VERSION 5.8 ;
BUSBITCHARS "[]" ;
DIVIDERCHAR "/" ;
UNITS
    DATABASE MICRONS 1000 ;
END UNITS

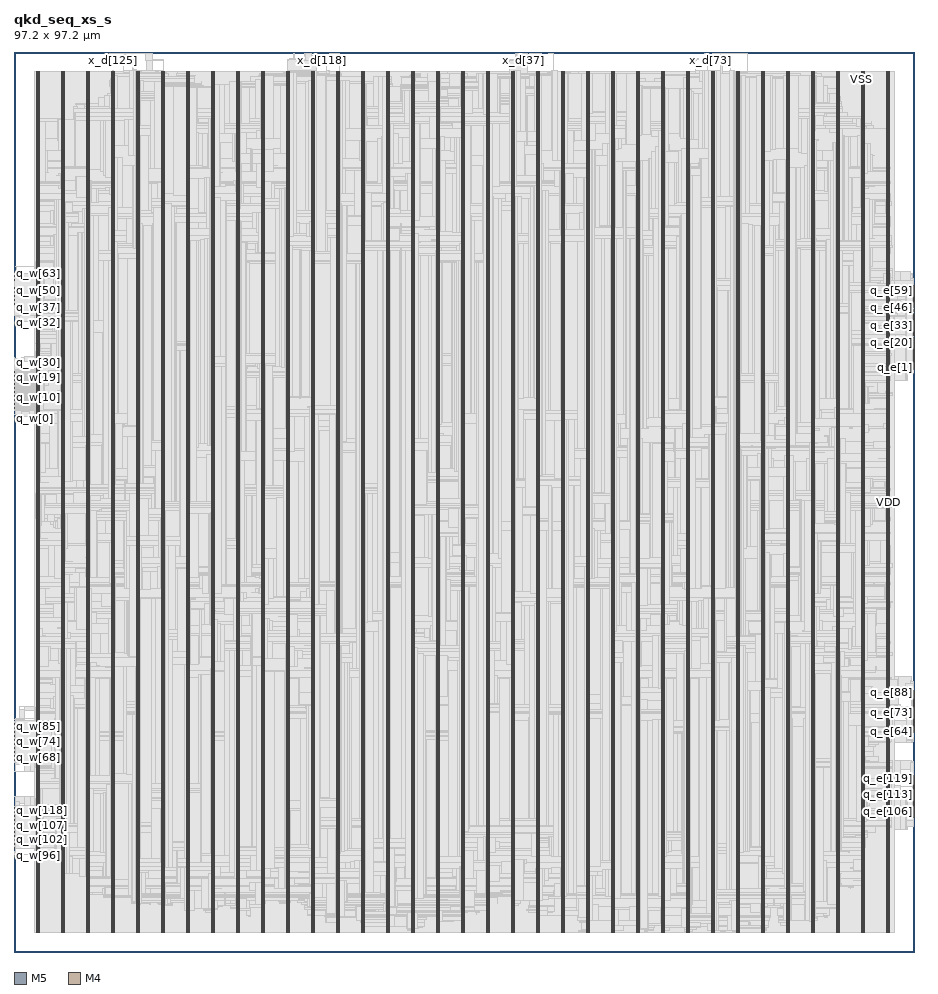
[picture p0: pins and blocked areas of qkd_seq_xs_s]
MACRO qkd_seq_xs_s
  FOREIGN qkd_seq_xs_s 0 0 ;
  CLASS BLOCK ;
  SIZE 97.2 BY 97.2 ;
  PIN ck
    DIRECTION INPUT ;
    USE SIGNAL ;
    PORT
      LAYER M5 ;
        RECT  11.232 97.116 11.256 97.2 ;
    END
  END ck
  PIN q_e[0]
    DIRECTION OUTPUT ;
    USE SIGNAL ;
    PORT
      LAYER M4 ;
        RECT  97.116 62.928 97.2 62.952 ;
    END
  END q_e[0]
  PIN q_e[100]
    DIRECTION OUTPUT ;
    USE SIGNAL ;
    PORT
      LAYER M4 ;
        RECT  97.116 15.12 97.2 15.144 ;
    END
  END q_e[100]
  PIN q_e[101]
    DIRECTION OUTPUT ;
    USE SIGNAL ;
    PORT
      LAYER M4 ;
        RECT  97.116 15.264 97.2 15.288 ;
    END
  END q_e[101]
  PIN q_e[102]
    DIRECTION OUTPUT ;
    USE SIGNAL ;
    PORT
      LAYER M4 ;
        RECT  97.116 15.408 97.2 15.432 ;
    END
  END q_e[102]
  PIN q_e[103]
    DIRECTION OUTPUT ;
    USE SIGNAL ;
    PORT
      LAYER M4 ;
        RECT  97.116 15.552 97.2 15.576 ;
    END
  END q_e[103]
  PIN q_e[104]
    DIRECTION OUTPUT ;
    USE SIGNAL ;
    PORT
      LAYER M4 ;
        RECT  97.116 15.696 97.2 15.72 ;
    END
  END q_e[104]
  PIN q_e[105]
    DIRECTION OUTPUT ;
    USE SIGNAL ;
    PORT
      LAYER M4 ;
        RECT  97.116 15.84 97.2 15.864 ;
    END
  END q_e[105]
  PIN q_e[106]
    DIRECTION OUTPUT ;
    USE SIGNAL ;
    PORT
      LAYER M4 ;
        RECT  97.116 15.984 97.2 16.008 ;
    END
  END q_e[106]
  PIN q_e[107]
    DIRECTION OUTPUT ;
    USE SIGNAL ;
    PORT
      LAYER M4 ;
        RECT  97.116 16.128 97.2 16.152 ;
    END
  END q_e[107]
  PIN q_e[108]
    DIRECTION OUTPUT ;
    USE SIGNAL ;
    PORT
      LAYER M4 ;
        RECT  97.116 16.272 97.2 16.296 ;
    END
  END q_e[108]
  PIN q_e[109]
    DIRECTION OUTPUT ;
    USE SIGNAL ;
    PORT
      LAYER M4 ;
        RECT  97.116 16.416 97.2 16.44 ;
    END
  END q_e[109]
  PIN q_e[10]
    DIRECTION OUTPUT ;
    USE SIGNAL ;
    PORT
      LAYER M4 ;
        RECT  97.116 64.368 97.2 64.392 ;
    END
  END q_e[10]
  PIN q_e[110]
    DIRECTION OUTPUT ;
    USE SIGNAL ;
    PORT
      LAYER M4 ;
        RECT  97.116 16.56 97.2 16.584 ;
    END
  END q_e[110]
  PIN q_e[111]
    DIRECTION OUTPUT ;
    USE SIGNAL ;
    PORT
      LAYER M4 ;
        RECT  97.116 16.704 97.2 16.728 ;
    END
  END q_e[111]
  PIN q_e[112]
    DIRECTION OUTPUT ;
    USE SIGNAL ;
    PORT
      LAYER M4 ;
        RECT  97.116 16.848 97.2 16.872 ;
    END
  END q_e[112]
  PIN q_e[113]
    DIRECTION OUTPUT ;
    USE SIGNAL ;
    PORT
      LAYER M4 ;
        RECT  97.116 16.992 97.2 17.016 ;
    END
  END q_e[113]
  PIN q_e[114]
    DIRECTION OUTPUT ;
    USE SIGNAL ;
    PORT
      LAYER M4 ;
        RECT  97.116 17.136 97.2 17.16 ;
    END
  END q_e[114]
  PIN q_e[115]
    DIRECTION OUTPUT ;
    USE SIGNAL ;
    PORT
      LAYER M4 ;
        RECT  97.116 17.28 97.2 17.304 ;
    END
  END q_e[115]
  PIN q_e[116]
    DIRECTION OUTPUT ;
    USE SIGNAL ;
    PORT
      LAYER M4 ;
        RECT  97.116 17.424 97.2 17.448 ;
    END
  END q_e[116]
  PIN q_e[117]
    DIRECTION OUTPUT ;
    USE SIGNAL ;
    PORT
      LAYER M4 ;
        RECT  97.116 17.568 97.2 17.592 ;
    END
  END q_e[117]
  PIN q_e[118]
    DIRECTION OUTPUT ;
    USE SIGNAL ;
    PORT
      LAYER M4 ;
        RECT  97.116 17.712 97.2 17.736 ;
    END
  END q_e[118]
  PIN q_e[119]
    DIRECTION OUTPUT ;
    USE SIGNAL ;
    PORT
      LAYER M4 ;
        RECT  97.116 17.856 97.2 17.88 ;
    END
  END q_e[119]
  PIN q_e[11]
    DIRECTION OUTPUT ;
    USE SIGNAL ;
    PORT
      LAYER M4 ;
        RECT  97.116 64.512 97.2 64.536 ;
    END
  END q_e[11]
  PIN q_e[120]
    DIRECTION OUTPUT ;
    USE SIGNAL ;
    PORT
      LAYER M4 ;
        RECT  97.116 18 97.2 18.024 ;
    END
  END q_e[120]
  PIN q_e[121]
    DIRECTION OUTPUT ;
    USE SIGNAL ;
    PORT
      LAYER M4 ;
        RECT  97.116 18.144 97.2 18.168 ;
    END
  END q_e[121]
  PIN q_e[122]
    DIRECTION OUTPUT ;
    USE SIGNAL ;
    PORT
      LAYER M4 ;
        RECT  97.116 18.288 97.2 18.312 ;
    END
  END q_e[122]
  PIN q_e[123]
    DIRECTION OUTPUT ;
    USE SIGNAL ;
    PORT
      LAYER M4 ;
        RECT  97.116 18.432 97.2 18.456 ;
    END
  END q_e[123]
  PIN q_e[124]
    DIRECTION OUTPUT ;
    USE SIGNAL ;
    PORT
      LAYER M4 ;
        RECT  97.116 18.576 97.2 18.6 ;
    END
  END q_e[124]
  PIN q_e[125]
    DIRECTION OUTPUT ;
    USE SIGNAL ;
    PORT
      LAYER M4 ;
        RECT  97.116 18.72 97.2 18.744 ;
    END
  END q_e[125]
  PIN q_e[126]
    DIRECTION OUTPUT ;
    USE SIGNAL ;
    PORT
      LAYER M4 ;
        RECT  97.116 18.864 97.2 18.888 ;
    END
  END q_e[126]
  PIN q_e[127]
    DIRECTION OUTPUT ;
    USE SIGNAL ;
    PORT
      LAYER M4 ;
        RECT  97.116 19.008 97.2 19.032 ;
    END
  END q_e[127]
  PIN q_e[12]
    DIRECTION OUTPUT ;
    USE SIGNAL ;
    PORT
      LAYER M4 ;
        RECT  97.116 64.656 97.2 64.68 ;
    END
  END q_e[12]
  PIN q_e[13]
    DIRECTION OUTPUT ;
    USE SIGNAL ;
    PORT
      LAYER M4 ;
        RECT  97.116 64.8 97.2 64.824 ;
    END
  END q_e[13]
  PIN q_e[14]
    DIRECTION OUTPUT ;
    USE SIGNAL ;
    PORT
      LAYER M4 ;
        RECT  97.116 64.944 97.2 64.968 ;
    END
  END q_e[14]
  PIN q_e[15]
    DIRECTION OUTPUT ;
    USE SIGNAL ;
    PORT
      LAYER M4 ;
        RECT  97.116 65.088 97.2 65.112 ;
    END
  END q_e[15]
  PIN q_e[16]
    DIRECTION OUTPUT ;
    USE SIGNAL ;
    PORT
      LAYER M4 ;
        RECT  97.116 65.232 97.2 65.256 ;
    END
  END q_e[16]
  PIN q_e[17]
    DIRECTION OUTPUT ;
    USE SIGNAL ;
    PORT
      LAYER M4 ;
        RECT  97.116 65.376 97.2 65.4 ;
    END
  END q_e[17]
  PIN q_e[18]
    DIRECTION OUTPUT ;
    USE SIGNAL ;
    PORT
      LAYER M4 ;
        RECT  97.116 65.52 97.2 65.544 ;
    END
  END q_e[18]
  PIN q_e[19]
    DIRECTION OUTPUT ;
    USE SIGNAL ;
    PORT
      LAYER M4 ;
        RECT  97.116 65.664 97.2 65.688 ;
    END
  END q_e[19]
  PIN q_e[1]
    DIRECTION OUTPUT ;
    USE SIGNAL ;
    PORT
      LAYER M4 ;
        RECT  97.116 63.072 97.2 63.096 ;
    END
  END q_e[1]
  PIN q_e[20]
    DIRECTION OUTPUT ;
    USE SIGNAL ;
    PORT
      LAYER M4 ;
        RECT  97.116 65.808 97.2 65.832 ;
    END
  END q_e[20]
  PIN q_e[21]
    DIRECTION OUTPUT ;
    USE SIGNAL ;
    PORT
      LAYER M4 ;
        RECT  97.116 65.952 97.2 65.976 ;
    END
  END q_e[21]
  PIN q_e[22]
    DIRECTION OUTPUT ;
    USE SIGNAL ;
    PORT
      LAYER M4 ;
        RECT  97.116 66.096 97.2 66.12 ;
    END
  END q_e[22]
  PIN q_e[23]
    DIRECTION OUTPUT ;
    USE SIGNAL ;
    PORT
      LAYER M4 ;
        RECT  97.116 66.24 97.2 66.264 ;
    END
  END q_e[23]
  PIN q_e[24]
    DIRECTION OUTPUT ;
    USE SIGNAL ;
    PORT
      LAYER M4 ;
        RECT  97.116 66.384 97.2 66.408 ;
    END
  END q_e[24]
  PIN q_e[25]
    DIRECTION OUTPUT ;
    USE SIGNAL ;
    PORT
      LAYER M4 ;
        RECT  97.116 66.528 97.2 66.552 ;
    END
  END q_e[25]
  PIN q_e[26]
    DIRECTION OUTPUT ;
    USE SIGNAL ;
    PORT
      LAYER M4 ;
        RECT  97.116 66.672 97.2 66.696 ;
    END
  END q_e[26]
  PIN q_e[27]
    DIRECTION OUTPUT ;
    USE SIGNAL ;
    PORT
      LAYER M4 ;
        RECT  97.116 66.816 97.2 66.84 ;
    END
  END q_e[27]
  PIN q_e[28]
    DIRECTION OUTPUT ;
    USE SIGNAL ;
    PORT
      LAYER M4 ;
        RECT  97.116 66.96 97.2 66.984 ;
    END
  END q_e[28]
  PIN q_e[29]
    DIRECTION OUTPUT ;
    USE SIGNAL ;
    PORT
      LAYER M4 ;
        RECT  97.116 67.104 97.2 67.128 ;
    END
  END q_e[29]
  PIN q_e[2]
    DIRECTION OUTPUT ;
    USE SIGNAL ;
    PORT
      LAYER M4 ;
        RECT  97.116 63.216 97.2 63.24 ;
    END
  END q_e[2]
  PIN q_e[30]
    DIRECTION OUTPUT ;
    USE SIGNAL ;
    PORT
      LAYER M4 ;
        RECT  97.116 67.248 97.2 67.272 ;
    END
  END q_e[30]
  PIN q_e[31]
    DIRECTION OUTPUT ;
    USE SIGNAL ;
    PORT
      LAYER M4 ;
        RECT  97.116 67.392 97.2 67.416 ;
    END
  END q_e[31]
  PIN q_e[32]
    DIRECTION OUTPUT ;
    USE SIGNAL ;
    PORT
      LAYER M4 ;
        RECT  97.116 67.536 97.2 67.56 ;
    END
  END q_e[32]
  PIN q_e[33]
    DIRECTION OUTPUT ;
    USE SIGNAL ;
    PORT
      LAYER M4 ;
        RECT  97.116 67.68 97.2 67.704 ;
    END
  END q_e[33]
  PIN q_e[34]
    DIRECTION OUTPUT ;
    USE SIGNAL ;
    PORT
      LAYER M4 ;
        RECT  97.116 67.824 97.2 67.848 ;
    END
  END q_e[34]
  PIN q_e[35]
    DIRECTION OUTPUT ;
    USE SIGNAL ;
    PORT
      LAYER M4 ;
        RECT  97.116 67.968 97.2 67.992 ;
    END
  END q_e[35]
  PIN q_e[36]
    DIRECTION OUTPUT ;
    USE SIGNAL ;
    PORT
      LAYER M4 ;
        RECT  97.116 68.112 97.2 68.136 ;
    END
  END q_e[36]
  PIN q_e[37]
    DIRECTION OUTPUT ;
    USE SIGNAL ;
    PORT
      LAYER M4 ;
        RECT  97.116 68.256 97.2 68.28 ;
    END
  END q_e[37]
  PIN q_e[38]
    DIRECTION OUTPUT ;
    USE SIGNAL ;
    PORT
      LAYER M4 ;
        RECT  97.116 68.4 97.2 68.424 ;
    END
  END q_e[38]
  PIN q_e[39]
    DIRECTION OUTPUT ;
    USE SIGNAL ;
    PORT
      LAYER M4 ;
        RECT  97.116 68.544 97.2 68.568 ;
    END
  END q_e[39]
  PIN q_e[3]
    DIRECTION OUTPUT ;
    USE SIGNAL ;
    PORT
      LAYER M4 ;
        RECT  97.116 63.36 97.2 63.384 ;
    END
  END q_e[3]
  PIN q_e[40]
    DIRECTION OUTPUT ;
    USE SIGNAL ;
    PORT
      LAYER M4 ;
        RECT  97.116 68.688 97.2 68.712 ;
    END
  END q_e[40]
  PIN q_e[41]
    DIRECTION OUTPUT ;
    USE SIGNAL ;
    PORT
      LAYER M4 ;
        RECT  97.116 68.832 97.2 68.856 ;
    END
  END q_e[41]
  PIN q_e[42]
    DIRECTION OUTPUT ;
    USE SIGNAL ;
    PORT
      LAYER M4 ;
        RECT  97.116 68.976 97.2 69 ;
    END
  END q_e[42]
  PIN q_e[43]
    DIRECTION OUTPUT ;
    USE SIGNAL ;
    PORT
      LAYER M4 ;
        RECT  97.116 69.12 97.2 69.144 ;
    END
  END q_e[43]
  PIN q_e[44]
    DIRECTION OUTPUT ;
    USE SIGNAL ;
    PORT
      LAYER M4 ;
        RECT  97.116 69.264 97.2 69.288 ;
    END
  END q_e[44]
  PIN q_e[45]
    DIRECTION OUTPUT ;
    USE SIGNAL ;
    PORT
      LAYER M4 ;
        RECT  97.116 69.408 97.2 69.432 ;
    END
  END q_e[45]
  PIN q_e[46]
    DIRECTION OUTPUT ;
    USE SIGNAL ;
    PORT
      LAYER M4 ;
        RECT  97.116 69.552 97.2 69.576 ;
    END
  END q_e[46]
  PIN q_e[47]
    DIRECTION OUTPUT ;
    USE SIGNAL ;
    PORT
      LAYER M4 ;
        RECT  97.116 69.696 97.2 69.72 ;
    END
  END q_e[47]
  PIN q_e[48]
    DIRECTION OUTPUT ;
    USE SIGNAL ;
    PORT
      LAYER M4 ;
        RECT  97.116 69.84 97.2 69.864 ;
    END
  END q_e[48]
  PIN q_e[49]
    DIRECTION OUTPUT ;
    USE SIGNAL ;
    PORT
      LAYER M4 ;
        RECT  97.116 69.984 97.2 70.008 ;
    END
  END q_e[49]
  PIN q_e[4]
    DIRECTION OUTPUT ;
    USE SIGNAL ;
    PORT
      LAYER M4 ;
        RECT  97.116 63.504 97.2 63.528 ;
    END
  END q_e[4]
  PIN q_e[50]
    DIRECTION OUTPUT ;
    USE SIGNAL ;
    PORT
      LAYER M4 ;
        RECT  97.116 70.128 97.2 70.152 ;
    END
  END q_e[50]
  PIN q_e[51]
    DIRECTION OUTPUT ;
    USE SIGNAL ;
    PORT
      LAYER M4 ;
        RECT  97.116 70.272 97.2 70.296 ;
    END
  END q_e[51]
  PIN q_e[52]
    DIRECTION OUTPUT ;
    USE SIGNAL ;
    PORT
      LAYER M4 ;
        RECT  97.116 70.416 97.2 70.44 ;
    END
  END q_e[52]
  PIN q_e[53]
    DIRECTION OUTPUT ;
    USE SIGNAL ;
    PORT
      LAYER M4 ;
        RECT  97.116 70.56 97.2 70.584 ;
    END
  END q_e[53]
  PIN q_e[54]
    DIRECTION OUTPUT ;
    USE SIGNAL ;
    PORT
      LAYER M4 ;
        RECT  97.116 70.704 97.2 70.728 ;
    END
  END q_e[54]
  PIN q_e[55]
    DIRECTION OUTPUT ;
    USE SIGNAL ;
    PORT
      LAYER M4 ;
        RECT  97.116 70.848 97.2 70.872 ;
    END
  END q_e[55]
  PIN q_e[56]
    DIRECTION OUTPUT ;
    USE SIGNAL ;
    PORT
      LAYER M4 ;
        RECT  97.116 70.992 97.2 71.016 ;
    END
  END q_e[56]
  PIN q_e[57]
    DIRECTION OUTPUT ;
    USE SIGNAL ;
    PORT
      LAYER M4 ;
        RECT  97.116 71.136 97.2 71.16 ;
    END
  END q_e[57]
  PIN q_e[58]
    DIRECTION OUTPUT ;
    USE SIGNAL ;
    PORT
      LAYER M4 ;
        RECT  97.116 71.28 97.2 71.304 ;
    END
  END q_e[58]
  PIN q_e[59]
    DIRECTION OUTPUT ;
    USE SIGNAL ;
    PORT
      LAYER M4 ;
        RECT  97.116 71.424 97.2 71.448 ;
    END
  END q_e[59]
  PIN q_e[5]
    DIRECTION OUTPUT ;
    USE SIGNAL ;
    PORT
      LAYER M4 ;
        RECT  97.116 63.648 97.2 63.672 ;
    END
  END q_e[5]
  PIN q_e[60]
    DIRECTION OUTPUT ;
    USE SIGNAL ;
    PORT
      LAYER M4 ;
        RECT  97.116 71.568 97.2 71.592 ;
    END
  END q_e[60]
  PIN q_e[61]
    DIRECTION OUTPUT ;
    USE SIGNAL ;
    PORT
      LAYER M4 ;
        RECT  97.116 71.712 97.2 71.736 ;
    END
  END q_e[61]
  PIN q_e[62]
    DIRECTION OUTPUT ;
    USE SIGNAL ;
    PORT
      LAYER M4 ;
        RECT  97.116 71.856 97.2 71.88 ;
    END
  END q_e[62]
  PIN q_e[63]
    DIRECTION OUTPUT ;
    USE SIGNAL ;
    PORT
      LAYER M4 ;
        RECT  97.116 72 97.2 72.024 ;
    END
  END q_e[63]
  PIN q_e[64]
    DIRECTION OUTPUT ;
    USE SIGNAL ;
    PORT
      LAYER M4 ;
        RECT  97.116 23.76 97.2 23.784 ;
    END
  END q_e[64]
  PIN q_e[65]
    DIRECTION OUTPUT ;
    USE SIGNAL ;
    PORT
      LAYER M4 ;
        RECT  97.116 23.904 97.2 23.928 ;
    END
  END q_e[65]
  PIN q_e[66]
    DIRECTION OUTPUT ;
    USE SIGNAL ;
    PORT
      LAYER M4 ;
        RECT  97.116 24.048 97.2 24.072 ;
    END
  END q_e[66]
  PIN q_e[67]
    DIRECTION OUTPUT ;
    USE SIGNAL ;
    PORT
      LAYER M4 ;
        RECT  97.116 24.192 97.2 24.216 ;
    END
  END q_e[67]
  PIN q_e[68]
    DIRECTION OUTPUT ;
    USE SIGNAL ;
    PORT
      LAYER M4 ;
        RECT  97.116 24.336 97.2 24.36 ;
    END
  END q_e[68]
  PIN q_e[69]
    DIRECTION OUTPUT ;
    USE SIGNAL ;
    PORT
      LAYER M4 ;
        RECT  97.116 24.48 97.2 24.504 ;
    END
  END q_e[69]
  PIN q_e[6]
    DIRECTION OUTPUT ;
    USE SIGNAL ;
    PORT
      LAYER M4 ;
        RECT  97.116 63.792 97.2 63.816 ;
    END
  END q_e[6]
  PIN q_e[70]
    DIRECTION OUTPUT ;
    USE SIGNAL ;
    PORT
      LAYER M4 ;
        RECT  97.116 24.624 97.2 24.648 ;
    END
  END q_e[70]
  PIN q_e[71]
    DIRECTION OUTPUT ;
    USE SIGNAL ;
    PORT
      LAYER M4 ;
        RECT  97.116 24.768 97.2 24.792 ;
    END
  END q_e[71]
  PIN q_e[72]
    DIRECTION OUTPUT ;
    USE SIGNAL ;
    PORT
      LAYER M4 ;
        RECT  97.116 24.912 97.2 24.936 ;
    END
  END q_e[72]
  PIN q_e[73]
    DIRECTION OUTPUT ;
    USE SIGNAL ;
    PORT
      LAYER M4 ;
        RECT  97.116 25.056 97.2 25.08 ;
    END
  END q_e[73]
  PIN q_e[74]
    DIRECTION OUTPUT ;
    USE SIGNAL ;
    PORT
      LAYER M4 ;
        RECT  97.116 25.2 97.2 25.224 ;
    END
  END q_e[74]
  PIN q_e[75]
    DIRECTION OUTPUT ;
    USE SIGNAL ;
    PORT
      LAYER M4 ;
        RECT  97.116 25.344 97.2 25.368 ;
    END
  END q_e[75]
  PIN q_e[76]
    DIRECTION OUTPUT ;
    USE SIGNAL ;
    PORT
      LAYER M4 ;
        RECT  97.116 25.488 97.2 25.512 ;
    END
  END q_e[76]
  PIN q_e[77]
    DIRECTION OUTPUT ;
    USE SIGNAL ;
    PORT
      LAYER M4 ;
        RECT  97.116 25.632 97.2 25.656 ;
    END
  END q_e[77]
  PIN q_e[78]
    DIRECTION OUTPUT ;
    USE SIGNAL ;
    PORT
      LAYER M4 ;
        RECT  97.116 25.776 97.2 25.8 ;
    END
  END q_e[78]
  PIN q_e[79]
    DIRECTION OUTPUT ;
    USE SIGNAL ;
    PORT
      LAYER M4 ;
        RECT  97.116 25.92 97.2 25.944 ;
    END
  END q_e[79]
  PIN q_e[7]
    DIRECTION OUTPUT ;
    USE SIGNAL ;
    PORT
      LAYER M4 ;
        RECT  97.116 63.936 97.2 63.96 ;
    END
  END q_e[7]
  PIN q_e[80]
    DIRECTION OUTPUT ;
    USE SIGNAL ;
    PORT
      LAYER M4 ;
        RECT  97.116 26.064 97.2 26.088 ;
    END
  END q_e[80]
  PIN q_e[81]
    DIRECTION OUTPUT ;
    USE SIGNAL ;
    PORT
      LAYER M4 ;
        RECT  97.116 26.208 97.2 26.232 ;
    END
  END q_e[81]
  PIN q_e[82]
    DIRECTION OUTPUT ;
    USE SIGNAL ;
    PORT
      LAYER M4 ;
        RECT  97.116 26.352 97.2 26.376 ;
    END
  END q_e[82]
  PIN q_e[83]
    DIRECTION OUTPUT ;
    USE SIGNAL ;
    PORT
      LAYER M4 ;
        RECT  97.116 26.496 97.2 26.52 ;
    END
  END q_e[83]
  PIN q_e[84]
    DIRECTION OUTPUT ;
    USE SIGNAL ;
    PORT
      LAYER M4 ;
        RECT  97.116 26.64 97.2 26.664 ;
    END
  END q_e[84]
  PIN q_e[85]
    DIRECTION OUTPUT ;
    USE SIGNAL ;
    PORT
      LAYER M4 ;
        RECT  97.116 26.784 97.2 26.808 ;
    END
  END q_e[85]
  PIN q_e[86]
    DIRECTION OUTPUT ;
    USE SIGNAL ;
    PORT
      LAYER M4 ;
        RECT  97.116 26.928 97.2 26.952 ;
    END
  END q_e[86]
  PIN q_e[87]
    DIRECTION OUTPUT ;
    USE SIGNAL ;
    PORT
      LAYER M4 ;
        RECT  97.116 27.072 97.2 27.096 ;
    END
  END q_e[87]
  PIN q_e[88]
    DIRECTION OUTPUT ;
    USE SIGNAL ;
    PORT
      LAYER M4 ;
        RECT  97.116 27.216 97.2 27.24 ;
    END
  END q_e[88]
  PIN q_e[89]
    DIRECTION OUTPUT ;
    USE SIGNAL ;
    PORT
      LAYER M4 ;
        RECT  97.116 27.36 97.2 27.384 ;
    END
  END q_e[89]
  PIN q_e[8]
    DIRECTION OUTPUT ;
    USE SIGNAL ;
    PORT
      LAYER M4 ;
        RECT  97.116 64.08 97.2 64.104 ;
    END
  END q_e[8]
  PIN q_e[90]
    DIRECTION OUTPUT ;
    USE SIGNAL ;
    PORT
      LAYER M4 ;
        RECT  97.116 27.504 97.2 27.528 ;
    END
  END q_e[90]
  PIN q_e[91]
    DIRECTION OUTPUT ;
    USE SIGNAL ;
    PORT
      LAYER M4 ;
        RECT  97.116 27.648 97.2 27.672 ;
    END
  END q_e[91]
  PIN q_e[92]
    DIRECTION OUTPUT ;
    USE SIGNAL ;
    PORT
      LAYER M4 ;
        RECT  97.116 27.792 97.2 27.816 ;
    END
  END q_e[92]
  PIN q_e[93]
    DIRECTION OUTPUT ;
    USE SIGNAL ;
    PORT
      LAYER M4 ;
        RECT  97.116 27.936 97.2 27.96 ;
    END
  END q_e[93]
  PIN q_e[94]
    DIRECTION OUTPUT ;
    USE SIGNAL ;
    PORT
      LAYER M4 ;
        RECT  97.116 28.08 97.2 28.104 ;
    END
  END q_e[94]
  PIN q_e[95]
    DIRECTION OUTPUT ;
    USE SIGNAL ;
    PORT
      LAYER M4 ;
        RECT  97.116 28.224 97.2 28.248 ;
    END
  END q_e[95]
  PIN q_e[96]
    DIRECTION OUTPUT ;
    USE SIGNAL ;
    PORT
      LAYER M4 ;
        RECT  97.116 14.544 97.2 14.568 ;
    END
  END q_e[96]
  PIN q_e[97]
    DIRECTION OUTPUT ;
    USE SIGNAL ;
    PORT
      LAYER M4 ;
        RECT  97.116 14.688 97.2 14.712 ;
    END
  END q_e[97]
  PIN q_e[98]
    DIRECTION OUTPUT ;
    USE SIGNAL ;
    PORT
      LAYER M4 ;
        RECT  97.116 14.832 97.2 14.856 ;
    END
  END q_e[98]
  PIN q_e[99]
    DIRECTION OUTPUT ;
    USE SIGNAL ;
    PORT
      LAYER M4 ;
        RECT  97.116 14.976 97.2 15 ;
    END
  END q_e[99]
  PIN q_e[9]
    DIRECTION OUTPUT ;
    USE SIGNAL ;
    PORT
      LAYER M4 ;
        RECT  97.116 64.224 97.2 64.248 ;
    END
  END q_e[9]
  PIN q_w[0]
    DIRECTION OUTPUT ;
    USE SIGNAL ;
    PORT
      LAYER M4 ;
        RECT  0 58.464 0.084 58.488 ;
    END
  END q_w[0]
  PIN q_w[100]
    DIRECTION OUTPUT ;
    USE SIGNAL ;
    PORT
      LAYER M4 ;
        RECT  0 11.808 0.084 11.832 ;
    END
  END q_w[100]
  PIN q_w[101]
    DIRECTION OUTPUT ;
    USE SIGNAL ;
    PORT
      LAYER M4 ;
        RECT  0 11.952 0.084 11.976 ;
    END
  END q_w[101]
  PIN q_w[102]
    DIRECTION OUTPUT ;
    USE SIGNAL ;
    PORT
      LAYER M4 ;
        RECT  0 12.096 0.084 12.12 ;
    END
  END q_w[102]
  PIN q_w[103]
    DIRECTION OUTPUT ;
    USE SIGNAL ;
    PORT
      LAYER M4 ;
        RECT  0 12.24 0.084 12.264 ;
    END
  END q_w[103]
  PIN q_w[104]
    DIRECTION OUTPUT ;
    USE SIGNAL ;
    PORT
      LAYER M4 ;
        RECT  0 12.384 0.084 12.408 ;
    END
  END q_w[104]
  PIN q_w[105]
    DIRECTION OUTPUT ;
    USE SIGNAL ;
    PORT
      LAYER M4 ;
        RECT  0 12.528 0.084 12.552 ;
    END
  END q_w[105]
  PIN q_w[106]
    DIRECTION OUTPUT ;
    USE SIGNAL ;
    PORT
      LAYER M4 ;
        RECT  0 12.672 0.084 12.696 ;
    END
  END q_w[106]
  PIN q_w[107]
    DIRECTION OUTPUT ;
    USE SIGNAL ;
    PORT
      LAYER M4 ;
        RECT  0 12.816 0.084 12.84 ;
    END
  END q_w[107]
  PIN q_w[108]
    DIRECTION OUTPUT ;
    USE SIGNAL ;
    PORT
      LAYER M4 ;
        RECT  0 12.96 0.084 12.984 ;
    END
  END q_w[108]
  PIN q_w[109]
    DIRECTION OUTPUT ;
    USE SIGNAL ;
    PORT
      LAYER M4 ;
        RECT  0 13.104 0.084 13.128 ;
    END
  END q_w[109]
  PIN q_w[10]
    DIRECTION OUTPUT ;
    USE SIGNAL ;
    PORT
      LAYER M4 ;
        RECT  0 59.904 0.084 59.928 ;
    END
  END q_w[10]
  PIN q_w[110]
    DIRECTION OUTPUT ;
    USE SIGNAL ;
    PORT
      LAYER M4 ;
        RECT  0 13.248 0.084 13.272 ;
    END
  END q_w[110]
  PIN q_w[111]
    DIRECTION OUTPUT ;
    USE SIGNAL ;
    PORT
      LAYER M4 ;
        RECT  0 13.392 0.084 13.416 ;
    END
  END q_w[111]
  PIN q_w[112]
    DIRECTION OUTPUT ;
    USE SIGNAL ;
    PORT
      LAYER M4 ;
        RECT  0 13.536 0.084 13.56 ;
    END
  END q_w[112]
  PIN q_w[113]
    DIRECTION OUTPUT ;
    USE SIGNAL ;
    PORT
      LAYER M4 ;
        RECT  0 13.68 0.084 13.704 ;
    END
  END q_w[113]
  PIN q_w[114]
    DIRECTION OUTPUT ;
    USE SIGNAL ;
    PORT
      LAYER M4 ;
        RECT  0 13.824 0.084 13.848 ;
    END
  END q_w[114]
  PIN q_w[115]
    DIRECTION OUTPUT ;
    USE SIGNAL ;
    PORT
      LAYER M4 ;
        RECT  0 13.968 0.084 13.992 ;
    END
  END q_w[115]
  PIN q_w[116]
    DIRECTION OUTPUT ;
    USE SIGNAL ;
    PORT
      LAYER M4 ;
        RECT  0 14.112 0.084 14.136 ;
    END
  END q_w[116]
  PIN q_w[117]
    DIRECTION OUTPUT ;
    USE SIGNAL ;
    PORT
      LAYER M4 ;
        RECT  0 14.256 0.084 14.28 ;
    END
  END q_w[117]
  PIN q_w[118]
    DIRECTION OUTPUT ;
    USE SIGNAL ;
    PORT
      LAYER M4 ;
        RECT  0 14.4 0.084 14.424 ;
    END
  END q_w[118]
  PIN q_w[119]
    DIRECTION OUTPUT ;
    USE SIGNAL ;
    PORT
      LAYER M4 ;
        RECT  0 14.544 0.084 14.568 ;
    END
  END q_w[119]
  PIN q_w[11]
    DIRECTION OUTPUT ;
    USE SIGNAL ;
    PORT
      LAYER M4 ;
        RECT  0 60.048 0.084 60.072 ;
    END
  END q_w[11]
  PIN q_w[120]
    DIRECTION OUTPUT ;
    USE SIGNAL ;
    PORT
      LAYER M4 ;
        RECT  0 14.688 0.084 14.712 ;
    END
  END q_w[120]
  PIN q_w[121]
    DIRECTION OUTPUT ;
    USE SIGNAL ;
    PORT
      LAYER M4 ;
        RECT  0 14.832 0.084 14.856 ;
    END
  END q_w[121]
  PIN q_w[122]
    DIRECTION OUTPUT ;
    USE SIGNAL ;
    PORT
      LAYER M4 ;
        RECT  0 14.976 0.084 15 ;
    END
  END q_w[122]
  PIN q_w[123]
    DIRECTION OUTPUT ;
    USE SIGNAL ;
    PORT
      LAYER M4 ;
        RECT  0 15.12 0.084 15.144 ;
    END
  END q_w[123]
  PIN q_w[124]
    DIRECTION OUTPUT ;
    USE SIGNAL ;
    PORT
      LAYER M4 ;
        RECT  0 15.264 0.084 15.288 ;
    END
  END q_w[124]
  PIN q_w[125]
    DIRECTION OUTPUT ;
    USE SIGNAL ;
    PORT
      LAYER M4 ;
        RECT  0 15.408 0.084 15.432 ;
    END
  END q_w[125]
  PIN q_w[126]
    DIRECTION OUTPUT ;
    USE SIGNAL ;
    PORT
      LAYER M4 ;
        RECT  0 15.552 0.084 15.576 ;
    END
  END q_w[126]
  PIN q_w[127]
    DIRECTION OUTPUT ;
    USE SIGNAL ;
    PORT
      LAYER M4 ;
        RECT  0 15.696 0.084 15.72 ;
    END
  END q_w[127]
  PIN q_w[12]
    DIRECTION OUTPUT ;
    USE SIGNAL ;
    PORT
      LAYER M4 ;
        RECT  0 60.192 0.084 60.216 ;
    END
  END q_w[12]
  PIN q_w[13]
    DIRECTION OUTPUT ;
    USE SIGNAL ;
    PORT
      LAYER M4 ;
        RECT  0 60.336 0.084 60.36 ;
    END
  END q_w[13]
  PIN q_w[14]
    DIRECTION OUTPUT ;
    USE SIGNAL ;
    PORT
      LAYER M4 ;
        RECT  0 60.48 0.084 60.504 ;
    END
  END q_w[14]
  PIN q_w[15]
    DIRECTION OUTPUT ;
    USE SIGNAL ;
    PORT
      LAYER M4 ;
        RECT  0 60.624 0.084 60.648 ;
    END
  END q_w[15]
  PIN q_w[16]
    DIRECTION OUTPUT ;
    USE SIGNAL ;
    PORT
      LAYER M4 ;
        RECT  0 60.768 0.084 60.792 ;
    END
  END q_w[16]
  PIN q_w[17]
    DIRECTION OUTPUT ;
    USE SIGNAL ;
    PORT
      LAYER M4 ;
        RECT  0 60.912 0.084 60.936 ;
    END
  END q_w[17]
  PIN q_w[18]
    DIRECTION OUTPUT ;
    USE SIGNAL ;
    PORT
      LAYER M4 ;
        RECT  0 61.056 0.084 61.08 ;
    END
  END q_w[18]
  PIN q_w[19]
    DIRECTION OUTPUT ;
    USE SIGNAL ;
    PORT
      LAYER M4 ;
        RECT  0 61.2 0.084 61.224 ;
    END
  END q_w[19]
  PIN q_w[1]
    DIRECTION OUTPUT ;
    USE SIGNAL ;
    PORT
      LAYER M4 ;
        RECT  0 58.608 0.084 58.632 ;
    END
  END q_w[1]
  PIN q_w[20]
    DIRECTION OUTPUT ;
    USE SIGNAL ;
    PORT
      LAYER M4 ;
        RECT  0 61.344 0.084 61.368 ;
    END
  END q_w[20]
  PIN q_w[21]
    DIRECTION OUTPUT ;
    USE SIGNAL ;
    PORT
      LAYER M4 ;
        RECT  0 61.488 0.084 61.512 ;
    END
  END q_w[21]
  PIN q_w[22]
    DIRECTION OUTPUT ;
    USE SIGNAL ;
    PORT
      LAYER M4 ;
        RECT  0 61.632 0.084 61.656 ;
    END
  END q_w[22]
  PIN q_w[23]
    DIRECTION OUTPUT ;
    USE SIGNAL ;
    PORT
      LAYER M4 ;
        RECT  0 61.776 0.084 61.8 ;
    END
  END q_w[23]
  PIN q_w[24]
    DIRECTION OUTPUT ;
    USE SIGNAL ;
    PORT
      LAYER M4 ;
        RECT  0 61.92 0.084 61.944 ;
    END
  END q_w[24]
  PIN q_w[25]
    DIRECTION OUTPUT ;
    USE SIGNAL ;
    PORT
      LAYER M4 ;
        RECT  0 62.064 0.084 62.088 ;
    END
  END q_w[25]
  PIN q_w[26]
    DIRECTION OUTPUT ;
    USE SIGNAL ;
    PORT
      LAYER M4 ;
        RECT  0 62.208 0.084 62.232 ;
    END
  END q_w[26]
  PIN q_w[27]
    DIRECTION OUTPUT ;
    USE SIGNAL ;
    PORT
      LAYER M4 ;
        RECT  0 62.352 0.084 62.376 ;
    END
  END q_w[27]
  PIN q_w[28]
    DIRECTION OUTPUT ;
    USE SIGNAL ;
    PORT
      LAYER M4 ;
        RECT  0 62.496 0.084 62.52 ;
    END
  END q_w[28]
  PIN q_w[29]
    DIRECTION OUTPUT ;
    USE SIGNAL ;
    PORT
      LAYER M4 ;
        RECT  0 62.64 0.084 62.664 ;
    END
  END q_w[29]
  PIN q_w[2]
    DIRECTION OUTPUT ;
    USE SIGNAL ;
    PORT
      LAYER M4 ;
        RECT  0 58.752 0.084 58.776 ;
    END
  END q_w[2]
  PIN q_w[30]
    DIRECTION OUTPUT ;
    USE SIGNAL ;
    PORT
      LAYER M4 ;
        RECT  0 62.784 0.084 62.808 ;
    END
  END q_w[30]
  PIN q_w[31]
    DIRECTION OUTPUT ;
    USE SIGNAL ;
    PORT
      LAYER M4 ;
        RECT  0 62.928 0.084 62.952 ;
    END
  END q_w[31]
  PIN q_w[32]
    DIRECTION OUTPUT ;
    USE SIGNAL ;
    PORT
      LAYER M4 ;
        RECT  0 68.832 0.084 68.856 ;
    END
  END q_w[32]
  PIN q_w[33]
    DIRECTION OUTPUT ;
    USE SIGNAL ;
    PORT
      LAYER M4 ;
        RECT  0 68.976 0.084 69 ;
    END
  END q_w[33]
  PIN q_w[34]
    DIRECTION OUTPUT ;
    USE SIGNAL ;
    PORT
      LAYER M4 ;
        RECT  0 69.12 0.084 69.144 ;
    END
  END q_w[34]
  PIN q_w[35]
    DIRECTION OUTPUT ;
    USE SIGNAL ;
    PORT
      LAYER M4 ;
        RECT  0 69.264 0.084 69.288 ;
    END
  END q_w[35]
  PIN q_w[36]
    DIRECTION OUTPUT ;
    USE SIGNAL ;
    PORT
      LAYER M4 ;
        RECT  0 69.408 0.084 69.432 ;
    END
  END q_w[36]
  PIN q_w[37]
    DIRECTION OUTPUT ;
    USE SIGNAL ;
    PORT
      LAYER M4 ;
        RECT  0 69.552 0.084 69.576 ;
    END
  END q_w[37]
  PIN q_w[38]
    DIRECTION OUTPUT ;
    USE SIGNAL ;
    PORT
      LAYER M4 ;
        RECT  0 69.696 0.084 69.72 ;
    END
  END q_w[38]
  PIN q_w[39]
    DIRECTION OUTPUT ;
    USE SIGNAL ;
    PORT
      LAYER M4 ;
        RECT  0 69.84 0.084 69.864 ;
    END
  END q_w[39]
  PIN q_w[3]
    DIRECTION OUTPUT ;
    USE SIGNAL ;
    PORT
      LAYER M4 ;
        RECT  0 58.896 0.084 58.92 ;
    END
  END q_w[3]
  PIN q_w[40]
    DIRECTION OUTPUT ;
    USE SIGNAL ;
    PORT
      LAYER M4 ;
        RECT  0 69.984 0.084 70.008 ;
    END
  END q_w[40]
  PIN q_w[41]
    DIRECTION OUTPUT ;
    USE SIGNAL ;
    PORT
      LAYER M4 ;
        RECT  0 70.128 0.084 70.152 ;
    END
  END q_w[41]
  PIN q_w[42]
    DIRECTION OUTPUT ;
    USE SIGNAL ;
    PORT
      LAYER M4 ;
        RECT  0 70.272 0.084 70.296 ;
    END
  END q_w[42]
  PIN q_w[43]
    DIRECTION OUTPUT ;
    USE SIGNAL ;
    PORT
      LAYER M4 ;
        RECT  0 70.416 0.084 70.44 ;
    END
  END q_w[43]
  PIN q_w[44]
    DIRECTION OUTPUT ;
    USE SIGNAL ;
    PORT
      LAYER M4 ;
        RECT  0 70.56 0.084 70.584 ;
    END
  END q_w[44]
  PIN q_w[45]
    DIRECTION OUTPUT ;
    USE SIGNAL ;
    PORT
      LAYER M4 ;
        RECT  0 70.704 0.084 70.728 ;
    END
  END q_w[45]
  PIN q_w[46]
    DIRECTION OUTPUT ;
    USE SIGNAL ;
    PORT
      LAYER M4 ;
        RECT  0 70.848 0.084 70.872 ;
    END
  END q_w[46]
  PIN q_w[47]
    DIRECTION OUTPUT ;
    USE SIGNAL ;
    PORT
      LAYER M4 ;
        RECT  0 70.992 0.084 71.016 ;
    END
  END q_w[47]
  PIN q_w[48]
    DIRECTION OUTPUT ;
    USE SIGNAL ;
    PORT
      LAYER M4 ;
        RECT  0 71.136 0.084 71.16 ;
    END
  END q_w[48]
  PIN q_w[49]
    DIRECTION OUTPUT ;
    USE SIGNAL ;
    PORT
      LAYER M4 ;
        RECT  0 71.28 0.084 71.304 ;
    END
  END q_w[49]
  PIN q_w[4]
    DIRECTION OUTPUT ;
    USE SIGNAL ;
    PORT
      LAYER M4 ;
        RECT  0 59.04 0.084 59.064 ;
    END
  END q_w[4]
  PIN q_w[50]
    DIRECTION OUTPUT ;
    USE SIGNAL ;
    PORT
      LAYER M4 ;
        RECT  0 71.424 0.084 71.448 ;
    END
  END q_w[50]
  PIN q_w[51]
    DIRECTION OUTPUT ;
    USE SIGNAL ;
    PORT
      LAYER M4 ;
        RECT  0 71.568 0.084 71.592 ;
    END
  END q_w[51]
  PIN q_w[52]
    DIRECTION OUTPUT ;
    USE SIGNAL ;
    PORT
      LAYER M4 ;
        RECT  0 71.712 0.084 71.736 ;
    END
  END q_w[52]
  PIN q_w[53]
    DIRECTION OUTPUT ;
    USE SIGNAL ;
    PORT
      LAYER M4 ;
        RECT  0 71.856 0.084 71.88 ;
    END
  END q_w[53]
  PIN q_w[54]
    DIRECTION OUTPUT ;
    USE SIGNAL ;
    PORT
      LAYER M4 ;
        RECT  0 72 0.084 72.024 ;
    END
  END q_w[54]
  PIN q_w[55]
    DIRECTION OUTPUT ;
    USE SIGNAL ;
    PORT
      LAYER M4 ;
        RECT  0 72.144 0.084 72.168 ;
    END
  END q_w[55]
  PIN q_w[56]
    DIRECTION OUTPUT ;
    USE SIGNAL ;
    PORT
      LAYER M4 ;
        RECT  0 72.288 0.084 72.312 ;
    END
  END q_w[56]
  PIN q_w[57]
    DIRECTION OUTPUT ;
    USE SIGNAL ;
    PORT
      LAYER M4 ;
        RECT  0 72.432 0.084 72.456 ;
    END
  END q_w[57]
  PIN q_w[58]
    DIRECTION OUTPUT ;
    USE SIGNAL ;
    PORT
      LAYER M4 ;
        RECT  0 72.576 0.084 72.6 ;
    END
  END q_w[58]
  PIN q_w[59]
    DIRECTION OUTPUT ;
    USE SIGNAL ;
    PORT
      LAYER M4 ;
        RECT  0 72.72 0.084 72.744 ;
    END
  END q_w[59]
  PIN q_w[5]
    DIRECTION OUTPUT ;
    USE SIGNAL ;
    PORT
      LAYER M4 ;
        RECT  0 59.184 0.084 59.208 ;
    END
  END q_w[5]
  PIN q_w[60]
    DIRECTION OUTPUT ;
    USE SIGNAL ;
    PORT
      LAYER M4 ;
        RECT  0 72.864 0.084 72.888 ;
    END
  END q_w[60]
  PIN q_w[61]
    DIRECTION OUTPUT ;
    USE SIGNAL ;
    PORT
      LAYER M4 ;
        RECT  0 73.008 0.084 73.032 ;
    END
  END q_w[61]
  PIN q_w[62]
    DIRECTION OUTPUT ;
    USE SIGNAL ;
    PORT
      LAYER M4 ;
        RECT  0 73.152 0.084 73.176 ;
    END
  END q_w[62]
  PIN q_w[63]
    DIRECTION OUTPUT ;
    USE SIGNAL ;
    PORT
      LAYER M4 ;
        RECT  0 73.296 0.084 73.32 ;
    END
  END q_w[63]
  PIN q_w[64]
    DIRECTION OUTPUT ;
    USE SIGNAL ;
    PORT
      LAYER M4 ;
        RECT  0 20.448 0.084 20.472 ;
    END
  END q_w[64]
  PIN q_w[65]
    DIRECTION OUTPUT ;
    USE SIGNAL ;
    PORT
      LAYER M4 ;
        RECT  0 20.592 0.084 20.616 ;
    END
  END q_w[65]
  PIN q_w[66]
    DIRECTION OUTPUT ;
    USE SIGNAL ;
    PORT
      LAYER M4 ;
        RECT  0 20.736 0.084 20.76 ;
    END
  END q_w[66]
  PIN q_w[67]
    DIRECTION OUTPUT ;
    USE SIGNAL ;
    PORT
      LAYER M4 ;
        RECT  0 20.88 0.084 20.904 ;
    END
  END q_w[67]
  PIN q_w[68]
    DIRECTION OUTPUT ;
    USE SIGNAL ;
    PORT
      LAYER M4 ;
        RECT  0 21.024 0.084 21.048 ;
    END
  END q_w[68]
  PIN q_w[69]
    DIRECTION OUTPUT ;
    USE SIGNAL ;
    PORT
      LAYER M4 ;
        RECT  0 21.168 0.084 21.192 ;
    END
  END q_w[69]
  PIN q_w[6]
    DIRECTION OUTPUT ;
    USE SIGNAL ;
    PORT
      LAYER M4 ;
        RECT  0 59.328 0.084 59.352 ;
    END
  END q_w[6]
  PIN q_w[70]
    DIRECTION OUTPUT ;
    USE SIGNAL ;
    PORT
      LAYER M4 ;
        RECT  0 21.312 0.084 21.336 ;
    END
  END q_w[70]
  PIN q_w[71]
    DIRECTION OUTPUT ;
    USE SIGNAL ;
    PORT
      LAYER M4 ;
        RECT  0 21.456 0.084 21.48 ;
    END
  END q_w[71]
  PIN q_w[72]
    DIRECTION OUTPUT ;
    USE SIGNAL ;
    PORT
      LAYER M4 ;
        RECT  0 21.6 0.084 21.624 ;
    END
  END q_w[72]
  PIN q_w[73]
    DIRECTION OUTPUT ;
    USE SIGNAL ;
    PORT
      LAYER M4 ;
        RECT  0 21.744 0.084 21.768 ;
    END
  END q_w[73]
  PIN q_w[74]
    DIRECTION OUTPUT ;
    USE SIGNAL ;
    PORT
      LAYER M4 ;
        RECT  0 21.888 0.084 21.912 ;
    END
  END q_w[74]
  PIN q_w[75]
    DIRECTION OUTPUT ;
    USE SIGNAL ;
    PORT
      LAYER M4 ;
        RECT  0 22.032 0.084 22.056 ;
    END
  END q_w[75]
  PIN q_w[76]
    DIRECTION OUTPUT ;
    USE SIGNAL ;
    PORT
      LAYER M4 ;
        RECT  0 22.176 0.084 22.2 ;
    END
  END q_w[76]
  PIN q_w[77]
    DIRECTION OUTPUT ;
    USE SIGNAL ;
    PORT
      LAYER M4 ;
        RECT  0 22.32 0.084 22.344 ;
    END
  END q_w[77]
  PIN q_w[78]
    DIRECTION OUTPUT ;
    USE SIGNAL ;
    PORT
      LAYER M4 ;
        RECT  0 22.464 0.084 22.488 ;
    END
  END q_w[78]
  PIN q_w[79]
    DIRECTION OUTPUT ;
    USE SIGNAL ;
    PORT
      LAYER M4 ;
        RECT  0 22.608 0.084 22.632 ;
    END
  END q_w[79]
  PIN q_w[7]
    DIRECTION OUTPUT ;
    USE SIGNAL ;
    PORT
      LAYER M4 ;
        RECT  0 59.472 0.084 59.496 ;
    END
  END q_w[7]
  PIN q_w[80]
    DIRECTION OUTPUT ;
    USE SIGNAL ;
    PORT
      LAYER M4 ;
        RECT  0 22.752 0.084 22.776 ;
    END
  END q_w[80]
  PIN q_w[81]
    DIRECTION OUTPUT ;
    USE SIGNAL ;
    PORT
      LAYER M4 ;
        RECT  0 22.896 0.084 22.92 ;
    END
  END q_w[81]
  PIN q_w[82]
    DIRECTION OUTPUT ;
    USE SIGNAL ;
    PORT
      LAYER M4 ;
        RECT  0 23.04 0.084 23.064 ;
    END
  END q_w[82]
  PIN q_w[83]
    DIRECTION OUTPUT ;
    USE SIGNAL ;
    PORT
      LAYER M4 ;
        RECT  0 23.184 0.084 23.208 ;
    END
  END q_w[83]
  PIN q_w[84]
    DIRECTION OUTPUT ;
    USE SIGNAL ;
    PORT
      LAYER M4 ;
        RECT  0 23.328 0.084 23.352 ;
    END
  END q_w[84]
  PIN q_w[85]
    DIRECTION OUTPUT ;
    USE SIGNAL ;
    PORT
      LAYER M4 ;
        RECT  0 23.472 0.084 23.496 ;
    END
  END q_w[85]
  PIN q_w[86]
    DIRECTION OUTPUT ;
    USE SIGNAL ;
    PORT
      LAYER M4 ;
        RECT  0 23.616 0.084 23.64 ;
    END
  END q_w[86]
  PIN q_w[87]
    DIRECTION OUTPUT ;
    USE SIGNAL ;
    PORT
      LAYER M4 ;
        RECT  0 23.76 0.084 23.784 ;
    END
  END q_w[87]
  PIN q_w[88]
    DIRECTION OUTPUT ;
    USE SIGNAL ;
    PORT
      LAYER M4 ;
        RECT  0 23.904 0.084 23.928 ;
    END
  END q_w[88]
  PIN q_w[89]
    DIRECTION OUTPUT ;
    USE SIGNAL ;
    PORT
      LAYER M4 ;
        RECT  0 24.048 0.084 24.072 ;
    END
  END q_w[89]
  PIN q_w[8]
    DIRECTION OUTPUT ;
    USE SIGNAL ;
    PORT
      LAYER M4 ;
        RECT  0 59.616 0.084 59.64 ;
    END
  END q_w[8]
  PIN q_w[90]
    DIRECTION OUTPUT ;
    USE SIGNAL ;
    PORT
      LAYER M4 ;
        RECT  0 24.192 0.084 24.216 ;
    END
  END q_w[90]
  PIN q_w[91]
    DIRECTION OUTPUT ;
    USE SIGNAL ;
    PORT
      LAYER M4 ;
        RECT  0 24.336 0.084 24.36 ;
    END
  END q_w[91]
  PIN q_w[92]
    DIRECTION OUTPUT ;
    USE SIGNAL ;
    PORT
      LAYER M4 ;
        RECT  0 24.48 0.084 24.504 ;
    END
  END q_w[92]
  PIN q_w[93]
    DIRECTION OUTPUT ;
    USE SIGNAL ;
    PORT
      LAYER M4 ;
        RECT  0 24.624 0.084 24.648 ;
    END
  END q_w[93]
  PIN q_w[94]
    DIRECTION OUTPUT ;
    USE SIGNAL ;
    PORT
      LAYER M4 ;
        RECT  0 24.768 0.084 24.792 ;
    END
  END q_w[94]
  PIN q_w[95]
    DIRECTION OUTPUT ;
    USE SIGNAL ;
    PORT
      LAYER M4 ;
        RECT  0 24.912 0.084 24.936 ;
    END
  END q_w[95]
  PIN q_w[96]
    DIRECTION OUTPUT ;
    USE SIGNAL ;
    PORT
      LAYER M4 ;
        RECT  0 11.232 0.084 11.256 ;
    END
  END q_w[96]
  PIN q_w[97]
    DIRECTION OUTPUT ;
    USE SIGNAL ;
    PORT
      LAYER M4 ;
        RECT  0 11.376 0.084 11.4 ;
    END
  END q_w[97]
  PIN q_w[98]
    DIRECTION OUTPUT ;
    USE SIGNAL ;
    PORT
      LAYER M4 ;
        RECT  0 11.52 0.084 11.544 ;
    END
  END q_w[98]
  PIN q_w[99]
    DIRECTION OUTPUT ;
    USE SIGNAL ;
    PORT
      LAYER M4 ;
        RECT  0 11.664 0.084 11.688 ;
    END
  END q_w[99]
  PIN q_w[9]
    DIRECTION OUTPUT ;
    USE SIGNAL ;
    PORT
      LAYER M4 ;
        RECT  0 59.76 0.084 59.784 ;
    END
  END q_w[9]
  PIN qpop
    DIRECTION INPUT ;
    USE SIGNAL ;
    PORT
      LAYER M5 ;
        RECT  11.376 97.116 11.4 97.2 ;
    END
  END qpop
  PIN rst_n
    DIRECTION INPUT ;
    USE SIGNAL ;
    PORT
      LAYER M5 ;
        RECT  11.52 97.116 11.544 97.2 ;
    END
  END rst_n
  PIN x_d[0]
    DIRECTION INPUT ;
    USE SIGNAL ;
    PORT
      LAYER M5 ;
        RECT  11.664 97.116 11.688 97.2 ;
    END
  END x_d[0]
  PIN x_d[100]
    DIRECTION INPUT ;
    USE SIGNAL ;
    PORT
      LAYER M5 ;
        RECT  30.672 97.116 30.696 97.2 ;
    END
  END x_d[100]
  PIN x_d[101]
    DIRECTION INPUT ;
    USE SIGNAL ;
    PORT
      LAYER M5 ;
        RECT  30.816 97.116 30.84 97.2 ;
    END
  END x_d[101]
  PIN x_d[102]
    DIRECTION INPUT ;
    USE SIGNAL ;
    PORT
      LAYER M5 ;
        RECT  30.96 97.116 30.984 97.2 ;
    END
  END x_d[102]
  PIN x_d[103]
    DIRECTION INPUT ;
    USE SIGNAL ;
    PORT
      LAYER M5 ;
        RECT  31.104 97.116 31.128 97.2 ;
    END
  END x_d[103]
  PIN x_d[104]
    DIRECTION INPUT ;
    USE SIGNAL ;
    PORT
      LAYER M5 ;
        RECT  31.248 97.116 31.272 97.2 ;
    END
  END x_d[104]
  PIN x_d[105]
    DIRECTION INPUT ;
    USE SIGNAL ;
    PORT
      LAYER M5 ;
        RECT  31.392 97.116 31.416 97.2 ;
    END
  END x_d[105]
  PIN x_d[106]
    DIRECTION INPUT ;
    USE SIGNAL ;
    PORT
      LAYER M5 ;
        RECT  31.536 97.116 31.56 97.2 ;
    END
  END x_d[106]
  PIN x_d[107]
    DIRECTION INPUT ;
    USE SIGNAL ;
    PORT
      LAYER M5 ;
        RECT  31.68 97.116 31.704 97.2 ;
    END
  END x_d[107]
  PIN x_d[108]
    DIRECTION INPUT ;
    USE SIGNAL ;
    PORT
      LAYER M5 ;
        RECT  31.824 97.116 31.848 97.2 ;
    END
  END x_d[108]
  PIN x_d[109]
    DIRECTION INPUT ;
    USE SIGNAL ;
    PORT
      LAYER M5 ;
        RECT  31.968 97.116 31.992 97.2 ;
    END
  END x_d[109]
  PIN x_d[10]
    DIRECTION INPUT ;
    USE SIGNAL ;
    PORT
      LAYER M5 ;
        RECT  13.104 97.116 13.128 97.2 ;
    END
  END x_d[10]
  PIN x_d[110]
    DIRECTION INPUT ;
    USE SIGNAL ;
    PORT
      LAYER M5 ;
        RECT  32.112 97.116 32.136 97.2 ;
    END
  END x_d[110]
  PIN x_d[111]
    DIRECTION INPUT ;
    USE SIGNAL ;
    PORT
      LAYER M5 ;
        RECT  32.256 97.116 32.28 97.2 ;
    END
  END x_d[111]
  PIN x_d[112]
    DIRECTION INPUT ;
    USE SIGNAL ;
    PORT
      LAYER M5 ;
        RECT  32.4 97.116 32.424 97.2 ;
    END
  END x_d[112]
  PIN x_d[113]
    DIRECTION INPUT ;
    USE SIGNAL ;
    PORT
      LAYER M5 ;
        RECT  32.544 97.116 32.568 97.2 ;
    END
  END x_d[113]
  PIN x_d[114]
    DIRECTION INPUT ;
    USE SIGNAL ;
    PORT
      LAYER M5 ;
        RECT  32.688 97.116 32.712 97.2 ;
    END
  END x_d[114]
  PIN x_d[115]
    DIRECTION INPUT ;
    USE SIGNAL ;
    PORT
      LAYER M5 ;
        RECT  32.832 97.116 32.856 97.2 ;
    END
  END x_d[115]
  PIN x_d[116]
    DIRECTION INPUT ;
    USE SIGNAL ;
    PORT
      LAYER M5 ;
        RECT  32.976 97.116 33 97.2 ;
    END
  END x_d[116]
  PIN x_d[117]
    DIRECTION INPUT ;
    USE SIGNAL ;
    PORT
      LAYER M5 ;
        RECT  33.12 97.116 33.144 97.2 ;
    END
  END x_d[117]
  PIN x_d[118]
    DIRECTION INPUT ;
    USE SIGNAL ;
    PORT
      LAYER M5 ;
        RECT  33.264 97.116 33.288 97.2 ;
    END
  END x_d[118]
  PIN x_d[119]
    DIRECTION INPUT ;
    USE SIGNAL ;
    PORT
      LAYER M5 ;
        RECT  33.408 97.116 33.432 97.2 ;
    END
  END x_d[119]
  PIN x_d[11]
    DIRECTION INPUT ;
    USE SIGNAL ;
    PORT
      LAYER M5 ;
        RECT  13.248 97.116 13.272 97.2 ;
    END
  END x_d[11]
  PIN x_d[120]
    DIRECTION INPUT ;
    USE SIGNAL ;
    PORT
      LAYER M5 ;
        RECT  33.552 97.116 33.576 97.2 ;
    END
  END x_d[120]
  PIN x_d[121]
    DIRECTION INPUT ;
    USE SIGNAL ;
    PORT
      LAYER M5 ;
        RECT  33.696 97.116 33.72 97.2 ;
    END
  END x_d[121]
  PIN x_d[122]
    DIRECTION INPUT ;
    USE SIGNAL ;
    PORT
      LAYER M5 ;
        RECT  33.84 97.116 33.864 97.2 ;
    END
  END x_d[122]
  PIN x_d[123]
    DIRECTION INPUT ;
    USE SIGNAL ;
    PORT
      LAYER M5 ;
        RECT  33.984 97.116 34.008 97.2 ;
    END
  END x_d[123]
  PIN x_d[124]
    DIRECTION INPUT ;
    USE SIGNAL ;
    PORT
      LAYER M5 ;
        RECT  34.128 97.116 34.152 97.2 ;
    END
  END x_d[124]
  PIN x_d[125]
    DIRECTION INPUT ;
    USE SIGNAL ;
    PORT
      LAYER M5 ;
        RECT  10.656 97.116 10.68 97.2 ;
    END
  END x_d[125]
  PIN x_d[126]
    DIRECTION INPUT ;
    USE SIGNAL ;
    PORT
      LAYER M5 ;
        RECT  10.8 97.116 10.824 97.2 ;
    END
  END x_d[126]
  PIN x_d[127]
    DIRECTION INPUT ;
    USE SIGNAL ;
    PORT
      LAYER M5 ;
        RECT  10.944 97.116 10.968 97.2 ;
    END
  END x_d[127]
  PIN x_d[12]
    DIRECTION INPUT ;
    USE SIGNAL ;
    PORT
      LAYER M5 ;
        RECT  13.392 97.116 13.416 97.2 ;
    END
  END x_d[12]
  PIN x_d[13]
    DIRECTION INPUT ;
    USE SIGNAL ;
    PORT
      LAYER M5 ;
        RECT  13.536 97.116 13.56 97.2 ;
    END
  END x_d[13]
  PIN x_d[14]
    DIRECTION INPUT ;
    USE SIGNAL ;
    PORT
      LAYER M5 ;
        RECT  13.68 97.116 13.704 97.2 ;
    END
  END x_d[14]
  PIN x_d[15]
    DIRECTION INPUT ;
    USE SIGNAL ;
    PORT
      LAYER M5 ;
        RECT  13.824 97.116 13.848 97.2 ;
    END
  END x_d[15]
  PIN x_d[16]
    DIRECTION INPUT ;
    USE SIGNAL ;
    PORT
      LAYER M5 ;
        RECT  13.968 97.116 13.992 97.2 ;
    END
  END x_d[16]
  PIN x_d[17]
    DIRECTION INPUT ;
    USE SIGNAL ;
    PORT
      LAYER M5 ;
        RECT  14.112 97.116 14.136 97.2 ;
    END
  END x_d[17]
  PIN x_d[18]
    DIRECTION INPUT ;
    USE SIGNAL ;
    PORT
      LAYER M5 ;
        RECT  14.256 97.116 14.28 97.2 ;
    END
  END x_d[18]
  PIN x_d[19]
    DIRECTION INPUT ;
    USE SIGNAL ;
    PORT
      LAYER M5 ;
        RECT  14.4 97.116 14.424 97.2 ;
    END
  END x_d[19]
  PIN x_d[1]
    DIRECTION INPUT ;
    USE SIGNAL ;
    PORT
      LAYER M5 ;
        RECT  11.808 97.116 11.832 97.2 ;
    END
  END x_d[1]
  PIN x_d[20]
    DIRECTION INPUT ;
    USE SIGNAL ;
    PORT
      LAYER M5 ;
        RECT  14.544 97.116 14.568 97.2 ;
    END
  END x_d[20]
  PIN x_d[21]
    DIRECTION INPUT ;
    USE SIGNAL ;
    PORT
      LAYER M5 ;
        RECT  14.688 97.116 14.712 97.2 ;
    END
  END x_d[21]
  PIN x_d[22]
    DIRECTION INPUT ;
    USE SIGNAL ;
    PORT
      LAYER M5 ;
        RECT  14.832 97.116 14.856 97.2 ;
    END
  END x_d[22]
  PIN x_d[23]
    DIRECTION INPUT ;
    USE SIGNAL ;
    PORT
      LAYER M5 ;
        RECT  14.976 97.116 15 97.2 ;
    END
  END x_d[23]
  PIN x_d[24]
    DIRECTION INPUT ;
    USE SIGNAL ;
    PORT
      LAYER M5 ;
        RECT  15.12 97.116 15.144 97.2 ;
    END
  END x_d[24]
  PIN x_d[25]
    DIRECTION INPUT ;
    USE SIGNAL ;
    PORT
      LAYER M5 ;
        RECT  15.264 97.116 15.288 97.2 ;
    END
  END x_d[25]
  PIN x_d[26]
    DIRECTION INPUT ;
    USE SIGNAL ;
    PORT
      LAYER M5 ;
        RECT  15.408 97.116 15.432 97.2 ;
    END
  END x_d[26]
  PIN x_d[27]
    DIRECTION INPUT ;
    USE SIGNAL ;
    PORT
      LAYER M5 ;
        RECT  15.552 97.116 15.576 97.2 ;
    END
  END x_d[27]
  PIN x_d[28]
    DIRECTION INPUT ;
    USE SIGNAL ;
    PORT
      LAYER M5 ;
        RECT  15.696 97.116 15.72 97.2 ;
    END
  END x_d[28]
  PIN x_d[29]
    DIRECTION INPUT ;
    USE SIGNAL ;
    PORT
      LAYER M5 ;
        RECT  53.856 97.116 53.88 97.2 ;
    END
  END x_d[29]
  PIN x_d[2]
    DIRECTION INPUT ;
    USE SIGNAL ;
    PORT
      LAYER M5 ;
        RECT  11.952 97.116 11.976 97.2 ;
    END
  END x_d[2]
  PIN x_d[30]
    DIRECTION INPUT ;
    USE SIGNAL ;
    PORT
      LAYER M5 ;
        RECT  54 97.116 54.024 97.2 ;
    END
  END x_d[30]
  PIN x_d[31]
    DIRECTION INPUT ;
    USE SIGNAL ;
    PORT
      LAYER M5 ;
        RECT  54.144 97.116 54.168 97.2 ;
    END
  END x_d[31]
  PIN x_d[32]
    DIRECTION INPUT ;
    USE SIGNAL ;
    PORT
      LAYER M5 ;
        RECT  54.288 97.116 54.312 97.2 ;
    END
  END x_d[32]
  PIN x_d[33]
    DIRECTION INPUT ;
    USE SIGNAL ;
    PORT
      LAYER M5 ;
        RECT  54.432 97.116 54.456 97.2 ;
    END
  END x_d[33]
  PIN x_d[34]
    DIRECTION INPUT ;
    USE SIGNAL ;
    PORT
      LAYER M5 ;
        RECT  54.576 97.116 54.6 97.2 ;
    END
  END x_d[34]
  PIN x_d[35]
    DIRECTION INPUT ;
    USE SIGNAL ;
    PORT
      LAYER M5 ;
        RECT  54.72 97.116 54.744 97.2 ;
    END
  END x_d[35]
  PIN x_d[36]
    DIRECTION INPUT ;
    USE SIGNAL ;
    PORT
      LAYER M5 ;
        RECT  54.864 97.116 54.888 97.2 ;
    END
  END x_d[36]
  PIN x_d[37]
    DIRECTION INPUT ;
    USE SIGNAL ;
    PORT
      LAYER M5 ;
        RECT  55.008 97.116 55.032 97.2 ;
    END
  END x_d[37]
  PIN x_d[38]
    DIRECTION INPUT ;
    USE SIGNAL ;
    PORT
      LAYER M5 ;
        RECT  55.152 97.116 55.176 97.2 ;
    END
  END x_d[38]
  PIN x_d[39]
    DIRECTION INPUT ;
    USE SIGNAL ;
    PORT
      LAYER M5 ;
        RECT  55.296 97.116 55.32 97.2 ;
    END
  END x_d[39]
  PIN x_d[3]
    DIRECTION INPUT ;
    USE SIGNAL ;
    PORT
      LAYER M5 ;
        RECT  12.096 97.116 12.12 97.2 ;
    END
  END x_d[3]
  PIN x_d[40]
    DIRECTION INPUT ;
    USE SIGNAL ;
    PORT
      LAYER M5 ;
        RECT  55.44 97.116 55.464 97.2 ;
    END
  END x_d[40]
  PIN x_d[41]
    DIRECTION INPUT ;
    USE SIGNAL ;
    PORT
      LAYER M5 ;
        RECT  55.584 97.116 55.608 97.2 ;
    END
  END x_d[41]
  PIN x_d[42]
    DIRECTION INPUT ;
    USE SIGNAL ;
    PORT
      LAYER M5 ;
        RECT  55.728 97.116 55.752 97.2 ;
    END
  END x_d[42]
  PIN x_d[43]
    DIRECTION INPUT ;
    USE SIGNAL ;
    PORT
      LAYER M5 ;
        RECT  55.872 97.116 55.896 97.2 ;
    END
  END x_d[43]
  PIN x_d[44]
    DIRECTION INPUT ;
    USE SIGNAL ;
    PORT
      LAYER M5 ;
        RECT  56.016 97.116 56.04 97.2 ;
    END
  END x_d[44]
  PIN x_d[45]
    DIRECTION INPUT ;
    USE SIGNAL ;
    PORT
      LAYER M5 ;
        RECT  56.16 97.116 56.184 97.2 ;
    END
  END x_d[45]
  PIN x_d[46]
    DIRECTION INPUT ;
    USE SIGNAL ;
    PORT
      LAYER M5 ;
        RECT  56.304 97.116 56.328 97.2 ;
    END
  END x_d[46]
  PIN x_d[47]
    DIRECTION INPUT ;
    USE SIGNAL ;
    PORT
      LAYER M5 ;
        RECT  56.448 97.116 56.472 97.2 ;
    END
  END x_d[47]
  PIN x_d[48]
    DIRECTION INPUT ;
    USE SIGNAL ;
    PORT
      LAYER M5 ;
        RECT  56.592 97.116 56.616 97.2 ;
    END
  END x_d[48]
  PIN x_d[49]
    DIRECTION INPUT ;
    USE SIGNAL ;
    PORT
      LAYER M5 ;
        RECT  56.736 97.116 56.76 97.2 ;
    END
  END x_d[49]
  PIN x_d[4]
    DIRECTION INPUT ;
    USE SIGNAL ;
    PORT
      LAYER M5 ;
        RECT  12.24 97.116 12.264 97.2 ;
    END
  END x_d[4]
  PIN x_d[50]
    DIRECTION INPUT ;
    USE SIGNAL ;
    PORT
      LAYER M5 ;
        RECT  56.88 97.116 56.904 97.2 ;
    END
  END x_d[50]
  PIN x_d[51]
    DIRECTION INPUT ;
    USE SIGNAL ;
    PORT
      LAYER M5 ;
        RECT  57.024 97.116 57.048 97.2 ;
    END
  END x_d[51]
  PIN x_d[52]
    DIRECTION INPUT ;
    USE SIGNAL ;
    PORT
      LAYER M5 ;
        RECT  57.168 97.116 57.192 97.2 ;
    END
  END x_d[52]
  PIN x_d[53]
    DIRECTION INPUT ;
    USE SIGNAL ;
    PORT
      LAYER M5 ;
        RECT  57.312 97.116 57.336 97.2 ;
    END
  END x_d[53]
  PIN x_d[54]
    DIRECTION INPUT ;
    USE SIGNAL ;
    PORT
      LAYER M5 ;
        RECT  57.456 97.116 57.48 97.2 ;
    END
  END x_d[54]
  PIN x_d[55]
    DIRECTION INPUT ;
    USE SIGNAL ;
    PORT
      LAYER M5 ;
        RECT  57.6 97.116 57.624 97.2 ;
    END
  END x_d[55]
  PIN x_d[56]
    DIRECTION INPUT ;
    USE SIGNAL ;
    PORT
      LAYER M5 ;
        RECT  57.744 97.116 57.768 97.2 ;
    END
  END x_d[56]
  PIN x_d[57]
    DIRECTION INPUT ;
    USE SIGNAL ;
    PORT
      LAYER M5 ;
        RECT  57.888 97.116 57.912 97.2 ;
    END
  END x_d[57]
  PIN x_d[58]
    DIRECTION INPUT ;
    USE SIGNAL ;
    PORT
      LAYER M5 ;
        RECT  58.032 97.116 58.056 97.2 ;
    END
  END x_d[58]
  PIN x_d[59]
    DIRECTION INPUT ;
    USE SIGNAL ;
    PORT
      LAYER M5 ;
        RECT  58.176 97.116 58.2 97.2 ;
    END
  END x_d[59]
  PIN x_d[5]
    DIRECTION INPUT ;
    USE SIGNAL ;
    PORT
      LAYER M5 ;
        RECT  12.384 97.116 12.408 97.2 ;
    END
  END x_d[5]
  PIN x_d[60]
    DIRECTION INPUT ;
    USE SIGNAL ;
    PORT
      LAYER M5 ;
        RECT  58.32 97.116 58.344 97.2 ;
    END
  END x_d[60]
  PIN x_d[61]
    DIRECTION INPUT ;
    USE SIGNAL ;
    PORT
      LAYER M5 ;
        RECT  73.44 97.116 73.464 97.2 ;
    END
  END x_d[61]
  PIN x_d[62]
    DIRECTION INPUT ;
    USE SIGNAL ;
    PORT
      LAYER M5 ;
        RECT  73.584 97.116 73.608 97.2 ;
    END
  END x_d[62]
  PIN x_d[63]
    DIRECTION INPUT ;
    USE SIGNAL ;
    PORT
      LAYER M5 ;
        RECT  73.728 97.116 73.752 97.2 ;
    END
  END x_d[63]
  PIN x_d[64]
    DIRECTION INPUT ;
    USE SIGNAL ;
    PORT
      LAYER M5 ;
        RECT  73.872 97.116 73.896 97.2 ;
    END
  END x_d[64]
  PIN x_d[65]
    DIRECTION INPUT ;
    USE SIGNAL ;
    PORT
      LAYER M5 ;
        RECT  74.016 97.116 74.04 97.2 ;
    END
  END x_d[65]
  PIN x_d[66]
    DIRECTION INPUT ;
    USE SIGNAL ;
    PORT
      LAYER M5 ;
        RECT  74.16 97.116 74.184 97.2 ;
    END
  END x_d[66]
  PIN x_d[67]
    DIRECTION INPUT ;
    USE SIGNAL ;
    PORT
      LAYER M5 ;
        RECT  74.304 97.116 74.328 97.2 ;
    END
  END x_d[67]
  PIN x_d[68]
    DIRECTION INPUT ;
    USE SIGNAL ;
    PORT
      LAYER M5 ;
        RECT  74.448 97.116 74.472 97.2 ;
    END
  END x_d[68]
  PIN x_d[69]
    DIRECTION INPUT ;
    USE SIGNAL ;
    PORT
      LAYER M5 ;
        RECT  74.592 97.116 74.616 97.2 ;
    END
  END x_d[69]
  PIN x_d[6]
    DIRECTION INPUT ;
    USE SIGNAL ;
    PORT
      LAYER M5 ;
        RECT  12.528 97.116 12.552 97.2 ;
    END
  END x_d[6]
  PIN x_d[70]
    DIRECTION INPUT ;
    USE SIGNAL ;
    PORT
      LAYER M5 ;
        RECT  74.736 97.116 74.76 97.2 ;
    END
  END x_d[70]
  PIN x_d[71]
    DIRECTION INPUT ;
    USE SIGNAL ;
    PORT
      LAYER M5 ;
        RECT  74.88 97.116 74.904 97.2 ;
    END
  END x_d[71]
  PIN x_d[72]
    DIRECTION INPUT ;
    USE SIGNAL ;
    PORT
      LAYER M5 ;
        RECT  75.024 97.116 75.048 97.2 ;
    END
  END x_d[72]
  PIN x_d[73]
    DIRECTION INPUT ;
    USE SIGNAL ;
    PORT
      LAYER M5 ;
        RECT  75.168 97.116 75.192 97.2 ;
    END
  END x_d[73]
  PIN x_d[74]
    DIRECTION INPUT ;
    USE SIGNAL ;
    PORT
      LAYER M5 ;
        RECT  75.312 97.116 75.336 97.2 ;
    END
  END x_d[74]
  PIN x_d[75]
    DIRECTION INPUT ;
    USE SIGNAL ;
    PORT
      LAYER M5 ;
        RECT  75.456 97.116 75.48 97.2 ;
    END
  END x_d[75]
  PIN x_d[76]
    DIRECTION INPUT ;
    USE SIGNAL ;
    PORT
      LAYER M5 ;
        RECT  75.6 97.116 75.624 97.2 ;
    END
  END x_d[76]
  PIN x_d[77]
    DIRECTION INPUT ;
    USE SIGNAL ;
    PORT
      LAYER M5 ;
        RECT  75.744 97.116 75.768 97.2 ;
    END
  END x_d[77]
  PIN x_d[78]
    DIRECTION INPUT ;
    USE SIGNAL ;
    PORT
      LAYER M5 ;
        RECT  75.888 97.116 75.912 97.2 ;
    END
  END x_d[78]
  PIN x_d[79]
    DIRECTION INPUT ;
    USE SIGNAL ;
    PORT
      LAYER M5 ;
        RECT  76.032 97.116 76.056 97.2 ;
    END
  END x_d[79]
  PIN x_d[7]
    DIRECTION INPUT ;
    USE SIGNAL ;
    PORT
      LAYER M5 ;
        RECT  12.672 97.116 12.696 97.2 ;
    END
  END x_d[7]
  PIN x_d[80]
    DIRECTION INPUT ;
    USE SIGNAL ;
    PORT
      LAYER M5 ;
        RECT  76.176 97.116 76.2 97.2 ;
    END
  END x_d[80]
  PIN x_d[81]
    DIRECTION INPUT ;
    USE SIGNAL ;
    PORT
      LAYER M5 ;
        RECT  76.32 97.116 76.344 97.2 ;
    END
  END x_d[81]
  PIN x_d[82]
    DIRECTION INPUT ;
    USE SIGNAL ;
    PORT
      LAYER M5 ;
        RECT  76.464 97.116 76.488 97.2 ;
    END
  END x_d[82]
  PIN x_d[83]
    DIRECTION INPUT ;
    USE SIGNAL ;
    PORT
      LAYER M5 ;
        RECT  76.608 97.116 76.632 97.2 ;
    END
  END x_d[83]
  PIN x_d[84]
    DIRECTION INPUT ;
    USE SIGNAL ;
    PORT
      LAYER M5 ;
        RECT  76.752 97.116 76.776 97.2 ;
    END
  END x_d[84]
  PIN x_d[85]
    DIRECTION INPUT ;
    USE SIGNAL ;
    PORT
      LAYER M5 ;
        RECT  76.896 97.116 76.92 97.2 ;
    END
  END x_d[85]
  PIN x_d[86]
    DIRECTION INPUT ;
    USE SIGNAL ;
    PORT
      LAYER M5 ;
        RECT  77.04 97.116 77.064 97.2 ;
    END
  END x_d[86]
  PIN x_d[87]
    DIRECTION INPUT ;
    USE SIGNAL ;
    PORT
      LAYER M5 ;
        RECT  77.184 97.116 77.208 97.2 ;
    END
  END x_d[87]
  PIN x_d[88]
    DIRECTION INPUT ;
    USE SIGNAL ;
    PORT
      LAYER M5 ;
        RECT  77.328 97.116 77.352 97.2 ;
    END
  END x_d[88]
  PIN x_d[89]
    DIRECTION INPUT ;
    USE SIGNAL ;
    PORT
      LAYER M5 ;
        RECT  77.472 97.116 77.496 97.2 ;
    END
  END x_d[89]
  PIN x_d[8]
    DIRECTION INPUT ;
    USE SIGNAL ;
    PORT
      LAYER M5 ;
        RECT  12.816 97.116 12.84 97.2 ;
    END
  END x_d[8]
  PIN x_d[90]
    DIRECTION INPUT ;
    USE SIGNAL ;
    PORT
      LAYER M5 ;
        RECT  77.616 97.116 77.64 97.2 ;
    END
  END x_d[90]
  PIN x_d[91]
    DIRECTION INPUT ;
    USE SIGNAL ;
    PORT
      LAYER M5 ;
        RECT  77.76 97.116 77.784 97.2 ;
    END
  END x_d[91]
  PIN x_d[92]
    DIRECTION INPUT ;
    USE SIGNAL ;
    PORT
      LAYER M5 ;
        RECT  77.904 97.116 77.928 97.2 ;
    END
  END x_d[92]
  PIN x_d[93]
    DIRECTION INPUT ;
    USE SIGNAL ;
    PORT
      LAYER M5 ;
        RECT  29.664 97.116 29.688 97.2 ;
    END
  END x_d[93]
  PIN x_d[94]
    DIRECTION INPUT ;
    USE SIGNAL ;
    PORT
      LAYER M5 ;
        RECT  29.808 97.116 29.832 97.2 ;
    END
  END x_d[94]
  PIN x_d[95]
    DIRECTION INPUT ;
    USE SIGNAL ;
    PORT
      LAYER M5 ;
        RECT  29.952 97.116 29.976 97.2 ;
    END
  END x_d[95]
  PIN x_d[96]
    DIRECTION INPUT ;
    USE SIGNAL ;
    PORT
      LAYER M5 ;
        RECT  30.096 97.116 30.12 97.2 ;
    END
  END x_d[96]
  PIN x_d[97]
    DIRECTION INPUT ;
    USE SIGNAL ;
    PORT
      LAYER M5 ;
        RECT  30.24 97.116 30.264 97.2 ;
    END
  END x_d[97]
  PIN x_d[98]
    DIRECTION INPUT ;
    USE SIGNAL ;
    PORT
      LAYER M5 ;
        RECT  30.384 97.116 30.408 97.2 ;
    END
  END x_d[98]
  PIN x_d[99]
    DIRECTION INPUT ;
    USE SIGNAL ;
    PORT
      LAYER M5 ;
        RECT  30.528 97.116 30.552 97.2 ;
    END
  END x_d[99]
  PIN x_d[9]
    DIRECTION INPUT ;
    USE SIGNAL ;
    PORT
      LAYER M5 ;
        RECT  12.96 97.116 12.984 97.2 ;
    END
  END x_d[9]
  PIN x_v
    DIRECTION INPUT ;
    USE SIGNAL ;
    PORT
      LAYER M5 ;
        RECT  11.088 97.116 11.112 97.2 ;
    END
  END x_v
  PIN VDD
    DIRECTION INOUT ;
    USE POWER ;
    PORT
      LAYER M5 ;
        RECT  94.392 2.151 94.512 95.049 ;
        RECT  91.692 2.151 91.812 95.049 ;
        RECT  88.992 2.151 89.112 95.049 ;
        RECT  86.292 2.151 86.412 95.049 ;
        RECT  83.592 2.151 83.712 95.049 ;
        RECT  80.892 2.151 81.012 95.049 ;
        RECT  78.192 2.151 78.312 95.049 ;
        RECT  75.492 2.151 75.612 95.049 ;
        RECT  72.792 2.151 72.912 95.049 ;
        RECT  70.092 2.151 70.212 95.049 ;
        RECT  67.392 2.151 67.512 95.049 ;
        RECT  64.692 2.151 64.812 95.049 ;
        RECT  61.992 2.151 62.112 95.049 ;
        RECT  59.292 2.151 59.412 95.049 ;
        RECT  56.592 2.151 56.712 95.049 ;
        RECT  53.892 2.151 54.012 95.049 ;
        RECT  51.192 2.151 51.312 95.049 ;
        RECT  48.492 2.151 48.612 95.049 ;
        RECT  45.792 2.151 45.912 95.049 ;
        RECT  43.092 2.151 43.212 95.049 ;
        RECT  40.392 2.151 40.512 95.049 ;
        RECT  37.692 2.151 37.812 95.049 ;
        RECT  34.992 2.151 35.112 95.049 ;
        RECT  32.292 2.151 32.412 95.049 ;
        RECT  29.592 2.151 29.712 95.049 ;
        RECT  26.892 2.151 27.012 95.049 ;
        RECT  24.192 2.151 24.312 95.049 ;
        RECT  21.492 2.151 21.612 95.049 ;
        RECT  18.792 2.151 18.912 95.049 ;
        RECT  16.092 2.151 16.212 95.049 ;
        RECT  13.392 2.151 13.512 95.049 ;
        RECT  10.692 2.151 10.812 95.049 ;
        RECT  7.992 2.151 8.112 95.049 ;
        RECT  5.292 2.151 5.412 95.049 ;
        RECT  2.592 2.151 2.712 95.049 ;
    END
  END VDD
  PIN VSS
    DIRECTION INOUT ;
    USE GROUND ;
    PORT
      LAYER M5 ;
        RECT  94.2 2.137 94.32 95.063 ;
        RECT  91.5 2.137 91.62 95.063 ;
        RECT  88.8 2.137 88.92 95.063 ;
        RECT  86.1 2.137 86.22 95.063 ;
        RECT  83.4 2.137 83.52 95.063 ;
        RECT  80.7 2.137 80.82 95.063 ;
        RECT  78 2.137 78.12 95.063 ;
        RECT  75.3 2.137 75.42 95.063 ;
        RECT  72.6 2.137 72.72 95.063 ;
        RECT  69.9 2.137 70.02 95.063 ;
        RECT  67.2 2.137 67.32 95.063 ;
        RECT  64.5 2.137 64.62 95.063 ;
        RECT  61.8 2.137 61.92 95.063 ;
        RECT  59.1 2.137 59.22 95.063 ;
        RECT  56.4 2.137 56.52 95.063 ;
        RECT  53.7 2.137 53.82 95.063 ;
        RECT  51 2.137 51.12 95.063 ;
        RECT  48.3 2.137 48.42 95.063 ;
        RECT  45.6 2.137 45.72 95.063 ;
        RECT  42.9 2.137 43.02 95.063 ;
        RECT  40.2 2.137 40.32 95.063 ;
        RECT  37.5 2.137 37.62 95.063 ;
        RECT  34.8 2.137 34.92 95.063 ;
        RECT  32.1 2.137 32.22 95.063 ;
        RECT  29.4 2.137 29.52 95.063 ;
        RECT  26.7 2.137 26.82 95.063 ;
        RECT  24 2.137 24.12 95.063 ;
        RECT  21.3 2.137 21.42 95.063 ;
        RECT  18.6 2.137 18.72 95.063 ;
        RECT  15.9 2.137 16.02 95.063 ;
        RECT  13.2 2.137 13.32 95.063 ;
        RECT  10.5 2.137 10.62 95.063 ;
        RECT  7.8 2.137 7.92 95.063 ;
        RECT  5.1 2.137 5.22 95.063 ;
        RECT  2.4 2.137 2.52 95.063 ;
    END
  END VSS
  # OT_OBS_CLOSED layer=M5 d_um=1.536 added=1233
  OBS
    LAYER RVTN ;
     RECT  2.16 2.16 95.04 2.295 ;
     RECT  2.16 2.565 95.04 2.835 ;
     RECT  2.16 3.105 95.04 3.375 ;
     RECT  2.16 3.645 95.04 3.915 ;
     RECT  2.16 4.185 95.04 4.455 ;
     RECT  2.16 4.725 95.04 4.995 ;
     RECT  2.16 5.265 95.04 5.535 ;
     RECT  2.16 5.805 95.04 6.075 ;
     RECT  2.16 6.345 95.04 6.615 ;
     RECT  2.16 6.885 95.04 7.155 ;
     RECT  2.16 7.425 95.04 7.695 ;
     RECT  2.16 7.965 95.04 8.235 ;
     RECT  2.16 8.505 95.04 8.775 ;
     RECT  2.16 9.045 95.04 9.315 ;
     RECT  2.16 9.585 95.04 9.855 ;
     RECT  2.16 10.125 95.04 10.395 ;
     RECT  2.16 10.665 95.04 10.935 ;
     RECT  2.16 11.205 95.04 11.475 ;
     RECT  2.16 11.745 95.04 12.015 ;
     RECT  2.16 12.285 95.04 12.555 ;
     RECT  2.16 12.825 95.04 13.095 ;
     RECT  2.16 13.365 95.04 13.635 ;
     RECT  2.16 13.905 95.04 14.175 ;
     RECT  2.16 14.445 95.04 14.715 ;
     RECT  2.16 14.985 95.04 15.255 ;
     RECT  2.16 15.525 95.04 15.795 ;
     RECT  2.16 16.065 95.04 16.335 ;
     RECT  2.16 16.605 95.04 16.875 ;
     RECT  2.16 17.145 95.04 17.415 ;
     RECT  2.16 17.685 95.04 17.955 ;
     RECT  2.16 18.225 95.04 18.495 ;
     RECT  2.16 18.765 95.04 19.035 ;
     RECT  2.16 19.305 95.04 19.575 ;
     RECT  2.16 19.845 95.04 20.115 ;
     RECT  2.16 20.385 95.04 20.655 ;
     RECT  2.16 20.925 95.04 21.195 ;
     RECT  2.16 21.465 95.04 21.735 ;
     RECT  2.16 22.005 95.04 22.275 ;
     RECT  2.16 22.545 95.04 22.815 ;
     RECT  2.16 23.085 95.04 23.355 ;
     RECT  2.16 23.625 95.04 23.895 ;
     RECT  2.16 24.165 95.04 24.435 ;
     RECT  2.16 24.705 95.04 24.975 ;
     RECT  2.16 25.245 95.04 25.515 ;
     RECT  2.16 25.785 95.04 26.055 ;
     RECT  2.16 26.325 95.04 26.595 ;
     RECT  2.16 26.865 95.04 27.135 ;
     RECT  2.16 27.405 95.04 27.675 ;
     RECT  2.16 27.945 95.04 28.215 ;
     RECT  2.16 28.485 95.04 28.755 ;
     RECT  2.16 29.025 95.04 29.295 ;
     RECT  2.16 29.565 95.04 29.835 ;
     RECT  2.16 30.105 95.04 30.375 ;
     RECT  2.16 30.645 95.04 30.915 ;
     RECT  2.16 31.185 95.04 31.455 ;
     RECT  2.16 31.725 95.04 31.995 ;
     RECT  2.16 32.265 95.04 32.535 ;
     RECT  2.16 32.805 95.04 33.075 ;
     RECT  2.16 33.345 95.04 33.615 ;
     RECT  2.16 33.885 95.04 34.155 ;
     RECT  2.16 34.425 95.04 34.695 ;
     RECT  2.16 34.965 95.04 35.235 ;
     RECT  2.16 35.505 95.04 35.775 ;
     RECT  2.16 36.045 95.04 36.315 ;
     RECT  2.16 36.585 95.04 36.855 ;
     RECT  2.16 37.125 95.04 37.395 ;
     RECT  2.16 37.665 95.04 37.935 ;
     RECT  2.16 38.205 95.04 38.475 ;
     RECT  2.16 38.745 95.04 39.015 ;
     RECT  2.16 39.285 95.04 39.555 ;
     RECT  2.16 39.825 95.04 40.095 ;
     RECT  2.16 40.365 95.04 40.635 ;
     RECT  2.16 40.905 95.04 41.175 ;
     RECT  2.16 41.445 95.04 41.715 ;
     RECT  2.16 41.985 95.04 42.255 ;
     RECT  2.16 42.525 95.04 42.795 ;
     RECT  2.16 43.065 95.04 43.335 ;
     RECT  2.16 43.605 95.04 43.875 ;
     RECT  2.16 44.145 95.04 44.415 ;
     RECT  2.16 44.685 95.04 44.955 ;
     RECT  2.16 45.225 95.04 45.495 ;
     RECT  2.16 45.765 95.04 46.035 ;
     RECT  2.16 46.305 95.04 46.575 ;
     RECT  2.16 46.845 95.04 47.115 ;
     RECT  2.16 47.385 95.04 47.655 ;
     RECT  2.16 47.925 95.04 48.195 ;
     RECT  2.16 48.465 95.04 48.735 ;
     RECT  2.16 49.005 95.04 49.275 ;
     RECT  2.16 49.545 95.04 49.815 ;
     RECT  2.16 50.085 95.04 50.355 ;
     RECT  2.16 50.625 95.04 50.895 ;
     RECT  2.16 51.165 95.04 51.435 ;
     RECT  2.16 51.705 95.04 51.975 ;
     RECT  2.16 52.245 95.04 52.515 ;
     RECT  2.16 52.785 95.04 53.055 ;
     RECT  2.16 53.325 95.04 53.595 ;
     RECT  2.16 53.865 95.04 54.135 ;
     RECT  2.16 54.405 95.04 54.675 ;
     RECT  2.16 54.945 95.04 55.215 ;
     RECT  2.16 55.485 95.04 55.755 ;
     RECT  2.16 56.025 95.04 56.295 ;
     RECT  2.16 56.565 95.04 56.835 ;
     RECT  2.16 57.105 95.04 57.375 ;
     RECT  2.16 57.645 95.04 57.915 ;
     RECT  2.16 58.185 95.04 58.455 ;
     RECT  2.16 58.725 95.04 58.995 ;
     RECT  2.16 59.265 95.04 59.535 ;
     RECT  2.16 59.805 95.04 60.075 ;
     RECT  2.16 60.345 95.04 60.615 ;
     RECT  2.16 60.885 95.04 61.155 ;
     RECT  2.16 61.425 95.04 61.695 ;
     RECT  2.16 61.965 95.04 62.235 ;
     RECT  2.16 62.505 95.04 62.775 ;
     RECT  2.16 63.045 95.04 63.315 ;
     RECT  2.16 63.585 95.04 63.855 ;
     RECT  2.16 64.125 95.04 64.395 ;
     RECT  2.16 64.665 95.04 64.935 ;
     RECT  2.16 65.205 95.04 65.475 ;
     RECT  2.16 65.745 95.04 66.015 ;
     RECT  2.16 66.285 95.04 66.555 ;
     RECT  2.16 66.825 95.04 67.095 ;
     RECT  2.16 67.365 95.04 67.635 ;
     RECT  2.16 67.905 95.04 68.175 ;
     RECT  2.16 68.445 95.04 68.715 ;
     RECT  2.16 68.985 95.04 69.255 ;
     RECT  2.16 69.525 95.04 69.795 ;
     RECT  2.16 70.065 95.04 70.335 ;
     RECT  2.16 70.605 95.04 70.875 ;
     RECT  2.16 71.145 95.04 71.415 ;
     RECT  2.16 71.685 95.04 71.955 ;
     RECT  2.16 72.225 95.04 72.495 ;
     RECT  2.16 72.765 95.04 73.035 ;
     RECT  2.16 73.305 95.04 73.575 ;
     RECT  2.16 73.845 95.04 74.115 ;
     RECT  2.16 74.385 95.04 74.655 ;
     RECT  2.16 74.925 95.04 75.195 ;
     RECT  2.16 75.465 95.04 75.735 ;
     RECT  2.16 76.005 95.04 76.275 ;
     RECT  2.16 76.545 95.04 76.815 ;
     RECT  2.16 77.085 95.04 77.355 ;
     RECT  2.16 77.625 95.04 77.895 ;
     RECT  2.16 78.165 95.04 78.435 ;
     RECT  2.16 78.705 95.04 78.975 ;
     RECT  2.16 79.245 95.04 79.515 ;
     RECT  2.16 79.785 95.04 80.055 ;
     RECT  2.16 80.325 95.04 80.595 ;
     RECT  2.16 80.865 95.04 81.135 ;
     RECT  2.16 81.405 95.04 81.675 ;
     RECT  2.16 81.945 95.04 82.215 ;
     RECT  2.16 82.485 95.04 82.755 ;
     RECT  2.16 83.025 95.04 83.295 ;
     RECT  2.16 83.565 95.04 83.835 ;
     RECT  2.16 84.105 95.04 84.375 ;
     RECT  2.16 84.645 95.04 84.915 ;
     RECT  2.16 85.185 95.04 85.455 ;
     RECT  2.16 85.725 95.04 85.995 ;
     RECT  2.16 86.265 95.04 86.535 ;
     RECT  2.16 86.805 95.04 87.075 ;
     RECT  2.16 87.345 95.04 87.615 ;
     RECT  2.16 87.885 95.04 88.155 ;
     RECT  2.16 88.425 95.04 88.695 ;
     RECT  2.16 88.965 95.04 89.235 ;
     RECT  2.16 89.505 95.04 89.775 ;
     RECT  2.16 90.045 95.04 90.315 ;
     RECT  2.16 90.585 95.04 90.855 ;
     RECT  2.16 91.125 95.04 91.395 ;
     RECT  2.16 91.665 95.04 91.935 ;
     RECT  2.16 92.205 95.04 92.475 ;
     RECT  2.16 92.745 95.04 93.015 ;
     RECT  2.16 93.285 95.04 93.555 ;
     RECT  2.16 93.825 95.04 94.095 ;
     RECT  2.16 94.365 95.04 94.635 ;
     RECT  2.16 94.905 95.04 95.04 ;
    LAYER RVTP ;
     RECT  2.16 2.295 95.04 2.565 ;
     RECT  2.16 2.835 95.04 3.105 ;
     RECT  2.16 3.375 95.04 3.645 ;
     RECT  2.16 3.915 95.04 4.185 ;
     RECT  2.16 4.455 95.04 4.725 ;
     RECT  2.16 4.995 95.04 5.265 ;
     RECT  2.16 5.535 95.04 5.805 ;
     RECT  2.16 6.075 95.04 6.345 ;
     RECT  2.16 6.615 95.04 6.885 ;
     RECT  2.16 7.155 95.04 7.425 ;
     RECT  2.16 7.695 95.04 7.965 ;
     RECT  2.16 8.235 95.04 8.505 ;
     RECT  2.16 8.775 95.04 9.045 ;
     RECT  2.16 9.315 95.04 9.585 ;
     RECT  2.16 9.855 95.04 10.125 ;
     RECT  2.16 10.395 95.04 10.665 ;
     RECT  2.16 10.935 95.04 11.205 ;
     RECT  2.16 11.475 95.04 11.745 ;
     RECT  2.16 12.015 95.04 12.285 ;
     RECT  2.16 12.555 95.04 12.825 ;
     RECT  2.16 13.095 95.04 13.365 ;
     RECT  2.16 13.635 95.04 13.905 ;
     RECT  2.16 14.175 95.04 14.445 ;
     RECT  2.16 14.715 95.04 14.985 ;
     RECT  2.16 15.255 95.04 15.525 ;
     RECT  2.16 15.795 95.04 16.065 ;
     RECT  2.16 16.335 95.04 16.605 ;
     RECT  2.16 16.875 95.04 17.145 ;
     RECT  2.16 17.415 95.04 17.685 ;
     RECT  2.16 17.955 95.04 18.225 ;
     RECT  2.16 18.495 95.04 18.765 ;
     RECT  2.16 19.035 95.04 19.305 ;
     RECT  2.16 19.575 95.04 19.845 ;
     RECT  2.16 20.115 95.04 20.385 ;
     RECT  2.16 20.655 95.04 20.925 ;
     RECT  2.16 21.195 95.04 21.465 ;
     RECT  2.16 21.735 95.04 22.005 ;
     RECT  2.16 22.275 95.04 22.545 ;
     RECT  2.16 22.815 95.04 23.085 ;
     RECT  2.16 23.355 95.04 23.625 ;
     RECT  2.16 23.895 95.04 24.165 ;
     RECT  2.16 24.435 95.04 24.705 ;
     RECT  2.16 24.975 95.04 25.245 ;
     RECT  2.16 25.515 95.04 25.785 ;
     RECT  2.16 26.055 95.04 26.325 ;
     RECT  2.16 26.595 95.04 26.865 ;
     RECT  2.16 27.135 95.04 27.405 ;
     RECT  2.16 27.675 95.04 27.945 ;
     RECT  2.16 28.215 95.04 28.485 ;
     RECT  2.16 28.755 95.04 29.025 ;
     RECT  2.16 29.295 95.04 29.565 ;
     RECT  2.16 29.835 95.04 30.105 ;
     RECT  2.16 30.375 95.04 30.645 ;
     RECT  2.16 30.915 95.04 31.185 ;
     RECT  2.16 31.455 95.04 31.725 ;
     RECT  2.16 31.995 95.04 32.265 ;
     RECT  2.16 32.535 95.04 32.805 ;
     RECT  2.16 33.075 95.04 33.345 ;
     RECT  2.16 33.615 95.04 33.885 ;
     RECT  2.16 34.155 95.04 34.425 ;
     RECT  2.16 34.695 95.04 34.965 ;
     RECT  2.16 35.235 95.04 35.505 ;
     RECT  2.16 35.775 95.04 36.045 ;
     RECT  2.16 36.315 95.04 36.585 ;
     RECT  2.16 36.855 95.04 37.125 ;
     RECT  2.16 37.395 95.04 37.665 ;
     RECT  2.16 37.935 95.04 38.205 ;
     RECT  2.16 38.475 95.04 38.745 ;
     RECT  2.16 39.015 95.04 39.285 ;
     RECT  2.16 39.555 95.04 39.825 ;
     RECT  2.16 40.095 95.04 40.365 ;
     RECT  2.16 40.635 95.04 40.905 ;
     RECT  2.16 41.175 95.04 41.445 ;
     RECT  2.16 41.715 95.04 41.985 ;
     RECT  2.16 42.255 95.04 42.525 ;
     RECT  2.16 42.795 95.04 43.065 ;
     RECT  2.16 43.335 95.04 43.605 ;
     RECT  2.16 43.875 95.04 44.145 ;
     RECT  2.16 44.415 95.04 44.685 ;
     RECT  2.16 44.955 95.04 45.225 ;
     RECT  2.16 45.495 95.04 45.765 ;
     RECT  2.16 46.035 95.04 46.305 ;
     RECT  2.16 46.575 95.04 46.845 ;
     RECT  2.16 47.115 95.04 47.385 ;
     RECT  2.16 47.655 95.04 47.925 ;
     RECT  2.16 48.195 95.04 48.465 ;
     RECT  2.16 48.735 95.04 49.005 ;
     RECT  2.16 49.275 95.04 49.545 ;
     RECT  2.16 49.815 95.04 50.085 ;
     RECT  2.16 50.355 95.04 50.625 ;
     RECT  2.16 50.895 95.04 51.165 ;
     RECT  2.16 51.435 95.04 51.705 ;
     RECT  2.16 51.975 95.04 52.245 ;
     RECT  2.16 52.515 95.04 52.785 ;
     RECT  2.16 53.055 95.04 53.325 ;
     RECT  2.16 53.595 95.04 53.865 ;
     RECT  2.16 54.135 95.04 54.405 ;
     RECT  2.16 54.675 95.04 54.945 ;
     RECT  2.16 55.215 95.04 55.485 ;
     RECT  2.16 55.755 95.04 56.025 ;
     RECT  2.16 56.295 95.04 56.565 ;
     RECT  2.16 56.835 95.04 57.105 ;
     RECT  2.16 57.375 95.04 57.645 ;
     RECT  2.16 57.915 95.04 58.185 ;
     RECT  2.16 58.455 95.04 58.725 ;
     RECT  2.16 58.995 95.04 59.265 ;
     RECT  2.16 59.535 95.04 59.805 ;
     RECT  2.16 60.075 95.04 60.345 ;
     RECT  2.16 60.615 95.04 60.885 ;
     RECT  2.16 61.155 95.04 61.425 ;
     RECT  2.16 61.695 95.04 61.965 ;
     RECT  2.16 62.235 95.04 62.505 ;
     RECT  2.16 62.775 95.04 63.045 ;
     RECT  2.16 63.315 95.04 63.585 ;
     RECT  2.16 63.855 95.04 64.125 ;
     RECT  2.16 64.395 95.04 64.665 ;
     RECT  2.16 64.935 95.04 65.205 ;
     RECT  2.16 65.475 95.04 65.745 ;
     RECT  2.16 66.015 95.04 66.285 ;
     RECT  2.16 66.555 95.04 66.825 ;
     RECT  2.16 67.095 95.04 67.365 ;
     RECT  2.16 67.635 95.04 67.905 ;
     RECT  2.16 68.175 95.04 68.445 ;
     RECT  2.16 68.715 95.04 68.985 ;
     RECT  2.16 69.255 95.04 69.525 ;
     RECT  2.16 69.795 95.04 70.065 ;
     RECT  2.16 70.335 95.04 70.605 ;
     RECT  2.16 70.875 95.04 71.145 ;
     RECT  2.16 71.415 95.04 71.685 ;
     RECT  2.16 71.955 95.04 72.225 ;
     RECT  2.16 72.495 95.04 72.765 ;
     RECT  2.16 73.035 95.04 73.305 ;
     RECT  2.16 73.575 95.04 73.845 ;
     RECT  2.16 74.115 95.04 74.385 ;
     RECT  2.16 74.655 95.04 74.925 ;
     RECT  2.16 75.195 95.04 75.465 ;
     RECT  2.16 75.735 95.04 76.005 ;
     RECT  2.16 76.275 95.04 76.545 ;
     RECT  2.16 76.815 95.04 77.085 ;
     RECT  2.16 77.355 95.04 77.625 ;
     RECT  2.16 77.895 95.04 78.165 ;
     RECT  2.16 78.435 95.04 78.705 ;
     RECT  2.16 78.975 95.04 79.245 ;
     RECT  2.16 79.515 95.04 79.785 ;
     RECT  2.16 80.055 95.04 80.325 ;
     RECT  2.16 80.595 95.04 80.865 ;
     RECT  2.16 81.135 95.04 81.405 ;
     RECT  2.16 81.675 95.04 81.945 ;
     RECT  2.16 82.215 95.04 82.485 ;
     RECT  2.16 82.755 95.04 83.025 ;
     RECT  2.16 83.295 95.04 83.565 ;
     RECT  2.16 83.835 95.04 84.105 ;
     RECT  2.16 84.375 95.04 84.645 ;
     RECT  2.16 84.915 95.04 85.185 ;
     RECT  2.16 85.455 95.04 85.725 ;
     RECT  2.16 85.995 95.04 86.265 ;
     RECT  2.16 86.535 95.04 86.805 ;
     RECT  2.16 87.075 95.04 87.345 ;
     RECT  2.16 87.615 95.04 87.885 ;
     RECT  2.16 88.155 95.04 88.425 ;
     RECT  2.16 88.695 95.04 88.965 ;
     RECT  2.16 89.235 95.04 89.505 ;
     RECT  2.16 89.775 95.04 90.045 ;
     RECT  2.16 90.315 95.04 90.585 ;
     RECT  2.16 90.855 95.04 91.125 ;
     RECT  2.16 91.395 95.04 91.665 ;
     RECT  2.16 91.935 95.04 92.205 ;
     RECT  2.16 92.475 95.04 92.745 ;
     RECT  2.16 93.015 95.04 93.285 ;
     RECT  2.16 93.555 95.04 93.825 ;
     RECT  2.16 94.095 95.04 94.365 ;
     RECT  2.16 94.635 95.04 94.905 ;
    LAYER M1 ;
     RECT  2.16 2.151 95.04 95.049 ;
    LAYER M2 ;
     RECT  0.067 64.134 0.103 64.152 ;
     RECT  0.031 10.566 0.131 10.854 ;
     RECT  0.103 25.146 0.139 25.164 ;
     RECT  0.103 58.086 0.175 58.104 ;
     RECT  0.103 59.04 0.175 59.058 ;
     RECT  0.139 68.076 0.175 68.094 ;
     RECT  0.067 61.938 0.203 61.956 ;
     RECT  0.103 16.776 0.211 16.794 ;
     RECT  0.175 58.086 0.239 59.058 ;
     RECT  0.139 20.511 0.571 20.529 ;
     RECT  0.175 68.076 0.571 68.634 ;
     RECT  0.139 25.101 0.599 25.164 ;
     RECT  0.239 58.086 0.823 58.374 ;
     RECT  0.103 63.756 0.823 64.152 ;
     RECT  0.211 16.038 1.111 16.794 ;
     RECT  0.571 26.496 1.111 26.514 ;
     RECT  0.103 19.476 1.147 19.494 ;
     RECT  0.571 20.286 1.147 20.529 ;
     RECT  0.599 25.146 1.147 25.164 ;
     RECT  0.823 63.756 1.147 64.224 ;
     RECT  1.147 25.146 1.175 25.236 ;
     RECT  0.823 57.888 1.687 58.374 ;
     RECT  0.571 11.376 1.723 11.394 ;
     RECT  1.687 57.888 1.723 58.644 ;
     RECT  1.111 15.606 1.759 16.794 ;
     RECT  1.147 19.476 1.759 20.529 ;
     RECT  0.131 10.566 2.16 10.584 ;
     RECT  1.723 11.376 2.16 11.844 ;
     RECT  1.723 14.616 2.16 14.634 ;
     RECT  1.759 15.426 2.16 16.794 ;
     RECT  1.759 19.476 2.16 20.574 ;
     RECT  0.103 21.636 2.16 21.654 ;
     RECT  1.175 25.218 2.16 25.236 ;
     RECT  1.111 26.136 2.16 26.514 ;
     RECT  1.723 57.888 2.16 58.914 ;
     RECT  1.147 63.756 2.16 64.314 ;
     RECT  0.571 68.076 2.16 68.706 ;
     RECT  0.571 69.768 2.16 69.786 ;
     RECT  0.211 74.016 2.16 74.034 ;
     RECT  2.16 2.151 95.04 95.049 ;
     RECT  95.04 25.758 95.207 25.884 ;
     RECT  95.04 27.954 95.531 29.754 ;
     RECT  95.04 13.266 95.747 17.946 ;
     RECT  95.04 18.846 95.747 20.718 ;
     RECT  95.04 26.676 95.747 26.694 ;
     RECT  95.207 25.866 95.783 25.884 ;
     RECT  95.04 61.776 96.287 70.794 ;
     RECT  95.747 13.266 96.323 17.604 ;
     RECT  96.287 61.776 96.323 69.984 ;
     RECT  96.323 13.266 96.359 16.326 ;
     RECT  96.323 61.776 96.359 69.786 ;
     RECT  96.359 65.448 96.395 67.896 ;
     RECT  95.04 22.626 96.431 25.002 ;
     RECT  96.395 65.448 96.431 67.392 ;
     RECT  96.359 61.776 96.467 64.314 ;
     RECT  96.467 61.776 96.503 63.27 ;
     RECT  96.467 64.134 96.503 64.314 ;
     RECT  96.359 13.266 96.539 15.174 ;
     RECT  96.503 62.478 96.611 63.27 ;
     RECT  96.539 13.536 96.647 15.084 ;
     RECT  95.04 71.586 96.863 73.494 ;
     RECT  95.531 28.188 96.899 29.754 ;
     RECT  95.747 19.746 96.935 20.718 ;
     RECT  96.431 22.626 96.971 24.498 ;
     RECT  96.899 28.188 96.971 29.484 ;
     RECT  95.747 18.846 97.007 18.864 ;
     RECT  96.971 28.188 97.007 29.214 ;
     RECT  96.323 17.154 97.043 17.604 ;
     RECT  96.431 65.448 97.043 67.284 ;
     RECT  96.359 68.994 97.043 69.786 ;
     RECT  96.863 71.586 97.043 73.224 ;
     RECT  96.935 19.746 97.079 20.574 ;
     RECT  96.971 22.626 97.079 22.806 ;
     RECT  96.971 23.634 97.079 24.498 ;
     RECT  97.007 28.386 97.079 29.214 ;
     RECT  97.043 65.646 97.079 67.284 ;
     RECT  97.043 71.586 97.079 73.134 ;
     RECT  96.647 13.536 97.115 13.554 ;
     RECT  96.647 14.616 97.115 15.084 ;
     RECT  97.043 17.154 97.115 17.514 ;
     RECT  97.079 20.016 97.115 20.574 ;
     RECT  97.079 23.634 97.115 24.156 ;
     RECT  97.079 28.386 97.115 28.404 ;
     RECT  96.611 62.586 97.115 63.27 ;
     RECT  97.079 65.718 97.115 67.122 ;
     RECT  97.043 68.994 97.115 69.444 ;
     RECT  96.287 70.776 97.115 70.794 ;
     RECT  97.079 71.928 97.115 72.684 ;
     RECT  97.115 14.616 97.151 14.859 ;
     RECT  97.079 22.788 97.151 22.806 ;
     RECT  97.115 24.138 97.151 24.156 ;
     RECT  97.115 17.154 97.187 17.172 ;
     RECT  97.115 20.556 97.187 20.574 ;
     RECT  97.087 26.676 97.187 26.694 ;
     RECT  97.079 29.196 97.187 29.214 ;
     RECT  97.115 62.586 97.187 62.604 ;
     RECT  97.087 64.791 97.187 64.809 ;
     RECT  97.115 69.426 97.187 69.444 ;
     RECT  97.115 71.928 97.187 71.946 ;
    LAYER M3 ;
     RECT  78.015 2.143 78.105 2.227 ;
     RECT  64.515 2.143 64.605 2.263 ;
     RECT  68.112 2.227 68.13 2.263 ;
     RECT  72.615 2.143 72.705 2.263 ;
     RECT  60.984 2.251 61.002 2.291 ;
     RECT  75.315 2.143 75.405 2.299 ;
     RECT  42.915 2.143 43.005 2.335 ;
     RECT  69.915 2.143 70.005 2.335 ;
     RECT  80.715 2.143 80.805 2.335 ;
     RECT  61.815 2.143 61.905 2.371 ;
     RECT  64.515 2.263 64.854 2.371 ;
     RECT  68.112 2.263 68.454 2.371 ;
     RECT  76.32 2.263 76.806 2.371 ;
     RECT  2.415 2.143 2.505 2.413 ;
     RECT  5.115 2.143 5.205 2.413 ;
     RECT  7.815 2.143 7.905 2.413 ;
     RECT  10.515 2.143 10.605 2.413 ;
     RECT  13.215 2.143 13.305 2.413 ;
     RECT  15.915 2.143 16.005 2.413 ;
     RECT  18.615 2.143 18.705 2.413 ;
     RECT  21.315 2.143 21.405 2.413 ;
     RECT  24.015 2.143 24.105 2.413 ;
     RECT  26.715 2.143 26.805 2.413 ;
     RECT  29.415 2.143 29.505 2.413 ;
     RECT  32.115 2.143 32.205 2.413 ;
     RECT  34.815 2.143 34.905 2.413 ;
     RECT  37.515 2.143 37.605 2.413 ;
     RECT  40.215 2.143 40.305 2.413 ;
     RECT  42.516 2.335 43.005 2.413 ;
     RECT  45.615 2.143 45.705 2.413 ;
     RECT  48.315 2.143 48.405 2.413 ;
     RECT  51.015 2.143 51.105 2.413 ;
     RECT  53.715 2.143 53.805 2.413 ;
     RECT  56.415 2.143 56.505 2.413 ;
     RECT  59.115 2.143 59.205 2.413 ;
     RECT  61.272 2.371 61.905 2.413 ;
     RECT  67.215 2.143 67.305 2.413 ;
     RECT  68.112 2.371 69.03 2.413 ;
     RECT  74.952 2.299 75.405 2.413 ;
     RECT  76.284 2.371 76.806 2.413 ;
     RECT  77.544 2.227 78.105 2.413 ;
     RECT  83.415 2.143 83.505 2.413 ;
     RECT  86.115 2.143 86.205 2.413 ;
     RECT  88.815 2.143 88.905 2.413 ;
     RECT  91.515 2.143 91.605 2.413 ;
     RECT  94.215 2.143 94.305 2.413 ;
     RECT  72.396 2.263 73.242 2.461 ;
     RECT  80.715 2.335 81.306 2.461 ;
     RECT  77.544 2.413 78.297 2.497 ;
     RECT  77.544 2.497 78.678 2.533 ;
     RECT  77.544 2.533 79.938 2.569 ;
     RECT  80.712 2.461 81.306 2.569 ;
     RECT  42.516 2.413 43.197 2.582 ;
     RECT  42.408 2.582 43.197 2.587 ;
     RECT  67.215 2.413 69.03 2.605 ;
     RECT  72.396 2.461 73.71 2.605 ;
     RECT  83.415 2.413 83.697 2.605 ;
     RECT  42.408 2.587 43.686 2.641 ;
     RECT  67.215 2.605 69.102 2.641 ;
     RECT  69.915 2.335 70.758 2.641 ;
     RECT  71.82 2.605 73.71 2.641 ;
     RECT  74.952 2.413 76.806 2.641 ;
     RECT  77.544 2.569 81.306 2.641 ;
     RECT  37.515 2.413 37.797 2.731 ;
     RECT  40.215 2.413 40.497 2.731 ;
     RECT  37.515 2.731 38.394 2.767 ;
     RECT  39.744 2.731 40.497 2.767 ;
     RECT  41.508 2.731 41.526 2.767 ;
     RECT  42.408 2.641 44.118 2.767 ;
     RECT  37.515 2.767 40.497 2.779 ;
     RECT  41.328 2.767 44.298 2.779 ;
     RECT  67.215 2.641 69.174 2.839 ;
     RECT  69.915 2.641 74.178 2.839 ;
     RECT  83.415 2.605 83.79 2.875 ;
     RECT  64.515 2.371 65.862 2.911 ;
     RECT  66.6 2.839 74.178 2.911 ;
     RECT  74.952 2.641 81.486 2.911 ;
     RECT  37.515 2.779 44.298 3.145 ;
     RECT  61.272 2.413 62.097 3.145 ;
     RECT  82.8 2.875 83.79 3.145 ;
     RECT  33.624 3.145 33.642 3.181 ;
     RECT  34.815 2.413 35.097 3.181 ;
     RECT  61.092 3.145 62.097 3.271 ;
     RECT  86.115 2.413 86.397 3.301 ;
     RECT  46.908 3.307 46.926 3.343 ;
     RECT  85.896 3.301 86.397 3.343 ;
     RECT  45.615 2.413 45.897 3.379 ;
     RECT  46.908 3.343 47.43 3.379 ;
     RECT  64.515 2.911 81.486 3.379 ;
     RECT  61.092 3.271 62.19 3.403 ;
     RECT  64.515 3.379 81.522 3.403 ;
     RECT  61.092 3.403 62.91 3.415 ;
     RECT  45.615 3.379 47.43 3.451 ;
     RECT  48.315 2.413 48.597 3.451 ;
     RECT  64.26 3.403 81.522 3.451 ;
     RECT  85.896 3.343 86.454 3.451 ;
     RECT  37.44 3.145 44.298 3.541 ;
     RECT  82.548 3.145 83.79 3.541 ;
     RECT  85.896 3.451 86.814 3.649 ;
     RECT  33.624 3.181 35.097 3.685 ;
     RECT  64.26 3.451 81.558 3.685 ;
     RECT  33.624 3.685 35.73 3.721 ;
     RECT  36.648 3.685 36.666 3.721 ;
     RECT  37.44 3.541 44.514 3.721 ;
     RECT  60.804 3.415 62.91 3.721 ;
     RECT  64.26 3.685 81.594 3.721 ;
     RECT  82.548 3.541 84.258 3.721 ;
     RECT  85.248 3.649 86.814 3.721 ;
     RECT  87.552 3.685 87.57 3.721 ;
     RECT  33.624 3.721 44.514 3.811 ;
     RECT  82.548 3.721 86.814 3.835 ;
     RECT  87.552 3.721 87.822 3.835 ;
     RECT  45.615 3.451 48.597 3.847 ;
     RECT  63.828 3.721 81.738 3.877 ;
     RECT  33.48 3.811 44.514 3.88 ;
     RECT  45.288 3.847 48.597 3.88 ;
     RECT  60.804 3.721 63.054 3.919 ;
     RECT  63.792 3.877 81.738 3.919 ;
     RECT  32.115 2.413 32.397 3.931 ;
     RECT  33.48 3.88 48.597 3.931 ;
     RECT  25.272 3.883 25.506 3.955 ;
     RECT  31.716 3.931 32.397 3.955 ;
     RECT  33.12 3.931 48.597 3.955 ;
     RECT  60.804 3.919 81.738 3.955 ;
     RECT  59.115 2.413 59.397 3.991 ;
     RECT  60.66 3.955 81.738 3.991 ;
     RECT  82.548 3.835 87.822 3.991 ;
     RECT  31.716 3.955 48.597 4.019 ;
     RECT  57.492 3.931 57.51 4.145 ;
     RECT  21.315 2.413 21.597 4.225 ;
     RECT  24.015 2.413 24.297 4.225 ;
     RECT  49.932 4.081 49.95 4.225 ;
     RECT  41.328 4.019 48.597 4.261 ;
     RECT  49.86 4.225 49.95 4.261 ;
     RECT  55.548 4.225 55.566 4.261 ;
     RECT  56.415 2.413 56.697 4.261 ;
     RECT  41.328 4.261 48.942 4.423 ;
     RECT  49.86 4.261 50.274 4.423 ;
     RECT  57.564 4.261 58.194 4.423 ;
     RECT  18.615 2.413 18.897 4.495 ;
     RECT  20.664 4.225 21.597 4.495 ;
     RECT  55.548 4.261 56.697 4.495 ;
     RECT  18.396 4.495 18.897 4.507 ;
     RECT  23.976 4.225 24.297 4.531 ;
     RECT  25.128 3.955 25.506 4.531 ;
     RECT  41.328 4.423 50.274 4.531 ;
     RECT  51.015 2.413 51.297 4.531 ;
     RECT  18.396 4.507 19.458 4.541 ;
     RECT  55.332 4.495 56.697 4.541 ;
     RECT  20.448 4.495 21.597 4.621 ;
     RECT  31.716 4.019 40.497 4.621 ;
     RECT  20.448 4.621 21.942 4.657 ;
     RECT  23.976 4.531 25.506 4.693 ;
     RECT  82.476 3.991 88.074 4.729 ;
     RECT  88.815 2.413 89.097 4.729 ;
     RECT  31.356 4.621 40.497 4.765 ;
     RECT  41.328 4.531 51.297 4.765 ;
     RECT  18.468 4.541 19.458 4.801 ;
     RECT  20.448 4.657 21.978 4.801 ;
     RECT  23.4 4.693 25.506 4.801 ;
     RECT  26.715 2.413 26.997 4.801 ;
     RECT  59.115 3.991 81.738 4.801 ;
     RECT  82.476 4.729 89.097 4.801 ;
     RECT  55.548 4.541 56.697 4.829 ;
     RECT  18.468 4.801 22.122 4.891 ;
     RECT  55.584 4.829 56.697 4.891 ;
     RECT  57.564 4.423 58.374 4.891 ;
     RECT  18.468 4.891 22.41 4.927 ;
     RECT  18.468 4.927 22.518 4.987 ;
     RECT  53.715 2.413 53.997 4.999 ;
     RECT  15.915 2.413 16.197 5.035 ;
     RECT  53.715 4.999 54.126 5.035 ;
     RECT  55.584 4.891 58.374 5.063 ;
     RECT  15.915 5.035 16.614 5.071 ;
     RECT  31.356 4.765 51.297 5.071 ;
     RECT  53.715 5.035 54.306 5.071 ;
     RECT  13.215 2.413 13.497 5.161 ;
     RECT  15.915 5.071 17.154 5.161 ;
     RECT  31.356 5.071 51.354 5.161 ;
     RECT  13.215 5.161 13.698 5.197 ;
     RECT  14.616 5.161 14.742 5.197 ;
     RECT  15.552 5.161 17.154 5.197 ;
     RECT  23.4 4.801 26.997 5.197 ;
     RECT  29.415 2.413 29.697 5.197 ;
     RECT  53.715 5.071 54.486 5.233 ;
     RECT  13.068 5.197 14.742 5.269 ;
     RECT  23.4 5.197 27.162 5.269 ;
     RECT  12.636 5.269 14.742 5.305 ;
     RECT  15.48 5.197 17.154 5.305 ;
     RECT  18.468 4.987 22.662 5.305 ;
     RECT  28.656 5.197 29.697 5.341 ;
     RECT  31.068 5.161 51.354 5.341 ;
     RECT  28.656 5.341 29.898 5.461 ;
     RECT  12.636 5.305 22.662 5.515 ;
     RECT  23.4 5.269 27.198 5.515 ;
     RECT  12.636 5.515 27.198 5.539 ;
     RECT  28.548 5.461 29.898 5.539 ;
     RECT  30.636 5.341 51.354 5.539 ;
     RECT  12.636 5.539 27.774 5.575 ;
     RECT  28.548 5.539 51.354 5.575 ;
     RECT  53.715 5.233 54.702 5.611 ;
     RECT  53.715 5.611 54.738 5.773 ;
     RECT  52.164 5.233 52.182 5.809 ;
     RECT  55.62 5.063 58.374 5.809 ;
     RECT  59.115 4.801 89.097 5.809 ;
     RECT  10.515 2.413 10.797 5.845 ;
     RECT  10.515 5.845 11.25 5.881 ;
     RECT  12.636 5.575 51.354 5.881 ;
     RECT  52.164 5.809 52.254 5.881 ;
     RECT  9.684 5.881 52.254 6.007 ;
     RECT  53.715 5.773 54.846 6.007 ;
     RECT  9.684 6.007 54.846 6.151 ;
     RECT  55.62 5.809 89.097 6.151 ;
     RECT  7.815 2.413 8.097 6.235 ;
     RECT  9.684 6.151 89.097 6.235 ;
     RECT  7.815 6.235 8.442 6.421 ;
     RECT  9.54 6.235 89.097 6.421 ;
     RECT  90.288 6.889 90.306 6.925 ;
     RECT  90.144 6.925 90.306 6.961 ;
     RECT  7.815 6.421 89.097 7.051 ;
     RECT  90.144 6.961 90.63 7.051 ;
     RECT  7.815 7.051 90.63 7.187 ;
     RECT  7.815 7.187 68.778 7.223 ;
     RECT  69.588 7.187 90.63 7.231 ;
     RECT  91.515 2.413 91.797 7.231 ;
     RECT  7.815 7.223 68.706 7.925 ;
     RECT  63.864 7.925 68.706 7.969 ;
     RECT  69.588 7.231 91.797 7.969 ;
     RECT  7.815 7.925 63.054 7.997 ;
     RECT  7.815 7.997 26.997 8.155 ;
     RECT  27.72 7.997 63.054 8.707 ;
     RECT  63.864 7.969 91.797 8.707 ;
     RECT  6.192 8.443 6.21 8.851 ;
     RECT  7.128 8.155 26.997 8.851 ;
     RECT  5.115 2.413 5.397 9.283 ;
     RECT  6.192 8.851 26.997 9.283 ;
     RECT  5.115 9.283 26.997 9.625 ;
     RECT  27.72 8.707 91.797 9.625 ;
     RECT  2.415 2.413 2.697 10.201 ;
     RECT  5.115 9.625 91.797 10.399 ;
     RECT  2.415 10.201 3.438 10.435 ;
     RECT  2.415 10.435 3.474 10.471 ;
     RECT  2.415 10.471 4.014 10.705 ;
     RECT  0.036 10.561 0.054 10.831 ;
     RECT  0.036 10.831 0.126 10.859 ;
     RECT  2.376 10.705 4.014 10.939 ;
     RECT  5.076 10.399 91.797 10.939 ;
     RECT  2.34 10.939 4.014 10.975 ;
     RECT  2.304 10.975 4.014 10.987 ;
     RECT  4.86 10.939 91.797 10.987 ;
     RECT  0.108 10.859 0.126 11.179 ;
     RECT  2.304 10.987 91.797 11.245 ;
     RECT  0.108 11.179 0.162 11.371 ;
     RECT  2.304 11.245 91.998 11.821 ;
     RECT  0.108 11.371 0.594 12.125 ;
     RECT  1.728 11.821 91.998 12.361 ;
     RECT  0.144 12.125 0.594 12.413 ;
     RECT  0.576 12.413 0.594 12.557 ;
     RECT  1.728 12.361 92.214 12.701 ;
     RECT  2.304 12.701 92.214 12.901 ;
     RECT  0.144 13.147 0.162 13.277 ;
     RECT  94.215 2.413 94.497 13.405 ;
     RECT  96.516 13.261 96.534 13.441 ;
     RECT  2.304 12.901 93.006 13.531 ;
     RECT  94.215 13.405 94.77 13.531 ;
     RECT  96.444 13.441 96.534 13.531 ;
     RECT  96.444 13.531 97.11 13.603 ;
     RECT  1.728 13.531 94.806 13.631 ;
     RECT  96.372 13.603 97.11 14.215 ;
     RECT  1.728 13.631 94.77 14.251 ;
     RECT  0.108 13.819 0.126 14.395 ;
     RECT  0.108 14.395 0.162 14.539 ;
     RECT  96.336 14.215 97.11 14.611 ;
     RECT  1.152 14.251 94.77 14.683 ;
     RECT  96.336 14.611 97.146 14.864 ;
     RECT  0.108 14.539 0.234 14.971 ;
     RECT  1.116 14.683 94.77 14.971 ;
     RECT  96.336 14.864 97.11 15.149 ;
     RECT  0.108 14.971 94.77 15.295 ;
     RECT  0.108 15.295 94.806 15.449 ;
     RECT  0.108 15.449 1.134 15.629 ;
     RECT  96.372 15.149 97.11 15.869 ;
     RECT  96.372 15.869 97.074 15.871 ;
     RECT  0.108 15.629 0.594 16.259 ;
     RECT  96.336 15.871 97.074 16.267 ;
     RECT  2.304 15.449 94.806 16.367 ;
     RECT  2.304 16.367 94.698 16.529 ;
     RECT  2.304 16.529 94.59 16.601 ;
     RECT  96.3 16.267 97.074 16.699 ;
     RECT  0.108 16.259 0.126 16.799 ;
     RECT  2.376 16.601 94.59 16.943 ;
     RECT  96.3 16.699 97.11 17.069 ;
     RECT  97.02 17.069 97.11 17.149 ;
     RECT  2.415 16.943 94.59 17.455 ;
     RECT  2.415 17.455 94.698 17.653 ;
     RECT  95.724 17.851 95.742 17.951 ;
     RECT  97.02 17.149 97.182 17.995 ;
     RECT  2.415 17.653 94.806 18.149 ;
     RECT  96.948 17.995 97.182 18.283 ;
     RECT  96.876 18.283 97.182 18.427 ;
     RECT  2.415 18.149 54.738 18.461 ;
     RECT  55.476 18.149 94.806 18.769 ;
     RECT  95.724 18.859 95.742 19.031 ;
     RECT  2.415 18.461 54.702 19.243 ;
     RECT  2.415 19.243 54.738 19.615 ;
     RECT  2.376 19.615 54.738 19.849 ;
     RECT  55.476 18.769 94.878 19.849 ;
     RECT  2.376 19.849 94.878 19.885 ;
     RECT  2.34 19.885 94.878 20.011 ;
     RECT  0.108 19.471 0.126 20.281 ;
     RECT  1.152 19.741 1.17 20.281 ;
     RECT  2.268 20.011 94.878 20.417 ;
     RECT  96.804 18.427 97.182 20.417 ;
     RECT  0.108 20.281 1.17 20.461 ;
     RECT  2.268 20.417 93.402 20.461 ;
     RECT  0.108 20.461 93.402 20.534 ;
     RECT  96.912 20.417 97.182 20.579 ;
     RECT  94.215 20.417 94.878 20.651 ;
     RECT  94.215 20.651 94.734 20.723 ;
     RECT  96.912 20.579 96.93 20.723 ;
     RECT  0.108 20.534 0.594 20.765 ;
     RECT  1.728 20.534 93.402 21.119 ;
     RECT  0.144 20.765 0.594 21.341 ;
     RECT  1.728 21.119 92.79 21.629 ;
     RECT  0.144 21.341 0.198 21.631 ;
     RECT  1.764 21.629 92.79 21.659 ;
     RECT  0.108 21.631 0.198 21.773 ;
     RECT  2.304 21.659 92.79 22.219 ;
     RECT  2.304 22.219 93.078 22.441 ;
     RECT  0.144 21.773 0.198 22.603 ;
     RECT  2.304 22.441 93.366 22.621 ;
     RECT  94.215 20.723 94.497 22.621 ;
     RECT  0.144 22.603 0.342 22.781 ;
     RECT  2.304 22.621 94.662 22.783 ;
     RECT  97.056 22.621 97.074 22.783 ;
     RECT  97.056 22.783 97.146 22.891 ;
     RECT  96.372 22.891 97.146 22.981 ;
     RECT  2.304 22.783 94.806 23.279 ;
     RECT  2.34 23.279 94.806 23.387 ;
     RECT  0.144 22.781 0.162 23.611 ;
     RECT  2.376 23.387 94.806 23.701 ;
     RECT  2.376 23.701 95.202 23.789 ;
     RECT  96.336 22.981 97.146 24.161 ;
     RECT  2.376 23.789 94.842 24.241 ;
     RECT  2.304 24.241 94.842 24.331 ;
     RECT  2.268 24.331 94.842 24.368 ;
     RECT  96.336 24.161 97.11 24.509 ;
     RECT  0.108 23.611 0.162 24.763 ;
     RECT  0.108 24.763 0.342 25.096 ;
     RECT  1.116 24.187 1.134 25.096 ;
     RECT  0.108 25.096 1.134 25.141 ;
     RECT  0.108 25.141 1.17 25.169 ;
     RECT  0.576 25.169 1.17 25.241 ;
     RECT  96.336 24.509 97.074 25.517 ;
     RECT  2.304 24.368 94.842 25.753 ;
     RECT  2.304 25.753 95.202 25.861 ;
     RECT  96.336 25.517 96.426 25.861 ;
     RECT  2.304 25.861 96.426 25.979 ;
     RECT  95.436 25.979 96.426 26.093 ;
     RECT  0.576 25.241 1.134 26.159 ;
     RECT  2.304 25.979 94.662 26.393 ;
     RECT  0.576 26.159 0.594 26.519 ;
     RECT  97.092 26.635 97.11 26.671 ;
     RECT  95.436 26.093 95.742 26.699 ;
     RECT  2.415 26.393 94.662 26.761 ;
     RECT  95.436 26.699 95.526 26.761 ;
     RECT  97.092 26.671 97.182 26.923 ;
     RECT  97.056 26.923 97.182 27.067 ;
     RECT  97.02 27.067 97.182 27.211 ;
     RECT  96.984 27.211 97.182 27.355 ;
     RECT  96.948 27.355 97.182 27.499 ;
     RECT  96.912 27.499 97.182 27.643 ;
     RECT  96.876 27.643 97.182 27.787 ;
     RECT  96.84 27.787 97.182 27.931 ;
     RECT  2.415 26.761 95.526 27.977 ;
     RECT  96.804 27.931 97.182 28.075 ;
     RECT  96.768 28.075 97.182 28.219 ;
     RECT  96.3 28.219 97.182 28.949 ;
     RECT  96.804 28.949 97.182 29.219 ;
     RECT  96.804 29.219 96.966 29.327 ;
     RECT  2.415 27.977 95.454 29.399 ;
     RECT  96.876 29.327 96.966 29.489 ;
     RECT  2.415 29.399 94.806 29.525 ;
     RECT  2.415 29.525 94.734 29.633 ;
     RECT  96.876 29.489 96.894 29.759 ;
     RECT  2.415 29.633 94.497 30.415 ;
     RECT  2.376 30.415 94.497 31.805 ;
     RECT  74.088 31.805 94.497 32.071 ;
     RECT  74.088 32.071 94.914 32.333 ;
     RECT  2.376 31.805 73.314 32.459 ;
     RECT  2.415 32.459 73.314 32.773 ;
     RECT  74.088 32.333 94.59 32.773 ;
     RECT  2.415 32.773 94.59 33.349 ;
     RECT  2.415 33.349 94.662 33.539 ;
     RECT  2.415 33.539 94.59 34.087 ;
     RECT  2.376 34.087 94.59 34.115 ;
     RECT  2.376 34.115 94.554 34.349 ;
     RECT  2.415 34.349 94.554 35.735 ;
     RECT  2.415 35.735 94.497 36.553 ;
     RECT  2.376 36.553 94.497 36.815 ;
     RECT  2.415 36.815 94.497 37.049 ;
     RECT  86.076 37.049 94.497 37.165 ;
     RECT  86.076 37.165 94.662 37.705 ;
     RECT  86.076 37.705 94.914 37.859 ;
     RECT  2.415 37.049 85.266 37.861 ;
     RECT  86.076 37.859 94.497 37.861 ;
     RECT  2.415 37.861 94.497 38.281 ;
     RECT  2.376 38.281 94.497 39.515 ;
     RECT  7.815 39.515 94.497 39.631 ;
     RECT  7.815 39.631 94.554 39.721 ;
     RECT  2.376 39.515 7.074 39.857 ;
     RECT  7.815 39.721 94.662 39.857 ;
     RECT  7.815 39.857 94.554 40.531 ;
     RECT  7.776 40.531 94.554 40.801 ;
     RECT  7.776 40.801 94.626 40.873 ;
     RECT  2.376 39.857 7.038 41.035 ;
     RECT  7.776 40.873 94.662 41.035 ;
     RECT  2.376 41.035 94.662 41.485 ;
     RECT  2.376 41.485 94.914 41.513 ;
     RECT  2.415 41.513 94.914 41.909 ;
     RECT  2.415 41.909 94.626 43.871 ;
     RECT  2.415 43.871 94.554 44.447 ;
     RECT  38.52 44.447 94.554 45.229 ;
     RECT  2.415 44.447 37.797 45.265 ;
     RECT  38.52 45.229 94.626 45.265 ;
     RECT  2.415 45.265 94.626 45.329 ;
     RECT  2.415 45.329 94.497 46.541 ;
     RECT  4.392 46.541 94.497 46.651 ;
     RECT  2.415 46.541 3.618 46.813 ;
     RECT  4.392 46.651 94.626 46.877 ;
     RECT  2.34 46.813 3.618 47.281 ;
     RECT  4.392 46.877 94.497 47.281 ;
     RECT  2.34 47.281 94.497 48.001 ;
     RECT  2.34 48.001 94.914 48.227 ;
     RECT  2.34 48.227 94.662 48.461 ;
     RECT  2.34 48.461 94.497 49.351 ;
     RECT  2.34 49.351 94.554 49.541 ;
     RECT  2.415 49.541 94.554 49.819 ;
     RECT  2.415 49.819 94.662 50.009 ;
     RECT  2.415 50.009 94.554 50.117 ;
     RECT  7.488 50.117 94.554 50.153 ;
     RECT  7.524 50.153 94.554 50.189 ;
     RECT  66.312 50.189 94.554 50.819 ;
     RECT  7.524 50.189 65.574 50.971 ;
     RECT  7.488 50.971 65.574 51.061 ;
     RECT  66.312 50.819 94.497 51.061 ;
     RECT  2.415 50.117 6.75 51.355 ;
     RECT  7.488 51.061 94.497 51.355 ;
     RECT  2.415 51.355 94.497 52.301 ;
     RECT  2.415 52.301 57.798 53.023 ;
     RECT  58.536 52.301 94.497 53.023 ;
     RECT  2.415 53.023 94.497 54.125 ;
     RECT  58.5 54.125 94.497 54.445 ;
     RECT  58.5 54.445 94.626 54.599 ;
     RECT  2.415 54.125 57.726 54.985 ;
     RECT  58.5 54.599 94.497 54.985 ;
     RECT  2.415 54.985 94.497 56.767 ;
     RECT  0.828 57.883 0.846 58.081 ;
     RECT  2.376 56.767 94.497 58.117 ;
     RECT  2.304 58.117 94.497 58.621 ;
     RECT  0.108 58.081 0.846 59.063 ;
     RECT  0.144 59.063 0.846 59.645 ;
     RECT  1.692 58.621 94.497 59.933 ;
     RECT  0.828 59.645 0.846 60.077 ;
     RECT  1.728 59.933 94.497 60.151 ;
     RECT  1.728 60.151 94.914 60.341 ;
     RECT  1.728 60.341 93.402 60.365 ;
     RECT  2.304 60.365 93.402 60.413 ;
     RECT  94.14 60.341 94.914 60.413 ;
     RECT  94.14 60.413 94.497 60.575 ;
     RECT  1.152 60.763 1.17 60.893 ;
     RECT  2.304 60.413 93.258 61.465 ;
     RECT  0.108 61.051 0.126 61.483 ;
     RECT  2.304 61.465 93.366 61.501 ;
     RECT  94.176 60.575 94.497 61.501 ;
     RECT  2.304 61.501 94.497 61.699 ;
     RECT  96.48 61.771 96.498 61.861 ;
     RECT  0.108 61.483 0.846 61.933 ;
     RECT  2.304 61.699 94.626 62.275 ;
     RECT  96.372 61.861 96.498 62.473 ;
     RECT  0.072 61.933 0.846 62.491 ;
     RECT  2.304 62.275 94.734 62.545 ;
     RECT  96.372 62.473 96.606 62.581 ;
     RECT  96.372 62.581 97.182 62.671 ;
     RECT  2.304 62.545 94.806 62.699 ;
     RECT  2.304 62.699 94.734 63.239 ;
     RECT  2.34 63.239 94.734 63.509 ;
     RECT  0.072 62.491 0.918 63.779 ;
     RECT  0.828 63.779 0.918 63.931 ;
     RECT  0.072 63.779 0.09 64.157 ;
     RECT  0.828 63.931 1.17 64.229 ;
     RECT  1.152 64.229 1.17 64.319 ;
     RECT  2.34 63.509 94.698 64.435 ;
     RECT  2.34 64.435 94.734 64.471 ;
     RECT  2.304 64.471 94.734 64.589 ;
     RECT  96.336 62.671 97.182 64.814 ;
     RECT  2.304 64.589 94.698 64.895 ;
     RECT  96.336 64.814 97.11 64.939 ;
     RECT  2.415 64.895 94.698 65.515 ;
     RECT  2.415 65.515 94.734 65.641 ;
     RECT  2.376 65.641 94.734 65.741 ;
     RECT  2.415 65.741 94.734 66.289 ;
     RECT  2.415 66.289 95.202 66.701 ;
     RECT  96.3 64.939 97.11 67.127 ;
     RECT  96.3 67.127 97.074 67.289 ;
     RECT  2.415 66.701 94.95 68.215 ;
     RECT  96.3 67.289 96.426 68.285 ;
     RECT  0.144 68.071 0.162 68.611 ;
     RECT  0.144 68.611 0.198 68.683 ;
     RECT  2.376 68.215 94.95 68.683 ;
     RECT  0.144 68.683 0.594 68.731 ;
     RECT  0.108 68.731 0.594 68.861 ;
     RECT  2.376 68.683 95.454 68.917 ;
     RECT  2.34 68.917 95.454 69.061 ;
     RECT  96.3 68.285 96.354 69.148 ;
     RECT  97.092 68.827 97.11 69.148 ;
     RECT  96.3 69.148 97.11 69.421 ;
     RECT  0.144 68.861 0.594 69.437 ;
     RECT  2.268 69.061 95.454 69.725 ;
     RECT  96.3 69.421 97.182 69.979 ;
     RECT  0.18 69.437 0.594 70.157 ;
     RECT  2.304 69.725 95.454 70.411 ;
     RECT  96.264 69.979 97.182 70.411 ;
     RECT  2.304 70.411 97.182 70.448 ;
     RECT  96.264 70.448 97.182 70.529 ;
     RECT  0.576 70.157 0.594 70.733 ;
     RECT  2.304 70.448 95.454 71.419 ;
     RECT  96.336 70.529 97.182 71.419 ;
     RECT  2.304 71.419 97.182 71.951 ;
     RECT  0.144 70.891 0.162 71.995 ;
     RECT  2.304 71.951 97.11 72.509 ;
     RECT  95.724 72.509 97.11 72.563 ;
     RECT  96.84 72.563 97.11 72.689 ;
     RECT  0.144 71.995 0.234 72.797 ;
     RECT  2.304 72.509 94.914 72.859 ;
     RECT  96.84 72.689 97.074 73.139 ;
     RECT  96.84 73.139 97.038 73.229 ;
     RECT  95.724 72.563 95.742 73.337 ;
     RECT  96.84 73.229 96.858 73.499 ;
     RECT  2.268 72.859 94.914 73.607 ;
     RECT  2.304 73.607 94.914 73.769 ;
     RECT  2.304 73.769 94.59 73.805 ;
     RECT  0.216 72.797 0.234 74.039 ;
     RECT  2.304 73.805 94.497 74.579 ;
     RECT  2.415 74.579 94.497 74.659 ;
     RECT  2.415 74.659 94.59 75.469 ;
     RECT  2.415 75.469 94.626 76.081 ;
     RECT  2.415 76.081 94.914 76.343 ;
     RECT  2.415 76.343 94.734 76.747 ;
     RECT  2.376 76.747 94.734 77.351 ;
     RECT  2.376 77.351 94.59 78.269 ;
     RECT  2.415 78.269 94.59 78.367 ;
     RECT  2.415 78.367 94.662 79.439 ;
     RECT  2.415 79.439 94.554 79.709 ;
     RECT  2.415 79.709 94.497 80.671 ;
     RECT  2.415 80.671 94.734 81.059 ;
     RECT  2.415 81.059 94.626 81.869 ;
     RECT  2.415 81.869 94.497 82.831 ;
     RECT  2.376 82.831 94.497 82.993 ;
     RECT  2.376 82.993 94.662 83.093 ;
     RECT  2.415 83.093 94.662 83.219 ;
     RECT  2.415 83.219 94.554 84.649 ;
     RECT  2.415 84.649 94.662 84.749 ;
     RECT  2.415 84.749 94.497 88.889 ;
     RECT  2.415 88.889 93.186 88.931 ;
     RECT  2.415 88.931 92.826 89.231 ;
     RECT  2.415 89.231 92.574 89.501 ;
     RECT  92.556 89.501 92.574 89.699 ;
     RECT  2.415 89.501 91.797 89.735 ;
     RECT  2.415 89.735 5.397 89.969 ;
     RECT  2.415 89.969 3.078 90.005 ;
     RECT  6.372 89.735 91.797 90.239 ;
     RECT  6.372 90.239 90.45 90.275 ;
     RECT  6.372 90.275 89.982 90.617 ;
     RECT  6.372 90.617 89.442 91.085 ;
     RECT  6.372 91.085 6.858 91.319 ;
     RECT  7.596 91.085 89.442 91.319 ;
     RECT  7.596 91.319 89.37 91.589 ;
     RECT  6.696 91.319 6.714 91.613 ;
     RECT  7.596 91.589 8.19 91.625 ;
     RECT  7.815 91.625 8.19 91.697 ;
     RECT  9.108 91.589 89.37 91.859 ;
     RECT  71.028 91.859 89.262 91.895 ;
     RECT  9.108 91.859 70.29 91.931 ;
     RECT  9.108 91.931 70.254 92.129 ;
     RECT  71.028 91.895 89.226 92.165 ;
     RECT  9.108 92.129 70.197 92.333 ;
     RECT  71.028 92.165 71.37 92.399 ;
     RECT  72.144 92.165 89.226 92.399 ;
     RECT  9.756 92.333 70.197 92.543 ;
     RECT  72.144 92.399 89.154 92.579 ;
     RECT  10.044 92.543 70.197 92.669 ;
     RECT  71.028 92.399 71.298 92.669 ;
     RECT  72.144 92.579 89.097 93.209 ;
     RECT  10.368 92.669 70.197 93.289 ;
     RECT  10.368 93.289 70.362 93.353 ;
     RECT  45.615 93.353 70.362 93.389 ;
     RECT  10.368 93.353 44.838 93.479 ;
     RECT  45.615 93.389 70.197 93.479 ;
     RECT  10.368 93.479 20.466 93.623 ;
     RECT  41.724 93.479 44.838 93.623 ;
     RECT  22.68 93.479 40.878 93.659 ;
     RECT  41.724 93.623 44.694 93.659 ;
     RECT  10.368 93.623 20.214 93.725 ;
     RECT  10.404 93.725 20.214 93.749 ;
     RECT  23.328 93.659 40.878 93.749 ;
     RECT  10.404 93.749 19.458 93.857 ;
     RECT  45.615 93.479 65.538 93.893 ;
     RECT  20.196 93.749 20.214 94.019 ;
     RECT  23.328 93.749 40.77 94.019 ;
     RECT  66.42 93.479 70.197 94.019 ;
     RECT  23.328 94.019 24.534 94.061 ;
     RECT  38.772 94.019 40.77 94.199 ;
     RECT  66.42 94.019 68.238 94.289 ;
     RECT  69.156 94.019 70.197 94.289 ;
     RECT  10.476 93.857 19.458 94.349 ;
     RECT  45.615 93.893 65.286 94.361 ;
     RECT  41.796 93.659 44.694 94.397 ;
     RECT  46.656 94.361 65.286 94.397 ;
     RECT  69.768 94.289 70.197 94.433 ;
     RECT  72.252 93.209 89.097 94.469 ;
     RECT  41.796 94.397 43.902 94.541 ;
     RECT  10.512 94.349 19.458 94.559 ;
     RECT  25.524 94.019 37.797 94.559 ;
     RECT  38.808 94.199 40.77 94.559 ;
     RECT  41.94 94.541 43.902 94.559 ;
     RECT  52.236 94.397 65.286 94.559 ;
     RECT  67.14 94.289 67.554 94.559 ;
     RECT  72.615 94.469 89.097 94.559 ;
     RECT  52.236 94.559 62.586 94.589 ;
     RECT  10.512 94.559 18.99 94.595 ;
     RECT  25.524 94.559 25.542 94.595 ;
     RECT  36.216 94.559 36.234 94.595 ;
     RECT  38.808 94.559 38.826 94.595 ;
     RECT  40.032 94.559 40.497 94.595 ;
     RECT  41.94 94.559 41.958 94.595 ;
     RECT  46.656 94.397 51.39 94.595 ;
     RECT  63.648 94.559 63.666 94.595 ;
     RECT  72.615 94.559 87.462 94.595 ;
     RECT  26.388 94.559 35.334 94.631 ;
     RECT  50.004 94.595 51.39 94.631 ;
     RECT  67.215 94.559 67.554 94.631 ;
     RECT  42.732 94.559 43.902 94.637 ;
     RECT  69.915 94.433 70.197 94.699 ;
     RECT  17.568 94.595 18.99 94.703 ;
     RECT  26.496 94.631 35.334 94.739 ;
     RECT  42.84 94.637 43.902 94.739 ;
     RECT  2.415 90.005 2.697 94.787 ;
     RECT  5.115 89.969 5.397 94.787 ;
     RECT  7.815 91.697 8.097 94.787 ;
     RECT  21.315 93.479 21.597 94.787 ;
     RECT  24.015 94.061 24.297 94.787 ;
     RECT  37.515 94.559 37.797 94.787 ;
     RECT  40.215 94.595 40.497 94.787 ;
     RECT  45.615 94.361 45.897 94.787 ;
     RECT  50.004 94.631 51.297 94.787 ;
     RECT  52.236 94.589 62.097 94.787 ;
     RECT  67.215 94.631 67.497 94.787 ;
     RECT  88.815 94.559 89.097 94.787 ;
     RECT  91.515 90.239 91.797 94.787 ;
     RECT  94.215 88.889 94.497 94.787 ;
     RECT  10.512 94.595 16.65 94.829 ;
     RECT  17.568 94.703 18.954 94.829 ;
     RECT  26.496 94.739 34.038 94.829 ;
     RECT  34.776 94.739 35.334 94.829 ;
     RECT  42.915 94.739 43.902 94.829 ;
     RECT  44.676 94.397 44.694 94.829 ;
     RECT  46.656 94.595 48.942 94.829 ;
     RECT  50.004 94.787 51.105 94.829 ;
     RECT  52.236 94.787 61.905 94.829 ;
     RECT  64.476 94.559 65.178 94.829 ;
     RECT  72.615 94.595 84.978 94.829 ;
     RECT  86.115 94.595 87.174 94.829 ;
     RECT  17.676 94.829 18.774 94.865 ;
     RECT  26.496 94.829 26.874 94.865 ;
     RECT  28.44 94.829 32.922 94.865 ;
     RECT  52.236 94.829 52.29 94.865 ;
     RECT  72.615 94.829 79.902 94.865 ;
     RECT  81.792 94.829 81.81 94.865 ;
     RECT  83.088 94.829 83.505 94.865 ;
     RECT  84.384 94.829 84.402 94.865 ;
     RECT  46.656 94.829 46.782 94.877 ;
     RECT  47.988 94.829 48.405 94.877 ;
     RECT  50.004 94.829 50.022 94.877 ;
     RECT  52.236 94.865 52.254 94.877 ;
     RECT  69.915 94.699 70.29 94.877 ;
     RECT  53.532 94.829 56.754 94.901 ;
     RECT  77.364 94.865 79.902 94.901 ;
     RECT  11.844 94.829 16.506 94.937 ;
     RECT  34.815 94.829 35.298 94.937 ;
     RECT  86.115 94.829 86.67 94.937 ;
     RECT  29.088 94.865 32.922 94.973 ;
     RECT  46.764 94.877 46.782 94.973 ;
     RECT  57.636 94.829 60.102 94.973 ;
     RECT  60.948 94.829 60.966 94.973 ;
     RECT  17.676 94.865 17.694 95.009 ;
     RECT  56.34 94.901 56.505 95.009 ;
     RECT  57.636 94.973 59.205 95.009 ;
     RECT  60.084 94.973 60.102 95.009 ;
     RECT  77.364 94.901 79.218 95.009 ;
     RECT  72.615 94.865 75.405 95.021 ;
     RECT  2.415 94.787 2.505 95.057 ;
     RECT  5.115 94.787 5.205 95.057 ;
     RECT  7.815 94.787 7.905 95.057 ;
     RECT  10.515 94.829 10.71 95.057 ;
     RECT  18.615 94.865 18.705 95.057 ;
     RECT  21.315 94.787 21.405 95.057 ;
     RECT  24.015 94.787 24.105 95.057 ;
     RECT  26.715 94.865 26.805 95.057 ;
     RECT  29.415 94.973 32.706 95.057 ;
     RECT  34.815 94.937 35.154 95.057 ;
     RECT  37.515 94.787 37.605 95.057 ;
     RECT  40.215 94.787 40.305 95.057 ;
     RECT  42.915 94.829 43.005 95.057 ;
     RECT  45.615 94.787 45.705 95.057 ;
     RECT  48.315 94.877 48.405 95.057 ;
     RECT  51.015 94.829 51.105 95.057 ;
     RECT  56.415 95.009 56.505 95.057 ;
     RECT  58.068 95.009 59.205 95.057 ;
     RECT  61.815 94.829 61.905 95.057 ;
     RECT  64.515 94.829 64.605 95.057 ;
     RECT  67.215 94.787 67.305 95.057 ;
     RECT  69.915 94.877 70.005 95.057 ;
     RECT  72.615 95.021 72.705 95.057 ;
     RECT  73.548 95.021 75.405 95.057 ;
     RECT  77.364 95.009 78.105 95.057 ;
     RECT  80.715 94.829 80.805 95.057 ;
     RECT  83.415 94.865 83.505 95.057 ;
     RECT  86.115 94.937 86.205 95.057 ;
     RECT  88.815 94.787 88.905 95.057 ;
     RECT  91.515 94.787 91.605 95.057 ;
     RECT  94.215 94.787 94.305 95.057 ;
     RECT  11.844 94.937 16.11 95.165 ;
     RECT  33.768 94.829 34.038 95.165 ;
     RECT  58.068 95.057 58.698 95.165 ;
     RECT  73.548 95.057 74.862 95.165 ;
     RECT  77.364 95.057 77.706 95.165 ;
     RECT  10.692 95.057 10.71 95.213 ;
     RECT  11.844 95.165 13.194 95.213 ;
     RECT  29.556 95.057 32.706 95.213 ;
     RECT  74.592 95.165 74.862 95.213 ;
     RECT  12.78 95.213 13.194 95.261 ;
     RECT  16.092 95.165 16.11 96.365 ;
     RECT  29.556 95.213 32.634 96.365 ;
     RECT  53.532 94.901 55.458 96.365 ;
     RECT  73.548 95.165 73.602 96.365 ;
     RECT  29.736 96.365 32.094 96.413 ;
     RECT  29.772 96.413 32.094 96.461 ;
     RECT  73.584 96.365 73.602 96.461 ;
     RECT  29.772 96.461 30.186 96.509 ;
     RECT  31.428 96.461 32.094 96.845 ;
     RECT  33.768 95.165 33.786 96.845 ;
     RECT  76.248 94.865 76.518 96.845 ;
     RECT  12.78 95.261 12.942 97.037 ;
     RECT  14.256 95.165 14.958 97.037 ;
     RECT  11.844 95.213 11.862 97.085 ;
     RECT  12.924 97.037 12.942 97.085 ;
     RECT  14.328 97.037 14.958 97.085 ;
     RECT  30.168 96.509 30.186 97.085 ;
     RECT  31.428 96.845 31.446 97.085 ;
     RECT  35.136 95.057 35.154 97.085 ;
     RECT  54.144 96.365 55.458 97.085 ;
     RECT  58.248 95.165 58.266 97.085 ;
     RECT  74.844 95.213 74.862 97.085 ;
     RECT  76.5 96.845 76.518 97.085 ;
     RECT  77.364 95.165 77.382 97.085 ;
     RECT  79.2 95.009 79.218 97.085 ;
    LAYER M4 ;
     RECT  0.084 68.832 0.097 68.856 ;
     RECT  0.06 68.856 0.097 68.976 ;
     RECT  0.084 68.976 0.097 69 ;
     RECT  0.06 69 0.097 69.12 ;
     RECT  0.084 69.12 0.097 69.144 ;
     RECT  0.06 69.144 0.097 69.264 ;
     RECT  0.084 69.264 0.097 69.288 ;
     RECT  0.06 69.288 0.097 69.408 ;
     RECT  0.084 69.408 0.097 69.432 ;
     RECT  0.06 69.432 0.097 69.552 ;
     RECT  0.084 69.552 0.097 69.576 ;
     RECT  0.06 69.576 0.097 69.696 ;
     RECT  0.084 69.696 0.097 69.72 ;
     RECT  0.06 69.72 0.097 69.84 ;
     RECT  0.084 69.84 0.097 69.864 ;
     RECT  0.06 69.864 0.097 69.984 ;
     RECT  0.084 69.984 0.097 70.008 ;
     RECT  0.06 70.008 0.097 70.128 ;
     RECT  0.084 70.128 0.097 70.152 ;
     RECT  0.06 70.152 0.097 70.272 ;
     RECT  0.084 70.272 0.097 70.296 ;
     RECT  0.06 70.296 0.097 70.416 ;
     RECT  0.084 70.416 0.097 70.44 ;
     RECT  0.06 70.44 0.097 70.56 ;
     RECT  0.084 70.56 0.097 70.584 ;
     RECT  0.06 70.584 0.097 70.704 ;
     RECT  0.084 70.704 0.097 70.728 ;
     RECT  0.06 70.728 0.097 70.848 ;
     RECT  0.084 70.848 0.097 70.872 ;
     RECT  0.06 70.872 0.097 70.992 ;
     RECT  0.084 70.992 0.097 71.016 ;
     RECT  0.06 71.016 0.097 71.136 ;
     RECT  0.084 71.136 0.097 71.16 ;
     RECT  0.06 71.16 0.097 71.28 ;
     RECT  0.084 71.28 0.097 71.304 ;
     RECT  0.06 71.304 0.097 71.424 ;
     RECT  0.084 71.424 0.097 71.448 ;
     RECT  0.06 71.448 0.097 71.568 ;
     RECT  0.084 71.568 0.097 71.592 ;
     RECT  0.06 71.592 0.097 71.712 ;
     RECT  0.084 71.712 0.097 71.736 ;
     RECT  0.06 71.736 0.097 71.856 ;
     RECT  0.084 71.856 0.097 71.88 ;
     RECT  0.06 71.88 0.097 72 ;
     RECT  0.084 72 0.097 72.024 ;
     RECT  0.06 72.024 0.097 72.144 ;
     RECT  0.084 72.144 0.097 72.168 ;
     RECT  0.06 72.168 0.097 72.288 ;
     RECT  0.084 72.288 0.097 72.312 ;
     RECT  0.06 72.312 0.097 72.432 ;
     RECT  0.084 72.432 0.097 72.456 ;
     RECT  0.06 72.456 0.097 72.576 ;
     RECT  0.084 72.576 0.097 72.6 ;
     RECT  0.06 72.6 0.097 72.72 ;
     RECT  0.084 72.72 0.097 72.744 ;
     RECT  0.06 72.744 0.097 72.864 ;
     RECT  0.084 72.864 0.097 72.888 ;
     RECT  0.06 72.888 0.097 73.008 ;
     RECT  0.084 73.008 0.097 73.032 ;
     RECT  0.06 73.032 0.097 73.152 ;
     RECT  0.084 73.152 0.097 73.176 ;
     RECT  0.06 73.176 0.097 73.296 ;
     RECT  0.084 73.296 0.097 73.32 ;
     RECT  0.084 11.232 0.133 11.256 ;
     RECT  0.06 11.256 0.133 11.376 ;
     RECT  0.084 11.376 0.133 11.4 ;
     RECT  0.06 11.4 0.133 11.52 ;
     RECT  0.084 11.52 0.133 11.544 ;
     RECT  0.06 11.544 0.133 11.664 ;
     RECT  0.084 11.664 0.133 11.688 ;
     RECT  0.06 11.688 0.133 11.808 ;
     RECT  0.084 11.808 0.133 11.832 ;
     RECT  0.06 11.832 0.133 11.952 ;
     RECT  0.084 11.952 0.133 11.976 ;
     RECT  0.06 11.976 0.133 12.096 ;
     RECT  0.084 12.096 0.133 12.12 ;
     RECT  0.06 12.12 0.133 12.24 ;
     RECT  0.084 12.24 0.133 12.264 ;
     RECT  0.06 12.264 0.133 12.384 ;
     RECT  0.084 12.384 0.133 12.408 ;
     RECT  0.06 12.408 0.133 12.528 ;
     RECT  0.084 12.528 0.133 12.552 ;
     RECT  0.06 12.552 0.133 12.672 ;
     RECT  0.084 12.672 0.133 12.696 ;
     RECT  0.06 12.696 0.133 12.816 ;
     RECT  0.084 12.816 0.133 12.84 ;
     RECT  0.06 12.84 0.133 12.96 ;
     RECT  0.084 12.96 0.133 12.984 ;
     RECT  0.06 12.984 0.133 13.104 ;
     RECT  0.084 13.104 0.133 13.128 ;
     RECT  0.06 13.128 0.133 13.248 ;
     RECT  0.084 13.248 0.133 13.272 ;
     RECT  0.06 13.272 0.133 13.392 ;
     RECT  0.084 13.392 0.133 13.416 ;
     RECT  0.06 13.416 0.133 13.536 ;
     RECT  0.084 13.536 0.133 13.56 ;
     RECT  0.06 13.56 0.133 13.68 ;
     RECT  0.084 13.68 0.133 13.704 ;
     RECT  0.06 13.704 0.133 13.824 ;
     RECT  0.084 13.824 0.133 13.848 ;
     RECT  0.06 13.848 0.133 13.968 ;
     RECT  0.084 13.968 0.133 13.992 ;
     RECT  0.06 13.992 0.133 14.112 ;
     RECT  0.084 14.112 0.133 14.136 ;
     RECT  0.06 14.136 0.133 14.256 ;
     RECT  0.084 14.256 0.133 14.28 ;
     RECT  0.06 14.28 0.133 14.4 ;
     RECT  0.084 14.4 0.133 14.424 ;
     RECT  0.06 14.424 0.133 14.544 ;
     RECT  0.084 14.544 0.133 14.568 ;
     RECT  0.06 14.568 0.133 14.688 ;
     RECT  0.084 14.688 0.133 14.712 ;
     RECT  0.06 14.712 0.133 14.832 ;
     RECT  0.084 14.832 0.133 14.856 ;
     RECT  0.06 14.856 0.133 14.976 ;
     RECT  0.084 14.976 0.133 15 ;
     RECT  0.06 15 0.133 15.12 ;
     RECT  0.084 15.12 0.133 15.144 ;
     RECT  0.06 15.144 0.133 15.264 ;
     RECT  0.084 15.264 0.133 15.288 ;
     RECT  0.06 15.288 0.133 15.408 ;
     RECT  0.084 15.408 0.133 15.432 ;
     RECT  0.06 15.432 0.133 15.552 ;
     RECT  0.084 15.552 0.133 15.576 ;
     RECT  0.06 15.576 0.133 15.696 ;
     RECT  0.084 15.696 0.133 15.72 ;
     RECT  0.084 20.448 0.133 20.472 ;
     RECT  0.06 20.472 0.133 20.592 ;
     RECT  0.084 20.592 0.133 20.616 ;
     RECT  0.06 20.616 0.133 20.736 ;
     RECT  0.084 20.736 0.133 20.76 ;
     RECT  0.06 20.76 0.133 20.88 ;
     RECT  0.084 20.88 0.133 20.904 ;
     RECT  0.06 20.904 0.133 21.024 ;
     RECT  0.084 21.024 0.133 21.048 ;
     RECT  0.06 21.048 0.133 21.168 ;
     RECT  0.084 21.168 0.133 21.192 ;
     RECT  0.06 21.192 0.133 21.312 ;
     RECT  0.084 21.312 0.133 21.336 ;
     RECT  0.06 21.336 0.133 21.456 ;
     RECT  0.084 21.456 0.133 21.48 ;
     RECT  0.06 21.48 0.133 21.6 ;
     RECT  0.084 21.6 0.133 21.624 ;
     RECT  0.06 21.624 0.133 21.744 ;
     RECT  0.084 21.744 0.133 21.768 ;
     RECT  0.06 21.768 0.133 21.888 ;
     RECT  0.084 21.888 0.133 21.912 ;
     RECT  0.06 21.912 0.133 22.032 ;
     RECT  0.084 22.032 0.133 22.056 ;
     RECT  0.06 22.056 0.133 22.176 ;
     RECT  0.084 22.176 0.133 22.2 ;
     RECT  0.06 22.2 0.133 22.32 ;
     RECT  0.084 22.32 0.133 22.344 ;
     RECT  0.06 22.344 0.133 22.464 ;
     RECT  0.084 22.464 0.133 22.488 ;
     RECT  0.06 22.488 0.133 22.608 ;
     RECT  0.084 22.608 0.133 22.632 ;
     RECT  0.06 22.632 0.133 22.752 ;
     RECT  0.084 22.752 0.133 22.776 ;
     RECT  0.06 22.776 0.133 22.896 ;
     RECT  0.084 22.896 0.133 22.92 ;
     RECT  0.06 22.92 0.133 23.04 ;
     RECT  0.084 23.04 0.133 23.064 ;
     RECT  0.06 23.064 0.133 23.184 ;
     RECT  0.084 23.184 0.133 23.208 ;
     RECT  0.06 23.208 0.133 23.328 ;
     RECT  0.084 23.328 0.133 23.352 ;
     RECT  0.06 23.352 0.133 23.472 ;
     RECT  0.084 23.472 0.133 23.496 ;
     RECT  0.06 23.496 0.133 23.616 ;
     RECT  0.084 23.616 0.133 23.64 ;
     RECT  0.06 23.64 0.133 23.76 ;
     RECT  0.084 23.76 0.133 23.784 ;
     RECT  0.06 23.784 0.133 23.904 ;
     RECT  0.084 23.904 0.133 23.928 ;
     RECT  0.06 23.928 0.133 24.048 ;
     RECT  0.084 24.048 0.133 24.072 ;
     RECT  0.06 24.072 0.133 24.192 ;
     RECT  0.084 24.192 0.133 24.216 ;
     RECT  0.06 24.216 0.133 24.336 ;
     RECT  0.084 24.336 0.133 24.36 ;
     RECT  0.06 24.36 0.133 24.48 ;
     RECT  0.084 24.48 0.133 24.504 ;
     RECT  0.06 24.504 0.133 24.624 ;
     RECT  0.084 24.624 0.133 24.648 ;
     RECT  0.06 24.648 0.133 24.768 ;
     RECT  0.084 24.768 0.133 24.792 ;
     RECT  0.06 24.792 0.133 24.912 ;
     RECT  0.084 24.912 0.133 24.936 ;
     RECT  0.133 11.184 2.329 15.816 ;
     RECT  0.084 58.464 2.329 58.488 ;
     RECT  0.06 58.488 2.329 58.608 ;
     RECT  0.084 58.608 2.329 58.632 ;
     RECT  0.06 58.632 2.329 58.752 ;
     RECT  0.084 58.752 2.329 58.776 ;
     RECT  0.06 58.776 2.329 58.896 ;
     RECT  0.084 58.896 2.329 58.92 ;
     RECT  0.06 58.92 2.329 59.04 ;
     RECT  0.084 59.04 2.329 59.064 ;
     RECT  0.06 59.064 2.329 59.184 ;
     RECT  0.084 59.184 2.329 59.208 ;
     RECT  0.06 59.208 2.329 59.328 ;
     RECT  0.084 59.328 2.329 59.352 ;
     RECT  0.06 59.352 2.329 59.472 ;
     RECT  0.084 59.472 2.329 59.496 ;
     RECT  0.06 59.496 2.329 59.616 ;
     RECT  0.084 59.616 2.329 59.64 ;
     RECT  0.06 59.64 2.329 59.76 ;
     RECT  0.084 59.76 2.329 59.784 ;
     RECT  0.06 59.784 2.329 59.904 ;
     RECT  0.084 59.904 2.329 59.928 ;
     RECT  0.06 59.928 2.329 60.048 ;
     RECT  0.084 60.048 2.329 60.072 ;
     RECT  0.06 60.072 2.329 60.192 ;
     RECT  0.084 60.192 2.329 60.216 ;
     RECT  0.06 60.216 2.329 60.336 ;
     RECT  0.084 60.336 2.329 60.36 ;
     RECT  0.06 60.36 2.329 60.48 ;
     RECT  0.084 60.48 2.329 60.504 ;
     RECT  0.06 60.504 2.329 60.624 ;
     RECT  0.084 60.624 2.329 60.648 ;
     RECT  0.06 60.648 2.329 60.768 ;
     RECT  0.084 60.768 2.329 60.792 ;
     RECT  0.06 60.792 2.329 60.912 ;
     RECT  0.084 60.912 2.329 60.936 ;
     RECT  0.06 60.936 2.329 61.056 ;
     RECT  0.084 61.056 2.329 61.08 ;
     RECT  0.06 61.08 2.329 61.2 ;
     RECT  0.084 61.2 2.329 61.224 ;
     RECT  0.06 61.224 2.329 61.344 ;
     RECT  0.084 61.344 2.329 61.368 ;
     RECT  0.06 61.368 2.329 61.488 ;
     RECT  0.084 61.488 2.329 61.512 ;
     RECT  0.06 61.512 2.329 61.632 ;
     RECT  0.084 61.632 2.329 61.656 ;
     RECT  0.06 61.656 2.329 61.776 ;
     RECT  0.084 61.776 2.329 61.8 ;
     RECT  0.06 61.8 2.329 61.92 ;
     RECT  0.084 61.92 2.329 61.944 ;
     RECT  0.06 61.944 2.329 62.064 ;
     RECT  0.084 62.064 2.329 62.088 ;
     RECT  0.06 62.088 2.329 62.208 ;
     RECT  0.084 62.208 2.329 62.232 ;
     RECT  0.06 62.232 2.329 62.352 ;
     RECT  0.084 62.352 2.329 62.376 ;
     RECT  0.06 62.376 2.329 62.496 ;
     RECT  0.084 62.496 2.329 62.52 ;
     RECT  0.06 62.52 2.329 62.64 ;
     RECT  0.084 62.64 2.329 62.664 ;
     RECT  0.06 62.664 2.329 62.784 ;
     RECT  0.084 62.784 2.329 62.808 ;
     RECT  0.06 62.808 2.329 62.928 ;
     RECT  0.084 62.928 2.329 62.952 ;
     RECT  2.329 10.944 2.408 15.816 ;
     RECT  0.133 20.448 2.408 25.032 ;
     RECT  2.401 56.784 2.408 56.808 ;
     RECT  2.329 58.464 2.408 63.048 ;
     RECT  2.365 65.712 2.408 65.736 ;
     RECT  0.097 68.736 2.408 73.32 ;
     RECT  2.408 2.148 2.512 95.052 ;
     RECT  2.512 2.418 2.704 94.782 ;
     RECT  2.704 58.464 2.765 63.096 ;
     RECT  2.704 68.736 2.801 74.424 ;
     RECT  2.704 50.688 2.819 57.048 ;
     RECT  2.704 64.944 2.819 65.736 ;
     RECT  2.704 44.688 2.873 49.368 ;
     RECT  2.704 11.184 2.909 17.64 ;
     RECT  2.801 68.736 2.909 72.744 ;
     RECT  2.873 46.08 2.917 49.368 ;
     RECT  2.704 75.456 3.017 75.48 ;
     RECT  2.909 11.664 3.125 17.64 ;
     RECT  2.704 34.08 3.125 34.968 ;
     RECT  3.125 11.712 3.161 14.664 ;
     RECT  2.765 58.464 3.161 62.568 ;
     RECT  3.161 13.392 3.197 14.424 ;
     RECT  3.161 58.464 3.197 58.728 ;
     RECT  2.909 69.264 3.233 72.744 ;
     RECT  3.233 69.264 3.269 72.696 ;
     RECT  2.917 46.512 3.299 49.368 ;
     RECT  3.161 59.76 3.305 62.568 ;
     RECT  3.299 48.288 3.377 49.368 ;
     RECT  2.704 83.184 3.388 89.736 ;
     RECT  2.819 51.792 3.413 54.936 ;
     RECT  3.305 59.76 3.413 59.784 ;
     RECT  3.125 34.08 3.443 34.2 ;
     RECT  2.704 37.584 3.443 39.24 ;
     RECT  3.269 69.264 3.449 69.528 ;
     RECT  3.388 83.184 3.449 86.616 ;
     RECT  2.873 44.688 3.629 44.712 ;
     RECT  3.449 84.144 3.635 86.616 ;
     RECT  3.635 85.392 3.665 86.616 ;
     RECT  3.305 61.2 3.701 62.568 ;
     RECT  2.704 40.56 3.733 43.56 ;
     RECT  2.704 30.864 3.737 33.048 ;
     RECT  2.819 50.688 3.745 50.712 ;
     RECT  3.701 61.632 3.769 62.568 ;
     RECT  3.635 84.144 3.773 84.168 ;
     RECT  3.413 52.224 3.841 54.936 ;
     RECT  2.819 55.968 3.841 57.048 ;
     RECT  3.443 34.08 3.845 34.104 ;
     RECT  3.443 39.216 3.845 39.24 ;
     RECT  3.299 46.512 3.913 46.536 ;
     RECT  2.704 78.72 3.949 79.992 ;
     RECT  2.704 26.64 3.985 27.432 ;
     RECT  2.704 29.04 3.985 29.112 ;
     RECT  2.819 65.184 3.985 65.736 ;
     RECT  2.704 77.28 3.985 77.304 ;
     RECT  3.737 31.488 3.989 33.048 ;
     RECT  2.704 20.16 4.057 25.032 ;
     RECT  3.985 64.464 4.057 65.736 ;
     RECT  3.985 28.944 4.129 29.112 ;
     RECT  2.704 67.008 4.129 67.272 ;
     RECT  3.985 26.304 4.237 27.432 ;
     RECT  2.704 36.096 4.237 36.12 ;
     RECT  3.443 37.584 4.237 37.608 ;
     RECT  3.913 46.128 4.237 46.536 ;
     RECT  3.949 78.72 4.268 80.088 ;
     RECT  3.269 71.376 4.273 72.696 ;
     RECT  3.985 76.32 4.273 77.304 ;
     RECT  2.801 73.776 4.309 74.424 ;
     RECT  2.704 81.216 4.309 81.24 ;
     RECT  3.161 11.712 4.345 12.36 ;
     RECT  4.057 19.776 4.345 25.032 ;
     RECT  4.129 67.008 4.345 67.704 ;
     RECT  4.057 18.72 4.381 18.744 ;
     RECT  4.345 19.776 4.381 25.224 ;
     RECT  4.268 78.528 4.381 80.088 ;
     RECT  4.309 81.072 4.381 81.24 ;
     RECT  3.733 40.56 4.412 43.944 ;
     RECT  4.309 73.776 4.417 74.664 ;
     RECT  4.273 76.32 4.417 77.544 ;
     RECT  4.381 18.72 4.453 25.224 ;
     RECT  4.237 26.304 4.453 27.624 ;
     RECT  4.345 10.992 4.501 12.36 ;
     RECT  3.197 13.392 4.501 14.184 ;
     RECT  4.237 45.888 4.501 46.536 ;
     RECT  4.453 18.72 4.525 27.624 ;
     RECT  4.129 28.944 4.525 29.688 ;
     RECT  3.449 69.456 4.525 69.528 ;
     RECT  4.273 71.088 4.525 72.696 ;
     RECT  4.417 73.776 4.549 77.544 ;
     RECT  4.381 78.528 4.549 81.24 ;
     RECT  3.377 48.432 4.561 49.368 ;
     RECT  4.057 63.888 4.597 65.736 ;
     RECT  4.501 10.992 4.633 14.184 ;
     RECT  4.597 63.888 4.633 65.976 ;
     RECT  4.345 67.008 4.633 68.424 ;
     RECT  3.388 87.84 4.645 89.736 ;
     RECT  3.841 52.224 4.669 57.048 ;
     RECT  3.197 58.464 4.669 58.536 ;
     RECT  4.645 87.84 4.7 89.88 ;
     RECT  4.501 45.792 4.741 46.536 ;
     RECT  3.989 31.488 4.777 32.76 ;
     RECT  3.665 86.592 4.777 86.616 ;
     RECT  4.7 87.6 4.777 89.88 ;
     RECT  4.525 69.456 4.789 72.696 ;
     RECT  4.549 73.776 4.789 81.24 ;
     RECT  3.985 82.8 4.796 82.824 ;
     RECT  4.633 63.888 4.813 68.424 ;
     RECT  4.669 52.224 4.837 58.536 ;
     RECT  4.604 83.808 4.837 83.832 ;
     RECT  4.837 51.552 4.849 58.536 ;
     RECT  3.769 61.632 4.849 62.76 ;
     RECT  4.813 63.84 4.849 68.424 ;
     RECT  3.125 15.984 4.957 17.64 ;
     RECT  4.525 18.72 4.957 29.688 ;
     RECT  4.957 15.984 4.981 29.688 ;
     RECT  4.777 31.152 4.981 32.76 ;
     RECT  4.705 60.576 4.981 60.6 ;
     RECT  4.849 61.632 4.981 68.424 ;
     RECT  4.741 45.792 5.029 46.776 ;
     RECT  4.796 82.416 5.065 82.824 ;
     RECT  4.837 83.808 5.065 84.12 ;
     RECT  3.665 85.392 5.101 85.512 ;
     RECT  4.777 86.592 5.101 89.88 ;
     RECT  4.633 10.992 5.108 14.424 ;
     RECT  4.981 15.984 5.108 32.76 ;
     RECT  4.741 34.992 5.108 35.016 ;
     RECT  4.237 36.096 5.108 37.608 ;
     RECT  4.412 40.32 5.108 43.944 ;
     RECT  5.029 45.792 5.108 47.112 ;
     RECT  4.561 48.432 5.108 49.512 ;
     RECT  4.849 51.36 5.108 58.536 ;
     RECT  4.993 59.568 5.108 59.592 ;
     RECT  4.981 60.576 5.108 68.424 ;
     RECT  4.789 69.456 5.108 81.24 ;
     RECT  5.065 82.416 5.108 84.12 ;
     RECT  5.101 85.392 5.108 89.88 ;
     RECT  5.108 2.148 5.212 95.052 ;
     RECT  5.212 2.418 5.404 94.782 ;
     RECT  5.404 42.144 5.555 47.352 ;
     RECT  5.404 69.312 5.565 81 ;
     RECT  5.404 8.448 5.645 32.808 ;
     RECT  5.645 8.448 5.717 32.76 ;
     RECT  5.555 43.536 5.747 47.352 ;
     RECT  5.404 33.84 5.789 37.752 ;
     RECT  5.565 69.312 5.843 78.744 ;
     RECT  5.717 8.448 6.005 12.888 ;
     RECT  5.404 38.736 6.041 40.824 ;
     RECT  5.717 13.872 6.083 32.76 ;
     RECT  5.789 33.84 6.124 34.488 ;
     RECT  5.404 50.784 6.149 68.04 ;
     RECT  5.843 78.336 6.221 78.744 ;
     RECT  6.005 8.448 6.275 10.296 ;
     RECT  5.555 42.144 6.293 42.168 ;
     RECT  5.565 79.824 6.293 81 ;
     RECT  6.149 50.784 6.323 57.336 ;
     RECT  6.041 40.8 6.329 40.824 ;
     RECT  6.323 50.928 6.329 57.336 ;
     RECT  6.149 58.56 6.329 68.04 ;
     RECT  6.293 80.976 6.329 81 ;
     RECT  5.404 48.432 6.469 49.464 ;
     RECT  6.083 13.872 6.473 27.672 ;
     RECT  6.473 13.872 6.509 27.432 ;
     RECT  5.789 35.76 6.541 37.752 ;
     RECT  6.041 38.736 6.541 39.336 ;
     RECT  5.404 84.816 6.572 89.928 ;
     RECT  6.083 28.8 6.617 32.76 ;
     RECT  6.572 84.816 6.659 90.552 ;
     RECT  6.617 30.864 6.685 32.76 ;
     RECT  5.404 82.224 6.685 83.304 ;
     RECT  6.685 30.864 6.761 33.576 ;
     RECT  6.541 35.76 6.793 39.336 ;
     RECT  6.685 82.224 6.793 83.784 ;
     RECT  6.761 30.864 6.797 31.224 ;
     RECT  6.005 11.28 6.865 12.888 ;
     RECT  6.509 13.872 6.865 26.328 ;
     RECT  5.843 69.312 6.901 77.352 ;
     RECT  6.329 62.496 6.937 68.04 ;
     RECT  6.901 69.312 6.937 77.688 ;
     RECT  6.221 78.72 7.009 78.744 ;
     RECT  6.293 79.824 7.009 79.992 ;
     RECT  6.275 8.448 7.117 10.056 ;
     RECT  6.329 58.56 7.297 61.512 ;
     RECT  6.937 62.496 7.297 77.688 ;
     RECT  6.329 55.68 7.369 57.336 ;
     RECT  7.297 58.56 7.369 77.688 ;
     RECT  7.009 78.72 7.429 79.992 ;
     RECT  7.369 55.68 7.628 77.688 ;
     RECT  7.429 78.72 7.628 80.328 ;
     RECT  6.509 27.408 7.657 27.432 ;
     RECT  6.617 28.8 7.657 29.544 ;
     RECT  7.117 8.16 7.669 10.056 ;
     RECT  6.865 11.28 7.669 26.328 ;
     RECT  7.669 8.16 7.693 26.328 ;
     RECT  7.657 27.408 7.693 29.544 ;
     RECT  5.747 44.16 7.693 47.352 ;
     RECT  6.329 50.928 7.729 54.456 ;
     RECT  6.685 41.04 7.765 41.4 ;
     RECT  7.693 8.16 7.808 29.544 ;
     RECT  6.797 31.104 7.808 31.224 ;
     RECT  6.761 32.736 7.808 33.576 ;
     RECT  6.793 34.8 7.808 39.336 ;
     RECT  7.765 40.56 7.808 41.4 ;
     RECT  7.765 42.576 7.808 42.6 ;
     RECT  7.693 44.064 7.808 47.352 ;
     RECT  6.469 48.432 7.808 49.608 ;
     RECT  7.729 50.928 7.808 54.696 ;
     RECT  7.628 55.68 7.808 80.328 ;
     RECT  6.793 81.456 7.808 83.784 ;
     RECT  6.659 84.816 7.808 89.784 ;
     RECT  6.685 91.584 7.808 91.608 ;
     RECT  7.808 2.148 7.912 95.052 ;
     RECT  7.912 2.418 8.104 94.782 ;
     RECT  8.104 9.6 8.165 9.624 ;
     RECT  8.104 19.056 8.243 31.224 ;
     RECT  8.104 40.416 8.243 49.272 ;
     RECT  8.104 50.544 8.243 83.304 ;
     RECT  8.243 50.544 8.291 79.56 ;
     RECT  8.104 32.208 8.381 39.24 ;
     RECT  8.243 80.928 8.381 83.304 ;
     RECT  8.381 32.208 8.417 36.696 ;
     RECT  8.381 37.824 8.417 39.24 ;
     RECT  8.291 55.872 8.62 79.56 ;
     RECT  8.104 10.848 8.633 17.64 ;
     RECT  8.243 19.056 8.777 29.688 ;
     RECT  8.243 30.864 8.885 31.224 ;
     RECT  8.417 35.472 8.915 36.696 ;
     RECT  8.243 40.416 8.921 47.64 ;
     RECT  8.381 80.928 8.921 82.488 ;
     RECT  8.921 40.416 9.065 46.584 ;
     RECT  8.104 91.344 9.097 91.368 ;
     RECT  8.62 68.208 9.137 79.56 ;
     RECT  8.921 80.976 9.137 82.488 ;
     RECT  8.885 30.864 9.209 30.936 ;
     RECT  8.921 47.616 9.277 47.64 ;
     RECT  8.777 19.056 9.281 29.544 ;
     RECT  9.137 81.072 9.281 81.096 ;
     RECT  8.104 84.528 9.308 89.784 ;
     RECT  8.633 10.848 9.313 17.112 ;
     RECT  8.417 32.208 9.353 34.392 ;
     RECT  8.243 48.768 9.389 49.272 ;
     RECT  8.417 37.824 9.421 38.712 ;
     RECT  8.291 50.544 9.421 54.744 ;
     RECT  9.277 47.616 9.457 47.784 ;
     RECT  8.104 6.24 9.529 6.264 ;
     RECT  9.421 50.544 9.529 54.792 ;
     RECT  8.62 55.872 9.529 66.888 ;
     RECT  8.104 8.16 9.601 8.184 ;
     RECT  9.601 8.16 9.637 9.096 ;
     RECT  9.137 68.208 9.637 74.664 ;
     RECT  9.313 10.8 9.673 17.112 ;
     RECT  9.529 50.544 9.685 66.888 ;
     RECT  9.637 68.064 9.685 74.664 ;
     RECT  9.389 48.96 9.709 49.272 ;
     RECT  9.308 84.336 9.709 89.784 ;
     RECT  9.097 91.344 9.745 92.328 ;
     RECT  9.529 6.24 9.817 6.84 ;
     RECT  9.209 30.864 9.853 30.888 ;
     RECT  9.817 6.24 9.889 6.936 ;
     RECT  9.137 82.224 9.889 82.488 ;
     RECT  9.637 8.16 9.925 9.624 ;
     RECT  9.673 10.8 9.925 17.208 ;
     RECT  9.065 45.168 9.925 46.584 ;
     RECT  9.709 83.856 9.925 89.784 ;
     RECT  9.925 8.16 9.997 17.208 ;
     RECT  9.353 32.256 10.213 34.392 ;
     RECT  8.915 35.472 10.213 36.072 ;
     RECT  9.709 48.96 10.213 49.56 ;
     RECT  9.685 50.544 10.213 74.664 ;
     RECT  9.137 75.744 10.249 79.56 ;
     RECT  9.065 40.416 10.285 44.184 ;
     RECT  9.889 82.224 10.309 82.536 ;
     RECT  10.261 94.128 10.309 94.152 ;
     RECT  9.281 19.056 10.321 22.872 ;
     RECT  9.281 23.856 10.321 29.544 ;
     RECT  9.745 91.344 10.357 92.52 ;
     RECT  10.309 93.6 10.357 94.152 ;
     RECT  9.997 8.16 10.393 18.072 ;
     RECT  10.321 19.056 10.393 29.544 ;
     RECT  10.357 93.504 10.465 94.152 ;
     RECT  9.925 45.168 10.501 46.632 ;
     RECT  9.457 47.616 10.501 47.88 ;
     RECT  10.357 91.152 10.501 92.52 ;
     RECT  10.465 93.504 10.501 94.344 ;
     RECT  9.889 6.24 10.508 6.984 ;
     RECT  10.393 8.16 10.508 29.544 ;
     RECT  9.853 30.768 10.508 30.888 ;
     RECT  10.213 32.256 10.508 36.072 ;
     RECT  9.421 37.296 10.508 38.712 ;
     RECT  10.285 39.84 10.508 44.184 ;
     RECT  10.501 45.168 10.508 47.88 ;
     RECT  10.213 48.96 10.508 74.664 ;
     RECT  10.249 75.744 10.508 80.376 ;
     RECT  10.309 81.84 10.508 82.536 ;
     RECT  9.925 83.664 10.508 89.784 ;
     RECT  10.501 91.152 10.508 94.344 ;
     RECT  10.508 2.148 10.612 95.052 ;
     RECT  10.612 2.418 10.645 95.052 ;
     RECT  10.645 2.418 10.732 95.208 ;
     RECT  10.732 2.418 10.804 94.782 ;
     RECT  10.804 48.768 10.829 57.096 ;
     RECT  10.804 42.288 10.865 47.64 ;
     RECT  10.804 86.784 10.865 89.784 ;
     RECT  10.829 50.544 10.937 57.096 ;
     RECT  10.804 32.304 10.973 40.44 ;
     RECT  10.973 32.304 10.979 38.424 ;
     RECT  10.804 91.056 11.15 94.68 ;
     RECT  10.804 58.128 11.189 76.68 ;
     RECT  10.804 77.952 11.189 85.8 ;
     RECT  11.189 58.128 11.297 75.432 ;
     RECT  11.189 80.352 11.747 85.8 ;
     RECT  10.937 52.176 11.765 57.096 ;
     RECT  10.804 19.248 11.797 22.872 ;
     RECT  10.804 23.856 11.797 30.888 ;
     RECT  10.865 42.288 11.797 46.632 ;
     RECT  10.357 97.056 11.845 97.08 ;
     RECT  11.765 56.688 11.873 57.096 ;
     RECT  10.829 48.768 11.905 49.56 ;
     RECT  10.937 50.544 11.905 50.952 ;
     RECT  10.979 32.304 11.941 37.992 ;
     RECT  10.973 39.84 11.941 40.44 ;
     RECT  11.797 41.424 11.941 46.632 ;
     RECT  10.865 87.072 11.941 89.784 ;
     RECT  11.873 56.736 11.945 57.096 ;
     RECT  11.905 48.768 12.089 50.952 ;
     RECT  11.797 19.248 12.157 30.888 ;
     RECT  11.941 39.216 12.157 46.632 ;
     RECT  10.865 47.616 12.157 47.64 ;
     RECT  12.157 19.2 12.161 30.888 ;
     RECT  12.089 50.592 12.161 50.952 ;
     RECT  12.157 39.216 12.179 47.64 ;
     RECT  11.941 32.256 12.193 37.992 ;
     RECT  11.189 76.56 12.193 76.68 ;
     RECT  11.189 77.952 12.193 79.224 ;
     RECT  11.945 56.832 12.229 57.096 ;
     RECT  11.297 58.128 12.229 74.856 ;
     RECT  12.193 32.208 12.265 37.992 ;
     RECT  12.161 50.64 12.265 50.952 ;
     RECT  11.765 52.176 12.265 55.704 ;
     RECT  10.804 6.144 12.325 6.84 ;
     RECT  10.804 7.824 12.325 18.216 ;
     RECT  11.941 87.072 12.337 89.88 ;
     RECT  12.265 32.016 12.409 37.992 ;
     RECT  12.179 44.928 12.445 47.64 ;
     RECT  12.089 48.768 12.445 49.56 ;
     RECT  12.409 31.92 12.517 37.992 ;
     RECT  12.179 39.216 12.517 43.896 ;
     RECT  11.15 91.056 12.517 94.584 ;
     RECT  12.325 6.144 12.661 18.216 ;
     RECT  12.193 76.56 12.757 79.224 ;
     RECT  12.757 76.08 12.805 79.224 ;
     RECT  11.747 80.352 12.805 84.936 ;
     RECT  11.845 96.96 12.805 97.08 ;
     RECT  12.661 5.472 12.841 18.216 ;
     RECT  12.161 19.2 12.841 25.608 ;
     RECT  12.805 76.08 12.877 84.936 ;
     RECT  12.337 86.064 12.949 89.88 ;
     RECT  12.517 91.056 12.949 95.208 ;
     RECT  12.805 96.768 12.995 97.08 ;
     RECT  12.995 96.864 13.043 97.08 ;
     RECT  12.949 86.064 13.093 95.208 ;
     RECT  12.841 5.472 13.129 25.608 ;
     RECT  12.161 27.072 13.129 30.888 ;
     RECT  12.877 75.984 13.165 84.936 ;
     RECT  13.093 86.016 13.165 95.208 ;
     RECT  13.129 5.472 13.208 30.888 ;
     RECT  12.517 31.92 13.208 43.896 ;
     RECT  12.445 44.928 13.208 49.56 ;
     RECT  12.265 50.64 13.208 55.704 ;
     RECT  12.229 56.832 13.208 74.856 ;
     RECT  13.165 75.984 13.208 95.256 ;
     RECT  13.208 2.148 13.312 95.256 ;
     RECT  13.312 2.418 13.504 95.256 ;
     RECT  13.504 50.64 13.565 94.104 ;
     RECT  13.504 95.136 13.571 95.256 ;
     RECT  13.565 89.232 13.619 94.104 ;
     RECT  13.565 50.64 13.673 88.152 ;
     RECT  13.504 10.128 13.708 38.184 ;
     RECT  13.504 39.168 13.781 43.896 ;
     RECT  13.504 5.232 13.817 8.568 ;
     RECT  13.571 95.136 13.817 95.16 ;
     RECT  13.781 39.168 13.853 41.4 ;
     RECT  13.673 50.64 13.859 78.696 ;
     RECT  13.859 50.64 13.997 78.456 ;
     RECT  13.619 92.928 14.033 94.104 ;
     RECT  13.043 97.056 14.101 97.08 ;
     RECT  13.817 6.288 14.243 8.568 ;
     RECT  14.101 97.008 14.245 97.08 ;
     RECT  13.673 80.064 14.501 88.152 ;
     RECT  14.243 7.92 14.533 8.568 ;
     RECT  13.504 44.976 14.537 48.984 ;
     RECT  13.817 5.232 14.717 5.256 ;
     RECT  14.243 6.288 14.717 6.888 ;
     RECT  14.501 84.672 14.749 88.152 ;
     RECT  13.619 89.232 14.749 91.944 ;
     RECT  13.853 39.168 14.753 41.064 ;
     RECT  13.708 13.968 14.819 38.184 ;
     RECT  13.997 52.56 14.819 78.456 ;
     RECT  13.708 10.128 14.821 12.888 ;
     RECT  14.819 13.968 14.821 15.528 ;
     RECT  14.501 80.064 14.821 82.968 ;
     RECT  14.537 47.904 14.857 48.984 ;
     RECT  14.821 79.92 14.867 82.968 ;
     RECT  14.819 55.2 14.937 78.456 ;
     RECT  14.245 96.336 14.969 97.08 ;
     RECT  13.781 42.624 15.037 43.656 ;
     RECT  13.997 50.64 15.037 51.24 ;
     RECT  14.937 55.2 15.116 78.648 ;
     RECT  14.867 79.92 15.116 80.376 ;
     RECT  14.749 84.672 15.145 91.944 ;
     RECT  14.033 92.928 15.145 94.056 ;
     RECT  14.857 47.904 15.205 49.56 ;
     RECT  15.037 50.64 15.205 51.384 ;
     RECT  14.819 18.192 15.253 38.184 ;
     RECT  15.205 47.904 15.325 51.384 ;
     RECT  14.819 52.56 15.325 54.216 ;
     RECT  14.753 39.216 15.461 41.064 ;
     RECT  14.867 81.408 15.541 82.968 ;
     RECT  15.037 42.624 15.613 43.896 ;
     RECT  14.537 44.976 15.613 46.632 ;
     RECT  15.245 95.136 15.617 95.16 ;
     RECT  15.613 42.624 15.793 46.632 ;
     RECT  14.821 10.128 15.829 15.528 ;
     RECT  15.461 39.216 15.832 41.64 ;
     RECT  15.793 42.624 15.832 46.872 ;
     RECT  14.717 6.288 15.908 6.84 ;
     RECT  14.533 7.92 15.908 8.76 ;
     RECT  15.829 9.792 15.908 15.528 ;
     RECT  14.819 16.656 15.908 17.208 ;
     RECT  15.253 18.192 15.908 38.232 ;
     RECT  15.832 39.216 15.908 46.872 ;
     RECT  15.325 47.904 15.908 54.216 ;
     RECT  15.116 55.2 15.908 80.376 ;
     RECT  15.541 81.408 15.908 83.064 ;
     RECT  15.145 84.672 15.908 94.056 ;
     RECT  15.908 2.148 16.012 95.052 ;
     RECT  14.969 96.336 16.121 96.36 ;
     RECT  16.012 2.418 16.204 94.782 ;
     RECT  16.204 9.12 16.301 80.856 ;
     RECT  16.204 5.088 16.355 7.464 ;
     RECT  16.301 9.12 16.409 47.688 ;
     RECT  16.355 5.088 16.625 5.784 ;
     RECT  16.409 9.12 16.661 43.896 ;
     RECT  16.625 5.232 16.913 5.784 ;
     RECT  16.301 48.672 17.057 80.856 ;
     RECT  16.661 9.12 17.129 33.72 ;
     RECT  17.129 11.952 17.171 33.72 ;
     RECT  16.204 81.936 17.197 93.48 ;
     RECT  17.057 48.672 17.363 80.52 ;
     RECT  16.661 34.8 17.417 43.896 ;
     RECT  17.363 48.672 17.453 78.792 ;
     RECT  17.417 34.8 17.489 41.688 ;
     RECT  17.453 48.672 17.5 78.744 ;
     RECT  17.363 79.776 17.507 80.52 ;
     RECT  16.355 7.44 17.593 7.464 ;
     RECT  17.129 9.12 17.593 10.968 ;
     RECT  17.593 7.44 17.633 10.968 ;
     RECT  17.171 32.448 17.665 33.72 ;
     RECT  17.489 34.8 17.665 41.448 ;
     RECT  16.409 44.928 17.845 47.688 ;
     RECT  17.5 48.672 17.845 64.968 ;
     RECT  17.417 42.672 17.917 43.896 ;
     RECT  16.913 5.76 17.989 5.784 ;
     RECT  17.633 7.44 17.989 9.144 ;
     RECT  17.917 42.672 18.025 43.944 ;
     RECT  17.845 44.928 18.025 64.968 ;
     RECT  18.385 4.512 18.457 4.536 ;
     RECT  17.989 5.76 18.457 9.144 ;
     RECT  17.633 10.128 18.457 10.968 ;
     RECT  17.171 11.952 18.457 31.032 ;
     RECT  18.457 4.512 18.608 9.144 ;
     RECT  18.457 10.128 18.608 31.032 ;
     RECT  17.665 32.448 18.608 41.448 ;
     RECT  18.025 42.672 18.608 64.968 ;
     RECT  17.5 65.952 18.608 78.744 ;
     RECT  17.507 80.256 18.608 80.52 ;
     RECT  17.197 81.744 18.608 93.48 ;
     RECT  17.557 94.608 18.608 94.632 ;
     RECT  18.608 2.148 18.712 95.052 ;
     RECT  18.712 2.418 18.904 94.782 ;
     RECT  18.904 31.056 18.965 39.288 ;
     RECT  18.904 80.256 18.965 93.384 ;
     RECT  18.965 31.056 19.001 38.232 ;
     RECT  19.001 31.056 19.037 38.136 ;
     RECT  19.037 31.056 19.073 36.984 ;
     RECT  18.904 48.432 19.109 76.872 ;
     RECT  18.904 4.512 19.469 6.6 ;
     RECT  18.904 94.608 19.619 94.632 ;
     RECT  19.037 38.112 19.641 38.136 ;
     RECT  19.109 48.672 19.685 76.872 ;
     RECT  18.965 84.912 19.756 93.384 ;
     RECT  19.756 89.568 19.829 93.384 ;
     RECT  18.965 80.256 19.897 83.592 ;
     RECT  19.685 54.48 19.907 76.872 ;
     RECT  19.756 84.912 19.907 88.536 ;
     RECT  19.829 89.568 19.907 90.072 ;
     RECT  18.904 18.192 19.909 29.64 ;
     RECT  18.904 78.144 19.909 78.744 ;
     RECT  19.073 31.056 19.955 34.2 ;
     RECT  18.904 40.416 19.973 47.352 ;
     RECT  19.955 31.2 20.041 34.2 ;
     RECT  19.073 35.232 20.041 36.984 ;
     RECT  18.965 39.216 20.041 39.288 ;
     RECT  19.973 40.416 20.041 40.68 ;
     RECT  20.041 31.2 20.081 36.984 ;
     RECT  18.904 9.648 20.185 17.208 ;
     RECT  19.909 18.192 20.185 30.024 ;
     RECT  19.907 54.912 20.185 76.872 ;
     RECT  19.469 4.656 20.197 6.6 ;
     RECT  18.904 7.968 20.197 7.992 ;
     RECT  20.185 9.648 20.225 30.024 ;
     RECT  20.081 31.92 20.225 36.984 ;
     RECT  20.041 39.216 20.329 40.68 ;
     RECT  19.907 84.912 20.365 88.44 ;
     RECT  20.225 35.424 20.533 36.984 ;
     RECT  19.897 79.824 20.54 83.592 ;
     RECT  20.185 54.912 20.581 76.968 ;
     RECT  19.909 78.144 20.821 78.792 ;
     RECT  20.54 79.824 20.821 83.64 ;
     RECT  19.685 48.672 20.833 53.4 ;
     RECT  20.581 54.912 20.869 77.112 ;
     RECT  20.365 84.816 20.869 88.44 ;
     RECT  20.197 4.656 21.013 7.992 ;
     RECT  20.329 38.736 21.049 40.68 ;
     RECT  19.973 41.664 21.049 47.352 ;
     RECT  20.869 84.624 21.049 88.44 ;
     RECT  19.907 89.568 21.049 90.024 ;
     RECT  20.869 54.72 21.061 77.112 ;
     RECT  20.821 78.144 21.061 83.64 ;
     RECT  20.533 35.424 21.085 37.656 ;
     RECT  21.049 38.736 21.085 47.352 ;
     RECT  21.085 35.424 21.193 47.352 ;
     RECT  20.225 10.608 21.229 30.024 ;
     RECT  21.193 35.424 21.229 47.448 ;
     RECT  21.061 54.72 21.265 83.64 ;
     RECT  21.049 84.624 21.265 90.024 ;
     RECT  21.013 4.656 21.308 8.472 ;
     RECT  21.229 10.608 21.308 30.6 ;
     RECT  20.225 31.92 21.308 34.2 ;
     RECT  21.229 35.28 21.308 47.448 ;
     RECT  20.833 48.672 21.308 53.688 ;
     RECT  21.265 54.72 21.308 90.024 ;
     RECT  19.829 91.056 21.308 93.384 ;
     RECT  21.308 2.148 21.412 95.052 ;
     RECT  21.412 2.418 21.604 94.782 ;
     RECT  21.604 36.912 21.629 37.704 ;
     RECT  21.629 36.912 21.773 36.936 ;
     RECT  21.604 4.704 21.953 5.544 ;
     RECT  21.604 31.392 21.961 35.928 ;
     RECT  21.604 82.656 22.241 93.72 ;
     RECT  21.604 64.32 22.249 81.528 ;
     RECT  22.241 82.656 22.277 87.384 ;
     RECT  22.277 84 22.307 87.384 ;
     RECT  21.961 31.392 22.313 35.448 ;
     RECT  22.277 82.656 22.313 83.016 ;
     RECT  22.307 84 22.313 84.6 ;
     RECT  22.313 84.144 22.348 84.6 ;
     RECT  21.604 8.16 22.355 9.288 ;
     RECT  21.604 38.736 22.421 63.288 ;
     RECT  21.604 6.816 22.457 6.84 ;
     RECT  22.421 39.216 22.457 63.288 ;
     RECT  22.348 84.144 22.529 84.168 ;
     RECT  22.597 38.112 22.633 38.232 ;
     RECT  21.604 10.464 22.705 22.872 ;
     RECT  21.604 23.856 22.705 30.264 ;
     RECT  22.705 10.464 22.741 30.264 ;
     RECT  22.313 31.392 22.741 35.4 ;
     RECT  22.741 10.464 22.745 35.4 ;
     RECT  21.953 4.992 22.777 5.544 ;
     RECT  22.633 37.92 22.777 38.232 ;
     RECT  22.241 88.368 22.78 93.72 ;
     RECT  22.457 39.696 22.789 63.288 ;
     RECT  22.249 64.32 22.789 81.144 ;
     RECT  22.777 4.992 22.861 6.312 ;
     RECT  22.861 4.992 22.876 6.216 ;
     RECT  22.313 82.656 22.889 82.968 ;
     RECT  22.789 39.696 22.925 81.144 ;
     RECT  22.925 39.744 22.931 81.144 ;
     RECT  22.931 39.744 22.961 78.984 ;
     RECT  22.961 39.744 22.997 57.72 ;
     RECT  22.355 8.544 23.245 9.288 ;
     RECT  22.745 10.464 23.245 32.616 ;
     RECT  22.78 89.52 23.317 93.72 ;
     RECT  22.307 85.728 23.577 87.384 ;
     RECT  22.78 88.368 23.577 88.392 ;
     RECT  23.577 85.728 23.605 88.392 ;
     RECT  22.745 33.696 23.713 35.4 ;
     RECT  22.777 36.432 23.713 38.232 ;
     RECT  22.889 82.944 23.713 82.968 ;
     RECT  23.245 8.544 23.857 32.616 ;
     RECT  23.605 85.392 23.857 88.392 ;
     RECT  23.713 82.944 23.893 83.352 ;
     RECT  23.857 85.392 23.893 88.44 ;
     RECT  22.876 4.992 23.929 5.208 ;
     RECT  22.876 6.192 23.929 6.216 ;
     RECT  22.997 44.688 23.929 57.72 ;
     RECT  22.961 58.944 23.929 78.984 ;
     RECT  23.893 84.96 23.929 88.44 ;
     RECT  23.929 4.992 24.008 6.216 ;
     RECT  23.857 7.92 24.008 32.616 ;
     RECT  23.713 33.696 24.008 38.232 ;
     RECT  22.997 39.744 24.008 43.608 ;
     RECT  23.929 44.688 24.008 78.984 ;
     RECT  22.931 80.88 24.008 81.144 ;
     RECT  23.893 82.176 24.008 83.352 ;
     RECT  23.929 84.336 24.008 88.44 ;
     RECT  23.317 89.52 24.008 94.056 ;
     RECT  24.008 2.148 24.112 95.052 ;
     RECT  24.112 2.418 24.304 94.782 ;
     RECT  24.304 37.872 24.419 79.032 ;
     RECT  24.304 80.304 24.419 94.056 ;
     RECT  24.419 39.888 24.467 79.032 ;
     RECT  24.467 39.888 24.473 78.936 ;
     RECT  24.419 80.304 24.509 88.488 ;
     RECT  24.304 34.128 24.545 36.36 ;
     RECT  24.473 54.096 24.545 78.936 ;
     RECT  24.419 89.472 24.545 94.056 ;
     RECT  24.509 80.784 24.617 85.176 ;
     RECT  24.304 30.912 24.653 32.616 ;
     RECT  24.617 80.784 24.797 83.016 ;
     RECT  24.419 37.872 24.833 38.808 ;
     RECT  24.473 39.888 24.947 53.064 ;
     RECT  24.545 54.096 25.013 76.584 ;
     RECT  25.013 54.096 25.085 63.384 ;
     RECT  24.304 4.704 25.091 5.736 ;
     RECT  24.833 38.16 25.121 38.808 ;
     RECT  24.947 39.888 25.121 49.272 ;
     RECT  25.013 64.608 25.121 76.584 ;
     RECT  24.509 86.208 25.121 88.488 ;
     RECT  25.085 54.096 25.139 62.04 ;
     RECT  24.304 7.92 25.157 8.808 ;
     RECT  25.121 38.784 25.157 38.808 ;
     RECT  25.121 64.608 25.157 74.76 ;
     RECT  25.121 75.84 25.165 76.584 ;
     RECT  25.085 63.024 25.229 63.384 ;
     RECT  24.545 35.28 25.405 36.36 ;
     RECT  25.091 4.704 25.409 5.592 ;
     RECT  25.157 64.608 25.409 74.472 ;
     RECT  24.545 89.472 25.445 93.384 ;
     RECT  25.405 6.672 25.477 6.696 ;
     RECT  25.157 8.784 25.513 8.808 ;
     RECT  24.304 10.08 25.513 10.392 ;
     RECT  24.797 80.784 25.523 81.624 ;
     RECT  24.653 30.96 25.585 32.616 ;
     RECT  24.545 34.128 25.585 34.2 ;
     RECT  24.617 84.288 25.585 85.176 ;
     RECT  25.121 86.208 25.585 86.808 ;
     RECT  25.585 84.288 25.667 86.808 ;
     RECT  24.304 11.376 25.669 29.784 ;
     RECT  25.585 30.96 25.669 34.2 ;
     RECT  25.405 35.28 25.669 36.552 ;
     RECT  25.121 40.608 25.697 49.272 ;
     RECT  25.667 84.288 25.715 86.664 ;
     RECT  25.669 11.376 25.733 36.552 ;
     RECT  25.697 41.664 25.733 49.272 ;
     RECT  24.545 78.144 25.765 78.936 ;
     RECT  25.445 90.048 26.101 93.384 ;
     RECT  25.409 5.184 26.125 5.592 ;
     RECT  25.477 6.672 26.125 7.464 ;
     RECT  25.657 38.832 26.125 38.856 ;
     RECT  25.697 40.608 26.125 40.68 ;
     RECT  24.947 50.544 26.125 53.064 ;
     RECT  25.139 54.096 26.125 57.432 ;
     RECT  25.229 63.264 26.125 63.384 ;
     RECT  25.165 75.84 26.125 76.536 ;
     RECT  24.797 82.992 26.125 83.016 ;
     RECT  25.733 41.904 26.161 49.272 ;
     RECT  26.125 50.544 26.161 57.432 ;
     RECT  25.139 58.992 26.161 62.04 ;
     RECT  25.121 87.888 26.161 88.488 ;
     RECT  25.513 8.784 26.197 10.392 ;
     RECT  25.733 11.376 26.197 30.936 ;
     RECT  26.125 82.992 26.197 83.256 ;
     RECT  25.715 84.288 26.197 85.176 ;
     RECT  25.765 78.144 26.233 79.848 ;
     RECT  26.125 75.6 26.245 76.536 ;
     RECT  26.125 63.264 26.269 63.576 ;
     RECT  26.245 75.504 26.341 76.536 ;
     RECT  26.125 38.832 26.377 39.24 ;
     RECT  26.341 75.504 26.413 76.584 ;
     RECT  26.233 77.664 26.413 79.848 ;
     RECT  26.377 38.832 26.449 39.288 ;
     RECT  26.449 38.736 26.485 39.288 ;
     RECT  26.125 40.416 26.521 40.68 ;
     RECT  26.161 58.656 26.557 62.04 ;
     RECT  26.269 63.072 26.557 63.576 ;
     RECT  26.161 87.888 26.593 88.776 ;
     RECT  26.101 90.048 26.593 94.248 ;
     RECT  26.125 5.184 26.708 7.464 ;
     RECT  26.197 8.784 26.708 30.936 ;
     RECT  25.733 31.92 26.708 36.552 ;
     RECT  26.485 38.736 26.708 39.336 ;
     RECT  26.521 40.32 26.708 40.68 ;
     RECT  26.161 41.904 26.708 57.432 ;
     RECT  26.557 58.656 26.708 63.576 ;
     RECT  25.409 64.608 26.708 74.376 ;
     RECT  26.413 75.504 26.708 79.848 ;
     RECT  25.523 80.832 26.708 81.624 ;
     RECT  26.197 82.608 26.708 85.176 ;
     RECT  25.715 86.208 26.708 86.664 ;
     RECT  26.593 87.888 26.708 94.248 ;
     RECT  26.708 2.148 26.812 95.052 ;
     RECT  26.812 2.418 27.004 94.782 ;
     RECT  27.004 37.584 27.065 48.984 ;
     RECT  27.004 50.4 27.203 63.576 ;
     RECT  27.004 31.728 27.389 36.024 ;
     RECT  27.065 37.584 27.533 42.504 ;
     RECT  27.389 34.704 27.605 36.024 ;
     RECT  27.004 81.36 27.821 83.256 ;
     RECT  27.004 6.096 27.857 6.12 ;
     RECT  27.389 31.728 27.964 33.576 ;
     RECT  27.605 34.704 27.965 35.784 ;
     RECT  27.203 50.4 27.965 63.384 ;
     RECT  27.004 84.336 27.973 86.664 ;
     RECT  27.533 38.208 28.001 42.504 ;
     RECT  27.965 50.4 28.012 62.04 ;
     RECT  27.973 84.336 28.037 86.808 ;
     RECT  27.004 87.888 28.037 94.68 ;
     RECT  28.037 84.912 28.067 86.808 ;
     RECT  28.012 50.4 28.073 55.512 ;
     RECT  27.004 9.072 28.115 30.312 ;
     RECT  28.115 10.08 28.156 30.312 ;
     RECT  27.004 7.344 28.177 7.896 ;
     RECT  27.821 81.36 28.181 82.968 ;
     RECT  27.965 63.216 28.249 63.384 ;
     RECT  27.004 64.608 28.249 74.376 ;
     RECT  28.249 63.216 28.285 74.376 ;
     RECT  27.004 75.504 28.285 80.28 ;
     RECT  27.065 43.632 28.321 48.984 ;
     RECT  28.001 38.4 28.357 42.504 ;
     RECT  28.321 43.632 28.357 49.08 ;
     RECT  28.067 84.912 28.433 84.936 ;
     RECT  28.177 6.912 28.537 7.896 ;
     RECT  28.115 9.072 28.537 9.096 ;
     RECT  28.285 63.216 28.645 80.28 ;
     RECT  28.181 81.36 28.645 82.488 ;
     RECT  28.067 86.208 28.789 86.808 ;
     RECT  28.037 87.888 28.789 93.576 ;
     RECT  28.645 63.216 28.933 82.488 ;
     RECT  28.357 38.4 29.077 49.08 ;
     RECT  28.073 50.4 29.077 53.064 ;
     RECT  28.156 10.08 29.185 10.2 ;
     RECT  28.156 11.28 29.185 30.312 ;
     RECT  28.537 6.912 29.257 9.096 ;
     RECT  29.185 10.08 29.257 30.312 ;
     RECT  28.933 63.12 29.257 82.488 ;
     RECT  28.012 56.496 29.269 62.04 ;
     RECT  29.257 63.12 29.269 82.536 ;
     RECT  29.257 6.912 29.293 30.312 ;
     RECT  27.964 31.728 29.293 33.336 ;
     RECT  28.537 5.472 29.408 5.496 ;
     RECT  29.293 6.912 29.408 33.336 ;
     RECT  27.965 34.704 29.408 35.112 ;
     RECT  28.609 36.24 29.408 36.264 ;
     RECT  29.077 38.4 29.408 53.064 ;
     RECT  28.073 54.336 29.408 55.512 ;
     RECT  29.269 56.496 29.408 82.536 ;
     RECT  28.789 86.208 29.408 93.576 ;
     RECT  28.037 94.656 29.408 94.68 ;
     RECT  29.408 2.148 29.512 95.052 ;
     RECT  29.545 96.336 29.698 96.36 ;
     RECT  29.698 96.336 29.699 96.408 ;
     RECT  29.512 2.418 29.704 95.016 ;
     RECT  29.704 5.472 29.729 5.496 ;
     RECT  29.699 96.384 29.761 96.408 ;
     RECT  29.704 11.232 29.909 15.24 ;
     RECT  29.704 60.048 30.125 76.248 ;
     RECT  29.761 96.384 30.157 96.504 ;
     RECT  29.704 77.28 30.233 95.016 ;
     RECT  30.157 96.384 30.275 97.08 ;
     RECT  29.704 30.816 30.305 33.048 ;
     RECT  29.704 54.096 30.305 57.864 ;
     RECT  29.704 7.2 30.341 7.992 ;
     RECT  30.233 77.568 30.457 95.016 ;
     RECT  30.457 77.568 30.485 94.008 ;
     RECT  30.485 80.064 30.563 94.008 ;
     RECT  29.704 34.08 30.611 36.408 ;
     RECT  30.305 30.816 30.665 32.568 ;
     RECT  29.704 39.936 30.707 53.016 ;
     RECT  30.457 94.992 30.707 95.016 ;
     RECT  29.704 26.64 30.733 29.544 ;
     RECT  30.275 96.384 30.764 96.456 ;
     RECT  30.341 7.2 30.773 7.368 ;
     RECT  30.733 26.64 30.803 29.64 ;
     RECT  30.611 34.08 30.809 34.872 ;
     RECT  30.485 77.568 30.851 78.744 ;
     RECT  30.125 60.048 30.86 75.864 ;
     RECT  29.704 38.016 30.901 38.04 ;
     RECT  30.901 38.016 30.947 38.952 ;
     RECT  30.86 59.76 30.947 75.864 ;
     RECT  29.909 11.664 30.985 15.24 ;
     RECT  29.704 16.32 30.985 25.272 ;
     RECT  30.947 60 31.069 75.864 ;
     RECT  30.665 31.728 31.133 32.568 ;
     RECT  31.093 95.136 31.241 95.16 ;
     RECT  30.707 40.368 31.345 53.016 ;
     RECT  30.764 96.336 31.373 96.456 ;
     RECT  30.697 5.712 31.417 5.736 ;
     RECT  31.345 40.368 31.417 53.16 ;
     RECT  30.305 54.336 31.417 57.864 ;
     RECT  31.373 96.336 31.457 97.08 ;
     RECT  30.803 26.64 31.525 26.664 ;
     RECT  30.563 80.064 31.525 93.768 ;
     RECT  30.947 38.256 31.561 38.952 ;
     RECT  30.985 11.664 31.597 25.272 ;
     RECT  31.525 26.256 31.597 26.664 ;
     RECT  30.851 77.568 31.621 78.696 ;
     RECT  31.417 5.424 31.705 5.736 ;
     RECT  31.597 11.664 31.777 26.664 ;
     RECT  31.525 80.064 31.813 94.056 ;
     RECT  31.705 4.944 31.861 5.736 ;
     RECT  31.381 30.672 31.885 30.696 ;
     RECT  31.417 40.368 31.909 57.864 ;
     RECT  31.669 58.848 31.909 58.872 ;
     RECT  31.561 38.256 31.921 39.24 ;
     RECT  31.909 40.368 31.921 58.872 ;
     RECT  31.069 60 31.921 75.768 ;
     RECT  30.773 7.344 31.957 7.368 ;
     RECT  30.733 8.544 31.957 8.568 ;
     RECT  29.704 9.648 31.957 10.2 ;
     RECT  31.621 77.328 31.957 78.696 ;
     RECT  31.705 3.936 32.108 3.96 ;
     RECT  31.861 4.944 32.108 6.312 ;
     RECT  31.957 7.344 32.108 10.2 ;
     RECT  31.777 11.232 32.108 26.664 ;
     RECT  30.803 27.984 32.108 29.64 ;
     RECT  31.885 30.624 32.108 30.696 ;
     RECT  31.133 31.728 32.108 32.088 ;
     RECT  31.381 33.072 32.108 33.096 ;
     RECT  30.809 34.08 32.108 34.104 ;
     RECT  30.611 36.048 32.108 36.312 ;
     RECT  31.921 38.256 32.108 58.872 ;
     RECT  31.921 59.856 32.108 75.768 ;
     RECT  31.957 77.328 32.108 78.936 ;
     RECT  31.813 80.064 32.108 94.104 ;
     RECT  31.457 96.336 32.147 97.032 ;
     RECT  32.108 2.148 32.212 95.052 ;
     RECT  32.212 2.418 32.245 95.052 ;
     RECT  32.245 2.418 32.404 95.208 ;
     RECT  32.404 37.584 32.501 74.376 ;
     RECT  32.147 96.336 32.579 96.84 ;
     RECT  32.579 96.336 32.645 96.36 ;
     RECT  32.404 75.696 32.717 95.208 ;
     RECT  32.501 37.584 32.933 58.008 ;
     RECT  32.404 10.176 33.005 36.312 ;
     RECT  32.933 37.584 33.005 56.376 ;
     RECT  33.005 16.656 33.077 36.312 ;
     RECT  33.005 10.176 33.107 15.576 ;
     RECT  32.404 5.856 33.329 7.416 ;
     RECT  32.404 3.936 33.613 4.44 ;
     RECT  32.717 75.696 33.635 94.68 ;
     RECT  33.077 34.416 33.721 36.312 ;
     RECT  33.005 37.584 33.721 39 ;
     RECT  33.613 3.168 33.733 4.44 ;
     RECT  33.329 5.856 33.733 7.368 ;
     RECT  33.635 80.064 33.761 94.68 ;
     RECT  33.733 3.168 33.779 7.368 ;
     RECT  33.541 96.816 33.797 96.84 ;
     RECT  33.635 75.696 33.833 78.696 ;
     RECT  32.404 8.496 33.877 9.144 ;
     RECT  33.107 10.176 33.877 13.368 ;
     RECT  33.965 95.136 34.049 95.16 ;
     RECT  33.077 16.656 34.081 33.288 ;
     RECT  33.005 40.032 34.081 56.376 ;
     RECT  32.933 57.408 34.081 58.008 ;
     RECT  32.501 59.04 34.153 74.376 ;
     RECT  33.833 75.696 34.153 77.16 ;
     RECT  33.721 34.416 34.597 39 ;
     RECT  34.597 34.416 34.693 39.048 ;
     RECT  34.081 40.032 34.693 58.008 ;
     RECT  33.779 4.176 34.729 7.368 ;
     RECT  33.877 8.496 34.729 13.368 ;
     RECT  33.107 14.496 34.801 15.576 ;
     RECT  34.081 16.56 34.801 33.288 ;
     RECT  34.729 4.176 34.808 13.368 ;
     RECT  34.801 14.496 34.808 33.288 ;
     RECT  34.693 34.416 34.808 58.008 ;
     RECT  34.153 59.04 34.808 77.16 ;
     RECT  33.833 78.144 34.808 78.696 ;
     RECT  33.761 80.064 34.808 94.104 ;
     RECT  34.808 2.148 34.912 95.052 ;
     RECT  34.912 2.418 35.104 94.782 ;
     RECT  34.117 97.056 35.165 97.08 ;
     RECT  35.104 10.656 35.273 33.096 ;
     RECT  35.104 34.464 35.273 94.104 ;
     RECT  35.273 34.464 35.315 80.904 ;
     RECT  35.273 10.848 35.381 33.096 ;
     RECT  35.315 34.464 35.381 80.808 ;
     RECT  35.381 34.464 35.453 80.664 ;
     RECT  35.273 81.936 35.459 94.104 ;
     RECT  35.453 34.464 35.525 53.928 ;
     RECT  35.104 3.792 35.699 7.752 ;
     RECT  35.381 10.848 35.741 31.224 ;
     RECT  35.104 8.976 35.813 9.672 ;
     RECT  35.459 81.936 35.813 84.6 ;
     RECT  35.459 85.68 35.849 94.104 ;
     RECT  35.453 55.152 35.921 80.664 ;
     RECT  35.699 5.472 35.957 7.752 ;
     RECT  35.921 55.488 35.957 80.664 ;
     RECT  35.957 75.456 35.987 80.664 ;
     RECT  35.741 10.944 36.029 31.224 ;
     RECT  35.957 5.472 36.065 7.416 ;
     RECT  35.381 32.208 36.241 33.096 ;
     RECT  36.029 11.136 36.245 31.224 ;
     RECT  35.849 88.944 36.245 94.104 ;
     RECT  35.813 9.072 36.385 9.672 ;
     RECT  36.245 11.136 36.425 29.64 ;
     RECT  36.245 30.672 36.517 31.224 ;
     RECT  36.241 32.208 36.517 33.384 ;
     RECT  36.385 9.072 36.745 9.768 ;
     RECT  35.987 79.584 36.805 80.664 ;
     RECT  35.813 81.936 36.805 84.36 ;
     RECT  35.525 34.896 36.889 53.928 ;
     RECT  35.957 55.488 36.889 74.376 ;
     RECT  35.699 3.792 36.908 4.488 ;
     RECT  36.908 3.792 36.949 4.92 ;
     RECT  36.517 30.672 36.997 33.384 ;
     RECT  36.889 34.896 36.997 74.376 ;
     RECT  36.425 14.448 37.285 29.64 ;
     RECT  36.997 30.672 37.285 74.376 ;
     RECT  35.849 85.68 37.321 87.672 ;
     RECT  36.065 6.336 37.357 7.416 ;
     RECT  36.745 9.072 37.357 9.912 ;
     RECT  36.949 3.408 37.508 4.92 ;
     RECT  37.357 6.336 37.508 9.912 ;
     RECT  36.425 11.136 37.508 13.416 ;
     RECT  37.285 14.448 37.508 74.376 ;
     RECT  35.987 75.456 37.508 78.504 ;
     RECT  36.805 79.584 37.508 84.36 ;
     RECT  37.321 85.488 37.508 87.672 ;
     RECT  36.245 88.944 37.508 93.768 ;
     RECT  37.508 2.148 37.612 95.052 ;
     RECT  37.612 2.418 37.804 94.782 ;
     RECT  37.804 76.896 37.955 93.768 ;
     RECT  37.804 4.416 37.973 4.488 ;
     RECT  37.955 83.04 37.981 93.768 ;
     RECT  37.804 6.384 38.003 49.56 ;
     RECT  37.981 83.04 38.081 87.576 ;
     RECT  37.981 89.28 38.117 93.768 ;
     RECT  38.117 89.28 38.189 90.264 ;
     RECT  38.003 35.616 38.195 49.56 ;
     RECT  37.955 76.896 38.621 82.008 ;
     RECT  38.195 35.712 38.729 49.56 ;
     RECT  38.117 91.344 38.797 93.768 ;
     RECT  38.003 6.384 38.819 34.632 ;
     RECT  38.819 6.384 38.873 11.16 ;
     RECT  37.973 4.416 39.013 4.44 ;
     RECT  38.081 83.232 39.229 87.576 ;
     RECT  38.729 36.816 39.265 49.56 ;
     RECT  37.804 50.64 39.265 75.72 ;
     RECT  39.229 82.992 39.301 87.576 ;
     RECT  38.819 12.288 39.337 34.632 ;
     RECT  38.729 35.712 39.337 35.832 ;
     RECT  38.189 89.28 39.373 90.072 ;
     RECT  38.797 91.344 39.373 94.584 ;
     RECT  39.013 4.416 39.409 4.632 ;
     RECT  38.873 6.384 39.625 8.28 ;
     RECT  38.621 76.896 39.661 80.568 ;
     RECT  39.301 82.992 39.685 87.864 ;
     RECT  39.337 12.288 39.769 35.832 ;
     RECT  39.265 36.816 39.769 75.72 ;
     RECT  38.621 81.936 39.769 82.008 ;
     RECT  39.685 82.992 39.769 88.104 ;
     RECT  39.373 89.28 39.769 94.584 ;
     RECT  39.409 4.368 39.877 4.632 ;
     RECT  38.873 9.792 39.877 11.16 ;
     RECT  39.769 12.288 39.877 75.72 ;
     RECT  39.661 76.896 39.877 80.808 ;
     RECT  39.877 4.368 40.165 5.256 ;
     RECT  39.625 6.336 40.165 8.28 ;
     RECT  37.804 2.784 40.208 2.808 ;
     RECT  40.165 4.368 40.208 8.28 ;
     RECT  39.877 9.792 40.208 75.72 ;
     RECT  39.877 76.896 40.208 80.904 ;
     RECT  39.769 81.936 40.208 94.584 ;
     RECT  40.208 2.148 40.312 95.052 ;
     RECT  40.312 2.418 40.504 94.782 ;
     RECT  40.504 12.24 40.637 39.528 ;
     RECT  40.504 40.608 40.637 75.768 ;
     RECT  40.504 80.256 40.709 89.496 ;
     RECT  40.709 80.256 40.997 83.784 ;
     RECT  40.709 84.768 41.033 89.496 ;
     RECT  40.504 4.944 41.069 11.16 ;
     RECT  40.997 80.256 41.069 82.296 ;
     RECT  40.504 2.784 41.075 3.96 ;
     RECT  41.069 10.272 41.105 11.16 ;
     RECT  41.069 4.944 41.249 9.144 ;
     RECT  41.249 7.632 41.315 9.144 ;
     RECT  41.249 4.944 41.465 6.648 ;
     RECT  41.033 85.152 41.537 88.392 ;
     RECT  41.069 80.256 41.605 82.248 ;
     RECT  40.504 76.848 41.645 78.168 ;
     RECT  40.637 40.608 41.677 42.072 ;
     RECT  40.637 43.104 41.677 75.768 ;
     RECT  41.605 80.208 41.708 82.248 ;
     RECT  41.677 40.608 41.713 75.768 ;
     RECT  41.645 77.616 41.713 78.168 ;
     RECT  40.504 91.872 41.785 93.48 ;
     RECT  41.708 79.92 41.795 82.248 ;
     RECT  41.713 77.616 41.797 78.648 ;
     RECT  40.637 12.24 41.821 39.336 ;
     RECT  41.713 40.608 41.821 76.056 ;
     RECT  41.821 12.24 41.825 76.056 ;
     RECT  41.785 91.824 41.825 93.48 ;
     RECT  41.537 85.152 41.939 88.008 ;
     RECT  40.504 90.576 42.001 90.6 ;
     RECT  41.825 91.824 42.001 93.048 ;
     RECT  41.315 7.92 42.145 9.144 ;
     RECT  41.033 89.472 42.181 89.496 ;
     RECT  42.001 90.576 42.181 93.048 ;
     RECT  42.145 7.92 42.229 9.288 ;
     RECT  41.105 10.512 42.229 11.16 ;
     RECT  41.825 12.24 42.229 75.768 ;
     RECT  40.997 83.28 42.236 83.784 ;
     RECT  41.075 2.784 42.397 3.864 ;
     RECT  42.397 2.592 42.541 3.864 ;
     RECT  41.795 80.064 42.541 82.248 ;
     RECT  42.236 83.28 42.541 84.072 ;
     RECT  41.785 94.512 42.721 94.536 ;
     RECT  41.939 85.392 42.757 88.008 ;
     RECT  42.181 89.472 42.757 93.048 ;
     RECT  42.541 2.592 42.908 4.248 ;
     RECT  41.465 5.232 42.908 6.648 ;
     RECT  42.229 7.92 42.908 75.768 ;
     RECT  41.797 77.616 42.908 77.88 ;
     RECT  42.541 80.064 42.908 84.072 ;
     RECT  42.757 85.392 42.908 93.048 ;
     RECT  42.721 94.512 42.908 94.632 ;
     RECT  42.908 2.148 43.012 95.052 ;
     RECT  43.012 2.418 43.204 94.782 ;
     RECT  43.204 5.808 43.265 33.096 ;
     RECT  43.204 94.032 43.373 94.632 ;
     RECT  43.204 34.464 43.517 34.968 ;
     RECT  43.265 5.808 43.589 32.856 ;
     RECT  43.204 2.592 43.625 4.248 ;
     RECT  43.204 55.44 43.667 77.592 ;
     RECT  43.625 2.592 43.697 2.616 ;
     RECT  43.204 90.528 43.697 90.6 ;
     RECT  43.204 79.056 43.811 89.496 ;
     RECT  43.697 90.528 43.841 90.552 ;
     RECT  43.625 4.224 43.877 4.248 ;
     RECT  43.667 76.608 43.877 76.632 ;
     RECT  43.667 55.44 43.913 75.24 ;
     RECT  43.811 79.44 43.913 89.496 ;
     RECT  43.913 79.44 43.955 86.808 ;
     RECT  43.589 5.808 44.201 32.232 ;
     RECT  44.201 6.24 44.237 32.232 ;
     RECT  43.204 42.576 44.293 47.112 ;
     RECT  43.517 34.464 44.305 34.92 ;
     RECT  44.237 6.24 44.489 32.04 ;
     RECT  44.489 6.24 44.525 22.92 ;
     RECT  43.204 48.288 44.561 54.168 ;
     RECT  44.561 48.672 44.633 54.168 ;
     RECT  44.293 42.576 44.737 47.304 ;
     RECT  44.633 51.792 44.737 54.168 ;
     RECT  43.913 55.44 44.737 75.192 ;
     RECT  43.204 36.336 44.809 41.496 ;
     RECT  43.204 91.872 44.809 93.048 ;
     RECT  43.373 94.032 44.809 94.056 ;
     RECT  43.913 87.888 44.831 89.496 ;
     RECT  44.377 78.048 44.869 78.072 ;
     RECT  44.305 33.936 44.917 34.92 ;
     RECT  44.917 33.696 45.025 34.92 ;
     RECT  44.737 51.792 45.061 75.192 ;
     RECT  44.809 36.24 45.097 41.496 ;
     RECT  44.737 42.528 45.097 47.304 ;
     RECT  45.025 33.696 45.169 35.256 ;
     RECT  45.097 36.24 45.169 47.304 ;
     RECT  43.955 79.44 45.169 81.96 ;
     RECT  43.955 83.184 45.169 86.808 ;
     RECT  44.525 8.016 45.493 22.92 ;
     RECT  44.489 23.904 45.493 32.04 ;
     RECT  45.061 51.792 45.565 75.24 ;
     RECT  44.869 78.048 45.565 78.408 ;
     RECT  45.169 79.44 45.565 86.808 ;
     RECT  45.025 3.888 45.608 3.912 ;
     RECT  45.025 5.088 45.608 5.112 ;
     RECT  44.525 6.24 45.608 6.648 ;
     RECT  45.493 8.016 45.608 32.04 ;
     RECT  45.169 33.696 45.608 47.304 ;
     RECT  44.633 48.672 45.608 50.664 ;
     RECT  45.565 51.792 45.608 75.768 ;
     RECT  45.097 76.896 45.608 76.92 ;
     RECT  45.565 78.048 45.608 86.808 ;
     RECT  44.831 87.888 45.608 90.264 ;
     RECT  44.809 91.872 45.608 94.056 ;
     RECT  45.608 2.148 45.712 95.052 ;
     RECT  45.712 2.418 45.904 94.872 ;
     RECT  45.904 8.496 45.965 9.048 ;
     RECT  45.904 77.856 46.019 88.104 ;
     RECT  45.904 92.4 46.019 94.872 ;
     RECT  46.019 86.496 46.037 88.104 ;
     RECT  45.904 89.472 46.06 91.368 ;
     RECT  46.06 89.472 46.067 90.072 ;
     RECT  45.904 33.072 46.109 44.904 ;
     RECT  45.904 57.024 46.145 74.424 ;
     RECT  45.904 75.744 46.145 76.056 ;
     RECT  46.145 75.744 46.181 75.96 ;
     RECT  45.904 3.312 46.253 4.536 ;
     RECT  46.145 57.168 46.289 74.424 ;
     RECT  45.904 55.776 46.397 55.992 ;
     RECT  46.037 86.592 46.499 88.104 ;
     RECT  46.019 77.856 46.595 85.512 ;
     RECT  46.109 33.12 46.613 44.904 ;
     RECT  46.613 35.76 46.721 44.904 ;
     RECT  45.904 27.648 46.793 32.04 ;
     RECT  46.019 92.4 46.793 93.096 ;
     RECT  45.904 5.616 46.865 5.64 ;
     RECT  46.793 27.648 46.865 31.896 ;
     RECT  46.865 31.488 46.901 31.896 ;
     RECT  45.904 23.904 46.933 26.664 ;
     RECT  46.865 27.648 46.933 30.456 ;
     RECT  46.253 3.312 46.937 3.336 ;
     RECT  45.904 10.32 46.969 22.872 ;
     RECT  46.933 23.904 46.969 30.456 ;
     RECT  45.904 46.56 46.969 47.784 ;
     RECT  46.06 91.344 46.969 91.368 ;
     RECT  46.721 41.328 47.027 44.904 ;
     RECT  47.027 41.424 47.045 44.904 ;
     RECT  46.019 94.32 47.077 94.872 ;
     RECT  46.253 4.512 47.149 4.536 ;
     RECT  46.499 86.592 47.149 87.912 ;
     RECT  46.721 35.76 47.171 40.2 ;
     RECT  45.904 52.224 47.185 54.648 ;
     RECT  47.185 52.224 47.257 54.744 ;
     RECT  46.397 55.776 47.257 55.8 ;
     RECT  46.067 89.52 47.257 89.544 ;
     RECT  46.289 57.168 47.285 63.384 ;
     RECT  46.289 64.608 47.285 74.424 ;
     RECT  47.257 89.328 47.317 89.544 ;
     RECT  47.317 89.136 47.329 89.544 ;
     RECT  47.045 42.768 47.333 44.904 ;
     RECT  46.181 75.744 47.333 75.816 ;
     RECT  45.965 8.544 47.365 9.048 ;
     RECT  47.257 52.224 47.365 55.8 ;
     RECT  47.285 57.168 47.365 74.424 ;
     RECT  46.595 77.856 47.365 84.072 ;
     RECT  46.595 85.152 47.557 85.512 ;
     RECT  47.149 86.496 47.557 87.912 ;
     RECT  47.365 52.224 47.581 74.424 ;
     RECT  45.904 6.624 47.708 6.744 ;
     RECT  47.708 6.624 47.749 7.176 ;
     RECT  47.365 8.208 47.749 9.048 ;
     RECT  47.333 75.792 47.761 75.816 ;
     RECT  47.581 51.888 47.797 74.424 ;
     RECT  46.613 33.12 47.833 34.68 ;
     RECT  47.365 77.712 47.833 84.072 ;
     RECT  47.557 85.152 47.833 87.912 ;
     RECT  47.833 33.12 47.869 34.776 ;
     RECT  47.171 35.76 47.869 39.096 ;
     RECT  46.969 10.32 47.941 30.456 ;
     RECT  46.901 31.488 47.941 31.512 ;
     RECT  47.333 44.064 47.977 44.904 ;
     RECT  46.969 45.888 47.977 47.88 ;
     RECT  45.904 48.96 47.977 50.856 ;
     RECT  47.797 51.888 47.977 74.664 ;
     RECT  46.969 91.344 47.977 92.232 ;
     RECT  47.941 10.32 48.077 31.512 ;
     RECT  47.869 33.12 48.077 39.096 ;
     RECT  47.749 6.624 48.085 9.048 ;
     RECT  47.045 41.424 48.085 41.688 ;
     RECT  47.761 75.792 48.157 76.296 ;
     RECT  47.833 77.712 48.157 87.912 ;
     RECT  47.977 91.344 48.181 92.28 ;
     RECT  47.077 93.504 48.181 94.872 ;
     RECT  47.149 4.512 48.265 4.968 ;
     RECT  48.085 6.048 48.265 9.192 ;
     RECT  47.977 44.064 48.265 47.88 ;
     RECT  47.977 48.96 48.265 74.664 ;
     RECT  48.265 4.512 48.308 9.192 ;
     RECT  48.077 10.32 48.308 39.096 ;
     RECT  47.171 40.128 48.308 40.152 ;
     RECT  48.085 41.232 48.308 41.688 ;
     RECT  47.333 42.768 48.308 42.792 ;
     RECT  48.265 44.064 48.308 74.664 ;
     RECT  48.157 75.792 48.308 76.488 ;
     RECT  48.157 77.664 48.308 87.912 ;
     RECT  47.329 88.896 48.308 89.544 ;
     RECT  48.181 91.344 48.308 94.872 ;
     RECT  48.308 2.148 48.412 95.052 ;
     RECT  48.412 2.418 48.604 94.782 ;
     RECT  48.604 58.128 48.701 93 ;
     RECT  48.604 44.112 48.809 46.824 ;
     RECT  48.604 41.184 48.881 42.792 ;
     RECT  48.604 13.056 49.061 39.432 ;
     RECT  49.061 13.344 49.241 39.432 ;
     RECT  48.701 58.128 49.349 89.304 ;
     RECT  49.349 58.128 49.379 79.512 ;
     RECT  49.349 80.784 49.421 89.304 ;
     RECT  48.701 90.576 49.493 93 ;
     RECT  48.604 7.968 49.612 10.968 ;
     RECT  48.881 41.184 49.705 42.648 ;
     RECT  49.379 58.128 49.709 79.032 ;
     RECT  48.604 4.944 49.717 6.648 ;
     RECT  49.717 4.512 49.763 6.648 ;
     RECT  49.763 6.288 49.921 6.648 ;
     RECT  49.612 7.968 49.921 8.76 ;
     RECT  49.241 13.632 49.957 39.432 ;
     RECT  49.705 40.512 49.957 42.648 ;
     RECT  48.604 48.384 49.957 57.048 ;
     RECT  49.709 58.128 49.957 74.424 ;
     RECT  49.957 13.632 49.993 42.744 ;
     RECT  48.809 44.16 49.993 46.824 ;
     RECT  48.604 94.032 49.993 94.392 ;
     RECT  49.612 9.936 50.029 10.968 ;
     RECT  49.813 12.336 50.029 12.36 ;
     RECT  49.493 91.152 50.137 93 ;
     RECT  49.993 94.032 50.137 94.872 ;
     RECT  49.993 13.632 50.149 46.824 ;
     RECT  50.149 13.632 50.204 47.064 ;
     RECT  49.957 48.384 50.204 74.424 ;
     RECT  49.709 75.456 50.569 79.032 ;
     RECT  49.421 80.784 50.569 84.984 ;
     RECT  50.137 91.152 50.605 94.872 ;
     RECT  50.029 9.936 50.713 12.36 ;
     RECT  50.204 13.632 50.713 74.424 ;
     RECT  50.569 75.456 50.713 84.984 ;
     RECT  49.421 86.016 50.713 89.304 ;
     RECT  50.605 91.056 50.732 94.872 ;
     RECT  49.921 6.288 50.869 8.76 ;
     RECT  50.713 9.936 50.869 12.504 ;
     RECT  49.763 4.512 51.008 5.064 ;
     RECT  50.869 6.288 51.008 12.504 ;
     RECT  50.713 13.632 51.008 89.304 ;
     RECT  50.732 90.48 51.008 94.872 ;
     RECT  51.008 2.148 51.112 95.052 ;
     RECT  51.112 2.418 51.304 94.872 ;
     RECT  51.304 33.552 51.653 41.736 ;
     RECT  51.304 43.056 51.689 89.448 ;
     RECT  51.689 43.056 51.761 81.624 ;
     RECT  51.304 26.832 51.941 32.568 ;
     RECT  51.653 33.552 51.977 41.496 ;
     RECT  51.304 10.704 52.013 12.36 ;
     RECT  52.013 11.136 52.049 12.36 ;
     RECT  51.941 26.832 52.193 29.88 ;
     RECT  51.304 90.624 52.265 94.872 ;
     RECT  51.761 43.056 52.297 81.432 ;
     RECT  52.049 11.136 52.409 11.976 ;
     RECT  51.304 13.632 52.409 25.848 ;
     RECT  52.409 14.448 52.441 25.848 ;
     RECT  52.193 26.832 52.441 29.592 ;
     RECT  51.689 82.656 52.445 89.448 ;
     RECT  52.265 90.624 52.453 94.392 ;
     RECT  51.304 7.632 52.481 9.384 ;
     RECT  51.941 31.44 52.508 32.568 ;
     RECT  51.977 33.552 52.508 35.736 ;
     RECT  52.453 90.576 52.525 94.392 ;
     RECT  51.304 6.288 52.585 6.408 ;
     RECT  52.585 6.288 52.621 6.6 ;
     RECT  52.481 8.496 52.693 9.384 ;
     RECT  51.977 36.72 52.693 41.496 ;
     RECT  52.297 42.528 52.693 81.432 ;
     RECT  52.693 36.72 52.697 81.432 ;
     RECT  52.621 6.096 52.739 6.6 ;
     RECT  52.697 81.072 53.084 81.432 ;
     RECT  52.508 31.44 53.173 35.736 ;
     RECT  52.441 14.448 53.485 29.592 ;
     RECT  53.485 14.448 53.557 29.64 ;
     RECT  52.445 83.232 53.557 89.448 ;
     RECT  52.525 90.576 53.557 91.512 ;
     RECT  52.525 92.736 53.557 94.392 ;
     RECT  52.739 6.576 53.708 6.6 ;
     RECT  52.693 8.496 53.708 9.816 ;
     RECT  52.409 11.136 53.708 11.448 ;
     RECT  53.557 14.208 53.708 29.64 ;
     RECT  53.173 31.008 53.708 35.736 ;
     RECT  52.697 36.72 53.708 45.48 ;
     RECT  52.697 46.464 53.708 80.088 ;
     RECT  53.084 81.072 53.708 81.912 ;
     RECT  53.557 83.232 53.708 94.392 ;
     RECT  53.708 2.148 53.812 95.052 ;
     RECT  53.812 2.418 53.917 95.052 ;
     RECT  53.917 2.418 54.004 95.16 ;
     RECT  54.004 26.784 54.065 37.704 ;
     RECT  54.004 5.52 54.101 12.792 ;
     RECT  53.521 96.336 54.133 96.36 ;
     RECT  54.004 38.976 54.209 81.624 ;
     RECT  54.004 82.656 54.245 95.16 ;
     RECT  54.245 82.656 54.281 87.576 ;
     RECT  54.133 96.336 54.323 97.08 ;
     RECT  54.209 51.12 54.389 81.624 ;
     RECT  54.389 51.12 54.533 76.536 ;
     RECT  54.245 88.656 54.649 95.16 ;
     RECT  54.065 33.792 54.803 37.704 ;
     RECT  54.389 77.568 54.821 81.624 ;
     RECT  54.209 38.976 54.929 50.136 ;
     RECT  54.101 5.52 55.001 10.008 ;
     RECT  54.533 59.76 55.001 76.536 ;
     RECT  54.533 51.12 55.037 58.584 ;
     RECT  54.065 26.784 55.105 32.52 ;
     RECT  54.803 33.792 55.105 37.464 ;
     RECT  55.001 8.448 55.187 10.008 ;
     RECT  54.281 83.856 55.187 87.576 ;
     RECT  54.929 48.144 55.213 50.136 ;
     RECT  55.037 51.12 55.213 57.48 ;
     RECT  54.649 88.656 55.235 94.392 ;
     RECT  55.187 83.856 55.285 86.088 ;
     RECT  55.187 9.552 55.325 10.008 ;
     RECT  55.187 87.072 55.333 87.576 ;
     RECT  55.235 88.656 55.333 92.472 ;
     RECT  55.037 58.464 55.42 58.584 ;
     RECT  55.333 87.072 55.42 92.472 ;
     RECT  54.323 97.056 55.469 97.08 ;
     RECT  55.001 59.856 55.525 76.536 ;
     RECT  54.821 77.568 55.525 81.432 ;
     RECT  54.004 14.448 55.609 25.032 ;
     RECT  55.609 14.448 55.681 25.32 ;
     RECT  55.105 26.784 55.681 37.464 ;
     RECT  55.235 93.456 55.717 94.392 ;
     RECT  54.929 38.976 55.789 47.16 ;
     RECT  55.525 59.856 55.789 81.432 ;
     RECT  54.281 82.656 55.789 82.68 ;
     RECT  54.101 11.136 55.861 12.792 ;
     RECT  55.789 59.856 56.077 82.68 ;
     RECT  55.681 14.448 56.185 37.464 ;
     RECT  56.077 59.856 56.185 82.776 ;
     RECT  55.42 88.656 56.245 92.472 ;
     RECT  55.717 93.456 56.245 94.632 ;
     RECT  56.185 14.4 56.257 37.464 ;
     RECT  55.187 8.448 56.293 8.52 ;
     RECT  55.321 4.512 56.408 4.536 ;
     RECT  55.001 5.52 56.408 7.464 ;
     RECT  56.293 8.448 56.408 9 ;
     RECT  55.861 10.272 56.408 12.792 ;
     RECT  56.257 14.4 56.408 37.656 ;
     RECT  55.789 38.736 56.408 47.16 ;
     RECT  55.213 48.144 56.408 57.48 ;
     RECT  55.42 58.464 56.408 58.536 ;
     RECT  56.185 59.808 56.408 82.776 ;
     RECT  55.285 83.808 56.408 86.088 ;
     RECT  55.42 87.072 56.408 87.576 ;
     RECT  56.245 88.656 56.408 94.632 ;
     RECT  56.408 2.148 56.512 95.052 ;
     RECT  55.717 97.008 56.581 97.032 ;
     RECT  56.512 2.418 56.704 94.782 ;
     RECT  56.581 96.912 56.725 97.032 ;
     RECT  56.725 96.816 56.915 97.032 ;
     RECT  56.704 51.456 56.945 94.632 ;
     RECT  56.945 83.28 57.011 94.632 ;
     RECT  56.915 97.008 57.011 97.032 ;
     RECT  56.704 5.52 57.053 9 ;
     RECT  56.945 51.456 57.053 82.248 ;
     RECT  57.053 5.52 57.089 6.12 ;
     RECT  57.011 83.28 57.161 85.128 ;
     RECT  57.053 7.2 57.269 9 ;
     RECT  57.053 51.6 57.413 82.248 ;
     RECT  56.704 13.632 57.521 45.576 ;
     RECT  56.704 3.936 57.587 4.536 ;
     RECT  56.704 12.096 57.697 12.312 ;
     RECT  57.269 7.68 57.701 9 ;
     RECT  57.521 39.264 57.733 45.576 ;
     RECT  56.704 46.8 57.733 50.328 ;
     RECT  57.521 13.632 57.737 37.896 ;
     RECT  57.413 58.512 57.737 82.248 ;
     RECT  57.089 5.712 57.773 6.12 ;
     RECT  57.737 78 57.773 82.248 ;
     RECT  57.697 11.424 57.805 12.504 ;
     RECT  57.737 26.784 57.953 37.896 ;
     RECT  57.737 58.512 57.989 76.584 ;
     RECT  57.011 86.544 58.013 94.632 ;
     RECT  57.701 8.448 58.021 9 ;
     RECT  57.733 39.264 58.061 50.376 ;
     RECT  57.805 10.464 58.093 12.504 ;
     RECT  58.013 86.544 58.124 95.16 ;
     RECT  58.061 39.312 58.133 50.136 ;
     RECT  58.124 86.16 58.165 95.16 ;
     RECT  58.093 10.368 58.237 12.504 ;
     RECT  57.737 13.632 58.237 25.608 ;
     RECT  57.733 97.056 58.277 97.08 ;
     RECT  57.773 6 58.309 6.12 ;
     RECT  57.413 51.6 58.345 57.432 ;
     RECT  57.161 83.28 58.357 84.408 ;
     RECT  58.309 6 58.381 6.696 ;
     RECT  58.165 85.44 58.709 95.16 ;
     RECT  58.237 10.368 58.789 25.608 ;
     RECT  57.773 78 58.885 81.72 ;
     RECT  58.357 82.704 58.885 84.408 ;
     RECT  58.381 6 58.981 7.416 ;
     RECT  58.021 8.448 58.981 9.144 ;
     RECT  57.989 58.512 58.981 76.488 ;
     RECT  58.885 78 58.981 84.408 ;
     RECT  57.587 3.936 59.108 3.96 ;
     RECT  58.981 6 59.108 9.144 ;
     RECT  58.789 10.368 59.108 25.704 ;
     RECT  57.953 26.784 59.108 37.656 ;
     RECT  58.133 39.312 59.108 45.48 ;
     RECT  58.133 46.464 59.108 50.136 ;
     RECT  58.345 51.12 59.108 57.432 ;
     RECT  58.981 58.512 59.108 76.536 ;
     RECT  58.981 77.52 59.108 84.408 ;
     RECT  58.709 85.44 59.108 95.052 ;
     RECT  59.108 2.148 59.212 95.052 ;
     RECT  59.212 2.418 59.404 94.872 ;
     RECT  59.404 80.832 59.609 84.12 ;
     RECT  59.404 6.048 59.681 57.48 ;
     RECT  59.404 78.048 59.717 79.8 ;
     RECT  59.404 85.2 59.753 94.872 ;
     RECT  59.753 89.76 59.897 94.872 ;
     RECT  59.681 6.288 59.939 57.48 ;
     RECT  59.939 6.288 60.437 50.376 ;
     RECT  59.609 80.88 60.437 84.12 ;
     RECT  59.753 85.2 60.473 88.728 ;
     RECT  59.939 51.36 60.545 57.48 ;
     RECT  60.437 40.368 60.581 50.376 ;
     RECT  60.473 87.552 60.581 88.728 ;
     RECT  59.404 4.512 60.709 4.776 ;
     RECT  60.437 6.288 60.709 39.336 ;
     RECT  60.437 80.88 60.709 83.688 ;
     RECT  60.709 4.512 60.755 39.336 ;
     RECT  60.545 54.336 60.908 57.48 ;
     RECT  59.404 58.464 60.908 76.776 ;
     RECT  60.755 4.512 60.997 5.832 ;
     RECT  59.717 78.048 61.093 79.752 ;
     RECT  60.581 42.768 61.225 50.376 ;
     RECT  60.545 51.36 61.225 53.352 ;
     RECT  60.581 87.648 61.333 88.728 ;
     RECT  59.897 90 61.333 94.872 ;
     RECT  61.093 78 61.477 79.848 ;
     RECT  60.709 80.832 61.477 83.688 ;
     RECT  60.755 7.152 61.621 39.336 ;
     RECT  60.581 40.368 61.621 41.592 ;
     RECT  60.908 54.336 61.621 76.776 ;
     RECT  61.477 78 61.621 83.688 ;
     RECT  60.973 2.256 61.808 2.28 ;
     RECT  60.997 3.696 61.808 5.832 ;
     RECT  61.621 7.152 61.808 41.592 ;
     RECT  61.225 42.768 61.808 53.352 ;
     RECT  61.621 54.336 61.808 83.688 ;
     RECT  60.473 85.2 61.808 86.568 ;
     RECT  61.333 87.648 61.808 94.872 ;
     RECT  61.808 2.148 61.912 95.052 ;
     RECT  61.912 2.418 62.104 94.872 ;
     RECT  62.104 3.408 62.129 26.856 ;
     RECT  62.129 3.408 62.201 25.224 ;
     RECT  62.104 27.84 62.201 86.664 ;
     RECT  62.201 40.32 62.417 86.664 ;
     RECT  62.201 3.408 62.525 8.28 ;
     RECT  62.417 40.368 62.525 86.664 ;
     RECT  62.104 90.528 62.525 94.872 ;
     RECT  62.525 46.8 62.705 48.456 ;
     RECT  62.525 49.584 62.713 86.664 ;
     RECT  62.525 40.368 62.741 45.72 ;
     RECT  62.713 78.24 62.771 86.664 ;
     RECT  62.525 6.096 62.819 8.28 ;
     RECT  62.104 87.648 62.849 89.496 ;
     RECT  62.741 40.416 63.011 45.576 ;
     RECT  62.525 3.408 63.101 5.112 ;
     RECT  62.771 78.24 63.209 84.984 ;
     RECT  62.201 9.264 63.317 25.224 ;
     RECT  62.129 26.208 63.349 26.856 ;
     RECT  62.201 27.84 63.349 39.288 ;
     RECT  63.011 42.48 63.353 45.576 ;
     RECT  62.713 49.584 63.461 77.112 ;
     RECT  62.819 6.912 63.529 8.28 ;
     RECT  63.317 9.888 63.601 25.224 ;
     RECT  63.349 26.208 63.601 39.288 ;
     RECT  62.771 86.016 63.601 86.664 ;
     RECT  63.461 49.584 63.733 77.064 ;
     RECT  62.705 46.848 63.781 48.456 ;
     RECT  62.849 88.368 63.829 89.496 ;
     RECT  62.525 90.816 63.829 94.872 ;
     RECT  63.353 45.168 63.889 45.576 ;
     RECT  63.781 46.656 63.889 48.456 ;
     RECT  63.529 6.912 63.925 8.904 ;
     RECT  63.209 78.48 64.069 84.984 ;
     RECT  63.601 86.016 64.069 87.288 ;
     RECT  63.925 6.048 64.249 8.904 ;
     RECT  64.069 78.48 64.316 87.288 ;
     RECT  63.829 88.368 64.316 94.872 ;
     RECT  63.601 9.888 64.321 39.288 ;
     RECT  63.011 40.416 64.321 41.496 ;
     RECT  63.889 45.168 64.393 48.456 ;
     RECT  63.733 49.536 64.393 77.064 ;
     RECT  63.101 3.408 64.508 4.872 ;
     RECT  64.249 6 64.508 8.904 ;
     RECT  64.321 9.888 64.508 41.496 ;
     RECT  63.353 42.48 64.508 44.184 ;
     RECT  64.393 45.168 64.508 77.064 ;
     RECT  64.316 78.48 64.508 94.872 ;
     RECT  64.508 2.148 64.612 95.052 ;
     RECT  64.612 2.418 64.804 94.872 ;
     RECT  64.804 78.24 65.009 87.816 ;
     RECT  64.804 89.232 65.045 94.872 ;
     RECT  64.804 34.656 65.075 77.016 ;
     RECT  65.075 35.232 65.081 77.016 ;
     RECT  65.081 54.432 65.117 77.016 ;
     RECT  65.117 54.432 65.297 57.096 ;
     RECT  64.804 2.832 65.305 4.632 ;
     RECT  65.009 86.64 65.305 87.816 ;
     RECT  65.081 35.232 65.411 53.4 ;
     RECT  65.411 40.848 65.441 45.624 ;
     RECT  65.297 54.672 65.477 57.096 ;
     RECT  64.804 5.76 65.507 31.224 ;
     RECT  65.507 6.288 65.585 31.224 ;
     RECT  65.305 86.736 65.621 87.816 ;
     RECT  65.411 35.232 65.629 39.864 ;
     RECT  64.804 32.304 65.729 33.624 ;
     RECT  65.009 78.24 65.729 85.416 ;
     RECT  65.585 27.648 65.869 31.224 ;
     RECT  65.729 32.304 65.869 33.576 ;
     RECT  65.117 58.08 65.869 77.016 ;
     RECT  65.729 78.24 65.869 84.36 ;
     RECT  65.621 87.264 66.013 87.816 ;
     RECT  65.045 89.232 66.013 89.784 ;
     RECT  65.477 56.496 66.085 57.096 ;
     RECT  65.869 58.08 66.085 84.36 ;
     RECT  65.629 35.232 66.121 38.856 ;
     RECT  66.085 56.496 66.125 84.36 ;
     RECT  66.013 87.264 66.193 89.784 ;
     RECT  65.045 90.816 66.193 94.872 ;
     RECT  65.411 46.656 66.301 53.4 ;
     RECT  65.477 54.672 66.301 55.512 ;
     RECT  65.305 3.408 66.445 4.632 ;
     RECT  65.441 40.848 66.517 41.496 ;
     RECT  65.441 42.576 66.517 45.624 ;
     RECT  66.301 46.656 66.517 55.512 ;
     RECT  66.125 56.496 66.517 77.112 ;
     RECT  66.517 40.848 66.589 45.624 ;
     RECT  66.517 46.656 66.589 77.112 ;
     RECT  65.585 6.288 66.661 26.664 ;
     RECT  65.869 27.648 66.661 33.576 ;
     RECT  66.121 34.752 66.661 38.856 ;
     RECT  65.629 39.84 66.661 39.864 ;
     RECT  66.661 6.288 67.093 33.576 ;
     RECT  66.661 34.752 67.093 39.864 ;
     RECT  66.589 40.848 67.093 77.112 ;
     RECT  66.125 78.24 67.093 81.672 ;
     RECT  66.125 82.752 67.093 84.36 ;
     RECT  65.729 85.392 67.093 85.416 ;
     RECT  66.445 3.408 67.208 4.968 ;
     RECT  67.093 6.288 67.208 39.864 ;
     RECT  67.093 40.848 67.208 81.672 ;
     RECT  67.093 82.752 67.208 85.416 ;
     RECT  66.193 87.264 67.208 94.872 ;
     RECT  67.208 2.148 67.312 95.052 ;
     RECT  67.312 2.418 67.504 94.872 ;
     RECT  67.504 2.592 67.619 29.544 ;
     RECT  67.504 47.328 67.619 85.512 ;
     RECT  67.619 47.328 67.637 55.512 ;
     RECT  67.619 2.592 67.667 25.032 ;
     RECT  67.504 30.864 67.673 36.024 ;
     RECT  67.504 88.176 67.745 93.528 ;
     RECT  67.673 30.864 67.817 33.576 ;
     RECT  67.637 47.376 67.853 55.512 ;
     RECT  67.745 88.32 67.853 93.528 ;
     RECT  67.619 56.496 67.889 85.512 ;
     RECT  67.889 56.496 67.961 76.92 ;
     RECT  67.673 34.752 68.321 36.024 ;
     RECT  67.961 56.496 68.357 75.192 ;
     RECT  67.504 37.392 68.387 41.448 ;
     RECT  67.619 26.208 68.428 27.288 ;
     RECT  67.667 2.592 68.429 24.984 ;
     RECT  67.889 77.952 68.492 85.512 ;
     RECT  67.619 28.56 68.497 29.544 ;
     RECT  68.357 56.592 68.501 56.616 ;
     RECT  68.357 57.6 68.501 75.192 ;
     RECT  68.429 2.592 68.524 4.44 ;
     RECT  67.853 47.376 68.641 54.984 ;
     RECT  68.492 77.952 68.645 85.656 ;
     RECT  67.504 42.528 68.681 46.248 ;
     RECT  68.681 42.576 68.749 46.248 ;
     RECT  68.641 47.328 68.749 54.984 ;
     RECT  68.387 37.584 68.753 41.448 ;
     RECT  68.321 35.28 68.785 36.024 ;
     RECT  67.853 88.32 68.789 93.288 ;
     RECT  68.789 88.32 68.821 88.728 ;
     RECT  68.645 80.256 68.876 85.656 ;
     RECT  68.749 42.576 68.933 54.984 ;
     RECT  68.429 6.288 68.965 24.984 ;
     RECT  68.497 28.56 69.001 29.64 ;
     RECT  67.817 30.96 69.001 33.576 ;
     RECT  67.961 76.32 69.001 76.92 ;
     RECT  68.645 77.952 69.001 79.224 ;
     RECT  68.501 57.696 69.068 75.192 ;
     RECT  69.001 76.32 69.068 79.224 ;
     RECT  68.876 80.256 69.253 86.472 ;
     RECT  68.965 6.288 69.613 25.08 ;
     RECT  69.253 80.256 69.613 87 ;
     RECT  68.821 88.08 69.613 88.728 ;
     RECT  69.068 57.696 69.637 79.224 ;
     RECT  69.613 80.256 69.637 88.728 ;
     RECT  69.001 28.56 69.649 34.2 ;
     RECT  68.524 3.12 69.781 4.44 ;
     RECT  69.649 28.512 69.781 34.2 ;
     RECT  68.785 35.28 69.781 36.504 ;
     RECT  69.781 28.512 69.829 36.504 ;
     RECT  68.753 37.584 69.829 39.768 ;
     RECT  68.753 40.8 69.829 41.448 ;
     RECT  69.781 3.12 69.908 4.776 ;
     RECT  69.613 6.048 69.908 25.08 ;
     RECT  68.428 26.208 69.908 27.192 ;
     RECT  69.829 28.512 69.908 36.6 ;
     RECT  69.829 37.584 69.908 41.448 ;
     RECT  68.933 42.576 69.908 54.888 ;
     RECT  69.793 56.496 69.908 56.52 ;
     RECT  69.637 57.696 69.908 88.728 ;
     RECT  68.789 89.712 69.908 93.288 ;
     RECT  67.504 94.848 69.908 94.872 ;
     RECT  69.908 2.148 70.012 95.052 ;
     RECT  70.012 2.418 70.204 94.872 ;
     RECT  70.204 2.832 70.301 9.048 ;
     RECT  70.204 94.704 70.301 94.872 ;
     RECT  70.204 56.496 70.373 56.904 ;
     RECT  70.204 78.48 70.409 93.288 ;
     RECT  70.204 10.32 70.517 29.592 ;
     RECT  70.373 56.496 70.517 56.76 ;
     RECT  70.204 47.328 70.589 53.016 ;
     RECT  70.204 35.424 70.625 36.6 ;
     RECT  70.409 86.496 70.661 93.288 ;
     RECT  70.204 58.464 70.697 75.96 ;
     RECT  70.517 10.752 70.733 12.024 ;
     RECT  70.409 78.48 70.733 85.224 ;
     RECT  70.204 37.584 70.777 46.344 ;
     RECT  70.625 35.424 70.805 36.36 ;
     RECT  70.661 86.496 70.805 87.24 ;
     RECT  70.301 5.52 70.949 9.048 ;
     RECT  70.733 10.848 70.985 12.024 ;
     RECT  70.777 39.504 71.021 46.344 ;
     RECT  71.021 39.504 71.093 41.784 ;
     RECT  71.093 39.504 71.129 39.864 ;
     RECT  70.204 54.336 71.228 54.888 ;
     RECT  71.021 42.816 71.269 46.344 ;
     RECT  70.589 47.328 71.269 50.184 ;
     RECT  70.517 13.056 71.273 29.592 ;
     RECT  70.589 51.264 71.305 53.016 ;
     RECT  71.228 54.048 71.305 54.888 ;
     RECT  70.517 56.496 71.305 56.568 ;
     RECT  70.733 80.64 71.315 85.224 ;
     RECT  71.305 51.264 71.459 56.568 ;
     RECT  71.315 80.832 71.525 85.224 ;
     RECT  70.949 6.336 71.555 9.048 ;
     RECT  71.273 24.96 71.593 29.592 ;
     RECT  70.204 30.672 71.593 32.232 ;
     RECT  70.805 35.76 71.593 36.36 ;
     RECT  70.697 59.76 71.593 75.96 ;
     RECT  71.564 77.28 71.593 77.304 ;
     RECT  71.269 42.816 71.633 50.184 ;
     RECT  71.593 35.76 71.665 36.456 ;
     RECT  70.777 37.584 71.665 37.944 ;
     RECT  71.273 13.056 71.701 23.64 ;
     RECT  71.525 80.976 71.797 85.224 ;
     RECT  70.805 86.496 71.797 86.616 ;
     RECT  71.665 35.76 71.917 37.944 ;
     RECT  70.697 58.464 71.917 58.488 ;
     RECT  71.593 59.76 71.917 77.304 ;
     RECT  70.733 78.48 71.917 79.368 ;
     RECT  70.661 88.416 71.917 93.288 ;
     RECT  71.917 88.128 71.941 93.288 ;
     RECT  71.093 40.944 71.989 41.784 ;
     RECT  71.633 42.816 71.989 43.56 ;
     RECT  71.633 45.168 72.025 50.184 ;
     RECT  71.459 51.264 72.025 53.352 ;
     RECT  71.917 58.464 72.025 79.368 ;
     RECT  70.301 2.832 72.037 3.912 ;
     RECT  71.797 80.976 72.061 86.616 ;
     RECT  72.025 58.464 72.085 79.56 ;
     RECT  70.985 10.944 72.097 12.024 ;
     RECT  72.097 10.608 72.133 12.024 ;
     RECT  71.701 13.008 72.133 23.64 ;
     RECT  71.555 7.392 72.169 9.048 ;
     RECT  72.133 10.608 72.169 23.64 ;
     RECT  71.459 54.336 72.197 56.568 ;
     RECT  71.917 35.328 72.205 37.944 ;
     RECT  71.129 39.84 72.241 39.864 ;
     RECT  72.169 7.392 72.313 23.64 ;
     RECT  71.593 24.96 72.313 32.232 ;
     RECT  71.941 87.888 72.349 93.288 ;
     RECT  72.313 7.392 72.421 32.232 ;
     RECT  72.241 39.312 72.428 39.864 ;
     RECT  72.037 2.64 72.608 4.68 ;
     RECT  71.555 6.336 72.608 6.36 ;
     RECT  72.421 7.392 72.608 32.52 ;
     RECT  70.204 33.888 72.608 34.104 ;
     RECT  72.205 35.232 72.608 37.944 ;
     RECT  72.428 39.12 72.608 39.864 ;
     RECT  71.989 40.944 72.608 43.56 ;
     RECT  72.025 45.168 72.608 53.352 ;
     RECT  72.197 54.336 72.608 57.048 ;
     RECT  72.085 58.464 72.608 79.8 ;
     RECT  72.061 80.976 72.608 86.76 ;
     RECT  72.349 87.84 72.608 93.288 ;
     RECT  70.301 94.704 72.608 94.728 ;
     RECT  72.608 2.148 72.712 95.052 ;
     RECT  72.712 2.418 72.904 95.052 ;
     RECT  72.904 39.312 72.929 54.36 ;
     RECT  72.904 94.704 73.001 95.052 ;
     RECT  72.904 55.536 73.037 85.176 ;
     RECT  72.904 4.176 73.043 29.592 ;
     RECT  72.904 30.672 73.145 37.896 ;
     RECT  73.043 4.176 73.187 9.096 ;
     RECT  72.904 87.792 73.217 93.096 ;
     RECT  73.187 5.184 73.228 9.096 ;
     RECT  73.037 55.536 73.289 83.88 ;
     RECT  73.217 87.792 73.405 92.952 ;
     RECT  73.001 94.848 73.573 95.052 ;
     RECT  73.537 96.336 73.573 96.36 ;
     RECT  72.929 39.312 73.613 54.168 ;
     RECT  73.145 34.896 73.721 37.896 ;
     RECT  73.573 96.336 73.763 96.456 ;
     RECT  73.043 10.32 73.897 29.592 ;
     RECT  73.721 34.992 73.897 37.896 ;
     RECT  73.763 96.432 73.907 96.456 ;
     RECT  73.037 84.864 73.933 85.176 ;
     RECT  72.904 86.736 73.957 86.76 ;
     RECT  73.405 87.792 73.957 92.712 ;
     RECT  73.573 94.848 73.997 95.16 ;
     RECT  73.228 5.568 74.005 9.096 ;
     RECT  73.897 10.32 74.005 29.64 ;
     RECT  73.933 84.864 74.005 85.224 ;
     RECT  73.613 39.312 74.101 50.136 ;
     RECT  73.145 30.672 74.113 33.672 ;
     RECT  73.289 56.544 74.149 83.88 ;
     RECT  74.005 84.864 74.149 85.704 ;
     RECT  72.904 2.784 74.153 3.144 ;
     RECT  74.113 30.672 74.153 33.96 ;
     RECT  73.897 34.992 74.197 37.944 ;
     RECT  74.101 39.264 74.261 50.136 ;
     RECT  74.149 56.544 74.261 85.704 ;
     RECT  73.613 51.168 74.293 54.168 ;
     RECT  74.261 81.408 74.297 85.704 ;
     RECT  73.957 86.736 74.389 92.712 ;
     RECT  73.997 94.032 74.389 95.16 ;
     RECT  74.197 34.992 74.437 37.992 ;
     RECT  74.389 86.736 74.581 95.16 ;
     RECT  73.289 55.536 74.617 55.56 ;
     RECT  73.187 4.176 74.833 4.2 ;
     RECT  74.005 5.568 74.833 29.64 ;
     RECT  74.581 97.056 74.873 97.08 ;
     RECT  74.153 2.784 74.941 3.096 ;
     RECT  74.153 31.2 75.013 33.96 ;
     RECT  74.437 34.992 75.013 38.184 ;
     RECT  74.293 51.168 75.013 54.36 ;
     RECT  74.617 55.536 75.013 55.944 ;
     RECT  74.297 81.456 75.049 85.704 ;
     RECT  74.581 86.736 75.049 95.208 ;
     RECT  74.261 39.552 75.157 50.136 ;
     RECT  75.013 51.168 75.157 55.944 ;
     RECT  74.833 4.176 75.301 29.64 ;
     RECT  75.013 31.2 75.301 38.184 ;
     RECT  74.941 2.304 75.308 3.096 ;
     RECT  75.301 4.176 75.308 38.184 ;
     RECT  75.157 39.552 75.308 55.944 ;
     RECT  74.261 57.024 75.308 80.376 ;
     RECT  75.049 81.456 75.308 95.208 ;
     RECT  75.308 2.148 75.347 95.208 ;
     RECT  75.347 2.148 75.412 95.16 ;
     RECT  75.445 97.008 75.589 97.032 ;
     RECT  75.412 2.304 75.604 95.16 ;
     RECT  75.604 2.304 75.701 38.232 ;
     RECT  75.701 24.96 75.731 38.232 ;
     RECT  75.604 57.072 75.806 58.968 ;
     RECT  75.806 57.12 75.845 58.968 ;
     RECT  75.604 60.048 75.845 95.16 ;
     RECT  75.701 2.304 75.875 23.928 ;
     RECT  75.731 24.96 75.881 35.832 ;
     RECT  75.845 57.12 75.881 58.728 ;
     RECT  75.845 60.048 75.881 80.376 ;
     RECT  75.875 6.768 75.925 23.928 ;
     RECT  75.589 96.816 76.021 97.032 ;
     RECT  75.881 60.048 76.025 71.736 ;
     RECT  75.875 2.304 76.097 5.304 ;
     RECT  75.881 24.96 76.205 31.224 ;
     RECT  76.021 96.816 76.277 97.08 ;
     RECT  75.845 81.6 76.313 95.16 ;
     RECT  75.881 32.448 76.7 35.832 ;
     RECT  75.731 36.912 76.7 38.232 ;
     RECT  75.604 39.312 76.817 55.848 ;
     RECT  75.881 72.72 76.837 80.376 ;
     RECT  76.817 39.36 76.849 55.848 ;
     RECT  76.7 32.448 76.931 38.232 ;
     RECT  75.925 6.768 76.957 10.68 ;
     RECT  75.925 11.712 76.957 23.928 ;
     RECT  76.849 39.36 76.993 56.04 ;
     RECT  75.881 57.12 76.993 57.144 ;
     RECT  76.931 32.928 76.997 38.232 ;
     RECT  76.097 2.304 77.065 2.712 ;
     RECT  76.097 3.84 77.065 3.96 ;
     RECT  75.881 58.128 77.065 58.728 ;
     RECT  76.025 60.048 77.065 71.448 ;
     RECT  76.993 39.36 77.173 57.144 ;
     RECT  77.065 58.128 77.173 71.448 ;
     RECT  76.205 25.152 77.209 31.224 ;
     RECT  76.957 6.768 77.228 23.928 ;
     RECT  77.209 25.104 77.228 31.224 ;
     RECT  76.097 5.184 77.281 5.304 ;
     RECT  76.313 81.6 77.317 94.872 ;
     RECT  77.173 39.36 77.425 71.448 ;
     RECT  76.837 72.72 77.425 80.52 ;
     RECT  77.228 6.768 77.509 31.224 ;
     RECT  77.065 2.304 77.516 3.96 ;
     RECT  77.281 5.184 77.516 5.544 ;
     RECT  77.425 39.36 77.677 80.52 ;
     RECT  77.317 81.6 77.677 95.16 ;
     RECT  77.677 39.36 77.795 95.16 ;
     RECT  76.997 34.128 77.893 38.232 ;
     RECT  77.795 39.36 77.893 95.052 ;
     RECT  76.997 32.928 77.929 33.096 ;
     RECT  77.516 2.304 78.008 5.544 ;
     RECT  77.509 6.768 78.008 31.848 ;
     RECT  77.929 32.832 78.008 33.096 ;
     RECT  77.893 34.128 78.008 95.052 ;
     RECT  78.008 2.148 78.112 95.052 ;
     RECT  78.112 2.418 78.304 94.782 ;
     RECT  78.304 2.832 78.329 3.432 ;
     RECT  78.304 34.08 78.508 54.696 ;
     RECT  78.508 34.224 78.509 54.696 ;
     RECT  78.304 55.968 78.515 94.632 ;
     RECT  78.515 62.448 78.604 94.632 ;
     RECT  78.509 34.224 78.617 54.312 ;
     RECT  78.617 34.224 78.803 53.592 ;
     RECT  78.304 10.704 78.833 33.096 ;
     RECT  78.803 34.224 78.995 42.552 ;
     RECT  78.604 79.776 78.995 94.632 ;
     RECT  78.833 10.848 79.013 33.096 ;
     RECT  78.995 34.224 79.036 35.88 ;
     RECT  78.803 43.632 79.139 53.592 ;
     RECT  79.013 10.848 79.193 32.328 ;
     RECT  76.277 97.056 79.229 97.08 ;
     RECT  79.139 43.824 79.265 53.592 ;
     RECT  79.036 34.224 79.283 35.832 ;
     RECT  78.329 2.832 79.301 3.336 ;
     RECT  78.604 62.448 79.373 78.648 ;
     RECT  79.301 2.88 79.445 3.336 ;
     RECT  78.995 79.776 79.445 94.44 ;
     RECT  79.193 10.848 79.481 28.248 ;
     RECT  79.283 34.224 79.481 34.68 ;
     RECT  78.304 5.136 79.513 5.208 ;
     RECT  79.445 2.88 79.553 3.144 ;
     RECT  79.481 11.376 79.589 28.248 ;
     RECT  79.265 43.824 79.589 50.904 ;
     RECT  79.589 11.376 79.619 24.792 ;
     RECT  79.628 54.672 79.715 54.696 ;
     RECT  79.373 62.448 79.733 78.552 ;
     RECT  78.515 55.968 80.017 61.464 ;
     RECT  79.733 62.448 80.017 78.456 ;
     RECT  79.193 29.232 80.053 32.328 ;
     RECT  79.481 34.224 80.053 34.248 ;
     RECT  79.445 80.88 80.233 94.44 ;
     RECT  79.265 52.368 80.269 53.592 ;
     RECT  78.995 36.912 80.348 42.552 ;
     RECT  79.589 43.824 80.348 47.688 ;
     RECT  78.304 6.816 80.444 9.528 ;
     RECT  79.619 11.424 80.557 24.792 ;
     RECT  79.589 25.776 80.557 28.248 ;
     RECT  80.348 36.912 80.557 47.688 ;
     RECT  79.589 48.72 80.557 50.904 ;
     RECT  79.553 2.88 80.581 2.904 ;
     RECT  79.513 4.224 80.581 5.208 ;
     RECT  80.557 36.912 80.593 50.904 ;
     RECT  80.269 52.368 80.593 53.88 ;
     RECT  80.017 55.968 80.593 78.456 ;
     RECT  80.581 2.592 80.708 2.904 ;
     RECT  80.581 3.936 80.708 5.208 ;
     RECT  80.444 6.816 80.708 10.344 ;
     RECT  80.557 11.424 80.708 28.248 ;
     RECT  80.053 29.232 80.708 34.248 ;
     RECT  79.283 35.712 80.708 35.832 ;
     RECT  80.593 36.912 80.708 53.88 ;
     RECT  80.593 55.248 80.708 78.456 ;
     RECT  79.445 79.776 80.708 79.8 ;
     RECT  80.233 80.88 80.708 94.632 ;
     RECT  80.708 2.148 80.812 95.052 ;
     RECT  80.812 2.418 81.004 94.782 ;
     RECT  81.004 45.552 81.101 61.464 ;
     RECT  81.004 3.84 81.173 3.96 ;
     RECT  81.004 29.568 81.173 44.472 ;
     RECT  81.101 45.648 81.173 61.464 ;
     RECT  81.004 6.192 81.251 6.84 ;
     RECT  81.004 7.968 81.281 9.336 ;
     RECT  81.004 2.832 81.347 2.856 ;
     RECT  81.004 4.944 81.347 5.208 ;
     RECT  81.173 3.84 81.388 3.864 ;
     RECT  81.173 45.648 81.497 54.408 ;
     RECT  81.173 55.776 81.539 61.464 ;
     RECT  81.004 76.32 81.569 85.512 ;
     RECT  81.173 29.568 81.605 43.128 ;
     RECT  81.251 6.816 81.635 6.84 ;
     RECT  81.497 45.648 81.641 48.744 ;
     RECT  81.281 7.968 81.713 7.992 ;
     RECT  81.004 10.32 81.713 28.536 ;
     RECT  81.605 29.568 81.713 42.984 ;
     RECT  81.004 86.496 81.713 94.68 ;
     RECT  81.713 40.416 81.821 42.984 ;
     RECT  81.497 52.32 81.821 54.408 ;
     RECT  81.173 44.112 81.857 44.472 ;
     RECT  81.713 86.688 81.865 94.68 ;
     RECT  81.569 79.776 81.971 85.512 ;
     RECT  81.971 81.984 81.973 85.512 ;
     RECT  81.004 62.448 82.033 75.24 ;
     RECT  81.569 76.32 82.033 78.504 ;
     RECT  81.821 52.32 82.067 53.352 ;
     RECT  81.347 4.992 82.069 5.208 ;
     RECT  81.713 29.568 82.115 39.384 ;
     RECT  81.281 9.072 82.141 9.336 ;
     RECT  81.713 10.32 82.141 27.48 ;
     RECT  82.069 4.992 82.163 5.688 ;
     RECT  81.539 55.776 82.177 57.096 ;
     RECT  82.115 29.568 82.181 35.592 ;
     RECT  81.539 58.176 82.181 61.464 ;
     RECT  81.821 54.384 82.217 54.408 ;
     RECT  81.865 86.688 82.217 94.392 ;
     RECT  82.033 62.448 82.253 78.504 ;
     RECT  82.177 55.392 82.289 57.096 ;
     RECT  82.181 58.368 82.325 61.464 ;
     RECT  81.973 81.984 82.355 85.608 ;
     RECT  81.713 28.512 82.465 28.536 ;
     RECT  82.181 29.568 82.465 34.392 ;
     RECT  82.325 58.944 82.537 61.464 ;
     RECT  82.253 62.448 82.537 75.816 ;
     RECT  82.253 76.992 82.537 78.504 ;
     RECT  82.289 56.976 82.609 57.096 ;
     RECT  82.537 76.992 82.645 78.552 ;
     RECT  81.971 79.776 82.645 81 ;
     RECT  82.163 4.992 82.753 5.208 ;
     RECT  81.857 44.112 82.825 44.136 ;
     RECT  82.537 3.408 82.933 3.432 ;
     RECT  82.141 9.072 83.036 27.48 ;
     RECT  82.465 28.512 83.036 34.392 ;
     RECT  83.036 9.072 83.041 34.392 ;
     RECT  82.933 3.36 83.077 3.432 ;
     RECT  82.753 4.944 83.077 5.208 ;
     RECT  81.821 40.56 83.077 42.984 ;
     RECT  82.217 86.784 83.077 94.392 ;
     RECT  81.641 45.696 83.149 48.744 ;
     RECT  81.497 49.824 83.149 51.336 ;
     RECT  82.709 6.816 83.185 6.84 ;
     RECT  83.041 8.496 83.185 34.392 ;
     RECT  82.067 52.32 83.221 53.064 ;
     RECT  82.609 56.976 83.221 57.384 ;
     RECT  82.537 58.944 83.221 75.816 ;
     RECT  82.645 76.992 83.221 81 ;
     RECT  83.185 6.816 83.257 34.392 ;
     RECT  82.181 35.568 83.257 35.592 ;
     RECT  83.221 58.944 83.269 81 ;
     RECT  82.355 81.984 83.269 85.56 ;
     RECT  83.077 3.36 83.408 5.208 ;
     RECT  83.257 6.816 83.408 35.592 ;
     RECT  82.115 37.056 83.408 39.384 ;
     RECT  83.077 40.56 83.408 43.032 ;
     RECT  82.825 44.064 83.408 44.136 ;
     RECT  83.149 45.696 83.408 51.336 ;
     RECT  83.221 52.32 83.408 53.592 ;
     RECT  82.289 55.392 83.408 55.8 ;
     RECT  83.221 56.976 83.408 57.72 ;
     RECT  83.269 58.944 83.408 85.56 ;
     RECT  83.077 86.784 83.408 94.68 ;
     RECT  83.408 2.148 83.512 95.052 ;
     RECT  83.512 2.418 83.704 94.782 ;
     RECT  83.704 3.36 83.765 35.016 ;
     RECT  83.704 54.72 83.765 85.512 ;
     RECT  83.704 41.616 83.801 53.592 ;
     RECT  83.765 3.36 83.843 34.584 ;
     RECT  83.843 3.36 83.891 33.048 ;
     RECT  83.891 3.36 83.939 6.168 ;
     RECT  83.891 7.44 83.945 33.048 ;
     RECT  83.945 7.44 84.125 25.224 ;
     RECT  83.801 48.72 84.161 53.592 ;
     RECT  83.939 6.144 84.305 6.168 ;
     RECT  84.161 48.72 84.413 52.968 ;
     RECT  83.765 54.72 84.413 84.696 ;
     RECT  84.413 56.016 84.521 84.696 ;
     RECT  83.843 34.128 84.665 34.152 ;
     RECT  84.521 56.016 84.665 75.96 ;
     RECT  83.704 86.784 84.707 94.68 ;
     RECT  83.704 36.336 84.733 40.104 ;
     RECT  84.707 86.784 84.764 90.072 ;
     RECT  83.801 41.616 84.877 47.688 ;
     RECT  84.413 48.72 84.877 48.888 ;
     RECT  83.945 26.544 84.913 33.048 ;
     RECT  84.733 36.336 84.913 40.632 ;
     RECT  84.521 76.944 84.917 84.696 ;
     RECT  84.913 26.448 84.949 33.048 ;
     RECT  84.913 35.664 84.949 40.632 ;
     RECT  84.877 41.616 84.949 48.888 ;
     RECT  84.665 57.168 84.953 75.96 ;
     RECT  84.949 35.664 85.036 48.888 ;
     RECT  84.764 86.352 85.057 90.072 ;
     RECT  84.125 7.44 85.237 24.312 ;
     RECT  85.237 6.576 85.273 24.312 ;
     RECT  83.939 3.36 85.333 5.112 ;
     RECT  85.129 34.656 85.417 34.68 ;
     RECT  85.036 35.664 85.417 48.744 ;
     RECT  84.917 77.04 85.417 84.696 ;
     RECT  85.333 3.36 85.525 5.544 ;
     RECT  85.273 6.576 85.525 25.224 ;
     RECT  84.949 26.448 85.525 33.336 ;
     RECT  84.413 49.872 85.561 52.968 ;
     RECT  84.413 54.72 85.561 54.744 ;
     RECT  85.561 49.872 85.633 53.256 ;
     RECT  85.417 77.04 85.741 84.936 ;
     RECT  85.057 86.208 85.741 90.072 ;
     RECT  85.525 3.36 85.861 33.336 ;
     RECT  85.561 54.576 85.885 54.744 ;
     RECT  85.633 49.872 85.957 53.304 ;
     RECT  85.885 54.576 85.957 54.984 ;
     RECT  85.741 77.04 85.957 90.072 ;
     RECT  84.707 91.056 85.957 94.68 ;
     RECT  85.861 3.312 86.108 33.336 ;
     RECT  85.417 34.656 86.108 48.744 ;
     RECT  85.957 49.872 86.108 54.984 ;
     RECT  84.665 56.016 86.108 56.04 ;
     RECT  84.953 57.168 86.108 75.864 ;
     RECT  85.957 77.04 86.108 94.68 ;
     RECT  86.108 2.148 86.212 95.052 ;
     RECT  86.212 2.418 86.404 94.782 ;
     RECT  86.404 3.84 86.501 32.04 ;
     RECT  86.501 3.84 86.531 30.12 ;
     RECT  86.404 88.752 86.531 90.312 ;
     RECT  86.404 46.32 86.573 52.728 ;
     RECT  86.531 20.88 86.579 30.12 ;
     RECT  86.404 57.6 86.579 81.192 ;
     RECT  86.404 91.584 86.579 94.632 ;
     RECT  86.531 3.84 86.581 19.896 ;
     RECT  86.404 82.272 86.645 87.72 ;
     RECT  86.645 85.392 86.675 87.72 ;
     RECT  86.579 91.728 86.675 94.632 ;
     RECT  86.404 33.024 86.681 37.368 ;
     RECT  86.579 76.848 86.681 77.064 ;
     RECT  86.681 33.024 86.789 33.624 ;
     RECT  86.404 38.736 86.789 45.192 ;
     RECT  86.404 54.96 86.825 54.984 ;
     RECT  86.789 38.736 86.833 44.472 ;
     RECT  86.675 87.696 86.861 87.72 ;
     RECT  86.579 57.6 86.969 75.816 ;
     RECT  86.681 34.704 87.041 37.368 ;
     RECT  86.404 56.352 87.041 56.52 ;
     RECT  86.833 38.736 87.077 44.376 ;
     RECT  86.969 57.6 87.185 58.44 ;
     RECT  87.077 39.216 87.257 44.376 ;
     RECT  87.041 34.704 87.293 35.832 ;
     RECT  87.293 34.704 87.329 35.736 ;
     RECT  87.329 35.712 87.365 35.736 ;
     RECT  86.675 85.488 87.365 86.616 ;
     RECT  86.581 3.84 87.437 4.2 ;
     RECT  86.501 31.2 87.437 32.04 ;
     RECT  86.581 5.472 87.443 19.896 ;
     RECT  87.437 31.2 87.473 31.368 ;
     RECT  86.531 89.28 87.473 90.312 ;
     RECT  86.675 91.728 87.473 94.536 ;
     RECT  87.473 90.288 87.505 90.312 ;
     RECT  86.573 46.32 87.509 47.688 ;
     RECT  86.789 33.024 87.541 33.528 ;
     RECT  86.404 53.904 87.545 53.928 ;
     RECT  87.509 47.568 87.577 47.688 ;
     RECT  86.573 48.72 87.577 52.728 ;
     RECT  86.645 82.272 87.577 84.408 ;
     RECT  87.541 32.448 87.587 33.528 ;
     RECT  86.969 59.808 87.685 75.816 ;
     RECT  86.681 76.848 87.685 76.872 ;
     RECT  87.473 89.28 87.685 89.304 ;
     RECT  87.685 88.896 87.689 89.304 ;
     RECT  87.041 37.008 87.733 37.368 ;
     RECT  87.437 4.176 87.761 4.2 ;
     RECT  87.505 90.288 87.761 90.552 ;
     RECT  87.443 5.472 87.779 9.912 ;
     RECT  87.685 59.808 87.793 76.872 ;
     RECT  87.577 47.568 87.829 52.728 ;
     RECT  87.541 55.728 87.829 55.752 ;
     RECT  87.577 82.176 87.829 84.408 ;
     RECT  87.365 85.488 87.829 85.512 ;
     RECT  87.473 91.728 87.833 93.624 ;
     RECT  87.779 5.472 87.865 9.096 ;
     RECT  87.829 55.056 87.973 55.752 ;
     RECT  86.579 78.096 87.973 81.192 ;
     RECT  87.829 82.176 87.973 85.512 ;
     RECT  87.833 91.728 88.028 92.76 ;
     RECT  87.689 88.896 88.069 88.92 ;
     RECT  87.973 54.624 88.117 55.752 ;
     RECT  87.793 59.808 88.213 76.968 ;
     RECT  87.973 78.096 88.213 85.512 ;
     RECT  87.443 10.896 88.225 19.896 ;
     RECT  86.579 20.928 88.225 30.12 ;
     RECT  87.733 37.008 88.225 38.088 ;
     RECT  87.257 39.216 88.225 39.624 ;
     RECT  88.117 54.624 88.261 56.568 ;
     RECT  87.257 44.352 88.297 44.376 ;
     RECT  88.225 10.896 88.333 30.12 ;
     RECT  87.473 31.2 88.333 31.224 ;
     RECT  87.329 34.704 88.441 34.728 ;
     RECT  87.365 86.544 88.441 86.568 ;
     RECT  88.225 37.008 88.477 39.624 ;
     RECT  88.213 59.808 88.508 85.512 ;
     RECT  88.441 86.544 88.508 87.432 ;
     RECT  87.509 46.32 88.585 46.344 ;
     RECT  87.829 47.568 88.657 53.352 ;
     RECT  88.261 54.624 88.657 56.616 ;
     RECT  87.185 57.6 88.657 58.296 ;
     RECT  88.508 59.808 88.693 87.432 ;
     RECT  88.333 10.896 88.765 31.224 ;
     RECT  87.587 32.448 88.765 33.048 ;
     RECT  87.865 5.088 88.808 9.096 ;
     RECT  88.765 10.896 88.808 33.048 ;
     RECT  88.441 34.704 88.808 35.16 ;
     RECT  88.477 36.24 88.808 39.624 ;
     RECT  87.257 40.608 88.808 43.176 ;
     RECT  88.297 44.352 88.808 44.472 ;
     RECT  88.585 46.224 88.808 46.344 ;
     RECT  88.657 47.568 88.808 56.616 ;
     RECT  88.657 57.6 88.808 58.776 ;
     RECT  88.693 59.76 88.808 87.432 ;
     RECT  88.069 88.512 88.808 88.92 ;
     RECT  87.761 90.528 88.808 90.552 ;
     RECT  88.028 91.632 88.808 92.76 ;
     RECT  88.808 2.148 88.912 95.052 ;
     RECT  88.912 2.418 89.104 94.782 ;
     RECT  89.104 7.2 89.219 8.52 ;
     RECT  89.104 10.896 89.273 32.472 ;
     RECT  89.104 44.112 89.309 55.464 ;
     RECT  89.273 10.896 89.345 29.88 ;
     RECT  89.345 28.176 89.381 29.88 ;
     RECT  89.219 7.2 89.411 7.416 ;
     RECT  89.219 8.496 89.411 8.52 ;
     RECT  89.345 10.896 89.417 27.096 ;
     RECT  89.104 70.08 89.525 75.72 ;
     RECT  89.104 76.848 89.525 88.92 ;
     RECT  89.417 12.336 89.555 27.096 ;
     RECT  89.104 36.24 89.561 37.128 ;
     RECT  89.555 12.336 89.597 12.936 ;
     RECT  89.525 76.848 89.597 88.2 ;
     RECT  89.597 76.896 89.669 88.2 ;
     RECT  89.273 30.864 89.699 32.472 ;
     RECT  89.309 53.808 89.777 55.464 ;
     RECT  89.309 44.112 89.843 52.728 ;
     RECT  89.843 50.736 89.891 52.728 ;
     RECT  89.104 33.456 90.085 34.92 ;
     RECT  89.417 10.896 90.097 11.016 ;
     RECT  89.555 14.448 90.101 27.096 ;
     RECT  89.669 76.896 90.101 88.104 ;
     RECT  89.104 58.656 90.133 69 ;
     RECT  89.525 70.08 90.133 74.184 ;
     RECT  89.699 30.864 90.137 31.704 ;
     RECT  89.381 28.176 90.172 29.64 ;
     RECT  90.133 58.656 90.209 74.184 ;
     RECT  90.097 10.8 90.245 11.016 ;
     RECT  90.137 30.96 90.245 31.704 ;
     RECT  90.101 84.768 90.317 88.104 ;
     RECT  89.843 44.112 90.323 49.608 ;
     RECT  90.245 30.96 90.353 31.56 ;
     RECT  90.323 44.112 90.371 48.696 ;
     RECT  90.101 25.728 90.385 27.096 ;
     RECT  90.172 28.176 90.385 29.4 ;
     RECT  90.385 25.728 90.389 29.4 ;
     RECT  89.104 38.4 90.421 43.128 ;
     RECT  90.085 32.688 90.425 34.92 ;
     RECT  90.209 58.656 90.461 71.256 ;
     RECT  90.101 76.896 90.461 83.64 ;
     RECT  90.461 76.896 90.497 78.696 ;
     RECT  90.461 79.824 90.497 83.64 ;
     RECT  89.104 90.048 90.529 90.072 ;
     RECT  89.411 7.2 90.533 7.224 ;
     RECT  90.241 56.592 90.533 56.616 ;
     RECT  90.497 80.016 90.533 83.64 ;
     RECT  90.425 33.024 90.565 34.92 ;
     RECT  90.461 58.656 90.613 65.544 ;
     RECT  89.525 75.456 90.613 75.72 ;
     RECT  90.613 75.456 90.637 75.816 ;
     RECT  90.385 9.072 90.661 9.096 ;
     RECT  90.209 72.336 90.661 74.184 ;
     RECT  90.637 75.408 90.661 75.816 ;
     RECT  90.661 8.784 90.668 9.096 ;
     RECT  89.561 36.576 90.709 37.128 ;
     RECT  90.421 38.208 90.709 43.128 ;
     RECT  90.709 36.576 90.853 43.128 ;
     RECT  90.371 44.112 90.853 47.688 ;
     RECT  89.597 12.336 90.925 12.504 ;
     RECT  90.565 33.024 90.925 35.208 ;
     RECT  90.853 36.576 90.925 47.688 ;
     RECT  90.101 14.448 90.961 24.504 ;
     RECT  90.497 76.896 90.961 78.552 ;
     RECT  90.529 89.472 91.033 90.072 ;
     RECT  90.317 84.864 91.141 88.104 ;
     RECT  90.533 80.352 91.381 83.64 ;
     RECT  91.141 84.864 91.381 88.2 ;
     RECT  91.033 89.184 91.381 90.072 ;
     RECT  90.389 27.072 91.465 29.4 ;
     RECT  90.961 76.8 91.501 78.552 ;
     RECT  91.381 80.352 91.501 90.072 ;
     RECT  90.661 7.728 91.508 7.752 ;
     RECT  90.668 8.784 91.508 9.96 ;
     RECT  90.245 10.992 91.508 11.016 ;
     RECT  90.925 12.336 91.508 12.552 ;
     RECT  90.961 14.112 91.508 24.504 ;
     RECT  90.389 25.728 91.508 25.992 ;
     RECT  91.465 27.072 91.508 29.64 ;
     RECT  90.353 30.96 91.508 30.984 ;
     RECT  90.925 33.024 91.508 47.688 ;
     RECT  90.371 48.672 91.508 48.696 ;
     RECT  89.891 50.736 91.508 52.248 ;
     RECT  89.777 53.808 91.508 55.128 ;
     RECT  90.613 58.128 91.508 65.544 ;
     RECT  90.461 67.152 91.508 71.256 ;
     RECT  90.661 72.336 91.508 75.816 ;
     RECT  91.501 76.8 91.508 90.072 ;
     RECT  91.508 2.148 91.612 95.052 ;
     RECT  91.612 2.418 91.804 94.782 ;
     RECT  91.804 19.344 91.865 19.368 ;
     RECT  91.804 22.224 91.865 23.592 ;
     RECT  91.804 27.936 91.901 30.216 ;
     RECT  91.804 41.472 91.901 44.472 ;
     RECT  91.804 72.336 91.901 82.68 ;
     RECT  91.804 59.28 91.973 61.464 ;
     RECT  91.804 20.688 92.009 21.144 ;
     RECT  91.804 88.896 92.045 89.208 ;
     RECT  91.804 14.112 92.099 16.824 ;
     RECT  91.804 13.056 92.125 13.08 ;
     RECT  91.804 31.536 92.188 36.6 ;
     RECT  91.804 37.68 92.188 38.424 ;
     RECT  92.188 32.4 92.189 36.6 ;
     RECT  91.973 59.28 92.189 61.128 ;
     RECT  91.804 84.048 92.189 87.336 ;
     RECT  92.099 14.304 92.225 16.824 ;
     RECT  91.901 41.712 92.225 44.472 ;
     RECT  91.901 82.416 92.291 82.68 ;
     RECT  92.225 14.304 92.297 14.76 ;
     RECT  91.865 22.224 92.297 23.304 ;
     RECT  91.804 56.112 92.297 57 ;
     RECT  92.189 59.28 92.297 61.08 ;
     RECT  92.297 56.112 92.333 56.52 ;
     RECT  91.901 72.336 92.341 81.432 ;
     RECT  92.009 20.688 92.369 20.712 ;
     RECT  92.297 59.28 92.369 59.832 ;
     RECT  92.225 41.76 92.405 44.472 ;
     RECT  91.804 69.264 92.405 69.48 ;
     RECT  92.225 15.84 92.441 16.824 ;
     RECT  92.405 41.952 92.441 44.472 ;
     RECT  92.333 56.352 92.441 56.52 ;
     RECT  92.341 77.088 92.441 81.432 ;
     RECT  92.341 72.336 92.477 76.056 ;
     RECT  92.189 84.336 92.483 87.336 ;
     RECT  91.804 25.728 92.513 25.752 ;
     RECT  91.804 67.92 92.513 67.944 ;
     RECT  91.804 45.936 92.531 47.928 ;
     RECT  92.297 23.28 92.549 23.304 ;
     RECT  91.804 49.584 92.549 51.096 ;
     RECT  91.901 27.936 92.585 28.68 ;
     RECT  92.477 74.064 92.693 76.056 ;
     RECT  92.483 84.336 92.693 86.088 ;
     RECT  92.531 46.176 92.723 47.928 ;
     RECT  92.585 28.656 92.729 28.68 ;
     RECT  92.549 50.16 92.765 51.096 ;
     RECT  92.441 77.088 92.765 81.24 ;
     RECT  92.297 61.056 92.801 61.08 ;
     RECT  91.804 54.336 92.833 54.648 ;
     RECT  92.765 50.16 92.837 50.808 ;
     RECT  91.804 39.888 92.869 39.912 ;
     RECT  92.441 16.368 92.873 16.824 ;
     RECT  92.869 39.456 92.909 39.912 ;
     RECT  92.723 46.56 92.915 47.928 ;
     RECT  92.873 16.368 92.945 16.392 ;
     RECT  92.765 77.088 92.945 77.112 ;
     RECT  92.765 78.528 92.945 81.24 ;
     RECT  92.291 82.656 92.945 82.68 ;
     RECT  92.693 86.016 92.945 86.04 ;
     RECT  91.804 71.184 92.981 71.208 ;
     RECT  91.901 30.192 93.013 30.216 ;
     RECT  92.189 32.4 93.053 36.552 ;
     RECT  93.013 30.192 93.059 30.84 ;
     RECT  92.297 22.224 93.089 22.248 ;
     RECT  92.945 79.776 93.089 81.24 ;
     RECT  93.059 30.432 93.097 30.84 ;
     RECT  92.297 14.304 93.125 14.328 ;
     RECT  93.053 32.4 93.157 34.248 ;
     RECT  93.053 35.28 93.193 36.552 ;
     RECT  93.193 35.28 93.196 37.032 ;
     RECT  92.945 78.528 93.197 78.648 ;
     RECT  92.045 88.896 93.197 88.92 ;
     RECT  93.157 31.872 93.203 34.248 ;
     RECT  92.477 72.336 93.301 72.36 ;
     RECT  93.157 67.68 93.481 67.704 ;
     RECT  93.301 72.144 93.589 72.36 ;
     RECT  92.441 42.192 93.596 44.472 ;
     RECT  92.405 69.456 93.769 69.48 ;
     RECT  92.441 56.496 93.877 56.52 ;
     RECT  93.769 68.928 93.913 69.48 ;
     RECT  93.589 72.144 93.949 72.504 ;
     RECT  92.188 38.112 94.021 38.424 ;
     RECT  92.909 39.456 94.021 39.48 ;
     RECT  92.837 50.16 94.021 50.184 ;
     RECT  94.021 38.112 94.069 39.48 ;
     RECT  92.915 46.56 94.069 47.88 ;
     RECT  94.021 50.16 94.069 50.664 ;
     RECT  93.089 79.776 94.129 79.8 ;
     RECT  93.089 81.216 94.129 81.24 ;
     RECT  94.165 23.856 94.208 23.88 ;
     RECT  93.097 30.432 94.208 30.456 ;
     RECT  93.203 31.872 94.208 31.896 ;
     RECT  93.203 33.024 94.208 33.816 ;
     RECT  93.196 35.52 94.208 37.032 ;
     RECT  94.069 38.112 94.208 39.864 ;
     RECT  93.596 41.952 94.208 44.472 ;
     RECT  94.069 46.56 94.208 48.456 ;
     RECT  94.069 49.776 94.208 50.664 ;
     RECT  93.409 53.28 94.208 53.304 ;
     RECT  92.833 54.336 94.208 55.176 ;
     RECT  93.877 56.496 94.208 57.096 ;
     RECT  92.977 58.656 94.208 58.68 ;
     RECT  92.369 59.808 94.208 59.832 ;
     RECT  93.481 67.344 94.208 67.704 ;
     RECT  93.913 68.928 94.208 69.864 ;
     RECT  93.949 72.144 94.208 73.272 ;
     RECT  92.693 74.592 94.208 76.056 ;
     RECT  93.197 78.576 94.208 78.648 ;
     RECT  94.129 79.776 94.208 81.24 ;
     RECT  92.693 84.336 94.208 84.36 ;
     RECT  94.208 2.148 94.312 95.052 ;
     RECT  94.312 2.418 94.504 94.782 ;
     RECT  94.504 78.624 94.601 78.648 ;
     RECT  94.504 71.712 94.709 73.272 ;
     RECT  94.504 23.76 94.745 23.88 ;
     RECT  94.709 71.712 95.069 72.504 ;
     RECT  94.504 25.776 95.497 26.232 ;
     RECT  95.497 25.776 95.713 26.376 ;
     RECT  94.504 69.84 95.713 69.864 ;
     RECT  95.069 71.712 95.713 71.88 ;
     RECT  94.504 66.672 96.289 67.704 ;
     RECT  94.504 68.688 96.289 68.712 ;
     RECT  95.713 69.84 96.289 70.44 ;
     RECT  96.289 16.272 96.325 16.872 ;
     RECT  94.745 23.76 96.325 23.784 ;
     RECT  95.713 25.776 96.325 26.52 ;
     RECT  96.289 64.944 96.325 70.44 ;
     RECT  95.713 71.424 96.325 71.88 ;
     RECT  96.325 15.12 96.361 15.144 ;
     RECT  96.325 16.128 96.361 16.872 ;
     RECT  96.325 23.76 96.361 23.928 ;
     RECT  96.325 62.928 96.361 62.952 ;
     RECT  96.325 64.368 96.361 71.88 ;
     RECT  96.361 23.76 96.397 24.216 ;
     RECT  96.325 25.2 96.397 26.52 ;
     RECT  96.361 62.928 96.397 63.096 ;
     RECT  96.361 64.08 96.397 71.88 ;
     RECT  96.361 15.12 96.505 16.872 ;
     RECT  96.289 28.224 96.757 28.248 ;
     RECT  95.713 17.856 96.793 17.88 ;
     RECT  95.713 18.864 96.793 18.888 ;
     RECT  96.757 28.08 96.793 28.248 ;
     RECT  96.793 27.936 96.829 28.248 ;
     RECT  96.829 27.792 96.865 28.248 ;
     RECT  96.865 27.648 96.901 28.248 ;
     RECT  96.397 23.76 96.937 26.52 ;
     RECT  96.901 27.504 96.937 28.248 ;
     RECT  96.793 17.856 96.973 18.888 ;
     RECT  96.505 14.544 97.009 16.872 ;
     RECT  96.973 17.856 97.009 19.032 ;
     RECT  96.397 62.928 97.045 71.88 ;
     RECT  97.009 14.544 97.116 14.568 ;
     RECT  97.009 14.568 97.164 14.688 ;
     RECT  97.009 14.688 97.116 14.712 ;
     RECT  97.009 14.712 97.164 14.832 ;
     RECT  97.009 14.832 97.116 14.856 ;
     RECT  97.009 14.856 97.164 14.976 ;
     RECT  97.009 14.976 97.116 15 ;
     RECT  97.009 15 97.164 15.12 ;
     RECT  97.009 15.12 97.116 15.144 ;
     RECT  97.009 15.144 97.164 15.264 ;
     RECT  97.009 15.264 97.116 15.288 ;
     RECT  97.009 15.288 97.164 15.408 ;
     RECT  97.009 15.408 97.116 15.432 ;
     RECT  97.009 15.432 97.164 15.552 ;
     RECT  97.009 15.552 97.116 15.576 ;
     RECT  97.009 15.576 97.164 15.696 ;
     RECT  97.009 15.696 97.116 15.72 ;
     RECT  97.009 15.72 97.164 15.84 ;
     RECT  97.009 15.84 97.116 15.864 ;
     RECT  97.009 15.864 97.164 15.984 ;
     RECT  97.009 15.984 97.116 16.008 ;
     RECT  97.009 16.008 97.164 16.128 ;
     RECT  97.009 16.128 97.116 16.152 ;
     RECT  97.009 16.152 97.164 16.272 ;
     RECT  97.009 16.272 97.116 16.296 ;
     RECT  97.009 16.296 97.164 16.416 ;
     RECT  97.009 16.416 97.116 16.44 ;
     RECT  97.009 16.44 97.164 16.56 ;
     RECT  97.009 16.56 97.116 16.584 ;
     RECT  97.009 16.584 97.164 16.704 ;
     RECT  97.009 16.704 97.116 16.728 ;
     RECT  97.009 16.728 97.164 16.848 ;
     RECT  97.009 16.848 97.116 16.872 ;
     RECT  97.009 16.872 97.164 16.992 ;
     RECT  97.009 16.992 97.116 17.016 ;
     RECT  97.009 17.016 97.164 17.136 ;
     RECT  97.009 17.136 97.116 17.16 ;
     RECT  97.009 17.16 97.164 17.28 ;
     RECT  97.009 17.28 97.116 17.304 ;
     RECT  97.009 17.304 97.164 17.424 ;
     RECT  97.009 17.424 97.116 17.448 ;
     RECT  97.009 17.448 97.164 17.568 ;
     RECT  97.009 17.568 97.116 17.592 ;
     RECT  97.009 17.592 97.164 17.712 ;
     RECT  97.009 17.712 97.116 17.736 ;
     RECT  97.009 17.736 97.164 17.856 ;
     RECT  97.009 17.856 97.116 17.88 ;
     RECT  97.009 17.88 97.164 18 ;
     RECT  97.009 18 97.116 18.024 ;
     RECT  97.009 18.024 97.164 18.144 ;
     RECT  97.009 18.144 97.116 18.168 ;
     RECT  97.009 18.168 97.164 18.288 ;
     RECT  97.009 18.288 97.116 18.312 ;
     RECT  97.009 18.312 97.164 18.432 ;
     RECT  97.009 18.432 97.116 18.456 ;
     RECT  97.009 18.456 97.164 18.576 ;
     RECT  97.009 18.576 97.116 18.6 ;
     RECT  97.009 18.6 97.164 18.72 ;
     RECT  97.009 18.72 97.116 18.744 ;
     RECT  97.009 18.744 97.164 18.864 ;
     RECT  97.009 18.864 97.116 18.888 ;
     RECT  97.009 18.888 97.164 19.008 ;
     RECT  97.009 19.008 97.116 19.032 ;
     RECT  96.937 23.76 97.116 23.784 ;
     RECT  96.937 23.784 97.164 23.904 ;
     RECT  96.937 23.904 97.116 23.928 ;
     RECT  96.937 23.928 97.164 24.048 ;
     RECT  96.937 24.048 97.116 24.072 ;
     RECT  96.937 24.072 97.164 24.192 ;
     RECT  96.937 24.192 97.116 24.216 ;
     RECT  96.937 24.216 97.164 24.336 ;
     RECT  96.937 24.336 97.116 24.36 ;
     RECT  96.937 24.36 97.164 24.48 ;
     RECT  96.937 24.48 97.116 24.504 ;
     RECT  96.937 24.504 97.164 24.624 ;
     RECT  96.937 24.624 97.116 24.648 ;
     RECT  96.937 24.648 97.164 24.768 ;
     RECT  96.937 24.768 97.116 24.792 ;
     RECT  96.937 24.792 97.164 24.912 ;
     RECT  96.937 24.912 97.116 24.936 ;
     RECT  96.937 24.936 97.164 25.056 ;
     RECT  96.937 25.056 97.116 25.08 ;
     RECT  96.937 25.08 97.164 25.2 ;
     RECT  96.937 25.2 97.116 25.224 ;
     RECT  96.937 25.224 97.164 25.344 ;
     RECT  96.937 25.344 97.116 25.368 ;
     RECT  96.937 25.368 97.164 25.488 ;
     RECT  96.937 25.488 97.116 25.512 ;
     RECT  96.937 25.512 97.164 25.632 ;
     RECT  96.937 25.632 97.116 25.656 ;
     RECT  96.937 25.656 97.164 25.776 ;
     RECT  96.937 25.776 97.116 25.8 ;
     RECT  96.937 25.8 97.164 25.92 ;
     RECT  96.937 25.92 97.116 25.944 ;
     RECT  96.937 25.944 97.164 26.064 ;
     RECT  96.937 26.064 97.116 26.088 ;
     RECT  96.937 26.088 97.164 26.208 ;
     RECT  96.937 26.208 97.116 26.232 ;
     RECT  96.937 26.232 97.164 26.352 ;
     RECT  96.937 26.352 97.116 26.376 ;
     RECT  96.937 26.376 97.164 26.496 ;
     RECT  96.937 26.496 97.116 26.52 ;
     RECT  96.937 26.52 97.164 26.64 ;
     RECT  96.937 26.64 97.116 26.664 ;
     RECT  96.937 26.664 97.164 26.784 ;
     RECT  96.937 26.784 97.116 26.808 ;
     RECT  96.937 26.808 97.164 26.928 ;
     RECT  96.937 26.928 97.116 26.952 ;
     RECT  96.937 26.952 97.164 27.072 ;
     RECT  96.937 27.072 97.116 27.096 ;
     RECT  96.937 27.096 97.164 27.216 ;
     RECT  96.937 27.216 97.116 27.24 ;
     RECT  96.937 27.24 97.164 27.36 ;
     RECT  96.937 27.36 97.116 27.384 ;
     RECT  96.937 27.384 97.164 27.504 ;
     RECT  96.937 27.504 97.116 27.528 ;
     RECT  96.937 27.528 97.164 27.648 ;
     RECT  96.937 27.648 97.116 27.672 ;
     RECT  96.937 27.672 97.164 27.792 ;
     RECT  96.937 27.792 97.116 27.816 ;
     RECT  96.937 27.816 97.164 27.936 ;
     RECT  96.937 27.936 97.116 27.96 ;
     RECT  96.937 27.96 97.164 28.08 ;
     RECT  96.937 28.08 97.116 28.104 ;
     RECT  96.937 28.104 97.164 28.224 ;
     RECT  96.937 28.224 97.116 28.248 ;
     RECT  97.045 62.928 97.116 62.952 ;
     RECT  97.045 62.952 97.164 63.072 ;
     RECT  97.045 63.072 97.116 63.096 ;
     RECT  97.045 63.096 97.164 63.216 ;
     RECT  97.045 63.216 97.116 63.24 ;
     RECT  97.045 63.24 97.164 63.36 ;
     RECT  97.045 63.36 97.116 63.384 ;
     RECT  97.045 63.384 97.164 63.504 ;
     RECT  97.045 63.504 97.116 63.528 ;
     RECT  97.045 63.528 97.164 63.648 ;
     RECT  97.045 63.648 97.116 63.672 ;
     RECT  97.045 63.672 97.164 63.792 ;
     RECT  97.045 63.792 97.116 63.816 ;
     RECT  97.045 63.816 97.164 63.936 ;
     RECT  97.045 63.936 97.116 63.96 ;
     RECT  97.045 63.96 97.164 64.08 ;
     RECT  97.045 64.08 97.116 64.104 ;
     RECT  97.045 64.104 97.164 64.224 ;
     RECT  97.045 64.224 97.116 64.248 ;
     RECT  97.045 64.248 97.164 64.368 ;
     RECT  97.045 64.368 97.116 64.392 ;
     RECT  97.045 64.392 97.164 64.512 ;
     RECT  97.045 64.512 97.116 64.536 ;
     RECT  97.045 64.536 97.164 64.656 ;
     RECT  97.045 64.656 97.116 64.68 ;
     RECT  97.045 64.68 97.164 64.8 ;
     RECT  97.045 64.8 97.116 64.824 ;
     RECT  97.045 64.824 97.164 64.944 ;
     RECT  97.045 64.944 97.116 64.968 ;
     RECT  97.045 64.968 97.164 65.088 ;
     RECT  97.045 65.088 97.116 65.112 ;
     RECT  97.045 65.112 97.164 65.232 ;
     RECT  97.045 65.232 97.116 65.256 ;
     RECT  97.045 65.256 97.164 65.376 ;
     RECT  97.045 65.376 97.116 65.4 ;
     RECT  97.045 65.4 97.164 65.52 ;
     RECT  97.045 65.52 97.116 65.544 ;
     RECT  97.045 65.544 97.164 65.664 ;
     RECT  97.045 65.664 97.116 65.688 ;
     RECT  97.045 65.688 97.164 65.808 ;
     RECT  97.045 65.808 97.116 65.832 ;
     RECT  97.045 65.832 97.164 65.952 ;
     RECT  97.045 65.952 97.116 65.976 ;
     RECT  97.045 65.976 97.164 66.096 ;
     RECT  97.045 66.096 97.116 66.12 ;
     RECT  97.045 66.12 97.164 66.24 ;
     RECT  97.045 66.24 97.116 66.264 ;
     RECT  97.045 66.264 97.164 66.384 ;
     RECT  97.045 66.384 97.116 66.408 ;
     RECT  97.045 66.408 97.164 66.528 ;
     RECT  97.045 66.528 97.116 66.552 ;
     RECT  97.045 66.552 97.164 66.672 ;
     RECT  97.045 66.672 97.116 66.696 ;
     RECT  97.045 66.696 97.164 66.816 ;
     RECT  97.045 66.816 97.116 66.84 ;
     RECT  97.045 66.84 97.164 66.96 ;
     RECT  97.045 66.96 97.116 66.984 ;
     RECT  97.045 66.984 97.164 67.104 ;
     RECT  97.045 67.104 97.116 67.128 ;
     RECT  97.045 67.128 97.164 67.248 ;
     RECT  97.045 67.248 97.116 67.272 ;
     RECT  97.045 67.272 97.164 67.392 ;
     RECT  97.045 67.392 97.116 67.416 ;
     RECT  97.045 67.416 97.164 67.536 ;
     RECT  97.045 67.536 97.116 67.56 ;
     RECT  97.045 67.56 97.164 67.68 ;
     RECT  97.045 67.68 97.116 67.704 ;
     RECT  97.045 67.704 97.164 67.824 ;
     RECT  97.045 67.824 97.116 67.848 ;
     RECT  97.045 67.848 97.164 67.968 ;
     RECT  97.045 67.968 97.116 67.992 ;
     RECT  97.045 67.992 97.164 68.112 ;
     RECT  97.045 68.112 97.116 68.136 ;
     RECT  97.045 68.136 97.164 68.256 ;
     RECT  97.045 68.256 97.116 68.28 ;
     RECT  97.045 68.28 97.164 68.4 ;
     RECT  97.045 68.4 97.116 68.424 ;
     RECT  97.045 68.424 97.164 68.544 ;
     RECT  97.045 68.544 97.116 68.568 ;
     RECT  97.045 68.568 97.164 68.688 ;
     RECT  97.045 68.688 97.116 68.712 ;
     RECT  97.045 68.712 97.164 68.832 ;
     RECT  97.045 68.832 97.116 68.856 ;
     RECT  97.045 68.856 97.164 68.976 ;
     RECT  97.045 68.976 97.116 69 ;
     RECT  97.045 69 97.164 69.12 ;
     RECT  97.045 69.12 97.116 69.144 ;
     RECT  97.045 69.144 97.164 69.264 ;
     RECT  97.045 69.264 97.116 69.288 ;
     RECT  97.045 69.288 97.164 69.408 ;
     RECT  97.045 69.408 97.116 69.432 ;
     RECT  97.045 69.432 97.164 69.552 ;
     RECT  97.045 69.552 97.116 69.576 ;
     RECT  97.045 69.576 97.164 69.696 ;
     RECT  97.045 69.696 97.116 69.72 ;
     RECT  97.045 69.72 97.164 69.84 ;
     RECT  97.045 69.84 97.116 69.864 ;
     RECT  97.045 69.864 97.164 69.984 ;
     RECT  97.045 69.984 97.116 70.008 ;
     RECT  97.045 70.008 97.164 70.128 ;
     RECT  97.045 70.128 97.116 70.152 ;
     RECT  97.045 70.152 97.164 70.272 ;
     RECT  97.045 70.272 97.116 70.296 ;
     RECT  97.045 70.296 97.164 70.416 ;
     RECT  97.045 70.416 97.116 70.44 ;
     RECT  97.045 70.44 97.164 70.56 ;
     RECT  97.045 70.56 97.116 70.584 ;
     RECT  97.045 70.584 97.164 70.704 ;
     RECT  97.045 70.704 97.116 70.728 ;
     RECT  97.045 70.728 97.164 70.848 ;
     RECT  97.045 70.848 97.116 70.872 ;
     RECT  97.045 70.872 97.164 70.992 ;
     RECT  97.045 70.992 97.116 71.016 ;
     RECT  97.045 71.016 97.164 71.136 ;
     RECT  97.045 71.136 97.116 71.16 ;
     RECT  97.045 71.16 97.164 71.28 ;
     RECT  97.045 71.28 97.116 71.304 ;
     RECT  97.045 71.304 97.164 71.424 ;
     RECT  97.045 71.424 97.116 71.448 ;
     RECT  97.045 71.448 97.164 71.568 ;
     RECT  97.045 71.568 97.116 71.592 ;
     RECT  97.045 71.592 97.164 71.712 ;
     RECT  97.045 71.712 97.116 71.736 ;
     RECT  97.045 71.736 97.164 71.856 ;
     RECT  97.045 71.856 97.116 71.88 ;
     RECT  97.045 71.88 97.164 72 ;
     RECT  97.045 72 97.116 72.024 ;
    LAYER M5 ;
     RECT  2.4 2.137 2.52 2.151 ;
     RECT  5.1 2.137 5.22 2.151 ;
     RECT  7.8 2.137 7.92 2.151 ;
     RECT  10.5 2.137 10.62 2.151 ;
     RECT  13.2 2.137 13.32 2.151 ;
     RECT  15.9 2.137 16.02 2.151 ;
     RECT  18.6 2.137 18.72 2.151 ;
     RECT  21.3 2.137 21.42 2.151 ;
     RECT  24 2.137 24.12 2.151 ;
     RECT  26.7 2.137 26.82 2.151 ;
     RECT  29.4 2.137 29.52 2.151 ;
     RECT  32.1 2.137 32.22 2.151 ;
     RECT  34.8 2.137 34.92 2.151 ;
     RECT  37.5 2.137 37.62 2.151 ;
     RECT  40.2 2.137 40.32 2.151 ;
     RECT  42.9 2.137 43.02 2.151 ;
     RECT  45.6 2.137 45.72 2.151 ;
     RECT  48.3 2.137 48.42 2.151 ;
     RECT  51 2.137 51.12 2.151 ;
     RECT  53.7 2.137 53.82 2.151 ;
     RECT  56.4 2.137 56.52 2.151 ;
     RECT  59.1 2.137 59.22 2.151 ;
     RECT  61.8 2.137 61.92 2.151 ;
     RECT  64.5 2.137 64.62 2.151 ;
     RECT  67.2 2.137 67.32 2.151 ;
     RECT  69.9 2.137 70.02 2.151 ;
     RECT  72.6 2.137 72.72 2.151 ;
     RECT  75.3 2.137 75.42 2.151 ;
     RECT  78 2.137 78.12 2.151 ;
     RECT  80.7 2.137 80.82 2.151 ;
     RECT  83.4 2.137 83.52 2.151 ;
     RECT  86.1 2.137 86.22 2.151 ;
     RECT  88.8 2.137 88.92 2.151 ;
     RECT  91.5 2.137 91.62 2.151 ;
     RECT  94.2 2.137 94.32 2.151 ;
     RECT  61.8 2.151 62.112 2.245 ;
     RECT  67.2 2.151 67.512 2.581 ;
     RECT  80.7 2.151 81.012 2.581 ;
     RECT  72.6 2.151 72.912 2.629 ;
     RECT  75.3 2.151 75.612 2.677 ;
     RECT  78 2.151 78.312 2.773 ;
     RECT  64.5 2.151 64.812 2.821 ;
     RECT  69.9 2.151 70.212 2.821 ;
     RECT  72.048 2.629 72.912 2.821 ;
     RECT  80.592 2.581 81.012 2.821 ;
     RECT  71.376 2.821 72.912 3.155 ;
     RECT  45.6 2.151 45.912 3.301 ;
     RECT  69.9 2.821 70.344 3.301 ;
     RECT  86.1 2.151 86.412 3.301 ;
     RECT  69.792 3.301 70.344 3.347 ;
     RECT  37.5 2.151 37.812 3.397 ;
     RECT  34.8 2.151 35.112 3.781 ;
     RECT  40.2 2.151 40.512 3.829 ;
     RECT  67.2 2.581 68.472 3.923 ;
     RECT  32.1 2.151 32.412 3.925 ;
     RECT  56.4 2.151 56.712 3.925 ;
     RECT  64.5 2.821 65.256 3.925 ;
     RECT  85.872 3.301 86.412 3.925 ;
     RECT  80.592 2.821 81.336 4.213 ;
     RECT  79.632 4.213 81.336 4.259 ;
     RECT  75.3 2.677 75.96 4.261 ;
     RECT  85.152 3.925 86.412 4.499 ;
     RECT  85.344 4.499 86.412 4.501 ;
     RECT  45.6 3.301 46.728 4.547 ;
     RECT  72.048 3.155 72.912 4.645 ;
     RECT  72.048 4.645 73.176 4.691 ;
     RECT  61.008 2.245 62.112 4.741 ;
     RECT  69.792 3.347 70.212 4.787 ;
     RECT  24 2.151 24.312 4.789 ;
     RECT  34.8 3.781 35.688 4.883 ;
     RECT  60.912 4.741 62.112 4.933 ;
     RECT  40.2 3.829 41.064 4.979 ;
     RECT  80.7 4.259 81.336 4.979 ;
     RECT  15.9 2.151 16.212 5.077 ;
     RECT  83.4 2.151 83.712 5.077 ;
     RECT  88.8 2.151 89.112 5.077 ;
     RECT  79.632 4.259 79.656 5.171 ;
     RECT  72.48 4.691 73.176 5.219 ;
     RECT  83.4 5.077 83.928 5.219 ;
     RECT  67.2 3.923 68.376 5.363 ;
     RECT  29.4 2.151 29.712 5.461 ;
     RECT  48.3 2.151 48.612 5.461 ;
     RECT  49.728 4.501 49.752 5.461 ;
     RECT  48.3 5.461 49.752 5.507 ;
     RECT  53.7 2.151 54.012 5.509 ;
     RECT  45.6 4.547 46.344 5.605 ;
     RECT  60.912 4.933 62.28 5.605 ;
     RECT  33.744 3.157 33.768 5.653 ;
     RECT  34.8 4.883 35.112 5.653 ;
     RECT  24 4.789 25.08 5.747 ;
     RECT  33.744 5.653 35.112 5.747 ;
     RECT  56.4 3.925 57.576 5.747 ;
     RECT  64.5 3.925 65.496 5.795 ;
     RECT  53.7 5.509 54.504 6.085 ;
     RECT  60.72 5.605 62.28 6.085 ;
     RECT  13.2 2.151 13.512 6.133 ;
     RECT  26.7 2.151 27.012 6.181 ;
     RECT  80.7 4.979 81.144 6.181 ;
     RECT  82.128 5.653 82.152 6.181 ;
     RECT  53.7 6.085 55.272 6.229 ;
     RECT  56.4 5.747 56.712 6.229 ;
     RECT  72.48 5.219 72.912 6.229 ;
     RECT  85.344 4.501 86.568 6.229 ;
     RECT  87.888 5.077 89.112 6.229 ;
     RECT  85.344 6.229 89.112 6.275 ;
     RECT  40.2 4.979 40.512 6.277 ;
     RECT  51 2.151 51.312 6.277 ;
     RECT  22.8 5.605 22.824 6.323 ;
     RECT  31.872 3.925 32.412 6.323 ;
     RECT  48.3 5.507 49.08 6.323 ;
     RECT  60.72 6.085 62.808 6.323 ;
     RECT  64.5 5.795 65.016 6.323 ;
     RECT  53.7 6.229 56.712 6.611 ;
     RECT  36.96 3.397 37.812 6.613 ;
     RECT  77.568 2.773 78.312 6.803 ;
     RECT  10.5 2.151 10.812 6.805 ;
     RECT  20.256 5.845 20.28 6.805 ;
     RECT  21.3 2.151 21.612 6.805 ;
     RECT  72.48 6.229 73.032 6.805 ;
     RECT  78 6.803 78.312 6.805 ;
     RECT  80.7 6.181 82.152 6.805 ;
     RECT  83.4 5.219 83.88 6.805 ;
     RECT  36.96 6.613 37.944 6.851 ;
     RECT  59.1 2.151 59.412 6.901 ;
     RECT  29.088 5.461 29.712 6.947 ;
     RECT  48.3 6.323 48.612 7.141 ;
     RECT  67.2 5.363 68.136 7.141 ;
     RECT  20.256 6.805 22.344 7.189 ;
     RECT  78 6.805 78.84 7.189 ;
     RECT  88.8 6.275 89.112 7.189 ;
     RECT  44.448 6.229 44.472 7.331 ;
     RECT  50.88 6.277 51.312 7.379 ;
     RECT  12.336 6.133 13.512 7.381 ;
     RECT  29.232 6.947 29.712 7.381 ;
     RECT  69.9 4.787 70.212 7.381 ;
     RECT  88.8 7.189 89.208 7.381 ;
     RECT  71.52 6.805 73.032 7.427 ;
     RECT  75.3 4.261 76.056 7.427 ;
     RECT  18.6 2.151 18.912 7.429 ;
     RECT  15.9 5.077 16.344 7.475 ;
     RECT  26.208 6.181 27.012 7.475 ;
     RECT  40.2 6.277 41.304 7.667 ;
     RECT  78 7.189 78.936 7.717 ;
     RECT  91.5 2.151 91.812 7.717 ;
     RECT  9.552 6.805 10.812 7.813 ;
     RECT  12.336 7.381 14.232 7.813 ;
     RECT  9.552 7.813 14.232 7.859 ;
     RECT  24 5.747 24.312 7.909 ;
     RECT  59.1 6.901 59.88 7.909 ;
     RECT  32.1 6.323 32.412 7.957 ;
     RECT  47.76 7.141 48.612 7.957 ;
     RECT  20.208 7.189 22.344 8.003 ;
     RECT  29.232 7.381 29.976 8.003 ;
     RECT  9.552 7.859 11.4 8.195 ;
     RECT  13.2 7.859 14.232 8.195 ;
     RECT  20.88 8.003 22.344 8.195 ;
     RECT  24 7.909 25.032 8.195 ;
     RECT  60.912 6.323 62.808 8.195 ;
     RECT  47.76 7.957 49.56 8.243 ;
     RECT  64.5 6.323 64.812 8.245 ;
     RECT  71.52 7.427 72.912 8.291 ;
     RECT  66.24 7.141 68.136 8.389 ;
     RECT  53.7 6.611 55.176 8.437 ;
     RECT  56.208 6.611 56.712 8.437 ;
     RECT  18.336 7.429 18.912 8.483 ;
     RECT  52.704 6.085 52.728 8.485 ;
     RECT  53.7 8.437 56.712 8.485 ;
     RECT  69.792 7.381 70.212 8.485 ;
     RECT  85.344 6.275 87 8.485 ;
     RECT  80.7 6.805 83.88 8.533 ;
     RECT  45.6 5.605 46.488 8.579 ;
     RECT  78 7.717 79.128 8.773 ;
     RECT  85.056 8.485 87 8.773 ;
     RECT  88.656 7.381 89.4 8.773 ;
     RECT  37.5 6.851 37.944 8.869 ;
     RECT  64.5 8.245 65.256 8.869 ;
     RECT  51 7.379 51.312 8.965 ;
     RECT  69.552 8.485 70.212 9.013 ;
     RECT  77.328 8.773 79.128 9.013 ;
     RECT  31.968 7.957 32.412 9.059 ;
     RECT  58.992 7.909 59.88 9.059 ;
     RECT  61.248 8.195 62.112 9.059 ;
     RECT  5.1 2.151 5.412 9.061 ;
     RECT  10.5 8.195 11.4 9.061 ;
     RECT  13.2 8.195 13.512 9.061 ;
     RECT  69.552 9.013 70.968 9.061 ;
     RECT  72.048 8.291 72.912 9.061 ;
     RECT  24 8.195 24.312 9.109 ;
     RECT  85.056 8.773 89.4 9.109 ;
     RECT  40.2 7.667 41.16 9.155 ;
     RECT  66.24 8.389 68.328 9.155 ;
     RECT  80.496 8.533 83.88 9.251 ;
     RECT  59.1 9.059 59.88 9.493 ;
     RECT  26.7 7.475 27.012 9.541 ;
     RECT  15.9 7.475 16.212 9.637 ;
     RECT  42.9 2.151 43.212 9.637 ;
     RECT  75.3 7.427 75.912 9.637 ;
     RECT  33.888 5.747 35.112 9.779 ;
     RECT  52.704 8.485 56.712 9.827 ;
     RECT  37.5 8.869 38.808 9.875 ;
     RECT  84.912 9.109 89.4 9.877 ;
     RECT  84.816 9.877 89.4 9.923 ;
     RECT  29.232 8.003 29.712 9.925 ;
     RECT  7.8 2.151 8.112 10.021 ;
     RECT  61.344 9.059 62.112 10.117 ;
     RECT  64.224 8.869 65.256 10.117 ;
     RECT  45.6 8.579 45.912 10.213 ;
     RECT  61.152 10.117 62.112 10.213 ;
     RECT  48.3 8.243 49.56 10.261 ;
     RECT  50.88 8.965 51.312 10.261 ;
     RECT  5.1 9.061 6.264 10.307 ;
     RECT  26.112 9.541 27.012 10.307 ;
     RECT  52.992 9.827 56.712 10.307 ;
     RECT  72.048 9.061 73.032 10.355 ;
     RECT  23.376 9.109 24.312 10.499 ;
     RECT  28.08 9.541 28.104 10.595 ;
     RECT  18.6 8.483 18.912 10.597 ;
     RECT  46.992 10.501 47.016 10.597 ;
     RECT  20.88 8.195 21.612 10.643 ;
     RECT  46.992 10.597 47.304 10.643 ;
     RECT  67.2 9.155 68.328 10.693 ;
     RECT  69.504 9.061 70.968 10.693 ;
     RECT  80.496 9.251 83.832 10.789 ;
     RECT  84.816 9.923 87.432 10.789 ;
     RECT  10.5 9.061 13.512 10.883 ;
     RECT  67.2 10.693 70.968 10.883 ;
     RECT  18.48 10.597 18.912 10.885 ;
     RECT  7.68 10.021 8.112 10.931 ;
     RECT  34.704 9.779 35.112 10.979 ;
     RECT  48.3 10.261 51.312 10.979 ;
     RECT  40.2 9.155 41.064 11.171 ;
     RECT  80.496 10.789 87.432 11.171 ;
     RECT  74.784 9.637 75.912 11.173 ;
     RECT  26.7 10.307 27.012 11.221 ;
     RECT  47.28 10.643 47.304 11.269 ;
     RECT  48.3 10.979 48.612 11.269 ;
     RECT  44.976 10.213 45.912 11.363 ;
     RECT  40.2 11.171 40.512 11.365 ;
     RECT  50.112 10.979 51.312 11.365 ;
     RECT  77.328 9.013 79.368 11.365 ;
     RECT  80.496 11.171 87.24 11.365 ;
     RECT  9.36 10.789 9.384 11.459 ;
     RECT  38.784 9.875 38.808 11.459 ;
     RECT  42.24 9.637 43.212 11.459 ;
     RECT  52.992 10.307 55.176 11.459 ;
     RECT  77.328 11.365 87.24 11.459 ;
     RECT  10.5 10.883 10.812 11.653 ;
     RECT  29.232 9.925 30.408 11.699 ;
     RECT  72.048 10.355 72.912 11.797 ;
     RECT  21.3 10.643 21.612 11.845 ;
     RECT  24 10.499 24.312 11.941 ;
     RECT  64.224 10.117 65.688 11.941 ;
     RECT  67.2 10.883 70.536 11.941 ;
     RECT  12.336 10.883 13.512 11.987 ;
     RECT  50.112 11.365 51.96 11.987 ;
     RECT  26.7 11.221 27.48 12.035 ;
     RECT  50.112 11.987 51.312 12.035 ;
     RECT  77.328 11.459 79.608 12.083 ;
     RECT  64.224 11.941 70.536 12.277 ;
     RECT  74.688 11.173 75.912 12.277 ;
     RECT  59.1 9.493 59.976 12.325 ;
     RECT  61.104 10.213 62.112 12.325 ;
     RECT  88.656 9.923 89.4 12.325 ;
     RECT  59.1 12.325 62.112 12.371 ;
     RECT  24 11.941 24.408 12.373 ;
     RECT  47.28 11.269 48.612 12.469 ;
     RECT  80.7 11.459 87 12.515 ;
     RECT  90.672 7.717 91.812 12.515 ;
     RECT  13.2 11.987 13.512 12.517 ;
     RECT  32.1 9.059 32.412 12.517 ;
     RECT  18.432 10.885 18.912 12.563 ;
     RECT  29.232 11.699 29.712 12.563 ;
     RECT  47.136 12.469 48.612 12.611 ;
     RECT  18.6 12.563 18.912 12.709 ;
     RECT  5.1 10.307 5.832 13.045 ;
     RECT  10.128 11.653 10.812 13.045 ;
     RECT  15.9 9.637 16.344 13.045 ;
     RECT  91.5 12.515 91.812 13.045 ;
     RECT  13.2 12.517 13.656 13.091 ;
     RECT  24 12.373 24.456 13.093 ;
     RECT  37.5 9.875 37.812 13.093 ;
     RECT  63.456 12.277 70.536 13.139 ;
     RECT  44.304 11.845 44.328 13.187 ;
     RECT  24 13.093 25.128 13.235 ;
     RECT  74.688 12.277 75.96 13.235 ;
     RECT  77.328 12.083 78.312 13.331 ;
     RECT  14.832 13.045 14.856 13.429 ;
     RECT  56.4 10.307 56.712 13.621 ;
     RECT  39.888 11.365 40.512 13.669 ;
     RECT  4.512 13.045 5.832 13.715 ;
     RECT  20.736 11.845 21.612 13.715 ;
     RECT  24 13.235 24.408 13.715 ;
     RECT  39.888 13.669 41.016 13.715 ;
     RECT  64.224 13.139 70.212 13.715 ;
     RECT  72.048 11.797 73.56 13.715 ;
     RECT  88.656 12.325 89.544 13.715 ;
     RECT  80.7 12.515 83.928 13.717 ;
     RECT  85.056 12.515 87 13.717 ;
     RECT  60.672 12.371 62.112 13.811 ;
     RECT  48.192 12.611 48.612 13.859 ;
     RECT  14.832 13.429 14.904 13.907 ;
     RECT  24 13.715 24.312 13.909 ;
     RECT  51 12.035 51.312 13.909 ;
     RECT  77.424 13.331 78.312 14.053 ;
     RECT  79.584 12.083 79.608 14.099 ;
     RECT  10.128 13.045 11.448 14.197 ;
     RECT  10.128 14.197 11.592 14.291 ;
     RECT  34.8 10.979 35.112 14.341 ;
     RECT  69.9 13.715 70.212 14.341 ;
     RECT  91.5 13.045 92.088 14.387 ;
     RECT  53.184 11.459 55.176 14.485 ;
     RECT  77.424 14.053 78.408 14.485 ;
     RECT  50.784 13.909 51.312 14.533 ;
     RECT  52.368 14.485 55.176 14.533 ;
     RECT  37.5 13.093 37.944 14.629 ;
     RECT  40.2 13.715 41.016 14.675 ;
     RECT  80.7 13.717 87 14.677 ;
     RECT  88.656 13.715 89.352 14.677 ;
     RECT  77.424 14.485 78.696 14.723 ;
     RECT  21.3 13.715 21.612 14.725 ;
     RECT  26.7 12.035 27.012 14.725 ;
     RECT  36.432 11.317 36.456 14.773 ;
     RECT  64.224 13.715 68.616 14.773 ;
     RECT  69.9 14.341 70.824 14.773 ;
     RECT  77.424 14.723 78.408 14.819 ;
     RECT  77.424 14.819 78.312 14.867 ;
     RECT  80.7 14.677 89.352 14.867 ;
     RECT  29.4 12.563 29.712 14.917 ;
     RECT  32.1 12.517 33.096 15.299 ;
     RECT  14.832 13.907 14.856 15.301 ;
     RECT  18.6 12.709 19.704 15.301 ;
     RECT  21.3 14.725 21.72 15.301 ;
     RECT  23.088 13.909 24.312 15.347 ;
     RECT  10.5 14.291 11.592 15.349 ;
     RECT  13.2 13.091 13.512 15.349 ;
     RECT  14.784 15.301 14.856 15.349 ;
     RECT  5.1 13.715 5.832 15.443 ;
     RECT  15.9 13.045 16.584 15.443 ;
     RECT  21.168 15.301 21.72 15.443 ;
     RECT  61.104 13.811 62.112 15.445 ;
     RECT  17.664 15.301 19.704 15.491 ;
     RECT  40.2 14.675 40.632 15.491 ;
     RECT  56.4 13.621 57.048 15.491 ;
     RECT  26.7 14.725 27.144 15.539 ;
     RECT  72.048 13.715 72.912 15.781 ;
     RECT  10.128 15.349 11.592 15.827 ;
     RECT  72.048 15.781 73.128 15.827 ;
     RECT  26.7 15.539 27.012 15.829 ;
     RECT  85.056 14.867 89.352 15.923 ;
     RECT  21.168 15.443 21.612 15.925 ;
     RECT  10.5 15.827 11.592 15.971 ;
     RECT  50.784 14.533 55.176 15.973 ;
     RECT  64.224 14.773 70.968 16.019 ;
     RECT  72.336 15.827 73.128 16.019 ;
     RECT  74.784 13.235 75.96 16.019 ;
     RECT  5.1 15.443 5.412 16.117 ;
     RECT  34.8 14.341 35.256 16.117 ;
     RECT  36.384 14.773 36.456 16.117 ;
     RECT  61.104 15.445 62.328 16.259 ;
     RECT  24 15.347 24.312 16.357 ;
     RECT  40.2 15.491 40.512 16.405 ;
     RECT  42.9 11.459 43.212 16.405 ;
     RECT  50.784 15.973 55.272 16.405 ;
     RECT  7.8 10.931 8.112 16.501 ;
     RECT  25.872 15.829 27.012 16.549 ;
     RECT  28.656 14.917 29.712 16.549 ;
     RECT  74.784 16.019 75.816 16.595 ;
     RECT  80.7 14.867 83.712 16.597 ;
     RECT  85.056 15.923 87 16.597 ;
     RECT  72.336 16.019 72.912 16.835 ;
     RECT  47.136 12.611 47.16 16.837 ;
     RECT  45.6 11.363 45.912 17.029 ;
     RECT  46.944 16.837 47.16 17.029 ;
     RECT  4.224 16.117 5.412 17.075 ;
     RECT  34.8 16.117 36.456 17.075 ;
     RECT  32.1 15.299 32.412 17.077 ;
     RECT  69.9 16.019 70.824 17.077 ;
     RECT  69.792 17.077 70.824 17.125 ;
     RECT  6.816 16.501 8.112 17.171 ;
     RECT  72.48 16.835 72.912 17.315 ;
     RECT  36.432 17.075 36.456 17.413 ;
     RECT  64.224 16.019 68.616 17.413 ;
     RECT  25.872 16.549 29.712 17.459 ;
     RECT  50.736 16.405 55.272 17.459 ;
     RECT  20.256 15.925 21.612 17.461 ;
     RECT  64.224 17.413 68.76 17.555 ;
     RECT  50.736 17.459 55.176 17.605 ;
     RECT  79.296 17.413 79.32 17.605 ;
     RECT  80.592 16.597 83.712 17.605 ;
     RECT  84.96 16.597 87 17.605 ;
     RECT  31.44 17.077 32.412 17.651 ;
     RECT  74.784 16.595 75.612 17.651 ;
     RECT  80.592 17.605 87 17.651 ;
     RECT  17.664 15.491 18.912 17.699 ;
     RECT  25.872 17.459 27.96 17.699 ;
     RECT  36.432 17.413 36.504 17.699 ;
     RECT  40.08 16.405 40.512 17.699 ;
     RECT  88.08 15.923 89.352 17.699 ;
     RECT  32.1 17.651 32.412 17.845 ;
     RECT  50.112 17.605 55.176 17.939 ;
     RECT  69.792 17.125 71.16 17.987 ;
     RECT  34.8 17.075 35.352 18.037 ;
     RECT  36.432 17.699 36.456 18.037 ;
     RECT  34.8 18.037 36.456 18.083 ;
     RECT  80.7 17.651 87 18.133 ;
     RECT  88.08 17.699 89.112 18.133 ;
     RECT  45.6 17.029 47.304 18.275 ;
     RECT  50.112 17.939 51.864 18.275 ;
     RECT  24 16.357 24.504 18.277 ;
     RECT  59.1 12.371 59.412 18.469 ;
     RECT  24 18.277 24.6 18.517 ;
     RECT  61.104 16.259 62.232 18.517 ;
     RECT  20.256 17.461 22.104 18.563 ;
     RECT  32.1 17.845 32.52 18.755 ;
     RECT  15.9 15.443 16.212 18.757 ;
     RECT  59.1 18.469 59.544 18.757 ;
     RECT  69.792 17.987 70.824 18.757 ;
     RECT  53.184 17.939 55.176 18.803 ;
     RECT  64.224 17.555 68.664 18.803 ;
     RECT  76.752 17.797 76.776 18.805 ;
     RECT  77.76 14.867 78.312 18.805 ;
     RECT  28.992 17.459 29.712 18.851 ;
     RECT  42.096 16.405 43.212 18.851 ;
     RECT  76.752 18.805 78.312 18.851 ;
     RECT  80.7 18.133 89.112 18.899 ;
     RECT  76.848 18.851 78.312 18.995 ;
     RECT  32.1 18.755 32.412 18.997 ;
     RECT  34.8 18.083 36.168 18.997 ;
     RECT  48.3 13.859 48.612 18.997 ;
     RECT  74.832 17.651 75.612 19.045 ;
     RECT  79.296 17.605 79.416 19.045 ;
     RECT  80.7 18.899 84.12 19.045 ;
     RECT  77.76 18.995 78.312 19.091 ;
     RECT  85.488 18.899 89.112 19.091 ;
     RECT  50.448 18.275 51.864 19.235 ;
     RECT  10.5 15.971 10.812 19.237 ;
     RECT  66.432 18.803 68.664 19.475 ;
     RECT  69.696 18.757 70.824 19.475 ;
     RECT  23.232 18.517 24.6 19.523 ;
     RECT  39.168 18.805 39.192 19.523 ;
     RECT  13.2 15.349 14.856 19.525 ;
     RECT  15.9 18.757 16.584 19.525 ;
     RECT  18.6 17.699 18.912 19.525 ;
     RECT  5.1 17.075 5.412 19.621 ;
     RECT  91.5 14.387 91.812 19.669 ;
     RECT  79.296 19.045 84.12 19.763 ;
     RECT  34.608 18.997 36.168 19.765 ;
     RECT  87.888 19.091 89.112 19.811 ;
     RECT  13.2 19.525 16.584 19.859 ;
     RECT  7.8 17.171 8.112 19.861 ;
     RECT  42.9 18.851 43.212 19.866 ;
     RECT  56.4 15.491 56.712 19.909 ;
     RECT  58.8 18.757 59.544 19.909 ;
     RECT  91.392 19.669 91.812 19.909 ;
     RECT  58.128 19.909 59.544 19.957 ;
     RECT  60.768 18.517 62.232 19.957 ;
     RECT  14.784 19.859 16.584 20.003 ;
     RECT  56.112 19.909 56.712 20.051 ;
     RECT  42.9 19.866 43.32 20.101 ;
     RECT  48.3 18.997 48.744 20.197 ;
     RECT  10.5 19.237 10.92 20.339 ;
     RECT  45.6 18.275 46.968 20.339 ;
     RECT  10.5 20.339 10.812 20.485 ;
     RECT  40.2 17.699 40.512 20.485 ;
     RECT  50.784 19.235 51.864 20.485 ;
     RECT  53.184 18.803 54.984 20.485 ;
     RECT  80.7 19.763 84.12 20.579 ;
     RECT  37.5 14.629 38.136 20.581 ;
     RECT  50.784 20.485 54.984 20.581 ;
     RECT  10.368 20.485 10.812 20.627 ;
     RECT  50.256 20.581 54.984 20.627 ;
     RECT  79.296 19.763 79.512 20.675 ;
     RECT  34.608 19.765 36.216 20.677 ;
     RECT  66.432 19.475 67.656 20.677 ;
     RECT  68.64 19.475 68.664 20.677 ;
     RECT  69.9 19.475 70.824 20.725 ;
     RECT  58.128 19.957 62.232 20.819 ;
     RECT  85.488 19.091 86.568 20.915 ;
     RECT  79.488 20.675 79.512 20.917 ;
     RECT  80.7 20.579 81.96 20.917 ;
     RECT  44.352 20.485 44.376 21.013 ;
     RECT  45.6 20.339 46.68 21.013 ;
     RECT  25.92 17.699 27.96 21.109 ;
     RECT  85.488 20.915 86.52 21.155 ;
     RECT  50.256 20.627 54.888 21.299 ;
     RECT  42 20.101 43.32 21.301 ;
     RECT  44.352 21.013 46.68 21.301 ;
     RECT  22.8 21.157 22.824 21.347 ;
     RECT  64.224 18.803 65.448 21.349 ;
     RECT  66.432 20.677 68.664 21.349 ;
     RECT  13.2 19.859 13.512 21.397 ;
     RECT  58.464 20.819 62.232 21.443 ;
     RECT  69.9 20.725 71.16 21.491 ;
     RECT  14.784 20.003 16.212 21.541 ;
     RECT  10.5 20.627 10.812 21.637 ;
     RECT  39.888 20.485 40.512 21.637 ;
     RECT  39.888 21.637 41.016 21.683 ;
     RECT  42 21.301 46.68 21.683 ;
     RECT  74.592 19.045 75.612 21.685 ;
     RECT  42 21.683 45.912 21.731 ;
     RECT  50.256 21.299 54.168 21.731 ;
     RECT  64.224 21.349 68.664 21.731 ;
     RECT  83.4 20.579 84.12 21.731 ;
     RECT  7.44 19.861 8.112 21.779 ;
     RECT  37.5 20.581 38.184 21.827 ;
     RECT  30.96 20.581 30.984 21.877 ;
     RECT  31.968 18.997 32.412 21.877 ;
     RECT  58.464 21.443 62.112 22.115 ;
     RECT  78 19.091 78.312 22.117 ;
     RECT  40.2 21.683 41.016 22.165 ;
     RECT  42 21.731 44.136 22.165 ;
     RECT  88.32 19.811 89.112 22.165 ;
     RECT  90.576 19.909 91.812 22.165 ;
     RECT  79.488 20.917 81.96 22.211 ;
     RECT  88.32 22.165 91.812 22.211 ;
     RECT  48.3 20.197 48.792 22.213 ;
     RECT  88.656 22.211 91.812 22.259 ;
     RECT  86.1 21.155 86.52 22.261 ;
     RECT  13.104 21.397 13.512 22.307 ;
     RECT  33.84 20.677 36.216 22.499 ;
     RECT  88.8 22.259 91.812 22.499 ;
     RECT  72.6 17.315 72.912 22.501 ;
     RECT  10.368 21.637 10.812 22.547 ;
     RECT  48.192 22.213 48.792 22.549 ;
     RECT  14.544 21.541 16.212 22.597 ;
     RECT  77.28 22.117 78.312 22.693 ;
     RECT  64.224 21.731 68.376 22.739 ;
     RECT  0.192 22.549 0.216 22.787 ;
     RECT  50.304 21.731 54.168 22.787 ;
     RECT  20.256 18.563 21.612 22.835 ;
     RECT  30.96 21.877 32.412 22.835 ;
     RECT  58.464 22.115 59.544 22.835 ;
     RECT  79.488 22.211 79.512 22.835 ;
     RECT  45.504 21.731 45.912 23.027 ;
     RECT  25.92 21.109 28.248 23.125 ;
     RECT  29.4 18.851 29.712 23.125 ;
     RECT  34.8 22.499 36.216 23.125 ;
     RECT  40.2 22.165 44.136 23.315 ;
     RECT  13.2 22.307 13.512 23.317 ;
     RECT  34.8 23.125 36.312 23.317 ;
     RECT  37.5 21.827 37.812 23.317 ;
     RECT  64.224 22.739 68.232 23.317 ;
     RECT  69.9 21.491 70.824 23.317 ;
     RECT  25.92 23.125 29.712 23.363 ;
     RECT  74.592 21.685 75.72 23.363 ;
     RECT  88.8 22.499 89.544 23.363 ;
     RECT  14.544 22.597 16.344 23.365 ;
     RECT  25.92 23.363 27.384 23.411 ;
     RECT  50.304 22.787 51.912 23.411 ;
     RECT  72.6 22.501 73.032 23.411 ;
     RECT  5.1 19.621 5.976 23.555 ;
     RECT  83.4 21.731 83.712 23.557 ;
     RECT  50.784 23.411 51.912 23.603 ;
     RECT  53.184 22.787 54.168 23.651 ;
     RECT  90.576 22.499 91.812 23.699 ;
     RECT  58.8 22.835 59.544 23.701 ;
     RECT  60.576 22.115 62.112 23.701 ;
     RECT  53.184 23.651 54.012 23.941 ;
     RECT  86.1 22.261 86.616 23.987 ;
     RECT  33.648 22.981 33.672 24.083 ;
     RECT  48.192 22.549 48.888 24.085 ;
     RECT  21.12 22.835 21.612 24.133 ;
     RECT  21.12 24.133 22.44 24.275 ;
     RECT  63.552 23.317 68.232 24.419 ;
     RECT  7.8 21.779 8.112 24.421 ;
     RECT  10.5 22.547 10.812 24.469 ;
     RECT  56.4 20.051 56.712 24.469 ;
     RECT  88.8 23.363 89.112 24.469 ;
     RECT  12.48 23.317 13.512 24.563 ;
     RECT  50.784 23.603 51.432 24.563 ;
     RECT  47.856 24.085 48.888 24.659 ;
     RECT  63.552 24.419 67.656 24.659 ;
     RECT  21.12 24.275 21.612 24.707 ;
     RECT  25.92 23.411 27.012 24.757 ;
     RECT  34.8 23.317 37.812 24.901 ;
     RECT  38.784 23.701 38.808 24.901 ;
     RECT  34.8 24.901 38.808 24.947 ;
     RECT  0.144 24.901 0.168 25.043 ;
     RECT  66.384 24.659 67.656 25.043 ;
     RECT  31.824 22.835 32.412 25.045 ;
     RECT  58.8 23.701 62.112 25.045 ;
     RECT  7.8 24.421 8.568 25.091 ;
     RECT  25.92 24.757 27.48 25.091 ;
     RECT  28.464 23.363 29.712 25.091 ;
     RECT  88.8 24.469 90.072 25.091 ;
     RECT  56.4 24.469 57 25.139 ;
     RECT  74.592 23.363 75.612 25.139 ;
     RECT  52.704 23.941 54.012 25.141 ;
     RECT  10.032 24.469 10.812 25.235 ;
     RECT  58.608 25.045 62.112 25.235 ;
     RECT  83.28 23.557 83.712 25.235 ;
     RECT  30.816 23.845 30.84 25.283 ;
     RECT  52.608 25.141 54.012 25.283 ;
     RECT  52.704 25.283 54.012 25.331 ;
     RECT  40.2 23.315 43.212 25.475 ;
     RECT  13.2 24.563 13.512 25.573 ;
     RECT  58.608 25.235 59.832 25.573 ;
     RECT  45.6 23.027 45.912 25.621 ;
     RECT  77.28 22.693 78.408 25.667 ;
     RECT  31.824 25.045 32.76 25.715 ;
     RECT  48.3 24.659 48.888 25.715 ;
     RECT  66.384 25.043 67.608 25.715 ;
     RECT  72.6 23.411 72.912 25.717 ;
     RECT  56.4 25.139 56.712 26.005 ;
     RECT  63.552 24.659 65.352 26.099 ;
     RECT  66.432 25.715 67.608 26.197 ;
     RECT  69.9 23.317 70.968 26.197 ;
     RECT  25.92 25.091 29.712 26.243 ;
     RECT  45.6 25.621 46.776 26.245 ;
     RECT  45.36 26.245 46.776 26.291 ;
     RECT  75.168 25.139 75.612 26.293 ;
     RECT  34.8 24.947 36.312 26.341 ;
     RECT  58.368 25.573 59.832 26.533 ;
     RECT  60.816 25.235 62.112 26.533 ;
     RECT  37.5 24.947 38.376 26.579 ;
     RECT  24 19.523 24.6 26.581 ;
     RECT  83.4 25.235 83.712 26.581 ;
     RECT  2.4 2.151 2.712 26.629 ;
     RECT  75.168 26.293 76.008 26.677 ;
     RECT  18.6 19.525 19.176 26.725 ;
     RECT  74.448 26.677 76.008 26.725 ;
     RECT  88.8 25.091 89.496 26.771 ;
     RECT  41.616 25.475 43.212 26.773 ;
     RECT  41.616 26.773 43.32 26.819 ;
     RECT  55.824 26.005 56.712 26.819 ;
     RECT  58.368 26.533 62.112 26.819 ;
     RECT  69.792 26.197 70.968 26.819 ;
     RECT  86.1 23.987 86.412 26.869 ;
     RECT  88.8 26.771 89.208 26.869 ;
     RECT  88.656 26.869 89.208 26.915 ;
     RECT  7.8 25.091 8.112 26.917 ;
     RECT  34.608 26.341 36.312 27.011 ;
     RECT  34.608 27.011 35.208 27.013 ;
     RECT  25.92 26.243 27.48 27.059 ;
     RECT  49.584 26.629 49.608 27.157 ;
     RECT  50.784 24.563 51.312 27.157 ;
     RECT  49.584 27.157 51.312 27.203 ;
     RECT  66.432 26.197 68.376 27.299 ;
     RECT  40.2 25.475 40.632 27.347 ;
     RECT  12.672 25.573 13.512 27.395 ;
     RECT  74.448 26.725 76.392 27.395 ;
     RECT  78 25.667 78.408 27.445 ;
     RECT  78 27.445 78.792 27.587 ;
     RECT  72.48 25.717 72.912 27.589 ;
     RECT  10.368 25.235 10.812 27.635 ;
     RECT  41.952 26.819 43.32 27.635 ;
     RECT  63.552 26.099 65.256 27.635 ;
     RECT  74.448 27.395 76.248 27.637 ;
     RECT  64.08 27.635 65.256 27.685 ;
     RECT  66.432 27.299 67.608 27.685 ;
     RECT  5.1 23.555 5.88 27.877 ;
     RECT  29.232 26.243 29.712 27.877 ;
     RECT  30.768 27.349 30.792 27.877 ;
     RECT  36.24 27.011 36.312 27.877 ;
     RECT  37.5 26.579 37.812 27.877 ;
     RECT  7.8 26.917 8.28 27.923 ;
     RECT  64.08 27.685 67.608 27.971 ;
     RECT  33.936 27.013 35.208 28.163 ;
     RECT  83.4 26.581 83.832 28.261 ;
     RECT  38.832 27.301 38.856 28.309 ;
     RECT  40.2 27.347 40.512 28.309 ;
     RECT  53.184 25.331 54.012 28.357 ;
     RECT  72.144 27.589 72.912 28.405 ;
     RECT  74.4 27.637 76.248 28.405 ;
     RECT  29.232 27.877 30.792 28.451 ;
     RECT  32.1 25.715 32.76 28.451 ;
     RECT  36.24 27.877 37.812 28.453 ;
     RECT  38.832 28.309 40.512 28.453 ;
     RECT  52.992 28.357 54.012 28.453 ;
     RECT  36.24 28.453 40.512 28.499 ;
     RECT  45.36 26.291 45.912 28.501 ;
     RECT  56.4 26.819 56.712 28.501 ;
     RECT  72.144 28.405 76.248 28.501 ;
     RECT  25.92 27.059 27.012 28.595 ;
     RECT  78 27.587 78.696 28.645 ;
     RECT  88.656 26.915 89.112 28.645 ;
     RECT  55.872 28.501 56.712 28.693 ;
     RECT  14.544 23.365 16.488 28.741 ;
     RECT  77.52 28.645 79.032 28.741 ;
     RECT  39.744 28.499 40.512 28.837 ;
     RECT  41.952 27.635 43.212 28.837 ;
     RECT  17.664 26.725 19.176 28.931 ;
     RECT  2.4 26.629 3.384 28.933 ;
     RECT  5.1 27.877 6.072 28.933 ;
     RECT  7.8 27.923 8.112 28.933 ;
     RECT  39.744 28.837 43.212 29.027 ;
     RECT  21.3 24.707 21.612 29.029 ;
     RECT  55.872 28.693 57.288 29.075 ;
     RECT  83.088 28.261 83.832 29.075 ;
     RECT  36.24 28.499 38.76 29.123 ;
     RECT  18.6 28.931 19.176 29.219 ;
     RECT  29.232 28.451 29.928 29.219 ;
     RECT  58.608 26.819 62.112 29.219 ;
     RECT  52.752 28.453 54.012 29.363 ;
     RECT  72.048 28.501 76.248 29.363 ;
     RECT  26.7 28.595 27.012 29.365 ;
     RECT  83.28 29.075 83.832 29.459 ;
     RECT  53.184 29.363 54.012 29.557 ;
     RECT  85.2 26.869 86.412 29.557 ;
     RECT  10.5 27.635 10.812 29.605 ;
     RECT  36.24 29.123 37.812 29.651 ;
     RECT  2.4 28.933 6.072 29.699 ;
     RECT  14.544 28.741 16.584 29.701 ;
     RECT  72.048 29.363 73.896 29.747 ;
     RECT  10.5 29.605 11.64 29.941 ;
     RECT  23.376 26.581 24.6 30.035 ;
     RECT  34.8 28.163 35.208 30.085 ;
     RECT  88.224 28.645 89.112 30.131 ;
     RECT  34.8 30.085 35.256 30.181 ;
     RECT  36.24 29.651 36.312 30.181 ;
     RECT  10.5 29.941 12.072 30.275 ;
     RECT  53.184 29.557 54.12 30.275 ;
     RECT  7.8 28.933 8.232 30.323 ;
     RECT  26.7 29.365 27.96 30.323 ;
     RECT  13.2 27.395 13.512 30.325 ;
     RECT  4.992 29.699 6.072 30.371 ;
     RECT  41.952 29.027 43.212 30.373 ;
     RECT  80.7 22.211 81.96 30.421 ;
     RECT  77.52 28.741 79.128 30.467 ;
     RECT  75.3 29.363 76.248 30.613 ;
     RECT  32.1 28.451 32.412 30.661 ;
     RECT  34.8 30.181 36.312 30.661 ;
     RECT  37.5 29.651 37.812 30.661 ;
     RECT  58.608 29.219 59.412 30.661 ;
     RECT  60.432 29.219 62.112 30.661 ;
     RECT  13.104 30.325 13.512 30.803 ;
     RECT  33.696 30.181 33.72 30.851 ;
     RECT  34.8 30.661 37.812 30.851 ;
     RECT  93.024 30.181 93.048 30.851 ;
     RECT  83.28 29.459 83.712 30.853 ;
     RECT  23.424 30.035 24.6 30.899 ;
     RECT  45.312 28.501 45.912 30.949 ;
     RECT  58.608 30.661 62.112 30.997 ;
     RECT  19.92 29.221 19.944 31.091 ;
     RECT  58.608 30.997 62.712 31.187 ;
     RECT  75.3 30.613 76.488 31.189 ;
     RECT  80.592 30.421 81.96 31.235 ;
     RECT  34.8 30.851 35.256 31.237 ;
     RECT  36.24 30.851 37.812 31.333 ;
     RECT  72.144 29.747 73.896 31.379 ;
     RECT  45.312 30.949 46.008 31.427 ;
     RECT  36.24 31.333 38.184 31.475 ;
     RECT  39.744 29.027 40.512 31.477 ;
     RECT  53.184 30.275 54.012 31.525 ;
     RECT  56.256 29.075 57.288 31.525 ;
     RECT  58.608 31.187 62.52 31.525 ;
     RECT  91.5 23.699 91.812 31.525 ;
     RECT  36.24 31.475 37.944 31.619 ;
     RECT  48.3 25.715 48.612 31.717 ;
     RECT  14.544 29.701 17.16 31.763 ;
     RECT  29.4 29.219 29.928 31.763 ;
     RECT  72.6 31.379 73.896 31.765 ;
     RECT  75.3 31.189 76.776 31.813 ;
     RECT  78 30.467 79.128 31.813 ;
     RECT  55.056 30.853 55.08 31.907 ;
     RECT  75.3 31.813 79.128 31.909 ;
     RECT  45.6 31.427 46.008 31.955 ;
     RECT  31.392 30.661 32.412 32.197 ;
     RECT  33.84 31.237 35.256 32.197 ;
     RECT  12.048 30.275 12.072 32.245 ;
     RECT  64.08 27.971 67.512 32.245 ;
     RECT  48.3 31.717 48.744 32.389 ;
     RECT  49.872 27.203 51.312 32.389 ;
     RECT  91.5 31.525 92.136 32.389 ;
     RECT  93.168 31.861 93.192 32.389 ;
     RECT  2.4 29.699 3.384 32.437 ;
     RECT  18.6 29.219 18.912 32.437 ;
     RECT  37.392 31.619 37.944 32.437 ;
     RECT  39.264 31.477 40.512 32.437 ;
     RECT  48.3 32.389 51.312 32.437 ;
     RECT  80.7 31.235 81.96 32.437 ;
     RECT  83.184 30.853 83.712 32.437 ;
     RECT  88.8 30.131 89.112 32.437 ;
     RECT  90.096 29.605 90.12 32.437 ;
     RECT  31.392 32.197 35.256 32.483 ;
     RECT  56.256 31.525 62.52 32.483 ;
     RECT  64.08 32.245 67.608 32.485 ;
     RECT  23.568 30.899 24.6 32.531 ;
     RECT  37.392 32.437 40.512 32.531 ;
     RECT  34.8 32.483 35.256 32.723 ;
     RECT  88.8 32.437 90.12 32.723 ;
     RECT  5.1 30.371 6.072 32.725 ;
     RECT  7.8 30.323 8.112 32.725 ;
     RECT  5.1 32.725 8.112 32.771 ;
     RECT  11.952 32.245 12.072 32.771 ;
     RECT  55.152 32.725 55.176 32.869 ;
     RECT  58.608 32.483 62.52 32.917 ;
     RECT  26.7 30.323 27.012 32.965 ;
     RECT  63.936 32.485 67.608 32.965 ;
     RECT  6.912 32.771 8.112 33.013 ;
     RECT  18.6 32.437 19.128 33.013 ;
     RECT  72.6 31.765 74.232 33.013 ;
     RECT  75.3 31.909 79.224 33.013 ;
     RECT  72.6 33.013 79.224 33.059 ;
     RECT  31.392 32.483 32.952 33.107 ;
     RECT  55.152 32.869 55.272 33.107 ;
     RECT  72.6 33.059 76.776 33.107 ;
     RECT  13.2 30.803 13.512 33.109 ;
     RECT  14.544 31.763 16.584 33.109 ;
     RECT  37.5 32.531 40.512 33.397 ;
     RECT  41.568 30.373 43.212 33.397 ;
     RECT  52.704 31.525 54.012 33.397 ;
     RECT  74.208 33.107 76.776 33.443 ;
     RECT  87.552 32.437 87.576 33.539 ;
     RECT  80.7 32.437 83.712 33.541 ;
     RECT  63.84 32.965 67.608 33.587 ;
     RECT  47.088 31.477 47.112 33.589 ;
     RECT  13.2 33.109 16.584 33.635 ;
     RECT  88.8 32.723 89.688 33.781 ;
     RECT  37.5 33.397 43.212 33.827 ;
     RECT  29.4 31.763 29.712 34.069 ;
     RECT  11.952 32.771 11.976 34.117 ;
     RECT  13.2 33.635 16.488 34.117 ;
     RECT  36.24 31.619 36.312 34.165 ;
     RECT  37.5 33.827 38.856 34.165 ;
     RECT  69.9 26.819 70.968 34.165 ;
     RECT  2.4 32.437 3.432 34.211 ;
     RECT  78 33.059 79.224 34.213 ;
     RECT  6.912 33.013 8.232 34.259 ;
     RECT  18.48 33.013 19.128 34.259 ;
     RECT  91.5 32.389 93.192 34.259 ;
     RECT  36.24 34.165 38.856 34.355 ;
     RECT  48.096 32.437 51.312 34.355 ;
     RECT  5.1 32.771 5.412 34.453 ;
     RECT  6.912 34.259 8.112 34.453 ;
     RECT  80.7 33.541 83.832 34.595 ;
     RECT  25.68 30.181 25.704 34.643 ;
     RECT  40.08 33.827 43.212 34.739 ;
     RECT  29.4 34.069 30.696 34.741 ;
     RECT  56.256 32.483 57.288 34.741 ;
     RECT  58.608 32.917 62.616 34.741 ;
     RECT  63.936 33.587 67.608 34.741 ;
     RECT  78 34.213 79.272 34.787 ;
     RECT  5.1 34.453 8.112 34.835 ;
     RECT  52.56 33.397 54.012 34.835 ;
     RECT  26.7 32.965 27.912 34.883 ;
     RECT  29.4 34.741 30.792 34.883 ;
     RECT  88.8 33.781 89.784 34.931 ;
     RECT  45.6 31.955 45.912 35.221 ;
     RECT  46.944 33.589 47.112 35.221 ;
     RECT  11.952 34.117 16.488 35.267 ;
     RECT  32.1 33.107 32.952 35.269 ;
     RECT  72.6 33.107 72.912 35.269 ;
     RECT  91.5 34.259 92.472 35.269 ;
     RECT  78 34.787 79.224 35.363 ;
     RECT  55.248 33.107 55.272 35.459 ;
     RECT  36.24 34.355 38.04 35.605 ;
     RECT  36.24 35.605 38.184 35.747 ;
     RECT  56.256 34.741 62.616 35.747 ;
     RECT  11.952 35.267 12.024 35.795 ;
     RECT  34.8 32.723 35.208 35.797 ;
     RECT  63.84 34.741 67.608 35.797 ;
     RECT  69.024 34.165 70.968 35.797 ;
     RECT  80.7 34.595 83.712 35.797 ;
     RECT  10.5 30.275 10.812 35.845 ;
     RECT  11.952 35.795 11.976 35.845 ;
     RECT  18.6 34.259 19.128 35.845 ;
     RECT  13.104 35.267 16.488 35.939 ;
     RECT  21.3 29.029 21.912 35.939 ;
     RECT  63.84 35.797 70.968 36.035 ;
     RECT  36.24 35.747 38.04 36.083 ;
     RECT  91.5 35.269 93.144 36.131 ;
     RECT  64.08 36.035 70.968 36.275 ;
     RECT  34.8 35.797 35.256 36.277 ;
     RECT  36.24 36.083 36.312 36.277 ;
     RECT  32.1 35.269 33.528 36.323 ;
     RECT  74.976 33.443 76.776 36.371 ;
     RECT  21.3 35.939 21.612 36.373 ;
     RECT  29.4 34.883 30.6 36.419 ;
     RECT  56.4 35.747 62.616 36.515 ;
     RECT  75.3 36.371 76.776 36.563 ;
     RECT  91.5 36.131 92.472 36.563 ;
     RECT  44.304 29.029 44.328 36.565 ;
     RECT  88.8 34.931 89.112 36.565 ;
     RECT  7.8 34.835 8.112 36.661 ;
     RECT  53.328 34.835 54.012 36.755 ;
     RECT  34.8 36.277 36.312 36.853 ;
     RECT  49.872 34.355 51.312 36.853 ;
     RECT  56.4 36.515 59.544 36.899 ;
     RECT  48.096 34.355 48.612 36.997 ;
     RECT  49.872 36.853 51.48 36.997 ;
     RECT  78 35.363 78.984 36.997 ;
     RECT  79.968 35.797 83.712 36.997 ;
     RECT  94.2 2.151 94.512 36.997 ;
     RECT  56.4 36.899 57.576 37.093 ;
     RECT  53.568 36.755 54.012 37.141 ;
     RECT  10.5 35.845 11.976 37.331 ;
     RECT  53.568 37.141 54.792 37.429 ;
     RECT  55.824 37.093 57.576 37.429 ;
     RECT  91.5 36.563 91.812 37.429 ;
     RECT  2.4 34.211 3.336 37.573 ;
     RECT  18.24 35.845 19.128 37.573 ;
     RECT  24 32.531 24.6 37.573 ;
     RECT  26.7 34.883 27.012 37.573 ;
     RECT  32.1 36.323 32.952 37.573 ;
     RECT  45.6 35.221 47.112 37.573 ;
     RECT  48.096 36.997 51.48 37.573 ;
     RECT  58.656 36.899 59.544 37.573 ;
     RECT  20.544 36.373 21.612 37.667 ;
     RECT  40.2 34.739 43.212 37.669 ;
     RECT  91.2 37.429 91.812 37.669 ;
     RECT  37.5 36.083 38.04 37.813 ;
     RECT  91.2 37.669 92.136 37.859 ;
     RECT  58.656 37.573 59.832 37.907 ;
     RECT  72.336 35.269 72.912 37.955 ;
     RECT  87.744 36.997 87.768 38.099 ;
     RECT  17.952 37.573 19.128 38.101 ;
     RECT  74.208 37.957 74.232 38.149 ;
     RECT  75.3 36.563 76.632 38.149 ;
     RECT  23.232 37.573 24.6 38.243 ;
     RECT  10.5 37.331 10.968 38.435 ;
     RECT  91.5 37.859 92.136 38.435 ;
     RECT  37.5 37.813 38.184 38.483 ;
     RECT  60.864 36.515 62.616 38.485 ;
     RECT  64.08 36.275 68.376 38.677 ;
     RECT  69.9 36.275 70.968 38.677 ;
     RECT  7.8 36.661 8.904 38.723 ;
     RECT  29.4 36.419 29.712 38.725 ;
     RECT  78 36.997 83.712 38.725 ;
     RECT  34.704 36.853 36.312 38.771 ;
     RECT  13.2 35.939 16.488 38.773 ;
     RECT  17.952 38.101 19.608 38.773 ;
     RECT  5.1 34.835 6.072 38.819 ;
     RECT  24 38.243 24.6 38.819 ;
     RECT  39.744 37.669 43.212 38.819 ;
     RECT  60.864 38.485 62.712 38.819 ;
     RECT  77.904 38.725 83.712 38.819 ;
     RECT  30.912 38.005 30.936 38.963 ;
     RECT  45.456 37.573 51.864 38.963 ;
     RECT  53.568 37.429 57.576 39.011 ;
     RECT  32.1 37.573 33.72 39.013 ;
     RECT  34.704 38.771 35.112 39.013 ;
     RECT  53.568 39.011 54.012 39.203 ;
     RECT  2.4 37.573 3.432 39.251 ;
     RECT  13.2 38.773 19.608 39.251 ;
     RECT  24 38.819 24.408 39.251 ;
     RECT  48.3 38.963 51.864 39.253 ;
     RECT  58.656 37.907 59.544 39.253 ;
     RECT  74.208 38.149 76.632 39.253 ;
     RECT  42.9 38.819 43.212 39.301 ;
     RECT  44.256 36.565 44.328 39.301 ;
     RECT  72.48 37.955 72.912 39.301 ;
     RECT  74.112 39.253 76.632 39.301 ;
     RECT  88.8 36.565 90.072 39.301 ;
     RECT  91.5 38.435 91.812 39.301 ;
     RECT  72.48 39.301 76.632 39.395 ;
     RECT  48.3 39.253 52.728 39.539 ;
     RECT  58.656 39.253 59.88 39.539 ;
     RECT  11.952 37.331 11.976 39.589 ;
     RECT  13.2 39.251 17.352 39.589 ;
     RECT  28.656 38.725 29.712 39.589 ;
     RECT  37.5 38.483 38.04 39.589 ;
     RECT  36.096 38.771 36.312 39.635 ;
     RECT  64.08 38.677 70.968 39.779 ;
     RECT  72.48 39.395 76.248 39.875 ;
     RECT  88.8 39.301 91.812 39.875 ;
     RECT  32.1 39.013 35.112 39.877 ;
     RECT  77.904 38.819 81.576 39.877 ;
     RECT  82.608 38.819 83.712 39.877 ;
     RECT  5.1 38.819 5.736 39.923 ;
     RECT  59.1 39.539 59.88 39.923 ;
     RECT  84.96 29.557 86.412 39.923 ;
     RECT  28.56 39.589 29.712 39.925 ;
     RECT  36.24 39.635 36.312 40.165 ;
     RECT  52.368 39.539 52.728 40.165 ;
     RECT  53.7 39.203 54.012 40.165 ;
     RECT  5.1 39.923 5.412 40.309 ;
     RECT  64.08 39.779 67.608 40.355 ;
     RECT  39.744 38.819 41.88 40.357 ;
     RECT  42.9 39.301 44.328 40.357 ;
     RECT  55.488 39.011 57.576 40.405 ;
     RECT  64.08 40.355 67.512 40.405 ;
     RECT  26.7 37.573 27.24 40.451 ;
     RECT  28.56 39.925 30.696 40.451 ;
     RECT  60.864 38.819 62.112 40.499 ;
     RECT  39.744 40.357 44.328 40.549 ;
     RECT  21.12 37.667 21.612 40.595 ;
     RECT  36.24 40.165 36.456 40.597 ;
     RECT  55.488 40.405 57.624 40.597 ;
     RECT  61.008 40.499 62.112 40.597 ;
     RECT  24 39.251 24.312 40.645 ;
     RECT  18.6 39.251 19.608 40.691 ;
     RECT  36.192 40.597 36.456 40.741 ;
     RECT  37.5 39.589 38.184 40.741 ;
     RECT  36.192 40.741 38.184 40.835 ;
     RECT  2.4 39.251 3.336 40.837 ;
     RECT  4.464 40.309 5.412 40.837 ;
     RECT  23.712 40.645 24.312 40.837 ;
     RECT  36.192 40.835 38.088 40.837 ;
     RECT  11.952 39.589 17.352 40.883 ;
     RECT  55.488 40.597 57.96 40.933 ;
     RECT  59.1 39.923 59.544 40.933 ;
     RECT  23.712 40.837 24.936 40.979 ;
     RECT  10.5 38.435 10.812 40.981 ;
     RECT  23.712 40.979 24.312 40.981 ;
     RECT  39.36 40.549 44.328 41.171 ;
     RECT  61.008 40.597 62.232 41.171 ;
     RECT  42.144 41.171 44.328 41.221 ;
     RECT  45.456 38.963 47.16 41.221 ;
     RECT  48.3 39.539 51.312 41.221 ;
     RECT  61.248 41.171 62.232 41.221 ;
     RECT  52.368 40.165 54.012 41.267 ;
     RECT  7.8 38.723 8.808 41.315 ;
     RECT  63.84 40.405 67.512 41.411 ;
     RECT  69.024 39.779 70.968 41.411 ;
     RECT  55.488 40.933 59.544 41.413 ;
     RECT  42.144 41.221 51.312 41.459 ;
     RECT  55.344 41.413 59.544 41.507 ;
     RECT  28.656 40.451 30.696 41.555 ;
     RECT  55.344 41.507 57.624 41.603 ;
     RECT  12.096 40.883 17.352 41.651 ;
     RECT  90.432 39.875 91.812 41.845 ;
     RECT  39.36 41.171 41.112 41.891 ;
     RECT  2.4 40.837 5.412 42.133 ;
     RECT  10.368 40.981 10.812 42.133 ;
     RECT  61.248 41.221 62.28 42.181 ;
     RECT  77.904 39.877 83.712 42.227 ;
     RECT  21.3 40.595 21.612 42.277 ;
     RECT  15.9 41.651 17.352 42.613 ;
     RECT  55.488 41.603 57.624 42.613 ;
     RECT  31.968 39.877 35.112 42.709 ;
     RECT  85.008 39.923 86.412 42.709 ;
     RECT  18.6 40.691 18.912 42.757 ;
     RECT  69.792 41.411 70.968 42.757 ;
     RECT  36.096 40.837 38.088 42.803 ;
     RECT  61.248 42.181 63 42.803 ;
     RECT  21.168 42.277 22.248 42.995 ;
     RECT  12.096 41.651 14.808 42.997 ;
     RECT  55.44 42.613 57.624 42.997 ;
     RECT  59.1 41.507 59.544 43.043 ;
     RECT  72.6 39.875 76.248 43.043 ;
     RECT  12 42.997 14.808 43.379 ;
     RECT  18.6 42.757 19.224 43.381 ;
     RECT  74.112 43.043 76.248 43.427 ;
     RECT  64.08 41.411 67.512 43.571 ;
     RECT  69.456 42.757 70.968 43.571 ;
     RECT  26.7 40.451 27.012 43.573 ;
     RECT  13.2 43.379 14.808 43.667 ;
     RECT  74.304 43.427 76.248 43.667 ;
     RECT  64.5 43.571 67.512 43.669 ;
     RECT  21.168 42.995 21.612 43.763 ;
     RECT  52.704 41.267 54.012 43.813 ;
     RECT  74.448 43.667 76.248 43.813 ;
     RECT  26.208 43.573 27.012 43.859 ;
     RECT  74.448 43.813 76.92 43.859 ;
     RECT  15.792 42.613 17.352 43.907 ;
     RECT  93.648 36.997 94.512 43.907 ;
     RECT  52.608 43.813 54.012 43.909 ;
     RECT  2.4 42.133 5.736 43.955 ;
     RECT  42.144 41.459 47.16 44.003 ;
     RECT  52.512 43.909 54.012 44.053 ;
     RECT  74.64 43.859 76.92 44.053 ;
     RECT  52.512 44.053 54.12 44.099 ;
     RECT  42.9 44.003 47.16 44.147 ;
     RECT  18.6 43.381 19.464 44.149 ;
     RECT  55.296 42.997 57.624 44.149 ;
     RECT  59.1 43.043 59.412 44.149 ;
     RECT  12 43.379 12.168 44.195 ;
     RECT  53.7 44.099 54.12 44.195 ;
     RECT  28.656 41.555 29.712 44.197 ;
     RECT  4.512 43.955 5.736 44.339 ;
     RECT  85.008 42.709 86.808 44.339 ;
     RECT  39.36 41.891 40.512 44.387 ;
     RECT  69.792 43.571 70.968 44.387 ;
     RECT  78 42.227 83.712 44.387 ;
     RECT  93.84 43.907 94.512 44.387 ;
     RECT  55.296 44.149 59.412 44.437 ;
     RECT  88.8 39.875 89.112 44.437 ;
     RECT  90.24 41.845 91.812 44.437 ;
     RECT  12.096 44.195 12.168 44.483 ;
     RECT  18.48 44.149 19.464 44.483 ;
     RECT  85.776 44.339 86.808 44.483 ;
     RECT  74.64 44.053 77.016 44.531 ;
     RECT  61.344 42.803 63 44.675 ;
     RECT  61.344 44.675 62.112 44.725 ;
     RECT  28.464 44.197 29.712 44.869 ;
     RECT  55.2 44.437 59.412 44.915 ;
     RECT  74.64 44.531 76.968 44.915 ;
     RECT  78 44.387 81.528 44.915 ;
     RECT  13.2 43.667 13.512 44.917 ;
     RECT  23.376 40.981 24.312 44.963 ;
     RECT  24 44.963 24.312 45.013 ;
     RECT  39.84 44.387 40.512 45.061 ;
     RECT  24 45.013 25.128 45.155 ;
     RECT  90.24 44.437 92.52 45.203 ;
     RECT  52.512 44.099 52.728 45.205 ;
     RECT  53.7 44.195 54.012 45.205 ;
     RECT  42.9 44.147 47.112 45.299 ;
     RECT  64.5 43.669 68.04 45.493 ;
     RECT  64.5 45.493 68.328 45.635 ;
     RECT  14.544 43.667 14.808 45.637 ;
     RECT  15.9 43.907 17.352 45.637 ;
     RECT  12.096 44.483 12.12 45.731 ;
     RECT  36.096 42.803 36.456 45.731 ;
     RECT  60.432 44.725 62.112 45.731 ;
     RECT  52.512 45.205 54.012 45.829 ;
     RECT  55.2 44.915 57.576 45.829 ;
     RECT  44.304 45.299 47.112 45.877 ;
     RECT  48.3 41.459 51.312 45.877 ;
     RECT  4.512 44.339 5.592 45.923 ;
     RECT  52.512 45.829 57.576 46.067 ;
     RECT  64.5 45.635 65.4 46.115 ;
     RECT  42.9 45.299 43.32 46.165 ;
     RECT  90.288 45.203 92.52 46.165 ;
     RECT  28.464 44.869 29.832 46.211 ;
     RECT  56.16 46.067 57.576 46.211 ;
     RECT  60.432 45.731 60.456 46.211 ;
     RECT  78 44.915 79.224 46.211 ;
     RECT  88.8 44.437 89.256 46.213 ;
     RECT  90.288 46.165 92.712 46.213 ;
     RECT  36.096 45.731 36.216 46.259 ;
     RECT  21.3 43.763 21.612 46.261 ;
     RECT  37.5 42.803 38.088 46.261 ;
     RECT  44.304 45.877 51.312 46.261 ;
     RECT  52.512 46.067 54.456 46.261 ;
     RECT  42.768 46.165 43.32 46.355 ;
     RECT  75.3 44.915 76.968 46.355 ;
     RECT  14.544 45.637 17.352 46.357 ;
     RECT  18.48 44.483 19.224 46.357 ;
     RECT  24 45.155 24.312 46.405 ;
     RECT  24 46.405 24.408 46.501 ;
     RECT  69.9 44.387 70.968 46.501 ;
     RECT  29.4 46.211 29.832 46.547 ;
     RECT  80.7 44.915 81.528 46.547 ;
     RECT  85.776 44.483 86.616 46.547 ;
     RECT  24 46.501 24.6 46.549 ;
     RECT  72.6 43.043 72.912 46.549 ;
     RECT  20.688 46.261 21.612 46.595 ;
     RECT  64.5 46.115 65.208 46.645 ;
     RECT  23.856 46.549 24.6 46.691 ;
     RECT  56.304 46.211 57.576 46.691 ;
     RECT  39.84 45.061 40.632 46.693 ;
     RECT  4.752 45.923 5.592 46.787 ;
     RECT  13.104 44.917 13.512 46.787 ;
     RECT  14.544 46.357 19.224 46.787 ;
     RECT  66.432 45.635 68.328 46.787 ;
     RECT  75.3 46.355 76.632 46.787 ;
     RECT  26.544 43.859 27.012 46.789 ;
     RECT  82.608 44.387 83.712 46.789 ;
     RECT  59.1 44.915 59.412 46.837 ;
     RECT  82.128 46.789 83.712 46.933 ;
     RECT  88.8 46.213 92.712 47.027 ;
     RECT  44.304 46.261 54.456 47.075 ;
     RECT  37.5 46.261 38.28 47.077 ;
     RECT  56.4 46.691 57.576 47.125 ;
     RECT  91.392 47.027 92.712 47.221 ;
     RECT  91.392 47.221 92.904 47.267 ;
     RECT  7.8 41.315 8.112 47.317 ;
     RECT  26.208 46.789 27.012 47.363 ;
     RECT  44.304 47.075 54.216 47.363 ;
     RECT  61.584 45.731 62.112 47.363 ;
     RECT  91.392 47.267 91.812 47.363 ;
     RECT  39.504 46.693 41.016 47.411 ;
     RECT  39.504 47.411 40.512 47.557 ;
     RECT  63.792 46.645 65.208 47.603 ;
     RECT  82.128 46.933 84.072 47.605 ;
     RECT  85.776 46.547 86.412 47.605 ;
     RECT  82.128 47.605 86.412 47.651 ;
     RECT  78 46.211 78.984 47.653 ;
     RECT  66.48 46.787 68.328 47.701 ;
     RECT  31.344 42.709 35.112 47.845 ;
     RECT  75.3 46.787 76.296 47.845 ;
     RECT  80.7 46.547 81.012 47.845 ;
     RECT  82.128 47.651 83.712 47.845 ;
     RECT  69.792 46.501 70.968 47.891 ;
     RECT  88.8 47.027 90.36 47.891 ;
     RECT  14.544 46.787 16.488 47.939 ;
     RECT  90.288 47.891 90.36 47.939 ;
     RECT  92.88 47.267 92.904 47.939 ;
     RECT  29.4 46.547 29.712 47.941 ;
     RECT  31.056 47.845 35.112 47.941 ;
     RECT  66.48 47.701 68.424 47.941 ;
     RECT  66.48 47.941 68.76 47.987 ;
     RECT  7.8 47.317 8.232 48.083 ;
     RECT  52.512 47.363 54.216 48.083 ;
     RECT  56.4 47.125 57.624 48.133 ;
     RECT  58.704 46.837 59.412 48.133 ;
     RECT  36.096 46.259 36.12 48.229 ;
     RECT  37.2 47.077 38.28 48.229 ;
     RECT  39.408 47.557 40.512 48.275 ;
     RECT  42.9 46.355 43.32 48.277 ;
     RECT  44.304 47.363 51.312 48.277 ;
     RECT  7.8 48.083 8.112 48.421 ;
     RECT  56.4 48.133 59.412 48.421 ;
     RECT  60.384 47.317 60.408 48.421 ;
     RECT  77.424 47.653 78.984 48.421 ;
     RECT  2.4 43.955 3.336 48.467 ;
     RECT  29.4 47.941 35.112 48.515 ;
     RECT  56.4 48.421 60.408 48.515 ;
     RECT  80.7 47.845 83.712 48.515 ;
     RECT  68.688 47.987 68.76 48.707 ;
     RECT  61.632 47.363 62.112 48.709 ;
     RECT  56.4 48.515 60.12 48.755 ;
     RECT  31.344 48.515 35.112 48.757 ;
     RECT  36.096 48.229 38.28 48.757 ;
     RECT  56.4 48.755 59.928 48.803 ;
     RECT  10.08 42.133 10.812 48.805 ;
     RECT  20.304 47.317 20.328 48.899 ;
     RECT  84.96 47.651 86.412 48.899 ;
     RECT  61.584 48.709 62.112 48.997 ;
     RECT  2.4 48.467 3.288 49.043 ;
     RECT  29.4 48.515 30.264 49.045 ;
     RECT  31.344 48.757 38.28 49.091 ;
     RECT  74.64 47.845 76.296 49.235 ;
     RECT  61.584 48.997 62.232 49.285 ;
     RECT  10.08 48.805 11.592 49.381 ;
     RECT  5.1 46.787 5.592 49.429 ;
     RECT  6.816 48.421 8.112 49.429 ;
     RECT  26.544 47.363 27.012 49.477 ;
     RECT  39.504 48.275 40.512 49.477 ;
     RECT  77.424 48.421 79.224 49.523 ;
     RECT  10.08 49.381 11.976 49.525 ;
     RECT  13.2 46.787 13.512 49.525 ;
     RECT  26.352 49.477 27.012 49.525 ;
     RECT  64.5 47.603 65.208 49.525 ;
     RECT  69.9 47.891 70.968 49.525 ;
     RECT  72.48 46.549 72.912 49.525 ;
     RECT  87.792 44.341 87.816 49.525 ;
     RECT  88.8 47.891 89.208 49.525 ;
     RECT  10.08 49.525 13.512 49.571 ;
     RECT  87.792 49.525 89.208 49.571 ;
     RECT  87.984 49.571 89.208 49.573 ;
     RECT  90.288 47.939 90.312 49.573 ;
     RECT  5.1 49.429 8.112 49.619 ;
     RECT  17.856 46.787 19.224 49.619 ;
     RECT  87.984 49.573 90.312 49.619 ;
     RECT  52.512 48.083 54.012 49.763 ;
     RECT  37.104 49.091 38.28 49.859 ;
     RECT  24 46.691 24.6 49.861 ;
     RECT  56.4 48.803 58.056 49.861 ;
     RECT  59.1 48.803 59.928 49.861 ;
     RECT  80.7 48.515 81.384 49.861 ;
     RECT  82.608 48.515 83.712 49.861 ;
     RECT  68.688 48.707 68.712 49.909 ;
     RECT  69.9 49.525 72.912 49.909 ;
     RECT  53.376 49.763 54.012 50.003 ;
     RECT  61.584 49.285 62.328 50.003 ;
     RECT  31.344 49.091 36.12 50.051 ;
     RECT  80.7 49.861 83.712 50.051 ;
     RECT  66.48 47.987 67.704 50.101 ;
     RECT  56.4 49.861 59.928 50.147 ;
     RECT  68.688 49.909 72.912 50.195 ;
     RECT  77.76 49.523 79.224 50.291 ;
     RECT  63.744 49.525 65.208 50.339 ;
     RECT  24 49.861 24.936 50.389 ;
     RECT  66.336 50.101 67.704 50.389 ;
     RECT  68.688 50.195 70.968 50.389 ;
     RECT  18.6 49.619 19.224 50.629 ;
     RECT  94.08 44.387 94.512 50.629 ;
     RECT  80.7 50.051 81.384 50.675 ;
     RECT  18.6 50.629 19.944 50.677 ;
     RECT  21.3 46.595 21.612 50.677 ;
     RECT  85.776 48.899 86.412 50.677 ;
     RECT  87.984 49.619 89.832 50.677 ;
     RECT  91.5 47.363 91.812 50.677 ;
     RECT  26.256 49.525 27.012 50.725 ;
     RECT  85.776 50.677 89.832 50.725 ;
     RECT  91.5 50.677 91.944 50.725 ;
     RECT  61.632 50.003 62.328 50.821 ;
     RECT  26.256 50.725 27.624 50.867 ;
     RECT  77.76 50.291 78.792 50.915 ;
     RECT  2.4 49.043 2.712 50.917 ;
     RECT  3.696 50.677 3.72 50.917 ;
     RECT  7.8 49.619 8.112 50.917 ;
     RECT  63.744 50.339 64.812 50.917 ;
     RECT  77.76 50.915 78.696 50.963 ;
     RECT  85.776 50.725 91.944 50.963 ;
     RECT  61.632 50.821 62.424 51.203 ;
     RECT  63.648 50.917 64.812 51.203 ;
     RECT  85.776 50.963 91.812 51.251 ;
     RECT  12.528 49.571 13.512 51.299 ;
     RECT  63.84 51.203 64.812 51.347 ;
     RECT  66.336 50.389 70.968 51.347 ;
     RECT  5.1 49.619 6.312 51.395 ;
     RECT  14.784 47.939 16.488 51.395 ;
     RECT  59.1 50.147 59.928 51.395 ;
     RECT  39.504 49.477 41.016 51.397 ;
     RECT  77.76 50.963 78.456 51.443 ;
     RECT  5.1 51.395 5.544 51.541 ;
     RECT  74.304 51.397 74.328 51.637 ;
     RECT  75.3 49.235 76.296 51.637 ;
     RECT  26.256 50.867 27.528 51.733 ;
     RECT  7.632 50.917 8.112 51.781 ;
     RECT  25.968 51.733 27.528 51.829 ;
     RECT  23.184 50.389 24.936 51.875 ;
     RECT  7.632 51.781 9.096 51.877 ;
     RECT  10.08 49.571 11.256 51.877 ;
     RECT  24 51.875 24.936 51.923 ;
     RECT  29.088 49.045 30.264 51.923 ;
     RECT  85.776 51.251 89.88 51.923 ;
     RECT  56.4 50.147 58.056 52.165 ;
     RECT  59.1 51.395 59.412 52.165 ;
     RECT  42.9 48.277 51.312 52.211 ;
     RECT  74.304 51.637 76.296 52.211 ;
     RECT  2.4 50.917 3.72 52.259 ;
     RECT  15.9 51.395 16.488 52.261 ;
     RECT  36.096 50.051 36.12 52.261 ;
     RECT  37.2 49.859 38.28 52.261 ;
     RECT  53.472 50.003 54.012 52.261 ;
     RECT  15.9 52.261 17.304 52.357 ;
     RECT  18.6 50.677 21.612 52.357 ;
     RECT  31.344 50.051 35.112 52.357 ;
     RECT  36.096 52.261 38.28 52.357 ;
     RECT  66.336 51.347 67.608 52.403 ;
     RECT  29.4 51.923 30.264 52.453 ;
     RECT  55.248 49.525 55.272 52.453 ;
     RECT  56.4 52.165 59.412 52.453 ;
     RECT  74.304 52.211 74.328 52.499 ;
     RECT  29.4 52.453 30.312 52.595 ;
     RECT  29.4 52.595 30.264 52.691 ;
     RECT  82.608 50.051 83.712 52.693 ;
     RECT  44.304 52.211 51.312 52.787 ;
     RECT  68.688 51.347 70.968 52.789 ;
     RECT  39.456 51.397 41.016 52.885 ;
     RECT  75.3 52.211 76.296 52.979 ;
     RECT  82.032 52.693 83.712 52.981 ;
     RECT  84.72 52.165 84.744 52.981 ;
     RECT  2.4 52.259 2.904 53.027 ;
     RECT  55.248 52.453 59.412 53.027 ;
     RECT  72.48 50.195 72.912 53.027 ;
     RECT  4.848 51.541 5.544 53.029 ;
     RECT  53.472 52.261 54.168 53.075 ;
     RECT  3.984 53.029 5.544 53.315 ;
     RECT  61.8 51.203 62.424 53.317 ;
     RECT  61.056 53.317 62.424 53.365 ;
     RECT  68.688 52.789 71.448 53.411 ;
     RECT  24 51.923 24.312 53.557 ;
     RECT  72.6 53.027 72.912 53.557 ;
     RECT  82.032 52.981 84.744 53.603 ;
     RECT  68.736 53.411 71.448 53.795 ;
     RECT  22.8 53.557 22.824 53.843 ;
     RECT  61.056 53.365 62.808 53.941 ;
     RECT  53.472 53.075 54.012 54.085 ;
     RECT  55.248 53.027 55.272 54.085 ;
     RECT  56.4 53.027 59.412 54.085 ;
     RECT  61.056 53.941 63.336 54.085 ;
     RECT  87.984 51.923 89.88 54.085 ;
     RECT  91.5 51.251 91.812 54.085 ;
     RECT  87.984 54.085 91.812 54.131 ;
     RECT  39.456 52.885 41.064 54.179 ;
     RECT  94.032 50.629 94.512 54.371 ;
     RECT  56.4 54.085 63.336 54.467 ;
     RECT  2.4 53.027 2.712 54.565 ;
     RECT  66.336 52.403 67.512 54.613 ;
     RECT  13.2 51.299 13.512 54.661 ;
     RECT  49.584 52.787 51.312 54.707 ;
     RECT  52.704 54.085 54.012 54.755 ;
     RECT  68.736 53.795 71.304 54.899 ;
     RECT  66.336 54.613 67.608 54.949 ;
     RECT  68.736 54.899 70.968 54.949 ;
     RECT  61.056 54.467 63.336 55.043 ;
     RECT  87.984 54.131 89.208 55.045 ;
     RECT  14.784 51.395 14.808 55.093 ;
     RECT  56.4 54.467 59.412 55.139 ;
     RECT  64.5 51.347 64.812 55.237 ;
     RECT  66.336 54.949 70.968 55.237 ;
     RECT  75.3 52.979 76.248 55.237 ;
     RECT  7.632 51.877 11.256 55.283 ;
     RECT  25.968 51.829 27.72 55.285 ;
     RECT  56.4 55.139 58.056 55.331 ;
     RECT  31.344 52.357 38.28 55.381 ;
     RECT  53.04 54.755 54.012 55.525 ;
     RECT  55.152 54.085 55.272 55.525 ;
     RECT  61.056 55.043 62.808 55.573 ;
     RECT  72.6 53.557 73.752 55.669 ;
     RECT  12.864 54.661 13.512 55.715 ;
     RECT  31.344 55.381 38.376 55.715 ;
     RECT  49.872 54.707 51.312 55.765 ;
     RECT  31.344 55.715 38.184 55.811 ;
     RECT  7.632 55.283 8.904 55.907 ;
     RECT  39.456 54.179 40.632 56.003 ;
     RECT  31.344 55.811 38.088 56.005 ;
     RECT  79.68 54.661 79.704 56.195 ;
     RECT  14.688 55.093 14.808 56.245 ;
     RECT  15.9 52.357 21.612 56.245 ;
     RECT  3.984 53.315 5.412 56.339 ;
     RECT  24 53.557 24.408 56.341 ;
     RECT  49.872 55.765 51.912 56.389 ;
     RECT  53.04 55.525 55.272 56.389 ;
     RECT  60.528 55.573 62.808 56.389 ;
     RECT  25.968 55.285 27.96 56.483 ;
     RECT  49.872 56.389 55.272 56.483 ;
     RECT  56.4 55.331 57.96 56.483 ;
     RECT  59.1 55.139 59.412 56.533 ;
     RECT  60.528 56.389 63.24 56.533 ;
     RECT  59.1 56.533 63.24 56.579 ;
     RECT  80.7 50.675 81.012 56.677 ;
     RECT  82.032 53.603 83.712 56.677 ;
     RECT  59.1 56.579 62.76 56.725 ;
     RECT  66.096 55.237 70.968 56.771 ;
     RECT  78 51.443 78.456 56.773 ;
     RECT  58.992 56.725 62.76 56.867 ;
     RECT  80.7 56.677 83.712 56.867 ;
     RECT  2.4 54.565 2.808 56.915 ;
     RECT  7.632 55.907 8.28 57.013 ;
     RECT  9.936 55.283 11.256 57.013 ;
     RECT  14.688 56.245 21.612 57.059 ;
     RECT  72.24 55.669 73.752 57.059 ;
     RECT  75.12 55.237 76.248 57.059 ;
     RECT  66.096 56.771 67.704 57.107 ;
     RECT  64.5 55.237 65.016 57.299 ;
     RECT  7.632 57.013 11.256 57.347 ;
     RECT  30.912 56.005 38.088 57.443 ;
     RECT  13.2 55.715 13.512 57.445 ;
     RECT  14.688 57.059 14.808 57.445 ;
     RECT  80.7 56.867 81.528 57.541 ;
     RECT  49.872 56.483 54.936 57.635 ;
     RECT  87.84 55.045 89.208 57.875 ;
     RECT  39.648 56.003 40.632 57.973 ;
     RECT  60.96 56.867 62.76 58.021 ;
     RECT  84.72 53.603 84.744 58.021 ;
     RECT  85.776 51.923 86.412 58.021 ;
     RECT  84.72 58.021 86.568 58.067 ;
     RECT  13.2 57.445 14.808 58.069 ;
     RECT  66.336 57.107 67.704 58.069 ;
     RECT  13.104 58.069 14.808 58.117 ;
     RECT  15.9 57.059 21.612 58.117 ;
     RECT  24 56.341 24.744 58.117 ;
     RECT  25.968 56.483 27.012 58.117 ;
     RECT  49.872 57.635 54.12 58.117 ;
     RECT  60.96 58.021 63.096 58.117 ;
     RECT  64.5 57.299 64.812 58.117 ;
     RECT  90.672 54.131 91.812 58.117 ;
     RECT  49.584 58.117 54.12 58.163 ;
     RECT  72.6 57.059 73.752 58.163 ;
     RECT  39.408 57.973 40.632 58.165 ;
     RECT  78 56.773 78.552 58.165 ;
     RECT  7.632 57.347 8.568 58.259 ;
     RECT  13.104 58.117 21.612 58.259 ;
     RECT  60.96 58.117 64.812 58.499 ;
     RECT  72.6 58.163 73.56 58.549 ;
     RECT  42.9 52.211 43.212 58.645 ;
     RECT  58.992 56.867 59.88 58.645 ;
     RECT  61.008 58.499 64.812 58.645 ;
     RECT  65.856 58.069 67.704 58.645 ;
     RECT  94.08 54.371 94.512 58.645 ;
     RECT  93.168 58.645 94.512 58.691 ;
     RECT  56.4 56.483 57.576 58.837 ;
     RECT  7.8 58.259 8.568 58.883 ;
     RECT  39.408 58.165 41.064 58.883 ;
     RECT  56.4 58.837 57.72 58.979 ;
     RECT  61.008 58.645 67.704 59.027 ;
     RECT  24 58.117 27.012 59.219 ;
     RECT  63.984 59.027 67.704 59.219 ;
     RECT  72.384 58.549 73.56 59.221 ;
     RECT  88.8 57.875 89.208 59.221 ;
     RECT  90.624 58.117 91.812 59.221 ;
     RECT  13.2 58.259 21.612 59.315 ;
     RECT  80.592 57.541 81.528 59.315 ;
     RECT  49.584 58.163 52.488 59.507 ;
     RECT  17.616 59.315 21.612 59.555 ;
     RECT  58.944 58.645 59.88 59.701 ;
     RECT  7.8 58.883 8.28 59.747 ;
     RECT  88.8 59.221 91.812 59.747 ;
     RECT  42.288 58.645 43.212 59.749 ;
     RECT  44.304 52.787 48.612 59.749 ;
     RECT  68.736 56.771 70.968 59.749 ;
     RECT  72.096 59.221 73.56 59.749 ;
     RECT  68.736 59.749 73.56 59.795 ;
     RECT  7.8 59.747 8.112 59.797 ;
     RECT  25.968 59.219 27.012 59.797 ;
     RECT  93.168 58.691 93.192 59.843 ;
     RECT  28.32 59.221 28.344 59.891 ;
     RECT  55.344 58.549 55.368 60.035 ;
     RECT  61.008 59.027 62.112 60.035 ;
     RECT  24 59.219 24.312 60.277 ;
     RECT  29.4 52.691 29.712 60.277 ;
     RECT  80.592 59.315 81.012 60.277 ;
     RECT  9.936 57.347 11.256 60.373 ;
     RECT  13.2 59.315 16.212 60.373 ;
     RECT  28.56 60.277 29.712 60.373 ;
     RECT  30.912 57.443 36.12 60.373 ;
     RECT  49.872 59.507 52.488 60.373 ;
     RECT  53.7 58.163 54.12 60.373 ;
     RECT  78 58.165 78.648 60.419 ;
     RECT  58.944 59.701 60.024 60.421 ;
     RECT  64.08 59.219 67.704 60.421 ;
     RECT  68.736 59.795 72.912 60.421 ;
     RECT  82.608 56.867 83.712 60.421 ;
     RECT  64.08 60.421 72.912 60.467 ;
     RECT  18.6 59.555 21.612 60.661 ;
     RECT  24 60.277 24.504 60.661 ;
     RECT  56.4 58.979 57.624 60.661 ;
     RECT  56.256 60.661 57.624 60.707 ;
     RECT  9.936 60.373 11.448 60.709 ;
     RECT  17.808 60.661 21.864 60.757 ;
     RECT  88.8 59.747 90.024 60.853 ;
     RECT  23.136 60.661 24.504 60.899 ;
     RECT  28.56 60.373 36.12 60.947 ;
     RECT  29.28 60.947 36.12 60.949 ;
     RECT  37.296 57.443 38.088 60.949 ;
     RECT  49.872 60.373 54.12 60.949 ;
     RECT  61.2 60.035 62.112 60.949 ;
     RECT  24 60.899 24.504 60.995 ;
     RECT  49.872 60.949 54.696 60.997 ;
     RECT  42.288 59.749 48.612 61.043 ;
     RECT  80.448 60.277 81.012 61.043 ;
     RECT  13.2 60.373 16.344 61.141 ;
     RECT  25.968 59.797 27.192 61.189 ;
     RECT  29.28 60.949 38.088 61.235 ;
     RECT  84.912 58.067 86.568 61.235 ;
     RECT  17.76 60.757 21.864 61.475 ;
     RECT  7.68 59.797 8.112 61.477 ;
     RECT  9.168 60.709 11.448 61.477 ;
     RECT  39.408 58.883 40.512 61.523 ;
     RECT  58.944 60.421 60.216 61.523 ;
     RECT  82.608 60.421 83.832 61.525 ;
     RECT  84.912 61.235 86.52 61.525 ;
     RECT  28.176 61.045 28.2 61.571 ;
     RECT  39.84 61.523 40.512 61.621 ;
     RECT  42.288 61.043 43.212 61.621 ;
     RECT  49.872 60.997 55.224 61.621 ;
     RECT  24 60.995 24.408 61.667 ;
     RECT  64.08 60.467 68.424 61.715 ;
     RECT  29.28 61.235 30.312 61.763 ;
     RECT  13.2 61.141 16.776 61.813 ;
     RECT  4.464 56.339 5.412 61.861 ;
     RECT  6.48 60.901 6.504 61.861 ;
     RECT  58.944 61.523 60.072 61.907 ;
     RECT  58.944 61.907 60.024 62.003 ;
     RECT  31.344 61.235 38.088 62.099 ;
     RECT  7.68 61.477 11.448 62.101 ;
     RECT  39.84 61.621 43.212 62.149 ;
     RECT  44.304 61.043 46.056 62.149 ;
     RECT  61.2 60.949 62.232 62.195 ;
     RECT  64.08 61.715 64.812 62.243 ;
     RECT  88.8 60.853 90.216 62.293 ;
     RECT  91.5 59.747 91.812 62.293 ;
     RECT  7.488 62.101 11.448 62.387 ;
     RECT  39.84 62.149 46.056 62.435 ;
     RECT  61.2 62.195 62.112 62.437 ;
     RECT  78 60.419 78.504 62.485 ;
     RECT  42.288 62.435 46.056 62.533 ;
     RECT  47.088 61.043 48.612 62.533 ;
     RECT  75.3 57.059 76.248 62.581 ;
     RECT  82.608 61.525 86.52 62.723 ;
     RECT  64.5 62.243 64.812 62.725 ;
     RECT  65.808 61.715 68.424 62.725 ;
     RECT  49.872 61.621 55.272 62.771 ;
     RECT  18.6 61.475 21.612 62.773 ;
     RECT  69.648 60.467 72.912 62.773 ;
     RECT  49.872 62.771 52.44 62.819 ;
     RECT  58.944 62.003 59.88 62.867 ;
     RECT  56.256 60.707 57.576 63.013 ;
     RECT  58.944 62.867 59.736 63.013 ;
     RECT  49.872 62.819 52.104 63.059 ;
     RECT  69.648 62.773 73.128 63.061 ;
     RECT  84.912 62.723 86.52 63.107 ;
     RECT  78 62.485 79.272 63.203 ;
     RECT  39.84 62.435 40.512 63.205 ;
     RECT  37.2 62.099 38.088 63.253 ;
     RECT  82.608 62.723 83.712 63.253 ;
     RECT  85.056 63.107 86.52 63.253 ;
     RECT  64.5 62.725 68.424 63.299 ;
     RECT  88.8 62.293 91.812 63.347 ;
     RECT  24 61.667 24.312 63.349 ;
     RECT  75.3 62.581 76.68 63.349 ;
     RECT  80.592 61.043 81.012 63.349 ;
     RECT  31.344 62.099 36.12 63.493 ;
     RECT  37.2 63.253 38.328 63.493 ;
     RECT  29.28 61.763 29.712 63.541 ;
     RECT  25.632 61.189 27.192 63.587 ;
     RECT  80.592 63.349 81.48 63.635 ;
     RECT  80.592 63.635 81.432 63.781 ;
     RECT  88.8 63.347 89.496 63.781 ;
     RECT  75.3 63.349 76.92 63.827 ;
     RECT  85.056 63.253 86.616 63.827 ;
     RECT  64.5 63.299 67.608 63.923 ;
     RECT  31.344 63.493 38.328 63.925 ;
     RECT  18.192 62.773 21.612 64.067 ;
     RECT  53.568 62.771 55.272 64.067 ;
     RECT  52.464 63.781 52.488 64.069 ;
     RECT  53.568 64.067 54.984 64.069 ;
     RECT  52.464 64.069 54.984 64.115 ;
     RECT  61.056 62.437 62.112 64.163 ;
     RECT  79.728 63.781 81.432 64.211 ;
     RECT  31.008 63.925 38.328 64.309 ;
     RECT  39.504 63.205 40.512 64.309 ;
     RECT  18.6 64.067 21.612 64.357 ;
     RECT  22.8 63.589 22.824 64.357 ;
     RECT  29.232 63.541 29.712 64.357 ;
     RECT  31.008 64.309 40.512 64.357 ;
     RECT  69.648 63.061 73.656 64.357 ;
     RECT  75.3 63.827 76.248 64.357 ;
     RECT  61.2 64.163 62.112 64.451 ;
     RECT  69.648 64.357 76.248 64.499 ;
     RECT  85.056 63.827 86.412 64.499 ;
     RECT  56.256 63.013 59.736 64.741 ;
     RECT  42.288 62.533 48.612 64.789 ;
     RECT  49.872 63.059 51.432 64.789 ;
     RECT  85.344 64.499 86.412 64.885 ;
     RECT  2.4 56.915 2.712 64.933 ;
     RECT  42.288 64.789 51.432 64.979 ;
     RECT  52.608 64.115 54.984 64.979 ;
     RECT  13.2 61.813 17.112 64.981 ;
     RECT  29.232 64.357 40.512 64.981 ;
     RECT  4.464 61.861 6.504 65.027 ;
     RECT  7.488 62.387 8.232 65.027 ;
     RECT  29.088 64.981 40.512 65.027 ;
     RECT  49.872 64.979 51.432 65.027 ;
     RECT  87.744 63.781 89.496 65.027 ;
     RECT  9.696 62.387 11.448 65.029 ;
     RECT  39.504 65.027 40.512 65.075 ;
     RECT  79.872 64.211 81.432 65.075 ;
     RECT  9.264 65.029 11.448 65.125 ;
     RECT  56.256 64.741 60.216 65.125 ;
     RECT  56.016 65.125 60.216 65.173 ;
     RECT  69.648 64.499 72.912 65.365 ;
     RECT  29.088 65.027 38.328 65.411 ;
     RECT  9.264 65.125 11.976 65.507 ;
     RECT  13.2 64.981 17.208 65.509 ;
     RECT  69.552 65.365 72.912 65.509 ;
     RECT  74.352 64.499 76.248 65.509 ;
     RECT  85.344 64.885 86.616 65.509 ;
     RECT  18.6 64.357 22.824 65.603 ;
     RECT  29.088 65.411 36.168 65.603 ;
     RECT  55.584 65.173 60.216 65.603 ;
     RECT  22.8 65.603 22.824 65.651 ;
     RECT  64.5 63.923 67.512 65.653 ;
     RECT  78 63.203 78.456 65.701 ;
     RECT  2.4 64.933 2.808 65.747 ;
     RECT  37.2 65.411 38.328 65.747 ;
     RECT  85.344 65.509 87.096 65.987 ;
     RECT  52.608 64.979 54.312 66.037 ;
     RECT  55.584 65.603 57.96 66.037 ;
     RECT  29.088 65.603 35.112 66.083 ;
     RECT  59.1 65.603 60.216 66.085 ;
     RECT  61.68 64.451 62.112 66.085 ;
     RECT  13.2 65.509 17.448 66.179 ;
     RECT  64.5 65.653 67.8 66.229 ;
     RECT  29.232 66.083 35.112 66.275 ;
     RECT  25.632 63.587 27.012 66.277 ;
     RECT  79.872 65.075 81.24 66.467 ;
     RECT  42.288 64.979 48.612 66.469 ;
     RECT  49.872 65.027 51.312 66.469 ;
     RECT  13.2 66.179 17.208 66.515 ;
     RECT  69.552 65.509 76.248 66.515 ;
     RECT  59.1 66.085 62.112 66.563 ;
     RECT  29.4 66.275 35.112 66.613 ;
     RECT  36.096 65.603 36.168 66.613 ;
     RECT  69.648 66.515 76.248 66.707 ;
     RECT  13.2 66.515 16.632 66.755 ;
     RECT  23.808 63.349 24.312 66.805 ;
     RECT  7.8 65.027 8.232 66.853 ;
     RECT  9.264 65.507 11.352 66.853 ;
     RECT  74.352 66.707 76.248 67.093 ;
     RECT  78 65.701 78.696 67.093 ;
     RECT  79.872 66.467 81.192 67.093 ;
     RECT  40.2 65.075 40.512 67.141 ;
     RECT  42.288 66.469 51.312 67.283 ;
     RECT  63.264 66.661 63.288 67.283 ;
     RECT  88.176 65.027 89.496 67.283 ;
     RECT  52.608 66.037 57.96 67.285 ;
     RECT  25.632 66.277 27.528 67.523 ;
     RECT  23.472 66.805 24.312 67.573 ;
     RECT  25.632 67.523 27.012 67.573 ;
     RECT  44.688 67.283 51.312 67.667 ;
     RECT  74.352 67.093 76.92 67.667 ;
     RECT  13.2 66.755 16.212 67.717 ;
     RECT  29.4 66.613 36.168 67.765 ;
     RECT  37.5 65.747 38.328 67.765 ;
     RECT  82.56 63.253 83.712 67.813 ;
     RECT  40.08 67.141 40.512 67.859 ;
     RECT  78 67.093 81.192 67.859 ;
     RECT  85.344 65.987 86.52 67.859 ;
     RECT  85.488 67.859 86.52 67.909 ;
     RECT  47.088 67.667 51.312 68.099 ;
     RECT  64.5 66.229 68.52 68.099 ;
     RECT  74.4 67.667 76.92 68.099 ;
     RECT  18.6 65.603 21.612 68.101 ;
     RECT  78 67.859 78.696 68.197 ;
     RECT  59.1 66.563 60.216 68.293 ;
     RECT  61.68 66.563 62.112 68.293 ;
     RECT  64.5 68.099 67.512 68.341 ;
     RECT  79.872 67.859 81.192 68.341 ;
     RECT  82.56 67.813 83.832 68.341 ;
     RECT  63.792 68.341 67.512 68.389 ;
     RECT  42.288 67.283 43.32 68.435 ;
     RECT  85.488 67.909 87.144 68.435 ;
     RECT  68.496 68.099 68.52 68.629 ;
     RECT  68.496 68.629 68.664 68.675 ;
     RECT  77.568 68.197 78.696 68.675 ;
     RECT  7.8 66.853 11.352 68.723 ;
     RECT  59.1 68.293 62.112 68.723 ;
     RECT  13.2 67.717 16.584 68.917 ;
     RECT  18.48 68.101 21.612 68.917 ;
     RECT  29.4 67.765 38.328 68.963 ;
     RECT  9.696 68.723 11.352 69.011 ;
     RECT  77.568 68.675 78.456 69.059 ;
     RECT  23.472 67.573 27.012 69.107 ;
     RECT  69.648 66.707 72.912 69.157 ;
     RECT  74.4 68.099 76.44 69.157 ;
     RECT  85.536 68.435 87.144 69.251 ;
     RECT  79.872 68.341 83.832 69.253 ;
     RECT  18.48 68.917 22.296 69.445 ;
     RECT  37.5 68.963 38.328 69.445 ;
     RECT  79.872 69.253 84.408 69.493 ;
     RECT  63.216 68.389 67.512 69.539 ;
     RECT  69.648 69.157 73.368 69.731 ;
     RECT  40.2 67.859 40.512 69.781 ;
     RECT  52.608 67.285 58.056 69.829 ;
     RECT  59.1 68.723 60.216 69.829 ;
     RECT  7.8 68.723 8.568 70.019 ;
     RECT  12.768 68.917 16.584 70.019 ;
     RECT  4.464 65.027 6.36 70.021 ;
     RECT  7.8 70.019 8.232 70.021 ;
     RECT  74.4 69.157 76.872 70.021 ;
     RECT  78 69.059 78.456 70.021 ;
     RECT  2.4 65.747 2.712 70.069 ;
     RECT  44.688 67.667 46.056 70.069 ;
     RECT  47.232 68.099 51.312 70.069 ;
     RECT  52.608 69.829 60.216 70.069 ;
     RECT  13.008 70.019 16.584 70.163 ;
     RECT  63.216 69.539 63.384 70.163 ;
     RECT  40.2 69.781 40.728 70.213 ;
     RECT  29.4 68.963 36.168 70.261 ;
     RECT  79.872 69.493 84.504 70.307 ;
     RECT  47.232 70.069 60.216 70.309 ;
     RECT  61.632 68.723 62.112 70.309 ;
     RECT  18.144 69.445 22.296 70.357 ;
     RECT  4.464 70.021 8.232 70.451 ;
     RECT  47.232 70.309 62.112 70.547 ;
     RECT  2.304 70.069 2.712 70.595 ;
     RECT  29.088 70.261 36.168 70.595 ;
     RECT  74.4 70.021 78.456 70.595 ;
     RECT  68.64 68.675 68.664 70.645 ;
     RECT  69.648 69.731 71.352 70.645 ;
     RECT  74.448 70.595 78.456 70.645 ;
     RECT  74.448 70.645 78.696 70.691 ;
     RECT  23.808 69.107 27.012 70.739 ;
     RECT  47.232 70.547 59.976 70.739 ;
     RECT  23.808 70.739 24.312 70.789 ;
     RECT  88.8 67.283 89.496 70.885 ;
     RECT  90.576 63.347 91.812 70.931 ;
     RECT  68.64 70.645 71.352 70.933 ;
     RECT  72.6 69.731 73.368 70.933 ;
     RECT  63.36 70.163 63.384 70.979 ;
     RECT  68.64 70.933 73.368 70.979 ;
     RECT  13.008 70.163 16.212 71.027 ;
     RECT  13.008 71.027 13.704 71.123 ;
     RECT  88.128 70.885 89.496 71.123 ;
     RECT  13.008 71.123 13.512 71.125 ;
     RECT  14.784 71.027 16.212 71.125 ;
     RECT  17.616 70.357 22.296 71.125 ;
     RECT  47.232 70.739 57.72 71.171 ;
     RECT  29.4 70.595 36.168 71.173 ;
     RECT  14.784 71.125 22.296 71.219 ;
     RECT  40.2 70.213 41.016 71.219 ;
     RECT  12.768 71.125 13.512 71.221 ;
     RECT  42.288 68.435 43.212 71.221 ;
     RECT  88.8 71.123 89.496 71.221 ;
     RECT  7.68 70.451 8.232 71.315 ;
     RECT  78 70.691 78.696 71.315 ;
     RECT  47.232 71.171 57.048 71.411 ;
     RECT  61.152 70.547 62.112 71.461 ;
     RECT  37.5 69.445 38.424 71.507 ;
     RECT  44.688 70.069 46.104 71.555 ;
     RECT  29.4 71.173 36.456 71.651 ;
     RECT  23.376 70.789 24.312 71.797 ;
     RECT  25.632 70.739 27.012 71.797 ;
     RECT  59.1 70.739 59.976 71.797 ;
     RECT  61.152 71.461 62.376 71.797 ;
     RECT  14.784 71.219 21.612 71.987 ;
     RECT  50.736 71.411 57.048 71.987 ;
     RECT  25.296 71.797 27.012 72.037 ;
     RECT  28.272 71.173 28.296 72.037 ;
     RECT  68.64 70.979 70.584 72.037 ;
     RECT  71.664 70.979 73.368 72.037 ;
     RECT  40.2 71.219 40.512 72.133 ;
     RECT  15.12 71.987 21.612 72.227 ;
     RECT  39.552 72.133 40.512 72.275 ;
     RECT  88.8 71.221 90.024 72.325 ;
     RECT  91.392 70.931 91.812 72.325 ;
     RECT  41.952 71.221 43.212 72.419 ;
     RECT  15.12 72.227 20.04 72.467 ;
     RECT  88.8 72.325 91.812 72.467 ;
     RECT  42.288 72.419 43.212 72.565 ;
     RECT  44.688 71.555 46.056 72.565 ;
     RECT  68.64 72.037 73.368 72.707 ;
     RECT  12.672 71.221 13.512 72.709 ;
     RECT  74.448 70.691 76.872 72.709 ;
     RECT  78 71.315 78.456 72.709 ;
     RECT  25.296 72.037 28.296 72.755 ;
     RECT  29.4 71.651 36.12 72.755 ;
     RECT  47.232 71.411 49.752 72.755 ;
     RECT  64.5 69.539 67.512 72.757 ;
     RECT  91.392 72.467 91.812 72.805 ;
     RECT  21.168 72.227 21.612 72.899 ;
     RECT  69.648 72.707 73.368 72.899 ;
     RECT  37.5 71.507 38.232 72.901 ;
     RECT  59.1 71.797 62.376 72.901 ;
     RECT  74.448 72.709 78.456 72.901 ;
     RECT  80.064 70.307 84.504 72.901 ;
     RECT  22.752 71.797 24.312 72.995 ;
     RECT  25.296 72.755 27.912 72.995 ;
     RECT  68.64 72.707 68.664 72.995 ;
     RECT  69.648 72.899 70.584 73.091 ;
     RECT  12.672 72.709 14.136 73.235 ;
     RECT  52.608 71.987 57.048 73.381 ;
     RECT  58.368 72.901 62.376 73.381 ;
     RECT  40.2 72.275 40.512 73.477 ;
     RECT  88.8 72.467 90.024 73.477 ;
     RECT  91.392 72.805 92.088 73.477 ;
     RECT  12.768 73.235 14.136 73.571 ;
     RECT  74.448 72.901 84.504 73.619 ;
     RECT  64.368 72.757 67.512 73.621 ;
     RECT  52.608 73.381 62.376 73.763 ;
     RECT  2.4 70.595 2.712 73.765 ;
     RECT  4.464 70.451 6.36 73.765 ;
     RECT  85.728 69.251 87.144 73.765 ;
     RECT  7.8 71.315 8.232 73.813 ;
     RECT  13.2 73.571 14.136 74.005 ;
     RECT  29.4 72.755 29.712 74.053 ;
     RECT  88.8 73.477 92.088 74.099 ;
     RECT  69.744 73.091 70.212 74.101 ;
     RECT  9.696 69.011 11.256 74.293 ;
     RECT  15.216 72.467 20.04 74.485 ;
     RECT  21.3 72.899 21.612 74.485 ;
     RECT  42.288 72.565 46.056 74.579 ;
     RECT  13.2 74.005 14.232 74.581 ;
     RECT  15.216 74.485 21.612 74.581 ;
     RECT  29.04 74.053 29.712 74.581 ;
     RECT  85.728 73.765 87.24 74.627 ;
     RECT  13.2 74.581 21.612 74.629 ;
     RECT  50.736 71.987 51.312 74.629 ;
     RECT  52.608 73.763 57.048 74.629 ;
     RECT  74.448 73.619 76.488 74.629 ;
     RECT  77.472 73.619 84.504 74.629 ;
     RECT  9.696 74.293 11.352 74.675 ;
     RECT  50.736 74.629 57.048 74.723 ;
     RECT  74.448 74.629 84.504 74.723 ;
     RECT  74.448 74.723 81.24 74.867 ;
     RECT  50.784 74.723 57.048 74.915 ;
     RECT  78 74.867 81.24 74.915 ;
     RECT  12.768 74.629 21.612 74.917 ;
     RECT  12.768 74.917 22.2 74.963 ;
     RECT  37.5 72.901 38.952 74.965 ;
     RECT  40.2 73.477 41.064 74.965 ;
     RECT  44.688 74.579 46.056 75.011 ;
     RECT  50.784 74.915 54.84 75.059 ;
     RECT  37.5 74.965 41.064 75.107 ;
     RECT  29.04 74.581 30.072 75.155 ;
     RECT  29.4 75.155 30.072 75.157 ;
     RECT  31.104 72.755 36.12 75.157 ;
     RECT  69.696 74.101 70.212 75.157 ;
     RECT  85.776 74.627 87.24 75.253 ;
     RECT  39.456 75.107 41.064 75.301 ;
     RECT  42.288 74.579 43.656 75.301 ;
     RECT  58.032 73.763 62.376 75.491 ;
     RECT  29.4 75.157 36.12 75.685 ;
     RECT  82.56 74.723 84.504 75.733 ;
     RECT  29.4 75.685 36.312 75.779 ;
     RECT  64.32 73.621 67.512 75.779 ;
     RECT  56.4 74.915 57.048 75.781 ;
     RECT  58.032 75.491 62.232 75.781 ;
     RECT  25.632 72.995 27.012 75.829 ;
     RECT  2.4 73.765 6.36 75.875 ;
     RECT  31.008 75.779 36.312 75.875 ;
     RECT  56.4 75.781 62.232 75.875 ;
     RECT  82.56 75.733 84.744 75.875 ;
     RECT  50.784 75.059 54.744 75.925 ;
     RECT  74.448 74.867 76.536 76.019 ;
     RECT  50.736 75.925 54.744 76.067 ;
     RECT  50.784 76.067 54.744 76.069 ;
     RECT  56.4 75.875 57.624 76.069 ;
     RECT  12.768 74.963 20.04 76.115 ;
     RECT  23.808 72.995 24.312 76.213 ;
     RECT  25.536 75.829 27.012 76.213 ;
     RECT  75.3 76.019 76.536 76.213 ;
     RECT  78 74.915 81.144 76.213 ;
     RECT  71.616 72.899 73.368 76.309 ;
     RECT  23.808 76.213 27.012 76.357 ;
     RECT  85.776 75.253 87.72 76.357 ;
     RECT  88.8 74.099 91.812 76.357 ;
     RECT  85.776 76.357 92.328 76.403 ;
     RECT  7.68 73.813 8.232 76.453 ;
     RECT  2.4 75.875 5.412 76.837 ;
     RECT  39.456 75.301 43.656 76.883 ;
     RECT  9.936 74.675 11.256 76.885 ;
     RECT  23.808 76.357 27.384 76.885 ;
     RECT  64.5 75.779 67.512 76.885 ;
     RECT  82.56 75.875 84.504 76.933 ;
     RECT  85.776 76.403 87.24 76.933 ;
     RECT  82.56 76.933 87.24 76.979 ;
     RECT  69.12 75.157 70.212 77.027 ;
     RECT  23.424 76.885 27.384 77.075 ;
     RECT  2.4 76.837 5.544 77.125 ;
     RECT  29.4 75.779 29.832 77.125 ;
     RECT  58.608 75.875 62.232 77.317 ;
     RECT  39.456 76.883 40.512 77.365 ;
     RECT  71.616 76.309 73.416 77.365 ;
     RECT  13.008 76.115 20.04 77.461 ;
     RECT  9.648 76.885 11.256 77.555 ;
     RECT  50.784 76.069 57.624 77.555 ;
     RECT  75.3 76.213 81.144 77.555 ;
     RECT  77.904 77.555 81.144 77.557 ;
     RECT  7.584 76.453 8.232 77.603 ;
     RECT  42.288 76.883 43.656 77.603 ;
     RECT  23.424 77.075 27.012 77.699 ;
     RECT  88.368 76.403 92.328 77.701 ;
     RECT  23.424 77.699 24.312 77.749 ;
     RECT  88.224 77.701 92.328 77.797 ;
     RECT  12.72 77.461 20.04 77.843 ;
     RECT  39.36 77.365 40.512 77.843 ;
     RECT  12.72 77.843 13.848 77.941 ;
     RECT  64.5 76.885 68.088 77.941 ;
     RECT  71.616 77.365 73.464 78.133 ;
     RECT  47.664 72.755 49.752 78.323 ;
     RECT  2.4 77.125 5.832 78.371 ;
     RECT  23.376 77.749 24.312 78.373 ;
     RECT  50.784 77.555 57.384 78.373 ;
     RECT  31.104 75.875 36.312 78.469 ;
     RECT  37.5 75.107 38.232 78.469 ;
     RECT  25.344 77.699 27.012 78.613 ;
     RECT  42.288 77.603 43.56 78.613 ;
     RECT  84.864 76.979 87.24 78.613 ;
     RECT  88.224 77.797 92.424 78.613 ;
     RECT  14.976 77.843 20.04 78.659 ;
     RECT  21.072 74.963 22.2 78.661 ;
     RECT  23.328 78.373 24.312 78.661 ;
     RECT  31.104 78.469 38.232 78.661 ;
     RECT  58.608 77.317 62.664 78.661 ;
     RECT  69.744 77.027 70.212 78.661 ;
     RECT  12.576 77.941 13.848 78.707 ;
     RECT  21.072 78.661 24.312 78.707 ;
     RECT  50.64 78.373 57.384 78.707 ;
     RECT  21.3 78.707 24.312 78.709 ;
     RECT  25.344 78.613 27.912 78.709 ;
     RECT  31.104 78.661 38.328 78.709 ;
     RECT  7.584 77.603 8.112 78.755 ;
     RECT  50.64 78.707 54.744 78.755 ;
     RECT  77.904 77.557 81.288 78.899 ;
     RECT  9.936 77.555 11.256 78.947 ;
     RECT  84.864 78.613 92.424 78.947 ;
     RECT  53.424 78.755 54.744 78.995 ;
     RECT  50.64 78.755 52.248 79.043 ;
     RECT  41.76 78.613 43.56 79.045 ;
     RECT  44.736 75.011 46.056 79.045 ;
     RECT  2.4 78.371 5.544 79.235 ;
     RECT  21.3 78.709 27.912 79.235 ;
     RECT  64.5 77.941 68.376 79.235 ;
     RECT  69.648 78.661 70.212 79.237 ;
     RECT  71.616 78.133 74.088 79.237 ;
     RECT  7.68 78.755 8.112 79.283 ;
     RECT  69.648 79.237 74.088 79.379 ;
     RECT  15.168 78.659 20.04 79.717 ;
     RECT  21.3 79.235 27.012 79.717 ;
     RECT  29.28 77.125 29.832 79.717 ;
     RECT  30.816 78.709 38.328 79.717 ;
     RECT  56.4 78.707 57.384 79.765 ;
     RECT  58.464 78.661 62.664 79.765 ;
     RECT  82.56 76.979 83.712 79.765 ;
     RECT  84.864 78.947 87.72 79.765 ;
     RECT  15.168 79.717 27.012 79.909 ;
     RECT  40.2 77.843 40.512 79.957 ;
     RECT  53.472 78.995 54.744 80.051 ;
     RECT  7.8 79.283 8.112 80.053 ;
     RECT  29.28 79.717 38.328 80.099 ;
     RECT  39.888 79.957 40.512 80.291 ;
     RECT  7.8 80.053 8.232 80.293 ;
     RECT  10.5 78.947 11.256 80.341 ;
     RECT  39.984 80.291 40.512 80.341 ;
     RECT  41.76 79.045 46.056 80.341 ;
     RECT  47.664 78.323 49.368 80.341 ;
     RECT  88.8 78.947 92.424 80.341 ;
     RECT  29.4 80.099 38.328 80.387 ;
     RECT  14.832 79.909 27.012 80.435 ;
     RECT  50.64 79.043 51.864 80.435 ;
     RECT  21.072 80.435 27.012 80.579 ;
     RECT  56.4 79.765 62.664 80.627 ;
     RECT  71.664 79.379 74.088 80.629 ;
     RECT  58.368 80.627 62.664 80.773 ;
     RECT  39.984 80.341 46.056 80.819 ;
     RECT  7.44 80.293 8.232 80.965 ;
     RECT  12.576 78.707 13.608 81.011 ;
     RECT  39.984 80.819 43.752 81.059 ;
     RECT  82.56 79.765 87.72 81.059 ;
     RECT  2.4 79.235 5.412 81.107 ;
     RECT  88.8 80.341 92.904 81.251 ;
     RECT  64.5 79.235 68.136 81.347 ;
     RECT  29.4 80.387 29.832 81.349 ;
     RECT  30.816 80.387 38.328 81.349 ;
     RECT  88.8 81.251 92.28 81.349 ;
     RECT  88.704 81.349 92.28 81.395 ;
     RECT  47.568 80.341 49.368 81.397 ;
     RECT  50.64 80.435 51.312 81.397 ;
     RECT  12.624 81.011 13.608 81.445 ;
     RECT  7.44 80.965 9 81.491 ;
     RECT  71.28 80.629 74.088 81.491 ;
     RECT  7.8 81.491 9 81.539 ;
     RECT  21.072 80.579 22.776 81.539 ;
     RECT  88.704 81.395 90.12 81.539 ;
     RECT  77.904 78.899 81.144 81.637 ;
     RECT  82.56 81.059 86.904 81.637 ;
     RECT  58.368 80.773 63.192 81.731 ;
     RECT  69.648 79.379 70.212 81.731 ;
     RECT  10.32 80.341 11.256 81.875 ;
     RECT  29.4 81.349 38.328 81.875 ;
     RECT  53.568 80.051 54.744 81.877 ;
     RECT  71.568 81.491 74.088 81.877 ;
     RECT  75.3 77.555 76.92 81.877 ;
     RECT  44.736 80.819 46.056 81.925 ;
     RECT  77.904 81.637 86.904 81.971 ;
     RECT  39.984 81.059 43.212 82.021 ;
     RECT  44.256 81.925 46.056 82.021 ;
     RECT  58.368 81.731 62.112 82.067 ;
     RECT  47.568 81.397 51.312 82.211 ;
     RECT  14.832 80.435 20.04 82.259 ;
     RECT  91.392 81.395 92.28 82.357 ;
     RECT  90.576 82.357 92.28 82.451 ;
     RECT  90.576 82.451 91.812 82.499 ;
     RECT  71.568 81.877 76.92 82.501 ;
     RECT  78 81.971 86.904 82.547 ;
     RECT  23.808 80.579 27.012 82.597 ;
     RECT  64.5 81.347 64.812 82.597 ;
     RECT  21.072 81.539 21.612 82.645 ;
     RECT  22.752 81.539 22.776 82.645 ;
     RECT  21.072 82.645 22.776 82.691 ;
     RECT  50.496 82.211 51.312 82.691 ;
     RECT  71.568 82.501 76.968 82.691 ;
     RECT  58.368 82.067 60.648 82.739 ;
     RECT  88.704 81.539 89.352 82.739 ;
     RECT  63.12 81.731 63.192 82.789 ;
     RECT  64.368 82.597 64.812 82.789 ;
     RECT  59.1 82.739 60.648 82.835 ;
     RECT  17.472 82.259 20.04 83.029 ;
     RECT  21.072 82.691 22.296 83.029 ;
     RECT  69.744 81.731 70.212 83.029 ;
     RECT  71.664 82.691 76.968 83.029 ;
     RECT  78 82.547 78.504 83.029 ;
     RECT  61.68 82.067 62.112 83.075 ;
     RECT  39.984 82.021 46.056 83.077 ;
     RECT  63.12 82.789 64.812 83.173 ;
     RECT  65.808 81.347 68.136 83.173 ;
     RECT  17.472 83.029 22.296 83.219 ;
     RECT  23.808 82.597 27.672 83.267 ;
     RECT  53.136 81.877 54.744 83.267 ;
     RECT  63.12 83.173 68.136 83.267 ;
     RECT  29.4 81.875 36.12 83.317 ;
     RECT  37.5 81.875 38.328 83.317 ;
     RECT  79.824 82.547 86.904 83.411 ;
     RECT  61.8 83.075 62.112 83.557 ;
     RECT  63.12 83.267 63.144 83.557 ;
     RECT  39.648 83.077 46.056 83.605 ;
     RECT  56.4 80.627 57.384 83.605 ;
     RECT  79.824 83.411 83.712 83.605 ;
     RECT  10.5 81.875 11.256 83.653 ;
     RECT  64.368 83.267 68.136 83.653 ;
     RECT  69.744 83.029 70.584 83.653 ;
     RECT  14.832 82.259 16.392 83.749 ;
     RECT  17.472 83.219 19.224 83.749 ;
     RECT  50.64 82.691 51.312 83.749 ;
     RECT  64.368 83.653 70.584 83.843 ;
     RECT  71.664 83.029 78.504 83.891 ;
     RECT  39.648 83.605 46.584 84.179 ;
     RECT  50.592 83.749 51.312 84.179 ;
     RECT  66.144 83.843 70.584 84.227 ;
     RECT  61.8 83.557 63.144 84.323 ;
     RECT  9.936 83.653 11.256 84.325 ;
     RECT  12.624 81.445 13.656 84.325 ;
     RECT  23.808 83.267 27.012 84.325 ;
     RECT  91.392 82.499 91.812 84.325 ;
     RECT  29.4 83.317 38.328 84.419 ;
     RECT  56.4 83.605 57.96 84.419 ;
     RECT  84.816 83.411 86.904 84.419 ;
     RECT  53.568 83.267 54.744 84.517 ;
     RECT  56.4 84.419 57 84.517 ;
     RECT  2.4 81.107 3.624 84.611 ;
     RECT  66.144 84.227 70.344 84.611 ;
     RECT  4.656 81.107 5.412 84.805 ;
     RECT  64.368 83.843 64.812 84.851 ;
     RECT  71.808 83.891 78.504 84.899 ;
     RECT  88.8 82.739 89.352 84.901 ;
     RECT  20.592 83.219 22.296 84.947 ;
     RECT  31.344 84.419 38.328 84.947 ;
     RECT  77.328 84.899 78.504 84.949 ;
     RECT  53.568 84.517 57 85.091 ;
     RECT  91.392 84.325 92.616 85.091 ;
     RECT  77.328 84.949 78.552 85.093 ;
     RECT  79.632 83.605 83.712 85.093 ;
     RECT  23.808 84.325 27.96 85.187 ;
     RECT  23.808 85.187 24.504 85.381 ;
     RECT  64.5 84.851 64.812 85.381 ;
     RECT  66.144 84.611 68.568 85.381 ;
     RECT  84.816 84.419 86.568 85.381 ;
     RECT  39.84 84.179 46.584 85.427 ;
     RECT  59.1 82.835 60.216 85.429 ;
     RECT  14.832 83.749 19.224 85.477 ;
     RECT  21.12 84.947 22.296 85.523 ;
     RECT  39.84 85.427 41.928 85.523 ;
     RECT  42.9 85.427 46.584 85.523 ;
     RECT  64.5 85.381 68.568 85.523 ;
     RECT  77.328 85.093 83.712 85.523 ;
     RECT  25.632 85.187 27.96 85.573 ;
     RECT  25.632 85.573 28.056 85.619 ;
     RECT  81.984 85.523 83.712 85.619 ;
     RECT  52.416 84.901 52.44 85.667 ;
     RECT  68.544 85.523 68.568 85.667 ;
     RECT  14.832 85.477 19.608 85.717 ;
     RECT  61.8 84.323 62.856 85.765 ;
     RECT  84.816 85.381 86.664 85.813 ;
     RECT  31.344 84.947 38.232 86.005 ;
     RECT  71.808 84.899 74.088 86.051 ;
     RECT  53.568 85.091 54.792 86.053 ;
     RECT  91.392 85.091 92.472 86.053 ;
     RECT  47.568 82.211 49.368 86.099 ;
     RECT  61.632 85.765 62.856 86.099 ;
     RECT  58.176 85.429 60.216 86.195 ;
     RECT  69.648 84.611 70.344 86.197 ;
     RECT  53.568 86.053 55.368 86.485 ;
     RECT  77.328 85.523 81.012 86.531 ;
     RECT  21.12 85.523 21.912 86.533 ;
     RECT  23.616 85.381 24.504 86.533 ;
     RECT  56.4 85.091 57 86.533 ;
     RECT  84.816 85.813 87.192 86.579 ;
     RECT  9.36 84.325 13.656 86.581 ;
     RECT  14.832 85.717 19.944 86.581 ;
     RECT  21.12 86.533 24.504 86.581 ;
     RECT  40.032 85.523 41.928 86.581 ;
     RECT  42.9 85.523 46.008 86.581 ;
     RECT  9.264 86.581 13.656 86.627 ;
     RECT  28.032 85.619 28.056 86.675 ;
     RECT  80.352 86.531 81.012 86.675 ;
     RECT  31.344 86.005 38.76 86.723 ;
     RECT  84.816 86.579 86.664 86.771 ;
     RECT  88.56 84.901 89.352 86.771 ;
     RECT  14.832 86.581 24.504 86.819 ;
     RECT  25.632 85.619 27.012 86.819 ;
     RECT  40.032 86.581 46.008 86.821 ;
     RECT  18.48 86.819 24.504 86.867 ;
     RECT  82.56 85.619 83.712 86.917 ;
     RECT  84.816 86.771 86.412 86.917 ;
     RECT  47.664 86.099 49.368 87.109 ;
     RECT  4.656 84.805 5.544 87.157 ;
     RECT  68.928 86.197 70.344 87.251 ;
     RECT  91.2 86.053 92.472 87.251 ;
     RECT  7.8 81.539 8.232 87.253 ;
     RECT  40.032 86.821 46.488 87.253 ;
     RECT  47.52 87.109 49.368 87.253 ;
     RECT  31.344 86.723 38.232 87.299 ;
     RECT  14.832 86.819 17.064 87.347 ;
     RECT  91.392 87.251 92.472 87.347 ;
     RECT  4.656 87.157 6.216 87.349 ;
     RECT  88.56 86.771 89.112 87.443 ;
     RECT  40.032 87.253 49.368 87.541 ;
     RECT  56.4 86.533 57.192 87.541 ;
     RECT  58.656 86.195 60.216 87.541 ;
     RECT  71.904 86.051 74.088 87.541 ;
     RECT  75.072 84.899 76.248 87.541 ;
     RECT  39.696 87.541 49.368 87.587 ;
     RECT  52.896 86.485 55.368 87.587 ;
     RECT  29.4 84.419 30.36 87.589 ;
     RECT  31.344 87.299 36.12 87.589 ;
     RECT  52.896 87.587 54.12 87.683 ;
     RECT  64.5 85.523 67.512 87.827 ;
     RECT  9.264 86.627 13.512 87.875 ;
     RECT  42.9 87.587 49.368 87.877 ;
     RECT  4.656 87.349 6.312 87.923 ;
     RECT  42.9 87.877 49.416 87.923 ;
     RECT  64.5 87.827 64.812 87.925 ;
     RECT  42.9 87.923 43.656 87.971 ;
     RECT  18.48 86.867 19.608 88.069 ;
     RECT  20.64 86.867 24.504 88.069 ;
     RECT  9.264 87.875 11.256 88.115 ;
     RECT  18.48 88.069 24.504 88.115 ;
     RECT  39.696 87.587 41.496 88.115 ;
     RECT  44.736 87.923 49.416 88.115 ;
     RECT  68.928 87.251 70.212 88.115 ;
     RECT  2.4 84.611 3.48 88.213 ;
     RECT  4.656 87.923 6.216 88.213 ;
     RECT  27.984 86.773 28.008 88.213 ;
     RECT  29.4 87.589 36.12 88.213 ;
     RECT  21.3 88.115 24.504 88.309 ;
     RECT  25.968 86.819 27.012 88.309 ;
     RECT  66.144 87.827 67.512 88.309 ;
     RECT  21.3 88.309 27.012 88.357 ;
     RECT  27.984 88.213 36.12 88.357 ;
     RECT  2.4 88.213 6.216 88.403 ;
     RECT  21.3 88.357 36.12 88.403 ;
     RECT  77.328 86.531 79.32 88.451 ;
     RECT  88.8 87.443 89.112 88.501 ;
     RECT  56.4 87.541 60.216 88.691 ;
     RECT  82.56 86.917 86.412 88.693 ;
     RECT  71.904 87.541 76.248 88.739 ;
     RECT  18.48 88.115 19.896 88.741 ;
     RECT  53.568 87.683 54.12 88.741 ;
     RECT  55.152 87.587 55.368 88.741 ;
     RECT  81.984 88.693 86.412 88.741 ;
     RECT  7.8 87.253 8.28 88.787 ;
     RECT  56.4 88.691 56.808 88.787 ;
     RECT  57.936 88.691 60.216 88.787 ;
     RECT  61.632 86.099 62.472 88.789 ;
     RECT  3.792 88.403 6.216 88.885 ;
     RECT  50.64 84.179 51.312 88.885 ;
     RECT  7.8 88.787 8.232 88.979 ;
     RECT  9.36 88.115 11.256 88.979 ;
     RECT  47.328 88.115 49.416 88.979 ;
     RECT  66.144 88.309 68.424 88.979 ;
     RECT  71.952 88.739 76.248 88.979 ;
     RECT  37.5 87.299 38.232 89.029 ;
     RECT  72.288 88.979 76.248 89.029 ;
     RECT  77.328 88.451 78.6 89.029 ;
     RECT  47.328 88.979 49.368 89.171 ;
     RECT  61.632 88.789 63.096 89.269 ;
     RECT  64.368 87.925 64.812 89.269 ;
     RECT  50.544 88.885 51.312 89.315 ;
     RECT  61.632 89.269 64.812 89.315 ;
     RECT  24 88.403 36.12 89.365 ;
     RECT  37.104 89.029 38.232 89.365 ;
     RECT  12.48 87.875 13.512 89.413 ;
     RECT  14.832 87.347 16.392 89.413 ;
     RECT  72.288 89.029 78.6 89.413 ;
     RECT  40.08 88.115 41.496 89.461 ;
     RECT  53.568 88.741 55.368 89.461 ;
     RECT  56.4 88.787 56.712 89.461 ;
     RECT  61.632 89.315 62.472 89.461 ;
     RECT  63.84 89.315 64.812 89.461 ;
     RECT  12.48 89.413 16.392 89.507 ;
     RECT  39.888 89.461 41.496 89.507 ;
     RECT  80.4 86.675 81.012 89.507 ;
     RECT  18.24 88.741 19.896 89.509 ;
     RECT  3.792 88.885 6.408 89.555 ;
     RECT  4.656 89.555 6.408 89.699 ;
     RECT  81.984 88.741 86.52 89.747 ;
     RECT  6.384 89.699 6.408 89.749 ;
     RECT  4.656 89.699 5.412 89.891 ;
     RECT  6.384 89.749 6.648 89.939 ;
     RECT  63.84 89.461 64.92 89.989 ;
     RECT  42.9 87.971 43.212 90.037 ;
     RECT  72.288 89.413 79.224 90.037 ;
     RECT  17.664 89.509 19.896 90.083 ;
     RECT  39.888 89.507 40.512 90.083 ;
     RECT  53.568 89.461 56.712 90.083 ;
     RECT  63.84 89.989 64.968 90.083 ;
     RECT  91.392 87.347 91.812 90.083 ;
     RECT  59.1 88.787 60.216 90.131 ;
     RECT  66.384 88.979 68.424 90.229 ;
     RECT  69.648 88.115 70.212 90.229 ;
     RECT  17.664 90.083 19.608 90.275 ;
     RECT  24 89.365 38.232 90.275 ;
     RECT  66.384 90.229 70.212 90.275 ;
     RECT  82.56 89.747 86.52 90.275 ;
     RECT  21.3 88.403 22.728 90.323 ;
     RECT  24 90.275 36.12 90.469 ;
     RECT  6.624 89.939 6.648 90.563 ;
     RECT  68.784 90.275 70.212 90.659 ;
     RECT  37.104 90.275 38.232 90.707 ;
     RECT  69.648 90.659 70.212 90.899 ;
     RECT  71.232 90.037 79.224 91.043 ;
     RECT  9.936 88.979 11.256 91.141 ;
     RECT  12.72 89.507 16.392 91.141 ;
     RECT  55.152 90.083 56.712 91.141 ;
     RECT  61.536 89.461 62.472 91.187 ;
     RECT  48.3 89.171 49.368 91.189 ;
     RECT  80.7 89.507 81.012 91.189 ;
     RECT  9.936 91.141 16.392 91.283 ;
     RECT  44.736 88.115 46.056 91.333 ;
     RECT  53.7 90.083 54.12 91.333 ;
     RECT  9.936 91.283 14.664 91.379 ;
     RECT  53.568 91.333 54.12 91.379 ;
     RECT  64.5 90.083 64.968 91.379 ;
     RECT  59.1 90.131 60.12 91.381 ;
     RECT  57.936 88.787 57.96 91.429 ;
     RECT  59.1 91.381 60.168 91.429 ;
     RECT  55.104 91.141 56.712 91.477 ;
     RECT  57.936 91.429 60.168 91.477 ;
     RECT  48.3 91.189 49.56 91.525 ;
     RECT  50.736 89.315 51.312 91.525 ;
     RECT  23.76 90.469 36.12 91.571 ;
     RECT  82.56 90.275 86.412 91.571 ;
     RECT  85.44 91.571 86.412 91.573 ;
     RECT  71.232 91.043 78.984 91.619 ;
     RECT  15.9 91.283 16.392 91.717 ;
     RECT  10.272 91.379 14.664 91.811 ;
     RECT  52.464 90.565 52.488 91.811 ;
     RECT  21.3 90.323 22.344 91.859 ;
     RECT  26.016 91.571 36.12 91.907 ;
     RECT  44.736 91.333 46.152 91.907 ;
     RECT  28.416 91.907 36.12 91.955 ;
     RECT  61.632 91.187 62.472 91.957 ;
     RECT  55.104 91.477 60.168 92.003 ;
     RECT  82.56 91.571 84.456 92.003 ;
     RECT  42.192 90.037 43.212 92.099 ;
     RECT  80.7 91.189 81.528 92.101 ;
     RECT  23.76 91.571 24.84 92.195 ;
     RECT  72 91.619 78.984 92.195 ;
     RECT  85.44 91.573 86.568 92.195 ;
     RECT  48.3 91.525 51.312 92.245 ;
     RECT  57.936 92.003 60.168 92.245 ;
     RECT  61.632 91.957 62.664 92.245 ;
     RECT  74.4 92.195 78.984 92.245 ;
     RECT  80.7 92.101 81.816 92.245 ;
     RECT  64.5 91.379 64.92 92.291 ;
     RECT  69.9 90.899 70.212 92.293 ;
     RECT  17.952 90.275 19.608 92.387 ;
     RECT  72 92.195 73.368 92.435 ;
     RECT  74.4 92.245 81.816 92.435 ;
     RECT  88.08 88.501 89.112 92.435 ;
     RECT  53.568 91.379 54.012 92.483 ;
     RECT  72.24 92.435 73.368 92.531 ;
     RECT  42.9 92.099 43.212 92.677 ;
     RECT  40.2 90.083 40.512 92.869 ;
     RECT  57.936 92.245 62.664 92.869 ;
     RECT  64.5 92.291 64.812 92.869 ;
     RECT  23.904 92.195 24.84 92.915 ;
     RECT  42.9 92.677 43.32 92.917 ;
     RECT  48.192 92.245 51.312 92.917 ;
     RECT  15.9 91.717 16.536 92.963 ;
     RECT  66.384 90.275 67.512 92.963 ;
     RECT  68.928 92.293 70.212 92.963 ;
     RECT  72.432 92.531 73.368 92.963 ;
     RECT  85.44 92.195 86.412 92.963 ;
     RECT  48.192 92.917 51.912 93.011 ;
     RECT  57.936 92.869 64.812 93.011 ;
     RECT  40.2 92.869 41.208 93.013 ;
     RECT  53.7 92.483 54.012 93.013 ;
     RECT  55.104 92.003 56.712 93.013 ;
     RECT  42.9 92.917 43.512 93.059 ;
     RECT  82.848 92.003 84.456 93.061 ;
     RECT  37.5 90.707 38.232 93.107 ;
     RECT  45.6 91.907 46.152 93.107 ;
     RECT  26.016 91.907 27.144 93.203 ;
     RECT  82.848 93.061 84.936 93.251 ;
     RECT  26.112 93.203 27.144 93.253 ;
     RECT  72.432 92.963 72.912 93.299 ;
     RECT  83.4 93.251 84.936 93.299 ;
     RECT  15.9 92.963 16.392 93.347 ;
     RECT  53.7 93.013 56.712 93.349 ;
     RECT  57.936 93.011 60.168 93.349 ;
     RECT  10.272 91.811 14.232 93.445 ;
     RECT  15.9 93.347 16.212 93.445 ;
     RECT  39.312 93.013 41.208 93.491 ;
     RECT  23.904 92.915 24.312 93.539 ;
     RECT  28.416 91.955 29.712 93.539 ;
     RECT  30.816 91.955 36.12 93.539 ;
     RECT  37.5 93.107 37.944 93.539 ;
     RECT  48.3 93.011 51.912 93.539 ;
     RECT  51 93.539 51.912 93.635 ;
     RECT  21.3 91.859 22.248 93.731 ;
     RECT  30.816 93.539 35.208 93.779 ;
     RECT  39.312 93.491 40.512 93.779 ;
     RECT  61.632 93.011 64.812 93.877 ;
     RECT  29.4 93.539 29.712 93.973 ;
     RECT  74.4 92.435 78.984 94.021 ;
     RECT  61.632 93.877 64.968 94.067 ;
     RECT  53.7 93.349 60.168 94.115 ;
     RECT  10.272 93.445 16.212 94.163 ;
     RECT  26.112 93.253 27.384 94.259 ;
     RECT  48.3 93.539 49.56 94.403 ;
     RECT  86.1 92.963 86.412 94.501 ;
     RECT  26.7 94.259 27.384 94.549 ;
     RECT  61.632 94.067 62.112 94.549 ;
     RECT  63.6 94.067 64.968 94.595 ;
     RECT  45.6 93.107 46.008 94.597 ;
     RECT  18.6 92.387 19.608 94.643 ;
     RECT  42.9 93.059 43.32 94.643 ;
     RECT  64.5 94.595 64.968 94.643 ;
     RECT  74.016 94.021 78.984 94.643 ;
     RECT  80.352 92.435 81.816 94.643 ;
     RECT  86.1 94.501 86.664 94.643 ;
     RECT  26.7 94.549 27.912 94.691 ;
     RECT  61.008 94.549 62.112 94.691 ;
     RECT  80.7 94.643 81.816 94.691 ;
     RECT  84.912 93.299 84.936 94.691 ;
     RECT  45.6 94.597 46.68 94.739 ;
     RECT  29.4 93.973 30.552 94.981 ;
     RECT  31.536 93.779 35.112 94.981 ;
     RECT  72.6 93.299 72.912 94.981 ;
     RECT  74.016 94.643 78.312 94.981 ;
     RECT  2.4 88.403 2.712 95.049 ;
     RECT  5.1 89.891 5.412 95.049 ;
     RECT  7.8 88.979 8.112 95.049 ;
     RECT  10.368 94.163 16.212 95.049 ;
     RECT  18.6 94.643 18.912 95.049 ;
     RECT  21.3 93.731 21.612 95.049 ;
     RECT  24 93.539 24.312 95.049 ;
     RECT  26.7 94.691 27.012 95.049 ;
     RECT  29.4 94.981 35.112 95.049 ;
     RECT  37.5 93.539 37.812 95.049 ;
     RECT  40.2 93.779 40.512 95.049 ;
     RECT  42.9 94.643 43.212 95.049 ;
     RECT  45.6 94.739 45.912 95.049 ;
     RECT  48.3 94.403 48.612 95.049 ;
     RECT  51 93.635 51.312 95.049 ;
     RECT  53.7 94.115 59.412 95.049 ;
     RECT  61.8 94.691 62.112 95.049 ;
     RECT  64.5 94.643 64.812 95.049 ;
     RECT  67.2 92.963 67.512 95.049 ;
     RECT  69.9 92.963 70.212 95.049 ;
     RECT  72.6 94.981 78.312 95.049 ;
     RECT  80.7 94.691 81.012 95.049 ;
     RECT  83.4 93.299 83.712 95.049 ;
     RECT  86.1 94.643 86.412 95.049 ;
     RECT  88.8 92.435 89.112 95.049 ;
     RECT  91.5 90.083 91.812 95.049 ;
     RECT  94.2 58.691 94.512 95.049 ;
     RECT  2.4 95.049 2.52 95.063 ;
     RECT  5.1 95.049 5.22 95.063 ;
     RECT  7.8 95.049 7.92 95.063 ;
     RECT  10.368 95.049 16.02 95.063 ;
     RECT  18.6 95.049 18.72 95.063 ;
     RECT  21.3 95.049 21.42 95.063 ;
     RECT  24 95.049 24.12 95.063 ;
     RECT  26.7 95.049 26.82 95.063 ;
     RECT  29.4 95.049 34.92 95.063 ;
     RECT  37.5 95.049 37.62 95.063 ;
     RECT  40.2 95.049 40.32 95.063 ;
     RECT  42.9 95.049 43.02 95.063 ;
     RECT  45.6 95.049 45.72 95.063 ;
     RECT  48.3 95.049 48.42 95.063 ;
     RECT  51 95.049 51.12 95.063 ;
     RECT  53.7 95.049 59.22 95.063 ;
     RECT  61.8 95.049 61.92 95.063 ;
     RECT  64.5 95.049 64.62 95.063 ;
     RECT  67.2 95.049 67.32 95.063 ;
     RECT  69.9 95.049 70.02 95.063 ;
     RECT  72.6 95.049 78.12 95.063 ;
     RECT  80.7 95.049 80.82 95.063 ;
     RECT  83.4 95.049 83.52 95.063 ;
     RECT  86.1 95.049 86.22 95.063 ;
     RECT  88.8 95.049 88.92 95.063 ;
     RECT  91.5 95.049 91.62 95.063 ;
     RECT  94.2 95.049 94.32 95.063 ;
     RECT  10.368 95.063 15.576 96.325 ;
     RECT  30.096 95.063 34.008 96.325 ;
     RECT  54 95.063 58.344 96.325 ;
     RECT  29.664 96.325 34.008 97.045 ;
     RECT  73.44 95.063 77.784 97.045 ;
     RECT  10.368 96.325 15.72 97.091 ;
     RECT  10.656 97.091 15.72 97.116 ;
     RECT  10.68 97.116 10.8 97.168 ;
     RECT  10.824 97.116 10.944 97.168 ;
     RECT  10.968 97.116 11.088 97.168 ;
     RECT  11.112 97.116 11.232 97.168 ;
     RECT  11.256 97.116 11.376 97.168 ;
     RECT  11.4 97.116 11.52 97.168 ;
     RECT  11.544 97.116 11.664 97.168 ;
     RECT  11.688 97.116 11.808 97.168 ;
     RECT  11.832 97.116 11.952 97.168 ;
     RECT  11.976 97.116 12.096 97.168 ;
     RECT  12.12 97.116 12.24 97.168 ;
     RECT  12.264 97.116 12.384 97.168 ;
     RECT  12.408 97.116 12.528 97.168 ;
     RECT  12.552 97.116 12.672 97.168 ;
     RECT  12.696 97.116 12.816 97.168 ;
     RECT  12.84 97.116 12.96 97.168 ;
     RECT  12.984 97.116 13.104 97.168 ;
     RECT  13.128 97.116 13.248 97.168 ;
     RECT  13.272 97.116 13.392 97.168 ;
     RECT  13.416 97.116 13.536 97.168 ;
     RECT  13.56 97.116 13.68 97.168 ;
     RECT  13.704 97.116 13.824 97.168 ;
     RECT  13.848 97.116 13.968 97.168 ;
     RECT  13.992 97.116 14.112 97.168 ;
     RECT  14.136 97.116 14.256 97.168 ;
     RECT  14.28 97.116 14.4 97.168 ;
     RECT  14.424 97.116 14.544 97.168 ;
     RECT  14.568 97.116 14.688 97.168 ;
     RECT  14.712 97.116 14.832 97.168 ;
     RECT  14.856 97.116 14.976 97.168 ;
     RECT  15 97.116 15.12 97.168 ;
     RECT  15.144 97.116 15.264 97.168 ;
     RECT  15.288 97.116 15.408 97.168 ;
     RECT  15.432 97.116 15.552 97.168 ;
     RECT  15.576 97.116 15.696 97.168 ;
     RECT  29.664 97.045 34.152 97.116 ;
     RECT  29.688 97.116 29.808 97.168 ;
     RECT  29.832 97.116 29.952 97.168 ;
     RECT  29.976 97.116 30.096 97.168 ;
     RECT  30.12 97.116 30.24 97.168 ;
     RECT  30.264 97.116 30.384 97.168 ;
     RECT  30.408 97.116 30.528 97.168 ;
     RECT  30.552 97.116 30.672 97.168 ;
     RECT  30.696 97.116 30.816 97.168 ;
     RECT  30.84 97.116 30.96 97.168 ;
     RECT  30.984 97.116 31.104 97.168 ;
     RECT  31.128 97.116 31.248 97.168 ;
     RECT  31.272 97.116 31.392 97.168 ;
     RECT  31.416 97.116 31.536 97.168 ;
     RECT  31.56 97.116 31.68 97.168 ;
     RECT  31.704 97.116 31.824 97.168 ;
     RECT  31.848 97.116 31.968 97.168 ;
     RECT  31.992 97.116 32.112 97.168 ;
     RECT  32.136 97.116 32.256 97.168 ;
     RECT  32.28 97.116 32.4 97.168 ;
     RECT  32.424 97.116 32.544 97.168 ;
     RECT  32.568 97.116 32.688 97.168 ;
     RECT  32.712 97.116 32.832 97.168 ;
     RECT  32.856 97.116 32.976 97.168 ;
     RECT  33 97.116 33.12 97.168 ;
     RECT  33.144 97.116 33.264 97.168 ;
     RECT  33.288 97.116 33.408 97.168 ;
     RECT  33.432 97.116 33.552 97.168 ;
     RECT  33.576 97.116 33.696 97.168 ;
     RECT  33.72 97.116 33.84 97.168 ;
     RECT  33.864 97.116 33.984 97.168 ;
     RECT  34.008 97.116 34.128 97.168 ;
     RECT  53.856 96.325 58.344 97.116 ;
     RECT  53.88 97.116 54 97.168 ;
     RECT  54.024 97.116 54.144 97.168 ;
     RECT  54.168 97.116 54.288 97.168 ;
     RECT  54.312 97.116 54.432 97.168 ;
     RECT  54.456 97.116 54.576 97.168 ;
     RECT  54.6 97.116 54.72 97.168 ;
     RECT  54.744 97.116 54.864 97.168 ;
     RECT  54.888 97.116 55.008 97.168 ;
     RECT  55.032 97.116 55.152 97.168 ;
     RECT  55.176 97.116 55.296 97.168 ;
     RECT  55.32 97.116 55.44 97.168 ;
     RECT  55.464 97.116 55.584 97.168 ;
     RECT  55.608 97.116 55.728 97.168 ;
     RECT  55.752 97.116 55.872 97.168 ;
     RECT  55.896 97.116 56.016 97.168 ;
     RECT  56.04 97.116 56.16 97.168 ;
     RECT  56.184 97.116 56.304 97.168 ;
     RECT  56.328 97.116 56.448 97.168 ;
     RECT  56.472 97.116 56.592 97.168 ;
     RECT  56.616 97.116 56.736 97.168 ;
     RECT  56.76 97.116 56.88 97.168 ;
     RECT  56.904 97.116 57.024 97.168 ;
     RECT  57.048 97.116 57.168 97.168 ;
     RECT  57.192 97.116 57.312 97.168 ;
     RECT  57.336 97.116 57.456 97.168 ;
     RECT  57.48 97.116 57.6 97.168 ;
     RECT  57.624 97.116 57.744 97.168 ;
     RECT  57.768 97.116 57.888 97.168 ;
     RECT  57.912 97.116 58.032 97.168 ;
     RECT  58.056 97.116 58.176 97.168 ;
     RECT  58.2 97.116 58.32 97.168 ;
     RECT  73.44 97.045 77.928 97.116 ;
     RECT  73.464 97.116 73.584 97.168 ;
     RECT  73.608 97.116 73.728 97.168 ;
     RECT  73.752 97.116 73.872 97.168 ;
     RECT  73.896 97.116 74.016 97.168 ;
     RECT  74.04 97.116 74.16 97.168 ;
     RECT  74.184 97.116 74.304 97.168 ;
     RECT  74.328 97.116 74.448 97.168 ;
     RECT  74.472 97.116 74.592 97.168 ;
     RECT  74.616 97.116 74.736 97.168 ;
     RECT  74.76 97.116 74.88 97.168 ;
     RECT  74.904 97.116 75.024 97.168 ;
     RECT  75.048 97.116 75.168 97.168 ;
     RECT  75.192 97.116 75.312 97.168 ;
     RECT  75.336 97.116 75.456 97.168 ;
     RECT  75.48 97.116 75.6 97.168 ;
     RECT  75.624 97.116 75.744 97.168 ;
     RECT  75.768 97.116 75.888 97.168 ;
     RECT  75.912 97.116 76.032 97.168 ;
     RECT  76.056 97.116 76.176 97.168 ;
     RECT  76.2 97.116 76.32 97.168 ;
     RECT  76.344 97.116 76.464 97.168 ;
     RECT  76.488 97.116 76.608 97.168 ;
     RECT  76.632 97.116 76.752 97.168 ;
     RECT  76.776 97.116 76.896 97.168 ;
     RECT  76.92 97.116 77.04 97.168 ;
     RECT  77.064 97.116 77.184 97.168 ;
     RECT  77.208 97.116 77.328 97.168 ;
     RECT  77.352 97.116 77.472 97.168 ;
     RECT  77.496 97.116 77.616 97.168 ;
     RECT  77.64 97.116 77.76 97.168 ;
     RECT  77.784 97.116 77.904 97.168 ;
     RECT  68.472 2.581 69.9 3.301 ;
     RECT  70.344 2.821 71.376 3.155 ;
     RECT  32.412 3.157 33.744 5.747 ;
     RECT  33.768 3.157 34.8 5.653 ;
     RECT  68.472 3.301 69.792 3.923 ;
     RECT  35.688 3.781 36.96 4.883 ;
     RECT  68.376 3.923 69.792 4.787 ;
     RECT  57.576 3.925 59.1 5.747 ;
     RECT  83.712 3.925 85.152 4.499 ;
     RECT  78.312 4.213 79.632 5.171 ;
     RECT  79.656 4.259 80.7 5.171 ;
     RECT  76.056 4.261 77.568 6.803 ;
     RECT  83.712 4.499 85.344 5.077 ;
     RECT  48.612 4.501 49.728 5.461 ;
     RECT  49.752 4.501 51 5.507 ;
     RECT  46.344 4.547 46.488 5.605 ;
     RECT  59.412 4.741 60.912 5.605 ;
     RECT  68.376 4.787 69.9 5.363 ;
     RECT  40.512 4.979 41.064 6.277 ;
     RECT  81.144 4.979 81.336 5.653 ;
     RECT  83.928 5.077 85.344 5.219 ;
     RECT  86.568 5.077 87.888 6.229 ;
     RECT  72.912 5.219 73.032 6.229 ;
     RECT  83.88 5.219 85.344 8.485 ;
     RECT  50.88 5.507 51 6.277 ;
     RECT  21.612 5.605 22.8 6.323 ;
     RECT  22.824 5.605 24 6.323 ;
     RECT  59.412 5.605 60.72 6.323 ;
     RECT  81.144 5.653 82.128 6.181 ;
     RECT  82.152 5.653 83.4 6.805 ;
     RECT  32.412 5.747 33.888 9.779 ;
     RECT  65.016 5.795 65.496 6.323 ;
     RECT  18.912 5.845 20.256 7.189 ;
     RECT  20.28 5.845 21.3 6.805 ;
     RECT  51.312 6.085 52.704 9.827 ;
     RECT  52.728 6.085 53.7 8.485 ;
     RECT  55.272 6.085 56.4 6.229 ;
     RECT  10.812 6.133 12.336 7.813 ;
     RECT  43.212 6.229 44.448 7.331 ;
     RECT  44.472 6.229 45.6 7.331 ;
     RECT  88.656 6.275 88.8 7.381 ;
     RECT  21.612 6.323 22.344 6.805 ;
     RECT  59.412 6.323 60.912 6.901 ;
     RECT  64.812 6.323 65.496 7.141 ;
     RECT  55.176 6.611 56.208 8.437 ;
     RECT  8.112 6.805 9.552 8.195 ;
     RECT  70.212 6.805 71.52 8.291 ;
     RECT  59.88 6.901 60.912 8.195 ;
     RECT  46.488 7.141 47.76 8.243 ;
     RECT  64.812 7.141 66.24 8.245 ;
     RECT  18.912 7.189 20.208 8.003 ;
     RECT  50.88 7.379 51 7.957 ;
     RECT  75.912 7.427 76.056 8.773 ;
     RECT  89.4 7.717 90.672 12.325 ;
     RECT  11.4 7.859 13.2 9.061 ;
     RECT  49.56 7.957 51 8.965 ;
     RECT  59.88 8.195 61.248 9.059 ;
     RECT  65.256 8.245 66.24 9.155 ;
     RECT  70.212 8.291 72.048 9.013 ;
     RECT  68.328 8.389 69.792 8.485 ;
     RECT  68.328 8.485 69.552 9.061 ;
     RECT  83.88 8.485 85.056 9.109 ;
     RECT  79.128 8.533 80.496 9.013 ;
     RECT  75.912 8.773 77.328 12.277 ;
     RECT  38.808 8.869 40.2 11.365 ;
     RECT  49.56 8.965 50.88 10.261 ;
     RECT  70.968 9.013 72.048 10.883 ;
     RECT  79.368 9.013 80.496 11.365 ;
     RECT  59.88 9.059 61.344 9.493 ;
     RECT  68.328 9.061 69.504 10.693 ;
     RECT  83.88 9.109 84.912 9.251 ;
     RECT  41.064 9.155 41.16 9.637 ;
     RECT  65.256 9.155 67.2 10.117 ;
     RECT  83.832 9.251 84.912 9.877 ;
     RECT  59.976 9.493 61.344 10.117 ;
     RECT  27.012 9.541 28.08 10.595 ;
     RECT  28.104 9.541 29.232 10.595 ;
     RECT  41.064 9.637 42.24 11.171 ;
     RECT  37.812 9.875 38.784 11.459 ;
     RECT  83.832 9.877 84.816 10.789 ;
     RECT  87.432 9.923 88.656 11.171 ;
     RECT  6.264 10.021 7.68 10.307 ;
     RECT  59.976 10.117 61.152 10.213 ;
     RECT  65.688 10.117 67.2 11.941 ;
     RECT  59.976 10.213 61.104 12.325 ;
     RECT  55.176 10.307 56.4 15.973 ;
     RECT  72.912 10.355 73.032 11.797 ;
     RECT  45.912 10.501 46.992 10.643 ;
     RECT  47.016 10.501 48.3 10.597 ;
     RECT  27.012 10.595 27.48 11.221 ;
     RECT  47.304 10.597 48.3 11.269 ;
     RECT  20.88 10.643 21.3 11.845 ;
     RECT  45.912 10.643 47.28 12.469 ;
     RECT  8.112 10.789 9.36 11.459 ;
     RECT  9.384 10.789 10.5 11.459 ;
     RECT  10.812 10.883 12.336 11.987 ;
     RECT  70.536 10.883 72.048 13.139 ;
     RECT  48.612 10.979 50.112 12.035 ;
     RECT  87.24 11.171 88.656 11.459 ;
     RECT  35.112 11.317 36.432 14.341 ;
     RECT  36.456 11.317 37.5 17.413 ;
     RECT  44.976 11.363 45.6 11.845 ;
     RECT  38.808 11.365 39.888 11.459 ;
     RECT  51.96 11.365 52.992 11.459 ;
     RECT  10.128 11.459 10.5 11.653 ;
     RECT  51.96 11.459 53.184 11.987 ;
     RECT  79.608 11.459 80.7 14.099 ;
     RECT  73.56 11.797 74.688 13.235 ;
     RECT  43.212 11.845 44.304 13.187 ;
     RECT  44.328 11.845 45.6 13.187 ;
     RECT  10.812 11.987 11.448 13.045 ;
     RECT  78.312 12.083 79.584 14.053 ;
     RECT  62.112 12.277 63.456 13.139 ;
     RECT  75.96 12.277 77.328 13.331 ;
     RECT  89.544 12.325 90.672 12.515 ;
     RECT  59.412 12.371 60.672 13.811 ;
     RECT  45.912 12.469 47.136 16.837 ;
     RECT  83.928 12.515 85.056 13.717 ;
     RECT  47.16 12.611 48.192 13.859 ;
     RECT  19.704 12.709 20.736 13.715 ;
     RECT  13.656 13.045 14.832 13.091 ;
     RECT  14.856 13.045 15.9 13.429 ;
     RECT  13.512 13.091 14.832 15.301 ;
     RECT  70.212 13.139 72.048 14.341 ;
     RECT  73.56 13.235 74.784 13.715 ;
     RECT  75.96 13.331 77.424 14.867 ;
     RECT  14.904 13.429 15.9 13.907 ;
     RECT  68.616 13.715 69.9 14.773 ;
     RECT  47.16 13.859 48.3 17.029 ;
     RECT  14.856 13.907 15.9 19.525 ;
     RECT  21.612 13.909 23.088 14.725 ;
     RECT  78.408 14.053 79.584 14.099 ;
     RECT  78.408 14.099 78.696 14.485 ;
     RECT  10.128 14.291 10.5 15.349 ;
     RECT  35.256 14.341 36.432 14.773 ;
     RECT  70.824 14.341 72.048 14.773 ;
     RECT  51.312 14.485 52.368 14.533 ;
     RECT  21.72 14.725 23.088 15.347 ;
     RECT  35.256 14.773 36.384 16.117 ;
     RECT  70.968 14.773 72.048 15.827 ;
     RECT  83.712 14.867 85.056 16.597 ;
     RECT  27.144 14.917 28.656 15.539 ;
     RECT  13.512 15.301 14.784 15.349 ;
     RECT  16.584 15.301 17.664 15.443 ;
     RECT  19.704 15.301 21.168 15.491 ;
     RECT  5.412 15.443 5.832 16.501 ;
     RECT  16.212 15.443 17.664 17.699 ;
     RECT  18.912 15.491 21.168 15.925 ;
     RECT  27.012 15.539 28.656 16.549 ;
     RECT  70.968 15.827 72.336 16.019 ;
     RECT  87 15.923 88.08 18.133 ;
     RECT  18.912 15.925 20.256 19.525 ;
     RECT  55.272 15.973 56.4 17.459 ;
     RECT  68.616 16.019 69.9 17.077 ;
     RECT  70.824 16.019 72.336 16.835 ;
     RECT  2.712 16.117 4.224 17.075 ;
     RECT  24.504 16.357 25.872 17.699 ;
     RECT  5.412 16.501 6.816 17.171 ;
     RECT  75.612 16.595 75.816 17.797 ;
     RECT  83.712 16.597 84.96 17.605 ;
     RECT  70.824 16.835 72.48 17.125 ;
     RECT  45.912 16.837 46.944 17.029 ;
     RECT  47.304 17.029 48.3 18.275 ;
     RECT  35.352 17.075 36.432 18.037 ;
     RECT  68.616 17.077 69.792 17.413 ;
     RECT  71.16 17.125 72.48 17.315 ;
     RECT  71.16 17.315 72.6 17.987 ;
     RECT  36.504 17.413 37.5 17.699 ;
     RECT  68.76 17.413 69.792 17.555 ;
     RECT  78.312 17.413 79.296 20.675 ;
     RECT  79.32 17.413 80.592 17.605 ;
     RECT  27.96 17.459 28.992 18.851 ;
     RECT  55.176 17.459 56.4 18.803 ;
     RECT  68.664 17.555 69.792 18.757 ;
     RECT  48.612 17.605 50.112 18.275 ;
     RECT  79.416 17.605 80.592 17.651 ;
     RECT  31.968 17.651 32.1 18.997 ;
     RECT  74.784 17.651 74.832 19.045 ;
     RECT  79.416 17.651 80.7 19.045 ;
     RECT  16.212 17.699 16.584 18.757 ;
     RECT  24.504 17.699 25.92 18.277 ;
     RECT  36.456 17.699 37.5 18.083 ;
     RECT  40.08 17.699 40.2 18.805 ;
     RECT  75.612 17.797 76.752 18.851 ;
     RECT  76.776 17.797 77.76 18.805 ;
     RECT  51.864 17.939 53.184 20.485 ;
     RECT  36.168 18.083 37.5 19.765 ;
     RECT  46.968 18.275 48.3 20.339 ;
     RECT  48.612 18.275 48.744 18.997 ;
     RECT  24.6 18.277 25.92 28.595 ;
     RECT  22.104 18.517 23.232 18.563 ;
     RECT  59.544 18.517 60.768 19.957 ;
     RECT  68.664 18.757 69.696 19.475 ;
     RECT  54.984 18.803 56.4 19.909 ;
     RECT  65.448 18.803 66.432 21.349 ;
     RECT  38.136 18.805 39.168 19.523 ;
     RECT  39.192 18.805 40.2 19.523 ;
     RECT  27.96 18.851 29.4 21.109 ;
     RECT  42.096 18.851 42.9 20.101 ;
     RECT  75.612 18.851 76.848 18.995 ;
     RECT  84.12 18.899 85.488 21.155 ;
     RECT  86.568 19.091 87.888 19.811 ;
     RECT  50.448 19.235 50.784 20.581 ;
     RECT  67.656 19.475 68.64 20.677 ;
     RECT  68.664 19.475 69.9 21.731 ;
     RECT  38.136 19.523 38.184 20.581 ;
     RECT  39.888 19.523 40.2 20.485 ;
     RECT  19.176 19.525 20.256 22.835 ;
     RECT  79.512 19.763 80.7 20.917 ;
     RECT  36.216 19.765 37.5 23.125 ;
     RECT  13.512 19.859 14.784 21.541 ;
     RECT  5.976 19.861 7.44 21.779 ;
     RECT  54.984 19.909 56.112 20.051 ;
     RECT  56.712 19.909 58.128 20.819 ;
     RECT  89.112 19.909 90.576 22.165 ;
     RECT  54.984 20.051 56.4 20.627 ;
     RECT  40.512 20.101 42 21.637 ;
     RECT  43.32 20.485 44.352 21.301 ;
     RECT  44.376 20.485 45.6 21.013 ;
     RECT  81.96 20.579 83.4 23.557 ;
     RECT  29.712 20.581 30.96 22.835 ;
     RECT  30.984 20.581 31.968 21.877 ;
     RECT  48.792 20.581 50.256 21.731 ;
     RECT  10.368 20.627 10.5 21.637 ;
     RECT  54.888 20.627 56.4 21.299 ;
     RECT  78.312 20.675 79.488 22.693 ;
     RECT  32.412 20.677 33.84 22.499 ;
     RECT  71.16 20.725 72.6 21.491 ;
     RECT  86.52 20.915 86.568 22.261 ;
     RECT  28.248 21.109 29.4 23.125 ;
     RECT  21.612 21.157 22.8 21.347 ;
     RECT  22.824 21.157 24 21.347 ;
     RECT  13.512 21.541 14.544 33.109 ;
     RECT  41.016 21.637 42 22.165 ;
     RECT  44.136 21.731 45.504 23.027 ;
     RECT  48.792 21.731 50.304 22.549 ;
     RECT  68.376 21.731 69.9 22.739 ;
     RECT  59.544 22.115 60.576 23.701 ;
     RECT  79.512 22.211 80.7 22.835 ;
     RECT  13.104 22.307 13.2 23.317 ;
     RECT  32.412 22.499 34.8 22.981 ;
     RECT  89.544 22.499 90.576 23.363 ;
     RECT  48.888 22.549 50.304 23.411 ;
     RECT  78.408 22.693 79.488 22.835 ;
     RECT  51.912 22.787 53.184 23.603 ;
     RECT  29.712 22.835 31.824 23.845 ;
     RECT  32.412 22.981 33.648 24.083 ;
     RECT  33.672 22.981 34.8 24.083 ;
     RECT  44.136 23.027 45.6 23.315 ;
     RECT  36.312 23.125 37.5 23.317 ;
     RECT  62.112 23.317 63.552 27.635 ;
     RECT  27.384 23.363 28.464 23.411 ;
     RECT  89.112 23.363 90.576 23.699 ;
     RECT  27.012 23.411 28.464 24.757 ;
     RECT  81.96 23.557 83.28 25.235 ;
     RECT  51.432 23.603 53.184 23.941 ;
     RECT  89.112 23.699 91.5 24.469 ;
     RECT  37.812 23.701 38.784 24.901 ;
     RECT  38.808 23.701 40.2 24.947 ;
     RECT  29.712 23.845 30.816 25.283 ;
     RECT  30.84 23.845 31.824 25.283 ;
     RECT  51.432 23.941 52.704 24.563 ;
     RECT  32.412 24.083 32.76 25.045 ;
     RECT  8.568 24.469 10.032 25.091 ;
     RECT  90.072 24.469 91.5 25.091 ;
     RECT  12.672 24.563 13.2 25.573 ;
     RECT  51.312 24.563 52.704 25.141 ;
     RECT  47.856 24.659 48.3 25.621 ;
     RECT  65.352 24.659 66.384 25.715 ;
     RECT  27.48 24.757 28.464 25.091 ;
     RECT  36.312 24.947 37.5 27.877 ;
     RECT  67.608 25.043 67.656 26.197 ;
     RECT  51.312 25.141 52.608 25.283 ;
     RECT  59.832 25.235 60.816 26.533 ;
     RECT  81.96 25.235 83.4 28.261 ;
     RECT  51.312 25.283 52.704 25.331 ;
     RECT  40.632 25.475 41.616 26.819 ;
     RECT  46.776 25.621 48.3 26.291 ;
     RECT  48.612 25.715 48.888 26.629 ;
     RECT  65.352 25.715 66.432 26.099 ;
     RECT  70.968 25.717 72.48 27.589 ;
     RECT  65.256 26.099 66.432 27.685 ;
     RECT  68.376 26.197 69.792 26.819 ;
     RECT  37.812 26.579 38.376 27.301 ;
     RECT  48.612 26.629 49.584 27.203 ;
     RECT  49.608 26.629 50.784 27.157 ;
     RECT  16.488 26.725 17.664 28.741 ;
     RECT  40.632 26.819 41.952 27.347 ;
     RECT  68.376 26.819 69.9 27.299 ;
     RECT  83.832 26.869 85.2 29.459 ;
     RECT  35.208 27.011 36.24 30.085 ;
     RECT  32.76 27.013 33.936 28.163 ;
     RECT  48.612 27.203 49.872 31.717 ;
     RECT  37.812 27.301 38.832 28.453 ;
     RECT  38.856 27.301 40.2 28.309 ;
     RECT  40.512 27.347 41.952 28.837 ;
     RECT  29.712 27.349 30.768 27.877 ;
     RECT  30.792 27.349 32.1 28.451 ;
     RECT  76.248 27.395 76.392 28.645 ;
     RECT  78.696 27.587 78.792 28.645 ;
     RECT  70.968 27.589 72.144 28.501 ;
     RECT  43.212 27.635 43.32 29.029 ;
     RECT  72.912 27.637 74.4 28.405 ;
     RECT  8.112 27.923 8.232 28.933 ;
     RECT  81.96 28.261 83.088 29.075 ;
     RECT  51.312 28.453 52.752 29.363 ;
     RECT  38.76 28.499 39.744 29.123 ;
     RECT  70.968 28.501 72.048 29.747 ;
     RECT  76.248 28.645 77.52 30.467 ;
     RECT  57.288 28.693 58.608 31.525 ;
     RECT  16.584 28.741 17.664 28.931 ;
     RECT  16.584 28.931 18.6 29.701 ;
     RECT  40.512 29.027 41.952 30.373 ;
     RECT  21.912 29.029 23.376 30.035 ;
     RECT  43.212 29.029 44.304 36.565 ;
     RECT  44.328 29.029 45.312 31.427 ;
     RECT  81.96 29.075 83.28 30.853 ;
     RECT  18.912 29.219 19.176 29.221 ;
     RECT  29.232 29.219 29.4 29.365 ;
     RECT  59.412 29.219 60.432 30.661 ;
     RECT  18.912 29.221 19.92 31.091 ;
     RECT  19.944 29.221 21.3 31.091 ;
     RECT  73.896 29.363 75.3 31.765 ;
     RECT  27.96 29.365 29.4 30.323 ;
     RECT  83.712 29.459 85.2 29.557 ;
     RECT  83.712 29.557 84.96 33.541 ;
     RECT  89.112 29.605 90.096 32.437 ;
     RECT  90.12 29.605 91.5 32.723 ;
     RECT  36.312 29.651 37.5 30.661 ;
     RECT  17.16 29.701 18.6 31.763 ;
     RECT  70.968 29.747 72.144 31.379 ;
     RECT  12.072 29.941 13.2 30.325 ;
     RECT  21.912 30.035 23.424 30.899 ;
     RECT  35.256 30.085 36.24 30.181 ;
     RECT  24.6 30.181 25.68 34.643 ;
     RECT  25.704 30.181 26.7 34.643 ;
     RECT  32.412 30.181 33.696 30.851 ;
     RECT  33.72 30.181 34.8 30.851 ;
     RECT  91.812 30.181 93.024 30.851 ;
     RECT  93.048 30.181 94.2 30.851 ;
     RECT  10.812 30.275 12.048 32.245 ;
     RECT  54.012 30.275 54.12 30.853 ;
     RECT  12.072 30.325 13.104 30.803 ;
     RECT  40.512 30.373 41.568 33.397 ;
     RECT  79.128 30.421 80.592 31.235 ;
     RECT  76.248 30.467 78 30.613 ;
     RECT  76.488 30.613 78 31.189 ;
     RECT  29.928 30.661 31.392 31.763 ;
     RECT  12.072 30.803 13.2 32.771 ;
     RECT  32.412 30.851 34.8 31.237 ;
     RECT  35.256 30.851 36.24 32.723 ;
     RECT  91.812 30.851 94.2 31.525 ;
     RECT  54.012 30.853 55.056 31.907 ;
     RECT  55.08 30.853 56.256 31.907 ;
     RECT  81.96 30.853 83.184 32.437 ;
     RECT  62.712 30.997 64.08 31.187 ;
     RECT  18.912 31.091 19.128 32.437 ;
     RECT  62.52 31.187 64.08 32.485 ;
     RECT  76.776 31.189 78 31.813 ;
     RECT  79.128 31.235 80.7 31.909 ;
     RECT  32.412 31.237 33.84 32.197 ;
     RECT  44.328 31.427 45.6 37.573 ;
     RECT  37.944 31.475 38.184 31.477 ;
     RECT  37.944 31.477 39.264 32.437 ;
     RECT  46.008 31.477 47.088 31.955 ;
     RECT  47.112 31.477 48.3 32.437 ;
     RECT  51.312 31.525 52.704 33.397 ;
     RECT  92.136 31.525 94.2 31.861 ;
     RECT  36.312 31.619 37.392 32.531 ;
     RECT  48.744 31.717 49.872 32.389 ;
     RECT  18.48 31.763 18.6 33.013 ;
     RECT  74.232 31.765 75.3 33.013 ;
     RECT  92.136 31.861 93.168 32.389 ;
     RECT  93.192 31.861 94.2 34.259 ;
     RECT  54.012 31.907 56.256 32.725 ;
     RECT  79.224 31.909 80.7 34.213 ;
     RECT  45.912 31.955 47.088 33.589 ;
     RECT  10.812 32.245 11.952 35.845 ;
     RECT  47.112 32.437 48.096 37.573 ;
     RECT  86.412 32.437 87.552 33.539 ;
     RECT  87.576 32.437 88.8 33.539 ;
     RECT  57.288 32.483 58.608 34.741 ;
     RECT  62.52 32.485 63.936 32.917 ;
     RECT  36.312 32.531 37.5 34.165 ;
     RECT  35.208 32.723 36.24 35.797 ;
     RECT  89.688 32.723 89.784 33.781 ;
     RECT  54.012 32.725 55.152 33.107 ;
     RECT  55.176 32.725 56.256 32.869 ;
     RECT  5.412 32.771 6.912 34.453 ;
     RECT  11.976 32.771 13.2 34.117 ;
     RECT  55.272 32.869 56.256 35.459 ;
     RECT  62.616 32.917 63.936 32.965 ;
     RECT  27.912 32.965 29.4 34.883 ;
     RECT  62.616 32.965 63.84 33.587 ;
     RECT  76.776 33.059 78 36.563 ;
     RECT  31.392 33.107 32.1 34.069 ;
     RECT  54.012 33.107 55.248 35.459 ;
     RECT  72.912 33.107 74.208 33.443 ;
     RECT  51.312 33.397 52.56 34.835 ;
     RECT  83.832 33.541 84.96 34.595 ;
     RECT  62.616 33.587 63.936 34.741 ;
     RECT  45.912 33.589 46.944 35.221 ;
     RECT  38.856 33.827 40.08 34.355 ;
     RECT  30.696 34.069 32.1 34.741 ;
     RECT  67.608 34.165 69.024 35.797 ;
     RECT  79.272 34.213 80.7 34.787 ;
     RECT  92.472 34.259 94.2 35.269 ;
     RECT  38.04 34.355 38.184 35.605 ;
     RECT  48.612 34.355 49.872 36.997 ;
     RECT  83.712 34.595 84.96 39.923 ;
     RECT  30.792 34.741 32.1 34.883 ;
     RECT  62.616 34.741 63.84 36.035 ;
     RECT  79.224 34.787 80.7 35.363 ;
     RECT  30.6 34.883 32.1 36.419 ;
     RECT  12.024 35.267 13.104 35.795 ;
     RECT  33.528 35.269 34.8 36.323 ;
     RECT  70.968 35.269 72.336 37.955 ;
     RECT  93.144 35.269 94.2 36.131 ;
     RECT  78.984 35.363 80.7 35.797 ;
     RECT  56.256 35.747 56.4 37.093 ;
     RECT  11.976 35.795 13.104 35.939 ;
     RECT  35.256 35.797 36.24 36.277 ;
     RECT  78.984 35.797 79.968 36.997 ;
     RECT  11.976 35.939 13.2 39.589 ;
     RECT  62.616 36.035 64.08 38.485 ;
     RECT  36.312 36.083 37.5 40.165 ;
     RECT  92.472 36.131 94.2 36.563 ;
     RECT  68.376 36.275 69.9 38.677 ;
     RECT  32.952 36.323 34.8 36.853 ;
     RECT  19.128 36.373 20.544 37.667 ;
     RECT  59.544 36.515 60.864 37.573 ;
     RECT  76.632 36.563 78 38.725 ;
     RECT  91.812 36.563 94.2 36.997 ;
     RECT  43.212 36.565 44.256 39.301 ;
     RECT  90.072 36.565 91.5 37.429 ;
     RECT  32.952 36.853 34.704 37.573 ;
     RECT  57.576 36.899 58.656 39.539 ;
     RECT  86.412 36.997 87.744 38.099 ;
     RECT  87.768 36.997 88.8 38.099 ;
     RECT  91.812 36.997 93.648 37.669 ;
     RECT  54.792 37.141 55.824 37.429 ;
     RECT  10.968 37.331 11.952 38.435 ;
     RECT  90.072 37.429 91.2 37.859 ;
     RECT  16.488 37.573 17.952 38.773 ;
     RECT  33.72 37.573 34.704 39.013 ;
     RECT  44.328 37.573 45.456 41.221 ;
     RECT  59.832 37.573 60.864 37.907 ;
     RECT  19.128 37.667 21.12 38.101 ;
     RECT  92.136 37.669 93.648 38.435 ;
     RECT  90.072 37.859 91.5 39.301 ;
     RECT  59.544 37.907 60.864 39.253 ;
     RECT  70.968 37.955 72.48 39.875 ;
     RECT  72.912 37.957 74.208 39.253 ;
     RECT  74.232 37.957 75.3 38.149 ;
     RECT  29.712 38.005 30.912 38.963 ;
     RECT  30.936 38.005 32.1 38.963 ;
     RECT  19.608 38.101 21.12 40.595 ;
     RECT  10.812 38.435 11.952 40.883 ;
     RECT  38.04 38.483 38.184 39.589 ;
     RECT  62.712 38.485 64.08 38.819 ;
     RECT  27.24 38.725 28.656 39.589 ;
     RECT  76.632 38.725 77.904 39.395 ;
     RECT  35.112 38.771 36.096 39.635 ;
     RECT  41.88 38.819 42.9 40.357 ;
     RECT  81.576 38.819 82.608 39.877 ;
     RECT  29.712 38.963 32.1 39.877 ;
     RECT  47.16 38.963 48.3 41.221 ;
     RECT  54.012 39.011 55.488 41.413 ;
     RECT  53.568 39.203 53.7 39.253 ;
     RECT  3.336 39.251 3.432 40.309 ;
     RECT  17.352 39.251 18.6 44.149 ;
     RECT  52.728 39.253 53.7 40.165 ;
     RECT  59.88 39.253 60.864 39.923 ;
     RECT  72.912 39.253 74.112 39.301 ;
     RECT  51.312 39.539 52.368 41.267 ;
     RECT  57.576 39.539 59.1 40.405 ;
     RECT  27.24 39.589 28.56 40.451 ;
     RECT  35.112 39.635 36.24 40.597 ;
     RECT  67.608 39.779 69.024 40.355 ;
     RECT  89.112 39.875 90.432 41.845 ;
     RECT  29.712 39.877 31.968 39.925 ;
     RECT  59.544 39.923 60.864 40.499 ;
     RECT  83.712 39.923 85.008 44.339 ;
     RECT  30.696 39.925 31.968 41.555 ;
     RECT  36.456 40.165 37.5 40.741 ;
     RECT  3.336 40.309 4.464 40.837 ;
     RECT  67.512 40.355 69.024 41.411 ;
     RECT  57.624 40.405 59.1 40.597 ;
     RECT  59.544 40.499 61.008 41.171 ;
     RECT  38.184 40.549 39.36 40.835 ;
     RECT  35.112 40.597 36.192 40.837 ;
     RECT  57.96 40.597 59.1 40.933 ;
     RECT  38.088 40.835 39.36 44.387 ;
     RECT  35.112 40.837 36.096 48.757 ;
     RECT  10.812 40.883 12.096 42.997 ;
     RECT  41.112 41.171 42.144 41.891 ;
     RECT  51.312 41.267 52.704 43.813 ;
     RECT  63.84 41.411 64.08 42.181 ;
     RECT  69.456 41.411 69.792 42.757 ;
     RECT  54.012 41.413 55.344 41.603 ;
     RECT  47.16 41.459 48.3 44.147 ;
     RECT  57.624 41.507 59.1 44.149 ;
     RECT  31.344 41.555 31.968 42.709 ;
     RECT  54.012 41.603 55.488 42.613 ;
     RECT  14.808 41.651 15.9 42.613 ;
     RECT  89.112 41.845 90.24 44.437 ;
     RECT  63 42.181 64.08 43.571 ;
     RECT  22.248 42.277 23.376 42.995 ;
     RECT  14.808 42.613 15.792 43.907 ;
     RECT  54.012 42.613 55.44 42.997 ;
     RECT  36.456 42.803 37.5 45.731 ;
     RECT  10.812 42.997 12 44.195 ;
     RECT  54.012 42.997 55.296 44.053 ;
     RECT  72.912 43.043 74.112 43.427 ;
     RECT  12.168 43.379 13.2 44.483 ;
     RECT  72.912 43.427 74.304 43.667 ;
     RECT  63 43.571 64.5 44.675 ;
     RECT  13.512 43.667 14.544 47.939 ;
     RECT  51.312 43.813 52.608 43.909 ;
     RECT  76.92 43.813 78 44.053 ;
     RECT  26.208 43.859 26.544 45.013 ;
     RECT  14.808 43.907 15.9 45.637 ;
     RECT  51.312 43.909 52.512 46.261 ;
     RECT  3.336 43.955 4.512 45.923 ;
     RECT  54.12 44.053 55.296 44.195 ;
     RECT  77.016 44.053 78 44.531 ;
     RECT  52.728 44.099 53.7 45.205 ;
     RECT  47.112 44.147 48.3 45.877 ;
     RECT  17.352 44.149 18.48 46.357 ;
     RECT  10.812 44.195 12.096 45.731 ;
     RECT  54.012 44.195 55.296 44.437 ;
     RECT  27.012 44.197 28.464 46.211 ;
     RECT  86.808 44.341 87.792 44.483 ;
     RECT  87.816 44.341 88.8 49.525 ;
     RECT  81.528 44.387 82.608 46.547 ;
     RECT  54.012 44.437 55.2 45.829 ;
     RECT  89.256 44.437 90.24 45.203 ;
     RECT  12.12 44.483 13.2 44.917 ;
     RECT  86.616 44.483 87.792 46.547 ;
     RECT  76.968 44.531 78 46.355 ;
     RECT  59.412 44.725 60.432 46.211 ;
     RECT  29.832 44.869 31.344 46.547 ;
     RECT  57.576 44.915 59.1 46.837 ;
     RECT  79.224 44.915 80.7 46.211 ;
     RECT  12.12 44.917 13.104 45.731 ;
     RECT  25.128 45.013 26.544 45.155 ;
     RECT  24.312 45.155 24.6 46.405 ;
     RECT  89.256 45.203 90.288 46.213 ;
     RECT  43.32 45.299 44.304 48.277 ;
     RECT  65.4 45.635 66.432 46.115 ;
     RECT  36.216 45.731 37.5 46.259 ;
     RECT  60.456 45.731 61.584 46.211 ;
     RECT  3.336 45.923 4.752 46.787 ;
     RECT  65.208 46.115 66.432 46.787 ;
     RECT  92.712 46.165 94.08 47.221 ;
     RECT  59.412 46.211 61.584 47.317 ;
     RECT  36.12 46.259 37.5 47.077 ;
     RECT  19.224 46.261 20.688 46.595 ;
     RECT  76.632 46.355 78 46.787 ;
     RECT  24.408 46.405 24.6 46.501 ;
     RECT  68.328 46.501 69.792 47.701 ;
     RECT  29.712 46.547 31.344 47.845 ;
     RECT  81.012 46.547 82.608 46.789 ;
     RECT  86.412 46.547 87.792 49.571 ;
     RECT  70.968 46.549 72.48 49.525 ;
     RECT  19.224 46.595 21.3 47.317 ;
     RECT  38.28 46.693 39.504 47.557 ;
     RECT  16.488 46.787 17.856 49.619 ;
     RECT  65.208 46.787 66.48 50.101 ;
     RECT  76.296 46.787 78 47.653 ;
     RECT  81.012 46.789 82.128 47.845 ;
     RECT  57.576 46.837 58.704 47.125 ;
     RECT  90.36 47.027 91.392 47.363 ;
     RECT  36.12 47.077 37.2 48.229 ;
     RECT  57.624 47.125 58.704 48.133 ;
     RECT  92.904 47.221 94.08 47.939 ;
     RECT  91.812 47.267 92.88 47.939 ;
     RECT  19.224 47.317 20.304 48.899 ;
     RECT  20.328 47.317 21.3 48.899 ;
     RECT  59.412 47.317 60.384 48.421 ;
     RECT  60.408 47.317 61.584 47.363 ;
     RECT  51.312 47.363 52.512 49.763 ;
     RECT  60.408 47.363 61.632 48.515 ;
     RECT  90.36 47.363 91.5 47.939 ;
     RECT  38.28 47.557 39.408 48.275 ;
     RECT  83.712 47.651 84.96 48.899 ;
     RECT  76.296 47.653 77.424 49.523 ;
     RECT  68.424 47.701 69.792 47.891 ;
     RECT  29.712 47.845 31.056 47.941 ;
     RECT  68.424 47.891 69.9 47.941 ;
     RECT  89.208 47.891 90.288 49.573 ;
     RECT  13.512 47.939 14.784 55.093 ;
     RECT  90.312 47.939 91.5 49.619 ;
     RECT  68.76 47.941 69.9 48.707 ;
     RECT  67.704 47.987 68.688 50.389 ;
     RECT  54.012 48.083 54.216 49.525 ;
     RECT  38.28 48.275 39.504 51.397 ;
     RECT  5.592 48.421 6.816 49.429 ;
     RECT  79.224 48.421 80.7 50.291 ;
     RECT  30.264 48.515 31.344 52.453 ;
     RECT  60.12 48.515 61.632 48.709 ;
     RECT  81.384 48.515 82.608 49.861 ;
     RECT  68.712 48.707 69.9 49.909 ;
     RECT  60.12 48.709 61.584 48.755 ;
     RECT  58.056 48.803 59.1 49.861 ;
     RECT  36.12 49.091 37.104 49.859 ;
     RECT  11.976 49.381 13.2 49.525 ;
     RECT  76.296 49.523 77.76 51.443 ;
     RECT  54.012 49.525 55.248 52.261 ;
     RECT  55.272 49.525 56.4 52.453 ;
     RECT  62.328 49.525 63.744 50.821 ;
     RECT  11.256 49.571 12.528 51.299 ;
     RECT  86.412 49.571 87.984 50.677 ;
     RECT  6.312 49.619 7.8 50.917 ;
     RECT  89.832 49.619 91.5 50.725 ;
     RECT  36.12 49.859 37.2 52.261 ;
     RECT  24.936 49.861 26.256 51.733 ;
     RECT  35.112 50.051 36.096 52.357 ;
     RECT  81.384 50.051 82.608 50.675 ;
     RECT  65.208 50.101 66.336 50.339 ;
     RECT  58.056 50.147 59.1 52.165 ;
     RECT  70.968 50.195 72.48 52.789 ;
     RECT  64.812 50.339 66.336 55.237 ;
     RECT  19.944 50.629 21.3 50.677 ;
     RECT  2.712 50.677 3.696 50.917 ;
     RECT  3.72 50.677 5.1 51.541 ;
     RECT  27.624 50.725 29.088 50.867 ;
     RECT  62.424 50.821 63.744 50.917 ;
     RECT  27.528 50.867 29.088 51.829 ;
     RECT  6.312 50.917 7.632 51.395 ;
     RECT  62.424 50.917 63.648 51.203 ;
     RECT  62.424 51.203 63.84 51.347 ;
     RECT  67.608 51.347 68.688 52.403 ;
     RECT  14.808 51.395 15.9 56.245 ;
     RECT  38.28 51.397 39.456 55.381 ;
     RECT  72.912 51.397 74.304 52.499 ;
     RECT  74.328 51.397 75.3 51.637 ;
     RECT  3.72 51.541 4.848 52.259 ;
     RECT  24.936 51.733 25.968 51.923 ;
     RECT  9.096 51.781 10.08 51.877 ;
     RECT  27.72 51.829 29.088 51.923 ;
     RECT  83.712 52.165 84.72 52.981 ;
     RECT  84.744 52.165 85.776 58.021 ;
     RECT  43.212 52.211 44.304 59.749 ;
     RECT  74.328 52.211 75.3 52.499 ;
     RECT  2.904 52.259 4.848 53.027 ;
     RECT  17.304 52.261 18.6 52.357 ;
     RECT  54.168 52.261 55.248 53.075 ;
     RECT  67.512 52.403 68.688 53.411 ;
     RECT  30.312 52.453 31.344 52.595 ;
     RECT  72.912 52.499 73.752 53.557 ;
     RECT  30.264 52.595 31.344 52.691 ;
     RECT  81.012 52.693 82.032 56.677 ;
     RECT  48.612 52.787 49.584 54.707 ;
     RECT  71.448 52.789 72.48 53.027 ;
     RECT  2.712 53.027 4.848 53.029 ;
     RECT  55.272 53.027 56.4 56.483 ;
     RECT  71.448 53.027 72.6 53.795 ;
     RECT  2.712 53.029 3.984 54.565 ;
     RECT  54.012 53.075 55.248 54.085 ;
     RECT  67.512 53.411 68.736 54.613 ;
     RECT  21.612 53.557 22.8 53.843 ;
     RECT  22.824 53.557 24 53.843 ;
     RECT  83.712 53.603 84.72 58.067 ;
     RECT  71.304 53.795 72.6 54.899 ;
     RECT  63.336 53.941 64.5 55.043 ;
     RECT  51.312 54.085 52.704 54.755 ;
     RECT  54.012 54.085 55.152 55.525 ;
     RECT  89.208 54.131 90.672 58.117 ;
     RECT  59.412 54.467 61.056 55.573 ;
     RECT  2.808 54.565 3.984 56.339 ;
     RECT  67.608 54.613 68.736 54.949 ;
     RECT  78.456 54.661 79.68 56.195 ;
     RECT  79.704 54.661 80.7 56.195 ;
     RECT  48.612 54.707 49.872 58.117 ;
     RECT  51.312 54.755 53.04 55.765 ;
     RECT  70.968 54.899 72.6 55.669 ;
     RECT  62.808 55.043 64.5 56.389 ;
     RECT  86.412 55.045 87.84 57.875 ;
     RECT  13.512 55.093 14.688 57.445 ;
     RECT  58.056 55.139 59.1 55.331 ;
     RECT  65.016 55.237 66.096 57.107 ;
     RECT  73.752 55.237 75.12 57.059 ;
     RECT  8.904 55.283 9.936 55.907 ;
     RECT  27.96 55.285 29.4 56.483 ;
     RECT  57.96 55.331 59.1 56.483 ;
     RECT  38.376 55.381 39.456 55.715 ;
     RECT  59.412 55.573 60.528 56.533 ;
     RECT  70.968 55.669 72.24 57.059 ;
     RECT  38.184 55.715 39.456 55.811 ;
     RECT  51.912 55.765 53.04 56.389 ;
     RECT  38.088 55.811 39.456 56.003 ;
     RECT  8.28 55.907 9.936 57.013 ;
     RECT  29.712 56.005 30.912 60.373 ;
     RECT  78.456 56.195 78.552 56.773 ;
     RECT  80.592 56.195 80.7 57.541 ;
     RECT  24.744 56.341 25.968 58.117 ;
     RECT  63.24 56.389 64.5 56.579 ;
     RECT  54.936 56.483 56.4 57.635 ;
     RECT  57.576 56.483 59.1 56.725 ;
     RECT  62.76 56.579 64.5 58.021 ;
     RECT  57.576 56.725 58.992 58.645 ;
     RECT  67.704 56.771 68.736 60.421 ;
     RECT  59.88 56.867 60.96 58.499 ;
     RECT  81.528 56.867 82.608 59.315 ;
     RECT  14.808 57.059 15.9 58.117 ;
     RECT  70.968 57.059 72.6 58.549 ;
     RECT  65.016 57.107 66.336 57.299 ;
     RECT  64.812 57.299 66.336 58.069 ;
     RECT  8.568 57.347 9.936 58.883 ;
     RECT  36.12 57.443 37.296 60.949 ;
     RECT  54.12 57.635 56.4 58.549 ;
     RECT  86.412 57.875 86.568 58.021 ;
     RECT  38.088 57.973 39.408 61.523 ;
     RECT  63.096 58.021 64.5 58.117 ;
     RECT  83.712 58.067 84.912 60.421 ;
     RECT  64.812 58.069 65.856 58.645 ;
     RECT  48.612 58.117 49.584 59.507 ;
     RECT  89.208 58.117 90.624 59.221 ;
     RECT  52.488 58.163 53.7 60.373 ;
     RECT  59.88 58.499 61.008 59.701 ;
     RECT  54.12 58.549 55.344 60.035 ;
     RECT  55.368 58.549 56.4 60.035 ;
     RECT  70.968 58.549 72.384 59.221 ;
     RECT  41.064 58.645 42.288 58.883 ;
     RECT  57.576 58.645 58.944 58.837 ;
     RECT  91.812 58.645 93.168 59.843 ;
     RECT  93.192 58.691 94.2 59.843 ;
     RECT  57.72 58.837 58.944 58.979 ;
     RECT  57.624 58.979 58.944 60.707 ;
     RECT  24.312 59.219 25.968 60.277 ;
     RECT  27.012 59.221 28.32 59.797 ;
     RECT  28.344 59.221 29.4 59.891 ;
     RECT  70.968 59.221 72.096 59.749 ;
     RECT  16.212 59.315 17.616 59.555 ;
     RECT  48.612 59.507 49.872 64.789 ;
     RECT  16.212 59.555 18.6 60.373 ;
     RECT  60.024 59.701 61.008 60.035 ;
     RECT  8.112 59.747 8.28 60.709 ;
     RECT  90.024 59.747 91.5 60.853 ;
     RECT  27.192 59.797 28.32 59.891 ;
     RECT  27.192 59.891 29.4 60.277 ;
     RECT  54.12 60.035 56.4 60.661 ;
     RECT  60.024 60.035 61.2 60.421 ;
     RECT  24.504 60.277 25.968 60.995 ;
     RECT  27.192 60.277 28.56 60.947 ;
     RECT  16.344 60.373 18.6 60.661 ;
     RECT  60.216 60.421 61.2 61.523 ;
     RECT  83.832 60.421 84.912 61.525 ;
     RECT  68.424 60.467 69.648 63.299 ;
     RECT  16.344 60.661 17.808 60.757 ;
     RECT  21.864 60.661 23.136 60.899 ;
     RECT  54.12 60.661 56.256 60.949 ;
     RECT  57.576 60.707 58.944 63.013 ;
     RECT  8.112 60.709 9.168 61.477 ;
     RECT  16.344 60.757 17.76 61.141 ;
     RECT  90.216 60.853 91.5 62.293 ;
     RECT  5.412 60.901 6.48 61.861 ;
     RECT  6.504 60.901 7.68 62.101 ;
     RECT  27.192 60.947 29.28 61.045 ;
     RECT  54.696 60.949 56.256 60.997 ;
     RECT  24.408 60.995 25.968 61.189 ;
     RECT  55.224 60.997 56.256 61.621 ;
     RECT  43.212 61.043 44.304 62.149 ;
     RECT  46.056 61.043 47.088 62.533 ;
     RECT  80.448 61.043 80.592 62.485 ;
     RECT  27.192 61.045 28.176 61.571 ;
     RECT  28.2 61.045 29.28 61.571 ;
     RECT  16.776 61.141 17.76 61.475 ;
     RECT  24.408 61.189 25.632 61.667 ;
     RECT  30.312 61.235 31.344 61.763 ;
     RECT  16.776 61.475 18.6 61.813 ;
     RECT  60.072 61.523 61.2 61.907 ;
     RECT  55.272 61.621 56.256 64.067 ;
     RECT  24.312 61.667 25.632 67.573 ;
     RECT  64.812 61.715 65.808 62.725 ;
     RECT  17.112 61.813 18.6 62.773 ;
     RECT  60.024 61.907 61.2 62.003 ;
     RECT  59.88 62.003 61.2 62.437 ;
     RECT  36.12 62.099 37.2 63.493 ;
     RECT  6.504 62.101 7.488 65.027 ;
     RECT  8.232 62.387 9.696 65.029 ;
     RECT  59.88 62.437 61.056 62.867 ;
     RECT  79.272 62.485 80.592 63.203 ;
     RECT  76.68 62.581 78 63.349 ;
     RECT  83.712 62.723 84.912 63.107 ;
     RECT  52.44 62.771 53.568 62.819 ;
     RECT  17.112 62.773 18.192 64.067 ;
     RECT  52.104 62.819 53.568 63.059 ;
     RECT  59.736 62.867 61.056 64.163 ;
     RECT  51.432 63.059 53.568 63.781 ;
     RECT  83.712 63.107 85.056 64.499 ;
     RECT  78.456 63.203 80.592 63.781 ;
     RECT  38.088 63.205 39.504 63.253 ;
     RECT  38.328 63.253 39.504 64.309 ;
     RECT  89.496 63.347 90.576 70.931 ;
     RECT  76.92 63.349 78 63.827 ;
     RECT  81.48 63.349 82.56 63.635 ;
     RECT  21.612 63.589 22.8 64.357 ;
     RECT  22.824 63.589 23.808 65.651 ;
     RECT  81.432 63.635 82.56 65.075 ;
     RECT  51.432 63.781 52.464 64.115 ;
     RECT  52.488 63.781 53.568 64.069 ;
     RECT  78.456 63.781 79.728 64.211 ;
     RECT  86.616 63.781 87.744 63.827 ;
     RECT  86.412 63.827 87.744 64.885 ;
     RECT  29.712 63.925 31.008 64.357 ;
     RECT  17.112 64.067 18.6 64.981 ;
     RECT  54.984 64.067 56.256 64.979 ;
     RECT  51.432 64.115 52.608 65.027 ;
     RECT  59.736 64.163 61.2 64.451 ;
     RECT  78.456 64.211 79.872 65.701 ;
     RECT  59.736 64.451 61.68 64.741 ;
     RECT  72.912 64.499 74.352 65.509 ;
     RECT  60.216 64.741 61.68 66.085 ;
     RECT  86.616 64.885 87.744 65.027 ;
     RECT  48.612 64.979 49.872 66.469 ;
     RECT  54.312 64.979 56.256 65.125 ;
     RECT  17.208 64.981 18.6 65.509 ;
     RECT  6.36 65.027 7.8 70.021 ;
     RECT  38.328 65.027 39.504 65.075 ;
     RECT  51.312 65.027 52.608 70.069 ;
     RECT  86.616 65.027 88.176 65.509 ;
     RECT  8.232 65.029 9.264 66.853 ;
     RECT  81.24 65.075 82.56 66.467 ;
     RECT  11.976 65.125 13.2 65.507 ;
     RECT  54.312 65.125 56.016 65.173 ;
     RECT  54.312 65.173 55.584 66.037 ;
     RECT  36.168 65.411 37.2 65.747 ;
     RECT  17.448 65.509 18.6 66.179 ;
     RECT  87.096 65.509 88.176 65.987 ;
     RECT  21.612 65.603 22.8 65.651 ;
     RECT  35.112 65.603 36.096 66.613 ;
     RECT  57.96 65.603 59.1 67.285 ;
     RECT  23.472 65.651 23.808 66.805 ;
     RECT  78.696 65.701 79.872 67.093 ;
     RECT  36.168 65.747 37.5 67.765 ;
     RECT  17.208 66.179 18.6 66.515 ;
     RECT  68.52 66.229 69.552 66.515 ;
     RECT  81.192 66.467 82.56 68.341 ;
     RECT  68.52 66.515 69.648 68.629 ;
     RECT  60.216 66.563 61.68 68.293 ;
     RECT  62.112 66.661 63.264 67.283 ;
     RECT  63.288 66.661 64.5 67.283 ;
     RECT  72.912 66.707 74.352 67.667 ;
     RECT  16.212 66.755 16.584 67.717 ;
     RECT  76.92 67.093 78 68.099 ;
     RECT  43.32 67.283 44.688 68.435 ;
     RECT  62.112 67.283 64.5 68.341 ;
     RECT  58.056 67.285 59.1 69.829 ;
     RECT  46.056 67.667 47.088 68.099 ;
     RECT  72.912 67.667 74.4 69.157 ;
     RECT  83.832 67.813 85.344 67.859 ;
     RECT  78.696 67.859 79.872 68.675 ;
     RECT  83.832 67.859 85.488 68.435 ;
     RECT  46.056 68.099 47.232 70.069 ;
     RECT  67.512 68.099 68.496 68.675 ;
     RECT  76.44 68.099 78 68.197 ;
     RECT  76.44 68.197 77.568 69.059 ;
     RECT  62.112 68.341 63.792 68.389 ;
     RECT  62.112 68.389 63.216 70.163 ;
     RECT  43.212 68.435 44.688 72.565 ;
     RECT  83.832 68.435 85.536 69.251 ;
     RECT  68.664 68.629 69.648 70.645 ;
     RECT  67.512 68.675 68.64 72.995 ;
     RECT  78.456 68.675 79.872 70.307 ;
     RECT  8.568 68.723 9.696 70.019 ;
     RECT  60.216 68.723 61.632 70.309 ;
     RECT  11.352 68.917 12.768 69.011 ;
     RECT  22.296 68.917 23.472 69.107 ;
     RECT  36.168 68.963 37.5 71.173 ;
     RECT  11.256 69.011 12.768 70.019 ;
     RECT  76.44 69.059 78 69.157 ;
     RECT  22.296 69.107 23.808 70.789 ;
     RECT  73.368 69.157 74.4 70.595 ;
     RECT  76.872 69.157 78 70.021 ;
     RECT  83.832 69.251 85.728 69.253 ;
     RECT  84.408 69.253 85.728 69.493 ;
     RECT  84.504 69.493 85.728 74.627 ;
     RECT  63.384 69.539 64.5 70.979 ;
     RECT  71.352 69.731 72.6 70.933 ;
     RECT  8.232 70.019 9.696 74.675 ;
     RECT  11.256 70.019 13.008 71.125 ;
     RECT  46.104 70.069 47.232 71.555 ;
     RECT  16.212 70.163 16.584 70.357 ;
     RECT  62.112 70.163 63.36 70.979 ;
     RECT  41.016 70.213 42.288 71.219 ;
     RECT  78.456 70.307 80.064 70.645 ;
     RECT  16.212 70.357 17.616 71.125 ;
     RECT  6.36 70.451 7.68 71.315 ;
     RECT  59.976 70.547 61.152 71.797 ;
     RECT  29.088 70.595 29.4 71.173 ;
     RECT  73.368 70.595 74.448 76.019 ;
     RECT  78.696 70.645 80.064 71.315 ;
     RECT  76.872 70.691 78 72.709 ;
     RECT  24.312 70.739 25.632 71.797 ;
     RECT  57.72 70.739 59.1 71.171 ;
     RECT  22.296 70.789 23.376 71.219 ;
     RECT  87.144 70.885 88.128 71.123 ;
     RECT  89.496 70.931 91.392 71.221 ;
     RECT  62.112 70.979 62.376 71.461 ;
     RECT  70.584 70.979 71.664 72.037 ;
     RECT  13.704 71.027 14.784 71.123 ;
     RECT  13.512 71.123 14.784 71.987 ;
     RECT  11.256 71.125 12.768 71.221 ;
     RECT  27.012 71.173 28.272 72.037 ;
     RECT  28.296 71.173 29.4 72.755 ;
     RECT  36.456 71.173 37.5 71.651 ;
     RECT  21.612 71.219 23.376 71.797 ;
     RECT  40.512 71.219 42.288 71.221 ;
     RECT  11.256 71.221 12.672 73.235 ;
     RECT  40.512 71.221 41.952 72.419 ;
     RECT  90.024 71.221 91.392 72.325 ;
     RECT  6.36 71.315 7.8 73.813 ;
     RECT  49.752 71.411 50.736 74.723 ;
     RECT  38.232 71.507 38.424 72.133 ;
     RECT  46.056 71.555 47.232 72.755 ;
     RECT  36.12 71.651 37.5 75.685 ;
     RECT  21.612 71.797 22.752 72.995 ;
     RECT  24.312 71.797 25.296 72.995 ;
     RECT  13.512 71.987 15.12 72.467 ;
     RECT  51.312 71.987 52.608 74.629 ;
     RECT  38.232 72.133 39.552 72.275 ;
     RECT  20.04 72.227 21.168 72.899 ;
     RECT  38.232 72.275 40.2 72.901 ;
     RECT  40.512 72.419 42.288 73.477 ;
     RECT  13.512 72.467 15.216 72.709 ;
     RECT  90.024 72.467 91.392 73.477 ;
     RECT  68.664 72.707 69.648 72.995 ;
     RECT  14.136 72.709 15.216 74.005 ;
     RECT  27.912 72.755 29.4 72.995 ;
     RECT  29.712 72.755 31.104 74.581 ;
     RECT  20.04 72.899 21.3 74.485 ;
     RECT  70.584 72.899 71.616 73.091 ;
     RECT  38.952 72.901 40.2 74.965 ;
     RECT  57.048 72.901 58.368 73.381 ;
     RECT  24.312 72.995 25.632 75.829 ;
     RECT  29.04 72.995 29.4 74.053 ;
     RECT  69.696 73.091 69.744 74.101 ;
     RECT  70.212 73.091 71.616 79.237 ;
     RECT  11.256 73.235 12.768 73.571 ;
     RECT  41.064 73.477 42.288 75.301 ;
     RECT  11.256 73.571 13.2 74.293 ;
     RECT  76.488 73.619 77.472 74.629 ;
     RECT  57.048 73.763 58.032 75.781 ;
     RECT  6.36 73.813 7.68 75.875 ;
     RECT  14.232 74.005 15.216 74.581 ;
     RECT  11.352 74.293 13.2 74.629 ;
     RECT  43.656 74.579 44.688 75.011 ;
     RECT  30.072 74.581 31.104 75.157 ;
     RECT  84.504 74.627 85.776 75.733 ;
     RECT  11.352 74.629 12.768 74.675 ;
     RECT  11.256 74.675 12.768 76.115 ;
     RECT  49.752 74.723 50.784 75.925 ;
     RECT  81.24 74.723 82.56 74.915 ;
     RECT  76.536 74.867 78 76.213 ;
     RECT  54.84 74.915 56.4 75.059 ;
     RECT  81.144 74.915 82.56 77.557 ;
     RECT  20.04 74.963 21.072 78.707 ;
     RECT  43.656 75.011 44.736 77.603 ;
     RECT  54.744 75.059 56.4 76.069 ;
     RECT  38.232 75.107 39.456 77.365 ;
     RECT  87.72 75.253 88.8 76.357 ;
     RECT  36.312 75.685 37.5 78.469 ;
     RECT  84.744 75.733 85.776 75.875 ;
     RECT  29.832 75.779 31.008 75.875 ;
     RECT  24.312 75.829 25.536 76.213 ;
     RECT  5.412 75.875 5.832 76.837 ;
     RECT  7.584 75.875 7.68 76.453 ;
     RECT  29.832 75.875 31.104 78.709 ;
     RECT  57.624 75.875 58.608 77.555 ;
     RECT  84.504 75.875 85.776 76.933 ;
     RECT  49.752 75.925 50.736 76.067 ;
     RECT  73.368 76.019 73.464 76.309 ;
     RECT  49.752 76.067 50.784 78.323 ;
     RECT  11.256 76.115 13.008 77.461 ;
     RECT  73.416 76.309 73.464 77.365 ;
     RECT  87.24 76.403 88.368 77.701 ;
     RECT  5.544 76.837 5.832 77.125 ;
     RECT  8.232 76.885 9.648 77.555 ;
     RECT  22.2 76.885 23.424 77.749 ;
     RECT  68.088 76.885 69.12 77.027 ;
     RECT  83.712 76.979 84.864 79.765 ;
     RECT  68.088 77.027 69.744 77.941 ;
     RECT  38.232 77.365 39.36 77.843 ;
     RECT  11.256 77.461 12.72 77.941 ;
     RECT  57.384 77.555 58.608 78.661 ;
     RECT  76.92 77.555 77.904 81.971 ;
     RECT  81.288 77.557 82.56 78.899 ;
     RECT  43.56 77.603 44.736 79.045 ;
     RECT  24.312 77.699 25.344 78.709 ;
     RECT  87.24 77.701 88.224 78.613 ;
     RECT  22.2 77.749 23.376 78.373 ;
     RECT  13.848 77.843 14.976 78.659 ;
     RECT  38.232 77.843 38.328 78.661 ;
     RECT  11.256 77.941 12.576 81.011 ;
     RECT  68.376 77.941 69.744 78.661 ;
     RECT  74.088 78.133 75.3 81.877 ;
     RECT  49.368 78.323 50.784 78.373 ;
     RECT  22.2 78.373 23.328 78.661 ;
     RECT  49.368 78.373 50.64 81.397 ;
     RECT  27.912 78.613 29.28 79.235 ;
     RECT  40.512 78.613 41.76 80.341 ;
     RECT  13.848 78.659 15.168 78.707 ;
     RECT  57.384 78.661 58.464 79.765 ;
     RECT  68.376 78.661 69.648 79.235 ;
     RECT  13.608 78.707 15.168 79.909 ;
     RECT  20.04 78.707 21.3 79.717 ;
     RECT  29.832 78.709 30.816 79.717 ;
     RECT  52.248 78.755 53.424 78.995 ;
     RECT  81.144 78.899 82.56 81.637 ;
     RECT  10.32 78.947 10.5 80.341 ;
     RECT  87.72 78.947 88.8 81.059 ;
     RECT  52.248 78.995 53.472 79.043 ;
     RECT  68.136 79.235 69.648 81.731 ;
     RECT  7.68 79.283 7.8 80.293 ;
     RECT  70.212 79.379 71.664 80.629 ;
     RECT  13.608 79.909 14.832 81.445 ;
     RECT  46.056 80.341 47.568 83.605 ;
     RECT  92.904 80.341 94.2 81.251 ;
     RECT  29.832 80.387 30.816 81.349 ;
     RECT  20.04 80.435 21.072 83.029 ;
     RECT  22.776 80.579 23.808 82.691 ;
     RECT  57.384 80.627 58.368 82.739 ;
     RECT  70.212 80.629 71.28 81.491 ;
     RECT  63.192 80.773 64.5 82.597 ;
     RECT  43.752 80.819 44.736 81.059 ;
     RECT  9 80.965 10.32 81.539 ;
     RECT  11.256 81.011 12.624 84.325 ;
     RECT  43.212 81.059 44.736 81.925 ;
     RECT  88.704 81.059 88.8 81.349 ;
     RECT  3.624 81.107 4.656 84.611 ;
     RECT  64.812 81.347 65.808 83.173 ;
     RECT  90.12 81.395 91.392 81.539 ;
     RECT  13.656 81.445 14.832 86.627 ;
     RECT  70.212 81.491 71.568 82.691 ;
     RECT  21.612 81.539 22.752 82.645 ;
     RECT  89.352 81.539 91.392 82.357 ;
     RECT  62.112 81.731 63.12 83.557 ;
     RECT  36.12 81.875 37.5 83.317 ;
     RECT  43.212 81.925 44.256 82.021 ;
     RECT  76.92 81.971 78 82.501 ;
     RECT  60.648 82.067 61.68 82.835 ;
     RECT  49.368 82.211 50.496 82.691 ;
     RECT  16.392 82.259 17.472 83.749 ;
     RECT  89.352 82.357 90.576 82.499 ;
     RECT  76.968 82.501 78 83.029 ;
     RECT  78.504 82.547 79.824 83.605 ;
     RECT  63.192 82.597 64.368 82.789 ;
     RECT  22.296 82.691 23.808 85.381 ;
     RECT  49.368 82.691 50.64 83.749 ;
     RECT  70.212 82.691 71.664 83.029 ;
     RECT  57.384 82.739 59.1 83.605 ;
     RECT  60.216 82.835 61.68 83.075 ;
     RECT  70.584 83.029 71.664 83.891 ;
     RECT  38.328 83.077 39.648 84.179 ;
     RECT  19.224 83.219 20.592 84.947 ;
     RECT  27.012 83.267 27.672 84.325 ;
     RECT  63.144 83.267 64.368 84.323 ;
     RECT  83.712 83.411 84.816 86.917 ;
     RECT  46.584 83.605 47.568 85.523 ;
     RECT  57.96 83.605 59.1 84.419 ;
     RECT  78.504 83.605 79.632 84.949 ;
     RECT  49.368 83.749 50.592 84.179 ;
     RECT  64.812 83.843 66.144 85.381 ;
     RECT  70.584 83.891 71.808 84.227 ;
     RECT  38.328 84.179 39.84 84.947 ;
     RECT  49.368 84.179 50.64 87.877 ;
     RECT  70.344 84.227 71.808 86.051 ;
     RECT  62.856 84.323 64.368 84.851 ;
     RECT  8.232 84.325 9.36 86.581 ;
     RECT  27.96 84.325 29.4 85.573 ;
     RECT  30.36 84.419 31.344 87.589 ;
     RECT  57 84.419 59.1 85.429 ;
     RECT  86.568 84.419 86.904 85.381 ;
     RECT  3.48 84.611 4.656 88.213 ;
     RECT  68.568 84.611 69.648 85.667 ;
     RECT  74.088 84.899 75.072 87.541 ;
     RECT  76.248 84.899 77.328 89.029 ;
     RECT  51.312 84.901 52.416 85.667 ;
     RECT  52.44 84.901 53.568 85.667 ;
     RECT  19.224 84.947 21.12 85.477 ;
     RECT  38.232 84.947 39.84 85.523 ;
     RECT  78.552 84.949 79.632 85.093 ;
     RECT  54.792 85.091 56.4 86.053 ;
     RECT  24.504 85.187 25.632 86.819 ;
     RECT  22.296 85.381 23.616 85.523 ;
     RECT  86.664 85.381 86.904 85.813 ;
     RECT  41.928 85.427 42.9 86.581 ;
     RECT  57 85.429 58.176 86.195 ;
     RECT  19.608 85.477 21.12 85.717 ;
     RECT  21.912 85.523 23.616 86.533 ;
     RECT  38.232 85.523 40.032 86.005 ;
     RECT  46.008 85.523 47.568 86.099 ;
     RECT  67.512 85.523 68.544 85.667 ;
     RECT  81.012 85.523 81.984 85.619 ;
     RECT  28.056 85.573 29.4 86.675 ;
     RECT  27.012 85.619 28.032 86.675 ;
     RECT  52.896 85.667 53.568 86.485 ;
     RECT  67.512 85.667 69.648 86.197 ;
     RECT  19.944 85.717 21.12 86.581 ;
     RECT  60.216 85.765 61.632 89.461 ;
     RECT  87.192 85.813 88.56 86.579 ;
     RECT  38.76 86.005 40.032 86.723 ;
     RECT  55.368 86.053 56.4 89.461 ;
     RECT  46.008 86.099 47.664 86.821 ;
     RECT  57 86.195 58.656 86.533 ;
     RECT  67.512 86.197 68.928 88.115 ;
     RECT  79.32 86.531 80.352 86.675 ;
     RECT  57.192 86.533 58.656 87.541 ;
     RECT  8.232 86.581 9.264 87.253 ;
     RECT  13.512 86.627 14.832 89.413 ;
     RECT  27.012 86.675 29.4 86.773 ;
     RECT  79.32 86.675 80.4 88.451 ;
     RECT  38.232 86.723 40.032 87.541 ;
     RECT  27.012 86.773 27.984 88.357 ;
     RECT  28.008 86.773 29.4 88.213 ;
     RECT  17.064 86.819 18.48 87.347 ;
     RECT  24.504 86.819 25.968 88.309 ;
     RECT  46.488 86.821 47.664 87.109 ;
     RECT  19.608 86.867 20.64 88.069 ;
     RECT  46.488 87.109 47.52 87.253 ;
     RECT  8.28 87.253 9.264 88.115 ;
     RECT  36.12 87.299 37.5 89.029 ;
     RECT  18.24 87.347 18.48 88.741 ;
     RECT  6.312 87.349 7.8 87.923 ;
     RECT  88.56 87.443 88.8 88.501 ;
     RECT  38.232 87.541 39.696 88.115 ;
     RECT  41.496 87.587 42.9 89.507 ;
     RECT  54.12 87.587 55.152 88.741 ;
     RECT  64.812 87.827 66.144 88.979 ;
     RECT  11.256 87.875 12.48 89.507 ;
     RECT  49.416 87.877 50.64 88.885 ;
     RECT  6.216 87.923 7.8 88.885 ;
     RECT  43.656 87.923 44.736 87.971 ;
     RECT  43.212 87.971 44.736 91.907 ;
     RECT  8.28 88.115 9.36 88.787 ;
     RECT  19.896 88.115 21.3 90.083 ;
     RECT  39.888 88.115 40.08 89.461 ;
     RECT  46.056 88.115 47.328 89.171 ;
     RECT  67.512 88.115 69.648 88.309 ;
     RECT  68.424 88.309 69.648 90.229 ;
     RECT  2.712 88.403 3.792 89.555 ;
     RECT  22.728 88.403 24 90.323 ;
     RECT  78.6 88.451 80.4 89.413 ;
     RECT  56.808 88.691 57.936 88.787 ;
     RECT  81.012 88.693 81.984 89.747 ;
     RECT  71.904 88.739 71.952 88.979 ;
     RECT  8.232 88.787 9.36 88.979 ;
     RECT  56.712 88.787 57.936 91.477 ;
     RECT  57.96 88.787 59.1 91.429 ;
     RECT  63.096 88.789 64.368 89.269 ;
     RECT  6.408 88.885 7.8 89.749 ;
     RECT  49.416 88.885 50.544 88.979 ;
     RECT  49.368 88.979 50.544 89.315 ;
     RECT  64.812 88.979 66.384 89.461 ;
     RECT  71.904 88.979 72.288 90.037 ;
     RECT  36.12 89.029 37.104 89.365 ;
     RECT  49.368 89.315 50.736 91.189 ;
     RECT  62.472 89.315 63.84 90.083 ;
     RECT  79.224 89.413 80.4 89.507 ;
     RECT  60.216 89.461 61.536 90.131 ;
     RECT  64.92 89.461 66.384 89.989 ;
     RECT  11.256 89.507 12.72 91.141 ;
     RECT  42.192 89.507 42.9 90.037 ;
     RECT  79.224 89.507 80.7 91.043 ;
     RECT  16.392 89.509 17.664 90.275 ;
     RECT  5.412 89.699 6.384 89.939 ;
     RECT  81.012 89.747 82.56 91.189 ;
     RECT  6.648 89.749 7.8 90.563 ;
     RECT  5.412 89.939 6.624 90.563 ;
     RECT  64.968 89.989 66.384 91.379 ;
     RECT  70.212 90.037 71.232 91.619 ;
     RECT  53.568 90.083 53.7 90.565 ;
     RECT  54.12 90.083 55.152 91.141 ;
     RECT  60.12 90.131 61.536 91.187 ;
     RECT  16.392 90.275 17.952 91.717 ;
     RECT  36.12 90.275 37.104 90.707 ;
     RECT  67.512 90.275 68.784 90.659 ;
     RECT  86.412 90.275 86.52 91.573 ;
     RECT  22.344 90.323 24 90.469 ;
     RECT  22.344 90.469 23.76 91.859 ;
     RECT  51.312 90.565 52.464 91.811 ;
     RECT  52.488 90.565 53.7 91.333 ;
     RECT  36.12 90.707 37.5 93.539 ;
     RECT  69.648 90.899 69.9 92.293 ;
     RECT  78.984 91.043 80.7 92.245 ;
     RECT  54.12 91.141 55.104 91.379 ;
     RECT  60.12 91.187 61.632 91.381 ;
     RECT  49.56 91.189 50.736 91.525 ;
     RECT  81.528 91.189 82.56 92.003 ;
     RECT  14.664 91.283 15.9 91.811 ;
     RECT  52.488 91.333 53.568 91.811 ;
     RECT  54.012 91.379 55.104 93.013 ;
     RECT  64.92 91.379 66.384 92.291 ;
     RECT  60.168 91.381 61.632 92.245 ;
     RECT  24.84 91.571 26.016 92.915 ;
     RECT  84.456 91.571 85.44 92.963 ;
     RECT  86.568 91.573 88.08 92.195 ;
     RECT  16.536 91.717 17.952 92.387 ;
     RECT  51.312 91.811 51.912 92.917 ;
     RECT  22.248 91.859 23.76 92.195 ;
     RECT  27.144 91.907 28.416 93.253 ;
     RECT  43.212 91.907 43.512 92.677 ;
     RECT  29.712 91.955 30.816 93.779 ;
     RECT  56.712 92.003 57.936 93.349 ;
     RECT  81.528 92.003 82.848 92.101 ;
     RECT  81.816 92.101 82.848 93.251 ;
     RECT  73.368 92.195 74.4 92.963 ;
     RECT  67.512 92.293 68.928 92.963 ;
     RECT  78.984 92.435 80.352 94.643 ;
     RECT  43.32 92.677 43.512 92.917 ;
     RECT  72.912 92.963 74.4 94.021 ;
     RECT  84.456 92.963 86.1 93.061 ;
     RECT  60.168 93.011 61.632 94.115 ;
     RECT  38.232 93.013 39.312 93.107 ;
     RECT  84.936 93.061 86.1 94.691 ;
     RECT  37.944 93.107 39.312 93.539 ;
     RECT  46.008 93.107 46.152 94.597 ;
     RECT  27.384 93.253 28.416 93.539 ;
     RECT  83.712 93.299 84.912 94.691 ;
     RECT  27.384 93.539 29.4 94.549 ;
     RECT  37.812 93.539 39.312 93.779 ;
     RECT  49.56 93.539 51 94.403 ;
     RECT  29.712 93.779 31.536 93.973 ;
     RECT  30.552 93.973 31.536 94.981 ;
     RECT  72.912 94.021 74.016 94.981 ;
     RECT  62.112 94.067 63.6 94.595 ;
     RECT  61.008 94.115 61.632 94.549 ;
     RECT  27.912 94.549 29.4 94.691 ;
     RECT  15.576 95.063 15.72 96.325 ;
     RECT  29.664 95.063 30.096 96.325 ;
     RECT  53.856 95.063 54 96.325 ;
  END
END qkd_seq_xs_s
END LIBRARY
